VERSION 5.8 ;
BUSBITCHARS "[]" ;
DIVIDERCHAR "/" ;
UNITS
    DATABASE MICRONS 1000 ;
END UNITS

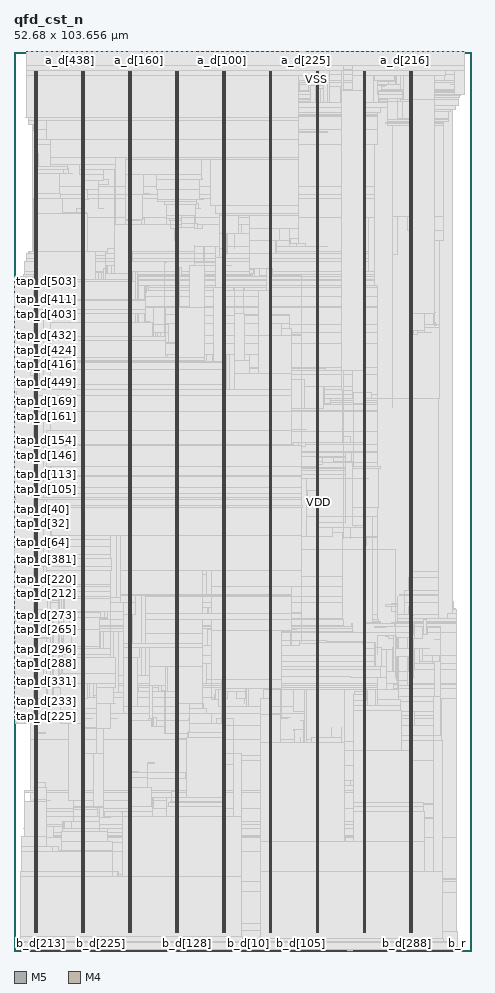
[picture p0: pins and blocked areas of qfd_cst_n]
MACRO qfd_cst_n
  FOREIGN qfd_cst_n 0 0 ;
  CLASS BLOCK ;
  SIZE 52.68 BY 103.656 ;
  PIN a_d[0]
    DIRECTION OUTPUT ;
    USE SIGNAL ;
    PORT
      LAYER M5 ;
        RECT  20.496 103.572 20.52 103.656 ;
    END
  END a_d[0]
  PIN a_d[100]
    DIRECTION OUTPUT ;
    USE SIGNAL ;
    PORT
      LAYER M5 ;
        RECT  23.952 103.572 23.976 103.656 ;
    END
  END a_d[100]
  PIN a_d[101]
    DIRECTION OUTPUT ;
    USE SIGNAL ;
    PORT
      LAYER M5 ;
        RECT  24.048 103.572 24.072 103.656 ;
    END
  END a_d[101]
  PIN a_d[102]
    DIRECTION OUTPUT ;
    USE SIGNAL ;
    PORT
      LAYER M5 ;
        RECT  24.144 103.572 24.168 103.656 ;
    END
  END a_d[102]
  PIN a_d[103]
    DIRECTION OUTPUT ;
    USE SIGNAL ;
    PORT
      LAYER M5 ;
        RECT  24.24 103.572 24.264 103.656 ;
    END
  END a_d[103]
  PIN a_d[104]
    DIRECTION OUTPUT ;
    USE SIGNAL ;
    PORT
      LAYER M5 ;
        RECT  24.336 103.572 24.36 103.656 ;
    END
  END a_d[104]
  PIN a_d[105]
    DIRECTION OUTPUT ;
    USE SIGNAL ;
    PORT
      LAYER M5 ;
        RECT  24.432 103.572 24.456 103.656 ;
    END
  END a_d[105]
  PIN a_d[106]
    DIRECTION OUTPUT ;
    USE SIGNAL ;
    PORT
      LAYER M5 ;
        RECT  24.528 103.572 24.552 103.656 ;
    END
  END a_d[106]
  PIN a_d[107]
    DIRECTION OUTPUT ;
    USE SIGNAL ;
    PORT
      LAYER M5 ;
        RECT  24.624 103.572 24.648 103.656 ;
    END
  END a_d[107]
  PIN a_d[108]
    DIRECTION OUTPUT ;
    USE SIGNAL ;
    PORT
      LAYER M5 ;
        RECT  24.72 103.572 24.744 103.656 ;
    END
  END a_d[108]
  PIN a_d[109]
    DIRECTION OUTPUT ;
    USE SIGNAL ;
    PORT
      LAYER M5 ;
        RECT  24.816 103.572 24.84 103.656 ;
    END
  END a_d[109]
  PIN a_d[10]
    DIRECTION OUTPUT ;
    USE SIGNAL ;
    PORT
      LAYER M5 ;
        RECT  21.456 103.572 21.48 103.656 ;
    END
  END a_d[10]
  PIN a_d[110]
    DIRECTION OUTPUT ;
    USE SIGNAL ;
    PORT
      LAYER M5 ;
        RECT  24.912 103.572 24.936 103.656 ;
    END
  END a_d[110]
  PIN a_d[111]
    DIRECTION OUTPUT ;
    USE SIGNAL ;
    PORT
      LAYER M5 ;
        RECT  25.008 103.572 25.032 103.656 ;
    END
  END a_d[111]
  PIN a_d[112]
    DIRECTION OUTPUT ;
    USE SIGNAL ;
    PORT
      LAYER M5 ;
        RECT  25.104 103.572 25.128 103.656 ;
    END
  END a_d[112]
  PIN a_d[113]
    DIRECTION OUTPUT ;
    USE SIGNAL ;
    PORT
      LAYER M5 ;
        RECT  25.2 103.572 25.224 103.656 ;
    END
  END a_d[113]
  PIN a_d[114]
    DIRECTION OUTPUT ;
    USE SIGNAL ;
    PORT
      LAYER M5 ;
        RECT  25.296 103.572 25.32 103.656 ;
    END
  END a_d[114]
  PIN a_d[115]
    DIRECTION OUTPUT ;
    USE SIGNAL ;
    PORT
      LAYER M5 ;
        RECT  25.392 103.572 25.416 103.656 ;
    END
  END a_d[115]
  PIN a_d[116]
    DIRECTION OUTPUT ;
    USE SIGNAL ;
    PORT
      LAYER M5 ;
        RECT  25.488 103.572 25.512 103.656 ;
    END
  END a_d[116]
  PIN a_d[117]
    DIRECTION OUTPUT ;
    USE SIGNAL ;
    PORT
      LAYER M5 ;
        RECT  25.584 103.572 25.608 103.656 ;
    END
  END a_d[117]
  PIN a_d[118]
    DIRECTION OUTPUT ;
    USE SIGNAL ;
    PORT
      LAYER M5 ;
        RECT  25.68 103.572 25.704 103.656 ;
    END
  END a_d[118]
  PIN a_d[119]
    DIRECTION OUTPUT ;
    USE SIGNAL ;
    PORT
      LAYER M5 ;
        RECT  25.776 103.572 25.8 103.656 ;
    END
  END a_d[119]
  PIN a_d[11]
    DIRECTION OUTPUT ;
    USE SIGNAL ;
    PORT
      LAYER M5 ;
        RECT  21.552 103.572 21.576 103.656 ;
    END
  END a_d[11]
  PIN a_d[120]
    DIRECTION OUTPUT ;
    USE SIGNAL ;
    PORT
      LAYER M5 ;
        RECT  25.872 103.572 25.896 103.656 ;
    END
  END a_d[120]
  PIN a_d[121]
    DIRECTION OUTPUT ;
    USE SIGNAL ;
    PORT
      LAYER M5 ;
        RECT  25.968 103.572 25.992 103.656 ;
    END
  END a_d[121]
  PIN a_d[122]
    DIRECTION OUTPUT ;
    USE SIGNAL ;
    PORT
      LAYER M5 ;
        RECT  26.064 103.572 26.088 103.656 ;
    END
  END a_d[122]
  PIN a_d[123]
    DIRECTION OUTPUT ;
    USE SIGNAL ;
    PORT
      LAYER M5 ;
        RECT  26.16 103.572 26.184 103.656 ;
    END
  END a_d[123]
  PIN a_d[124]
    DIRECTION OUTPUT ;
    USE SIGNAL ;
    PORT
      LAYER M5 ;
        RECT  26.256 103.572 26.28 103.656 ;
    END
  END a_d[124]
  PIN a_d[125]
    DIRECTION OUTPUT ;
    USE SIGNAL ;
    PORT
      LAYER M5 ;
        RECT  26.352 103.572 26.376 103.656 ;
    END
  END a_d[125]
  PIN a_d[126]
    DIRECTION OUTPUT ;
    USE SIGNAL ;
    PORT
      LAYER M5 ;
        RECT  26.448 103.572 26.472 103.656 ;
    END
  END a_d[126]
  PIN a_d[127]
    DIRECTION OUTPUT ;
    USE SIGNAL ;
    PORT
      LAYER M5 ;
        RECT  26.544 103.572 26.568 103.656 ;
    END
  END a_d[127]
  PIN a_d[128]
    DIRECTION OUTPUT ;
    USE SIGNAL ;
    PORT
      LAYER M5 ;
        RECT  17.424 103.572 17.448 103.656 ;
    END
  END a_d[128]
  PIN a_d[129]
    DIRECTION OUTPUT ;
    USE SIGNAL ;
    PORT
      LAYER M5 ;
        RECT  17.52 103.572 17.544 103.656 ;
    END
  END a_d[129]
  PIN a_d[12]
    DIRECTION OUTPUT ;
    USE SIGNAL ;
    PORT
      LAYER M5 ;
        RECT  21.648 103.572 21.672 103.656 ;
    END
  END a_d[12]
  PIN a_d[130]
    DIRECTION OUTPUT ;
    USE SIGNAL ;
    PORT
      LAYER M5 ;
        RECT  17.616 103.572 17.64 103.656 ;
    END
  END a_d[130]
  PIN a_d[131]
    DIRECTION OUTPUT ;
    USE SIGNAL ;
    PORT
      LAYER M5 ;
        RECT  17.712 103.572 17.736 103.656 ;
    END
  END a_d[131]
  PIN a_d[132]
    DIRECTION OUTPUT ;
    USE SIGNAL ;
    PORT
      LAYER M5 ;
        RECT  17.808 103.572 17.832 103.656 ;
    END
  END a_d[132]
  PIN a_d[133]
    DIRECTION OUTPUT ;
    USE SIGNAL ;
    PORT
      LAYER M5 ;
        RECT  17.904 103.572 17.928 103.656 ;
    END
  END a_d[133]
  PIN a_d[134]
    DIRECTION OUTPUT ;
    USE SIGNAL ;
    PORT
      LAYER M5 ;
        RECT  18 103.572 18.024 103.656 ;
    END
  END a_d[134]
  PIN a_d[135]
    DIRECTION OUTPUT ;
    USE SIGNAL ;
    PORT
      LAYER M5 ;
        RECT  18.096 103.572 18.12 103.656 ;
    END
  END a_d[135]
  PIN a_d[136]
    DIRECTION OUTPUT ;
    USE SIGNAL ;
    PORT
      LAYER M5 ;
        RECT  18.192 103.572 18.216 103.656 ;
    END
  END a_d[136]
  PIN a_d[137]
    DIRECTION OUTPUT ;
    USE SIGNAL ;
    PORT
      LAYER M5 ;
        RECT  18.288 103.572 18.312 103.656 ;
    END
  END a_d[137]
  PIN a_d[138]
    DIRECTION OUTPUT ;
    USE SIGNAL ;
    PORT
      LAYER M5 ;
        RECT  18.384 103.572 18.408 103.656 ;
    END
  END a_d[138]
  PIN a_d[139]
    DIRECTION OUTPUT ;
    USE SIGNAL ;
    PORT
      LAYER M5 ;
        RECT  18.48 103.572 18.504 103.656 ;
    END
  END a_d[139]
  PIN a_d[13]
    DIRECTION OUTPUT ;
    USE SIGNAL ;
    PORT
      LAYER M5 ;
        RECT  21.744 103.572 21.768 103.656 ;
    END
  END a_d[13]
  PIN a_d[140]
    DIRECTION OUTPUT ;
    USE SIGNAL ;
    PORT
      LAYER M5 ;
        RECT  18.576 103.572 18.6 103.656 ;
    END
  END a_d[140]
  PIN a_d[141]
    DIRECTION OUTPUT ;
    USE SIGNAL ;
    PORT
      LAYER M5 ;
        RECT  18.672 103.572 18.696 103.656 ;
    END
  END a_d[141]
  PIN a_d[142]
    DIRECTION OUTPUT ;
    USE SIGNAL ;
    PORT
      LAYER M5 ;
        RECT  18.768 103.572 18.792 103.656 ;
    END
  END a_d[142]
  PIN a_d[143]
    DIRECTION OUTPUT ;
    USE SIGNAL ;
    PORT
      LAYER M5 ;
        RECT  18.864 103.572 18.888 103.656 ;
    END
  END a_d[143]
  PIN a_d[144]
    DIRECTION OUTPUT ;
    USE SIGNAL ;
    PORT
      LAYER M5 ;
        RECT  18.96 103.572 18.984 103.656 ;
    END
  END a_d[144]
  PIN a_d[145]
    DIRECTION OUTPUT ;
    USE SIGNAL ;
    PORT
      LAYER M5 ;
        RECT  19.056 103.572 19.08 103.656 ;
    END
  END a_d[145]
  PIN a_d[146]
    DIRECTION OUTPUT ;
    USE SIGNAL ;
    PORT
      LAYER M5 ;
        RECT  19.152 103.572 19.176 103.656 ;
    END
  END a_d[146]
  PIN a_d[147]
    DIRECTION OUTPUT ;
    USE SIGNAL ;
    PORT
      LAYER M5 ;
        RECT  19.248 103.572 19.272 103.656 ;
    END
  END a_d[147]
  PIN a_d[148]
    DIRECTION OUTPUT ;
    USE SIGNAL ;
    PORT
      LAYER M5 ;
        RECT  19.344 103.572 19.368 103.656 ;
    END
  END a_d[148]
  PIN a_d[149]
    DIRECTION OUTPUT ;
    USE SIGNAL ;
    PORT
      LAYER M5 ;
        RECT  19.44 103.572 19.464 103.656 ;
    END
  END a_d[149]
  PIN a_d[14]
    DIRECTION OUTPUT ;
    USE SIGNAL ;
    PORT
      LAYER M5 ;
        RECT  21.84 103.572 21.864 103.656 ;
    END
  END a_d[14]
  PIN a_d[150]
    DIRECTION OUTPUT ;
    USE SIGNAL ;
    PORT
      LAYER M5 ;
        RECT  19.536 103.572 19.56 103.656 ;
    END
  END a_d[150]
  PIN a_d[151]
    DIRECTION OUTPUT ;
    USE SIGNAL ;
    PORT
      LAYER M5 ;
        RECT  19.632 103.572 19.656 103.656 ;
    END
  END a_d[151]
  PIN a_d[152]
    DIRECTION OUTPUT ;
    USE SIGNAL ;
    PORT
      LAYER M5 ;
        RECT  19.728 103.572 19.752 103.656 ;
    END
  END a_d[152]
  PIN a_d[153]
    DIRECTION OUTPUT ;
    USE SIGNAL ;
    PORT
      LAYER M5 ;
        RECT  19.824 103.572 19.848 103.656 ;
    END
  END a_d[153]
  PIN a_d[154]
    DIRECTION OUTPUT ;
    USE SIGNAL ;
    PORT
      LAYER M5 ;
        RECT  19.92 103.572 19.944 103.656 ;
    END
  END a_d[154]
  PIN a_d[155]
    DIRECTION OUTPUT ;
    USE SIGNAL ;
    PORT
      LAYER M5 ;
        RECT  20.016 103.572 20.04 103.656 ;
    END
  END a_d[155]
  PIN a_d[156]
    DIRECTION OUTPUT ;
    USE SIGNAL ;
    PORT
      LAYER M5 ;
        RECT  20.112 103.572 20.136 103.656 ;
    END
  END a_d[156]
  PIN a_d[157]
    DIRECTION OUTPUT ;
    USE SIGNAL ;
    PORT
      LAYER M5 ;
        RECT  20.208 103.572 20.232 103.656 ;
    END
  END a_d[157]
  PIN a_d[158]
    DIRECTION OUTPUT ;
    USE SIGNAL ;
    PORT
      LAYER M5 ;
        RECT  20.304 103.572 20.328 103.656 ;
    END
  END a_d[158]
  PIN a_d[159]
    DIRECTION OUTPUT ;
    USE SIGNAL ;
    PORT
      LAYER M5 ;
        RECT  20.4 103.572 20.424 103.656 ;
    END
  END a_d[159]
  PIN a_d[15]
    DIRECTION OUTPUT ;
    USE SIGNAL ;
    PORT
      LAYER M5 ;
        RECT  21.936 103.572 21.96 103.656 ;
    END
  END a_d[15]
  PIN a_d[160]
    DIRECTION OUTPUT ;
    USE SIGNAL ;
    PORT
      LAYER M5 ;
        RECT  14.352 103.572 14.376 103.656 ;
    END
  END a_d[160]
  PIN a_d[161]
    DIRECTION OUTPUT ;
    USE SIGNAL ;
    PORT
      LAYER M5 ;
        RECT  14.448 103.572 14.472 103.656 ;
    END
  END a_d[161]
  PIN a_d[162]
    DIRECTION OUTPUT ;
    USE SIGNAL ;
    PORT
      LAYER M5 ;
        RECT  14.544 103.572 14.568 103.656 ;
    END
  END a_d[162]
  PIN a_d[163]
    DIRECTION OUTPUT ;
    USE SIGNAL ;
    PORT
      LAYER M5 ;
        RECT  14.64 103.572 14.664 103.656 ;
    END
  END a_d[163]
  PIN a_d[164]
    DIRECTION OUTPUT ;
    USE SIGNAL ;
    PORT
      LAYER M5 ;
        RECT  14.736 103.572 14.76 103.656 ;
    END
  END a_d[164]
  PIN a_d[165]
    DIRECTION OUTPUT ;
    USE SIGNAL ;
    PORT
      LAYER M5 ;
        RECT  14.832 103.572 14.856 103.656 ;
    END
  END a_d[165]
  PIN a_d[166]
    DIRECTION OUTPUT ;
    USE SIGNAL ;
    PORT
      LAYER M5 ;
        RECT  14.928 103.572 14.952 103.656 ;
    END
  END a_d[166]
  PIN a_d[167]
    DIRECTION OUTPUT ;
    USE SIGNAL ;
    PORT
      LAYER M5 ;
        RECT  15.024 103.572 15.048 103.656 ;
    END
  END a_d[167]
  PIN a_d[168]
    DIRECTION OUTPUT ;
    USE SIGNAL ;
    PORT
      LAYER M5 ;
        RECT  15.12 103.572 15.144 103.656 ;
    END
  END a_d[168]
  PIN a_d[169]
    DIRECTION OUTPUT ;
    USE SIGNAL ;
    PORT
      LAYER M5 ;
        RECT  15.216 103.572 15.24 103.656 ;
    END
  END a_d[169]
  PIN a_d[16]
    DIRECTION OUTPUT ;
    USE SIGNAL ;
    PORT
      LAYER M5 ;
        RECT  22.032 103.572 22.056 103.656 ;
    END
  END a_d[16]
  PIN a_d[170]
    DIRECTION OUTPUT ;
    USE SIGNAL ;
    PORT
      LAYER M5 ;
        RECT  15.312 103.572 15.336 103.656 ;
    END
  END a_d[170]
  PIN a_d[171]
    DIRECTION OUTPUT ;
    USE SIGNAL ;
    PORT
      LAYER M5 ;
        RECT  15.408 103.572 15.432 103.656 ;
    END
  END a_d[171]
  PIN a_d[172]
    DIRECTION OUTPUT ;
    USE SIGNAL ;
    PORT
      LAYER M5 ;
        RECT  15.504 103.572 15.528 103.656 ;
    END
  END a_d[172]
  PIN a_d[173]
    DIRECTION OUTPUT ;
    USE SIGNAL ;
    PORT
      LAYER M5 ;
        RECT  15.6 103.572 15.624 103.656 ;
    END
  END a_d[173]
  PIN a_d[174]
    DIRECTION OUTPUT ;
    USE SIGNAL ;
    PORT
      LAYER M5 ;
        RECT  15.696 103.572 15.72 103.656 ;
    END
  END a_d[174]
  PIN a_d[175]
    DIRECTION OUTPUT ;
    USE SIGNAL ;
    PORT
      LAYER M5 ;
        RECT  15.792 103.572 15.816 103.656 ;
    END
  END a_d[175]
  PIN a_d[176]
    DIRECTION OUTPUT ;
    USE SIGNAL ;
    PORT
      LAYER M5 ;
        RECT  15.888 103.572 15.912 103.656 ;
    END
  END a_d[176]
  PIN a_d[177]
    DIRECTION OUTPUT ;
    USE SIGNAL ;
    PORT
      LAYER M5 ;
        RECT  15.984 103.572 16.008 103.656 ;
    END
  END a_d[177]
  PIN a_d[178]
    DIRECTION OUTPUT ;
    USE SIGNAL ;
    PORT
      LAYER M5 ;
        RECT  16.08 103.572 16.104 103.656 ;
    END
  END a_d[178]
  PIN a_d[179]
    DIRECTION OUTPUT ;
    USE SIGNAL ;
    PORT
      LAYER M5 ;
        RECT  16.176 103.572 16.2 103.656 ;
    END
  END a_d[179]
  PIN a_d[17]
    DIRECTION OUTPUT ;
    USE SIGNAL ;
    PORT
      LAYER M5 ;
        RECT  22.128 103.572 22.152 103.656 ;
    END
  END a_d[17]
  PIN a_d[180]
    DIRECTION OUTPUT ;
    USE SIGNAL ;
    PORT
      LAYER M5 ;
        RECT  16.272 103.572 16.296 103.656 ;
    END
  END a_d[180]
  PIN a_d[181]
    DIRECTION OUTPUT ;
    USE SIGNAL ;
    PORT
      LAYER M5 ;
        RECT  16.368 103.572 16.392 103.656 ;
    END
  END a_d[181]
  PIN a_d[182]
    DIRECTION OUTPUT ;
    USE SIGNAL ;
    PORT
      LAYER M5 ;
        RECT  16.464 103.572 16.488 103.656 ;
    END
  END a_d[182]
  PIN a_d[183]
    DIRECTION OUTPUT ;
    USE SIGNAL ;
    PORT
      LAYER M5 ;
        RECT  16.56 103.572 16.584 103.656 ;
    END
  END a_d[183]
  PIN a_d[184]
    DIRECTION OUTPUT ;
    USE SIGNAL ;
    PORT
      LAYER M5 ;
        RECT  16.656 103.572 16.68 103.656 ;
    END
  END a_d[184]
  PIN a_d[185]
    DIRECTION OUTPUT ;
    USE SIGNAL ;
    PORT
      LAYER M5 ;
        RECT  16.752 103.572 16.776 103.656 ;
    END
  END a_d[185]
  PIN a_d[186]
    DIRECTION OUTPUT ;
    USE SIGNAL ;
    PORT
      LAYER M5 ;
        RECT  16.848 103.572 16.872 103.656 ;
    END
  END a_d[186]
  PIN a_d[187]
    DIRECTION OUTPUT ;
    USE SIGNAL ;
    PORT
      LAYER M5 ;
        RECT  16.944 103.572 16.968 103.656 ;
    END
  END a_d[187]
  PIN a_d[188]
    DIRECTION OUTPUT ;
    USE SIGNAL ;
    PORT
      LAYER M5 ;
        RECT  17.04 103.572 17.064 103.656 ;
    END
  END a_d[188]
  PIN a_d[189]
    DIRECTION OUTPUT ;
    USE SIGNAL ;
    PORT
      LAYER M5 ;
        RECT  17.136 103.572 17.16 103.656 ;
    END
  END a_d[189]
  PIN a_d[18]
    DIRECTION OUTPUT ;
    USE SIGNAL ;
    PORT
      LAYER M5 ;
        RECT  22.224 103.572 22.248 103.656 ;
    END
  END a_d[18]
  PIN a_d[190]
    DIRECTION OUTPUT ;
    USE SIGNAL ;
    PORT
      LAYER M5 ;
        RECT  17.232 103.572 17.256 103.656 ;
    END
  END a_d[190]
  PIN a_d[191]
    DIRECTION OUTPUT ;
    USE SIGNAL ;
    PORT
      LAYER M5 ;
        RECT  17.328 103.572 17.352 103.656 ;
    END
  END a_d[191]
  PIN a_d[192]
    DIRECTION OUTPUT ;
    USE SIGNAL ;
    PORT
      LAYER M5 ;
        RECT  42.768 103.572 42.792 103.656 ;
    END
  END a_d[192]
  PIN a_d[193]
    DIRECTION OUTPUT ;
    USE SIGNAL ;
    PORT
      LAYER M5 ;
        RECT  42.864 103.572 42.888 103.656 ;
    END
  END a_d[193]
  PIN a_d[194]
    DIRECTION OUTPUT ;
    USE SIGNAL ;
    PORT
      LAYER M5 ;
        RECT  42.96 103.572 42.984 103.656 ;
    END
  END a_d[194]
  PIN a_d[195]
    DIRECTION OUTPUT ;
    USE SIGNAL ;
    PORT
      LAYER M5 ;
        RECT  43.056 103.572 43.08 103.656 ;
    END
  END a_d[195]
  PIN a_d[196]
    DIRECTION OUTPUT ;
    USE SIGNAL ;
    PORT
      LAYER M5 ;
        RECT  43.152 103.572 43.176 103.656 ;
    END
  END a_d[196]
  PIN a_d[197]
    DIRECTION OUTPUT ;
    USE SIGNAL ;
    PORT
      LAYER M5 ;
        RECT  43.248 103.572 43.272 103.656 ;
    END
  END a_d[197]
  PIN a_d[198]
    DIRECTION OUTPUT ;
    USE SIGNAL ;
    PORT
      LAYER M5 ;
        RECT  43.344 103.572 43.368 103.656 ;
    END
  END a_d[198]
  PIN a_d[199]
    DIRECTION OUTPUT ;
    USE SIGNAL ;
    PORT
      LAYER M5 ;
        RECT  43.44 103.572 43.464 103.656 ;
    END
  END a_d[199]
  PIN a_d[19]
    DIRECTION OUTPUT ;
    USE SIGNAL ;
    PORT
      LAYER M5 ;
        RECT  22.32 103.572 22.344 103.656 ;
    END
  END a_d[19]
  PIN a_d[1]
    DIRECTION OUTPUT ;
    USE SIGNAL ;
    PORT
      LAYER M5 ;
        RECT  20.592 103.572 20.616 103.656 ;
    END
  END a_d[1]
  PIN a_d[200]
    DIRECTION OUTPUT ;
    USE SIGNAL ;
    PORT
      LAYER M5 ;
        RECT  43.536 103.572 43.56 103.656 ;
    END
  END a_d[200]
  PIN a_d[201]
    DIRECTION OUTPUT ;
    USE SIGNAL ;
    PORT
      LAYER M5 ;
        RECT  43.632 103.572 43.656 103.656 ;
    END
  END a_d[201]
  PIN a_d[202]
    DIRECTION OUTPUT ;
    USE SIGNAL ;
    PORT
      LAYER M5 ;
        RECT  43.728 103.572 43.752 103.656 ;
    END
  END a_d[202]
  PIN a_d[203]
    DIRECTION OUTPUT ;
    USE SIGNAL ;
    PORT
      LAYER M5 ;
        RECT  43.824 103.572 43.848 103.656 ;
    END
  END a_d[203]
  PIN a_d[204]
    DIRECTION OUTPUT ;
    USE SIGNAL ;
    PORT
      LAYER M5 ;
        RECT  43.92 103.572 43.944 103.656 ;
    END
  END a_d[204]
  PIN a_d[205]
    DIRECTION OUTPUT ;
    USE SIGNAL ;
    PORT
      LAYER M5 ;
        RECT  44.016 103.572 44.04 103.656 ;
    END
  END a_d[205]
  PIN a_d[206]
    DIRECTION OUTPUT ;
    USE SIGNAL ;
    PORT
      LAYER M5 ;
        RECT  44.112 103.572 44.136 103.656 ;
    END
  END a_d[206]
  PIN a_d[207]
    DIRECTION OUTPUT ;
    USE SIGNAL ;
    PORT
      LAYER M5 ;
        RECT  44.208 103.572 44.232 103.656 ;
    END
  END a_d[207]
  PIN a_d[208]
    DIRECTION OUTPUT ;
    USE SIGNAL ;
    PORT
      LAYER M5 ;
        RECT  44.304 103.572 44.328 103.656 ;
    END
  END a_d[208]
  PIN a_d[209]
    DIRECTION OUTPUT ;
    USE SIGNAL ;
    PORT
      LAYER M5 ;
        RECT  44.4 103.572 44.424 103.656 ;
    END
  END a_d[209]
  PIN a_d[20]
    DIRECTION OUTPUT ;
    USE SIGNAL ;
    PORT
      LAYER M5 ;
        RECT  22.416 103.572 22.44 103.656 ;
    END
  END a_d[20]
  PIN a_d[210]
    DIRECTION OUTPUT ;
    USE SIGNAL ;
    PORT
      LAYER M5 ;
        RECT  44.496 103.572 44.52 103.656 ;
    END
  END a_d[210]
  PIN a_d[211]
    DIRECTION OUTPUT ;
    USE SIGNAL ;
    PORT
      LAYER M5 ;
        RECT  44.592 103.572 44.616 103.656 ;
    END
  END a_d[211]
  PIN a_d[212]
    DIRECTION OUTPUT ;
    USE SIGNAL ;
    PORT
      LAYER M5 ;
        RECT  44.688 103.572 44.712 103.656 ;
    END
  END a_d[212]
  PIN a_d[213]
    DIRECTION OUTPUT ;
    USE SIGNAL ;
    PORT
      LAYER M5 ;
        RECT  44.784 103.572 44.808 103.656 ;
    END
  END a_d[213]
  PIN a_d[214]
    DIRECTION OUTPUT ;
    USE SIGNAL ;
    PORT
      LAYER M5 ;
        RECT  44.88 103.572 44.904 103.656 ;
    END
  END a_d[214]
  PIN a_d[215]
    DIRECTION OUTPUT ;
    USE SIGNAL ;
    PORT
      LAYER M5 ;
        RECT  44.976 103.572 45 103.656 ;
    END
  END a_d[215]
  PIN a_d[216]
    DIRECTION OUTPUT ;
    USE SIGNAL ;
    PORT
      LAYER M5 ;
        RECT  45.072 103.572 45.096 103.656 ;
    END
  END a_d[216]
  PIN a_d[217]
    DIRECTION OUTPUT ;
    USE SIGNAL ;
    PORT
      LAYER M5 ;
        RECT  45.168 103.572 45.192 103.656 ;
    END
  END a_d[217]
  PIN a_d[218]
    DIRECTION OUTPUT ;
    USE SIGNAL ;
    PORT
      LAYER M5 ;
        RECT  45.264 103.572 45.288 103.656 ;
    END
  END a_d[218]
  PIN a_d[219]
    DIRECTION OUTPUT ;
    USE SIGNAL ;
    PORT
      LAYER M5 ;
        RECT  45.36 103.572 45.384 103.656 ;
    END
  END a_d[219]
  PIN a_d[21]
    DIRECTION OUTPUT ;
    USE SIGNAL ;
    PORT
      LAYER M5 ;
        RECT  22.512 103.572 22.536 103.656 ;
    END
  END a_d[21]
  PIN a_d[220]
    DIRECTION OUTPUT ;
    USE SIGNAL ;
    PORT
      LAYER M5 ;
        RECT  45.456 103.572 45.48 103.656 ;
    END
  END a_d[220]
  PIN a_d[221]
    DIRECTION OUTPUT ;
    USE SIGNAL ;
    PORT
      LAYER M5 ;
        RECT  45.552 103.572 45.576 103.656 ;
    END
  END a_d[221]
  PIN a_d[222]
    DIRECTION OUTPUT ;
    USE SIGNAL ;
    PORT
      LAYER M5 ;
        RECT  45.648 103.572 45.672 103.656 ;
    END
  END a_d[222]
  PIN a_d[223]
    DIRECTION OUTPUT ;
    USE SIGNAL ;
    PORT
      LAYER M5 ;
        RECT  45.744 103.572 45.768 103.656 ;
    END
  END a_d[223]
  PIN a_d[224]
    DIRECTION OUTPUT ;
    USE SIGNAL ;
    PORT
      LAYER M5 ;
        RECT  33.552 103.572 33.576 103.656 ;
    END
  END a_d[224]
  PIN a_d[225]
    DIRECTION OUTPUT ;
    USE SIGNAL ;
    PORT
      LAYER M5 ;
        RECT  33.648 103.572 33.672 103.656 ;
    END
  END a_d[225]
  PIN a_d[226]
    DIRECTION OUTPUT ;
    USE SIGNAL ;
    PORT
      LAYER M5 ;
        RECT  33.744 103.572 33.768 103.656 ;
    END
  END a_d[226]
  PIN a_d[227]
    DIRECTION OUTPUT ;
    USE SIGNAL ;
    PORT
      LAYER M5 ;
        RECT  33.84 103.572 33.864 103.656 ;
    END
  END a_d[227]
  PIN a_d[228]
    DIRECTION OUTPUT ;
    USE SIGNAL ;
    PORT
      LAYER M5 ;
        RECT  33.936 103.572 33.96 103.656 ;
    END
  END a_d[228]
  PIN a_d[229]
    DIRECTION OUTPUT ;
    USE SIGNAL ;
    PORT
      LAYER M5 ;
        RECT  34.032 103.572 34.056 103.656 ;
    END
  END a_d[229]
  PIN a_d[22]
    DIRECTION OUTPUT ;
    USE SIGNAL ;
    PORT
      LAYER M5 ;
        RECT  22.608 103.572 22.632 103.656 ;
    END
  END a_d[22]
  PIN a_d[230]
    DIRECTION OUTPUT ;
    USE SIGNAL ;
    PORT
      LAYER M5 ;
        RECT  34.128 103.572 34.152 103.656 ;
    END
  END a_d[230]
  PIN a_d[231]
    DIRECTION OUTPUT ;
    USE SIGNAL ;
    PORT
      LAYER M5 ;
        RECT  34.224 103.572 34.248 103.656 ;
    END
  END a_d[231]
  PIN a_d[232]
    DIRECTION OUTPUT ;
    USE SIGNAL ;
    PORT
      LAYER M5 ;
        RECT  34.32 103.572 34.344 103.656 ;
    END
  END a_d[232]
  PIN a_d[233]
    DIRECTION OUTPUT ;
    USE SIGNAL ;
    PORT
      LAYER M5 ;
        RECT  34.416 103.572 34.44 103.656 ;
    END
  END a_d[233]
  PIN a_d[234]
    DIRECTION OUTPUT ;
    USE SIGNAL ;
    PORT
      LAYER M5 ;
        RECT  34.512 103.572 34.536 103.656 ;
    END
  END a_d[234]
  PIN a_d[235]
    DIRECTION OUTPUT ;
    USE SIGNAL ;
    PORT
      LAYER M5 ;
        RECT  34.608 103.572 34.632 103.656 ;
    END
  END a_d[235]
  PIN a_d[236]
    DIRECTION OUTPUT ;
    USE SIGNAL ;
    PORT
      LAYER M5 ;
        RECT  34.704 103.572 34.728 103.656 ;
    END
  END a_d[236]
  PIN a_d[237]
    DIRECTION OUTPUT ;
    USE SIGNAL ;
    PORT
      LAYER M5 ;
        RECT  34.8 103.572 34.824 103.656 ;
    END
  END a_d[237]
  PIN a_d[238]
    DIRECTION OUTPUT ;
    USE SIGNAL ;
    PORT
      LAYER M5 ;
        RECT  34.896 103.572 34.92 103.656 ;
    END
  END a_d[238]
  PIN a_d[239]
    DIRECTION OUTPUT ;
    USE SIGNAL ;
    PORT
      LAYER M5 ;
        RECT  34.992 103.572 35.016 103.656 ;
    END
  END a_d[239]
  PIN a_d[23]
    DIRECTION OUTPUT ;
    USE SIGNAL ;
    PORT
      LAYER M5 ;
        RECT  22.704 103.572 22.728 103.656 ;
    END
  END a_d[23]
  PIN a_d[240]
    DIRECTION OUTPUT ;
    USE SIGNAL ;
    PORT
      LAYER M5 ;
        RECT  35.088 103.572 35.112 103.656 ;
    END
  END a_d[240]
  PIN a_d[241]
    DIRECTION OUTPUT ;
    USE SIGNAL ;
    PORT
      LAYER M5 ;
        RECT  35.184 103.572 35.208 103.656 ;
    END
  END a_d[241]
  PIN a_d[242]
    DIRECTION OUTPUT ;
    USE SIGNAL ;
    PORT
      LAYER M5 ;
        RECT  35.28 103.572 35.304 103.656 ;
    END
  END a_d[242]
  PIN a_d[243]
    DIRECTION OUTPUT ;
    USE SIGNAL ;
    PORT
      LAYER M5 ;
        RECT  35.376 103.572 35.4 103.656 ;
    END
  END a_d[243]
  PIN a_d[244]
    DIRECTION OUTPUT ;
    USE SIGNAL ;
    PORT
      LAYER M5 ;
        RECT  35.472 103.572 35.496 103.656 ;
    END
  END a_d[244]
  PIN a_d[245]
    DIRECTION OUTPUT ;
    USE SIGNAL ;
    PORT
      LAYER M5 ;
        RECT  35.568 103.572 35.592 103.656 ;
    END
  END a_d[245]
  PIN a_d[246]
    DIRECTION OUTPUT ;
    USE SIGNAL ;
    PORT
      LAYER M5 ;
        RECT  35.664 103.572 35.688 103.656 ;
    END
  END a_d[246]
  PIN a_d[247]
    DIRECTION OUTPUT ;
    USE SIGNAL ;
    PORT
      LAYER M5 ;
        RECT  35.76 103.572 35.784 103.656 ;
    END
  END a_d[247]
  PIN a_d[248]
    DIRECTION OUTPUT ;
    USE SIGNAL ;
    PORT
      LAYER M5 ;
        RECT  35.856 103.572 35.88 103.656 ;
    END
  END a_d[248]
  PIN a_d[249]
    DIRECTION OUTPUT ;
    USE SIGNAL ;
    PORT
      LAYER M5 ;
        RECT  35.952 103.572 35.976 103.656 ;
    END
  END a_d[249]
  PIN a_d[24]
    DIRECTION OUTPUT ;
    USE SIGNAL ;
    PORT
      LAYER M5 ;
        RECT  22.8 103.572 22.824 103.656 ;
    END
  END a_d[24]
  PIN a_d[250]
    DIRECTION OUTPUT ;
    USE SIGNAL ;
    PORT
      LAYER M5 ;
        RECT  36.048 103.572 36.072 103.656 ;
    END
  END a_d[250]
  PIN a_d[251]
    DIRECTION OUTPUT ;
    USE SIGNAL ;
    PORT
      LAYER M5 ;
        RECT  36.144 103.572 36.168 103.656 ;
    END
  END a_d[251]
  PIN a_d[252]
    DIRECTION OUTPUT ;
    USE SIGNAL ;
    PORT
      LAYER M5 ;
        RECT  36.24 103.572 36.264 103.656 ;
    END
  END a_d[252]
  PIN a_d[253]
    DIRECTION OUTPUT ;
    USE SIGNAL ;
    PORT
      LAYER M5 ;
        RECT  36.336 103.572 36.36 103.656 ;
    END
  END a_d[253]
  PIN a_d[254]
    DIRECTION OUTPUT ;
    USE SIGNAL ;
    PORT
      LAYER M5 ;
        RECT  36.432 103.572 36.456 103.656 ;
    END
  END a_d[254]
  PIN a_d[255]
    DIRECTION OUTPUT ;
    USE SIGNAL ;
    PORT
      LAYER M5 ;
        RECT  36.528 103.572 36.552 103.656 ;
    END
  END a_d[255]
  PIN a_d[256]
    DIRECTION OUTPUT ;
    USE SIGNAL ;
    PORT
      LAYER M5 ;
        RECT  36.624 103.572 36.648 103.656 ;
    END
  END a_d[256]
  PIN a_d[257]
    DIRECTION OUTPUT ;
    USE SIGNAL ;
    PORT
      LAYER M5 ;
        RECT  36.72 103.572 36.744 103.656 ;
    END
  END a_d[257]
  PIN a_d[258]
    DIRECTION OUTPUT ;
    USE SIGNAL ;
    PORT
      LAYER M5 ;
        RECT  36.816 103.572 36.84 103.656 ;
    END
  END a_d[258]
  PIN a_d[259]
    DIRECTION OUTPUT ;
    USE SIGNAL ;
    PORT
      LAYER M5 ;
        RECT  36.912 103.572 36.936 103.656 ;
    END
  END a_d[259]
  PIN a_d[25]
    DIRECTION OUTPUT ;
    USE SIGNAL ;
    PORT
      LAYER M5 ;
        RECT  22.896 103.572 22.92 103.656 ;
    END
  END a_d[25]
  PIN a_d[260]
    DIRECTION OUTPUT ;
    USE SIGNAL ;
    PORT
      LAYER M5 ;
        RECT  37.008 103.572 37.032 103.656 ;
    END
  END a_d[260]
  PIN a_d[261]
    DIRECTION OUTPUT ;
    USE SIGNAL ;
    PORT
      LAYER M5 ;
        RECT  37.104 103.572 37.128 103.656 ;
    END
  END a_d[261]
  PIN a_d[262]
    DIRECTION OUTPUT ;
    USE SIGNAL ;
    PORT
      LAYER M5 ;
        RECT  37.2 103.572 37.224 103.656 ;
    END
  END a_d[262]
  PIN a_d[263]
    DIRECTION OUTPUT ;
    USE SIGNAL ;
    PORT
      LAYER M5 ;
        RECT  37.296 103.572 37.32 103.656 ;
    END
  END a_d[263]
  PIN a_d[264]
    DIRECTION OUTPUT ;
    USE SIGNAL ;
    PORT
      LAYER M5 ;
        RECT  37.392 103.572 37.416 103.656 ;
    END
  END a_d[264]
  PIN a_d[265]
    DIRECTION OUTPUT ;
    USE SIGNAL ;
    PORT
      LAYER M5 ;
        RECT  37.488 103.572 37.512 103.656 ;
    END
  END a_d[265]
  PIN a_d[266]
    DIRECTION OUTPUT ;
    USE SIGNAL ;
    PORT
      LAYER M5 ;
        RECT  37.584 103.572 37.608 103.656 ;
    END
  END a_d[266]
  PIN a_d[267]
    DIRECTION OUTPUT ;
    USE SIGNAL ;
    PORT
      LAYER M5 ;
        RECT  37.68 103.572 37.704 103.656 ;
    END
  END a_d[267]
  PIN a_d[268]
    DIRECTION OUTPUT ;
    USE SIGNAL ;
    PORT
      LAYER M5 ;
        RECT  37.776 103.572 37.8 103.656 ;
    END
  END a_d[268]
  PIN a_d[269]
    DIRECTION OUTPUT ;
    USE SIGNAL ;
    PORT
      LAYER M5 ;
        RECT  37.872 103.572 37.896 103.656 ;
    END
  END a_d[269]
  PIN a_d[26]
    DIRECTION OUTPUT ;
    USE SIGNAL ;
    PORT
      LAYER M5 ;
        RECT  22.992 103.572 23.016 103.656 ;
    END
  END a_d[26]
  PIN a_d[270]
    DIRECTION OUTPUT ;
    USE SIGNAL ;
    PORT
      LAYER M5 ;
        RECT  37.968 103.572 37.992 103.656 ;
    END
  END a_d[270]
  PIN a_d[271]
    DIRECTION OUTPUT ;
    USE SIGNAL ;
    PORT
      LAYER M5 ;
        RECT  38.064 103.572 38.088 103.656 ;
    END
  END a_d[271]
  PIN a_d[272]
    DIRECTION OUTPUT ;
    USE SIGNAL ;
    PORT
      LAYER M5 ;
        RECT  38.16 103.572 38.184 103.656 ;
    END
  END a_d[272]
  PIN a_d[273]
    DIRECTION OUTPUT ;
    USE SIGNAL ;
    PORT
      LAYER M5 ;
        RECT  38.256 103.572 38.28 103.656 ;
    END
  END a_d[273]
  PIN a_d[274]
    DIRECTION OUTPUT ;
    USE SIGNAL ;
    PORT
      LAYER M5 ;
        RECT  38.352 103.572 38.376 103.656 ;
    END
  END a_d[274]
  PIN a_d[275]
    DIRECTION OUTPUT ;
    USE SIGNAL ;
    PORT
      LAYER M5 ;
        RECT  38.448 103.572 38.472 103.656 ;
    END
  END a_d[275]
  PIN a_d[276]
    DIRECTION OUTPUT ;
    USE SIGNAL ;
    PORT
      LAYER M5 ;
        RECT  38.544 103.572 38.568 103.656 ;
    END
  END a_d[276]
  PIN a_d[277]
    DIRECTION OUTPUT ;
    USE SIGNAL ;
    PORT
      LAYER M5 ;
        RECT  38.64 103.572 38.664 103.656 ;
    END
  END a_d[277]
  PIN a_d[278]
    DIRECTION OUTPUT ;
    USE SIGNAL ;
    PORT
      LAYER M5 ;
        RECT  38.736 103.572 38.76 103.656 ;
    END
  END a_d[278]
  PIN a_d[279]
    DIRECTION OUTPUT ;
    USE SIGNAL ;
    PORT
      LAYER M5 ;
        RECT  38.832 103.572 38.856 103.656 ;
    END
  END a_d[279]
  PIN a_d[27]
    DIRECTION OUTPUT ;
    USE SIGNAL ;
    PORT
      LAYER M5 ;
        RECT  23.088 103.572 23.112 103.656 ;
    END
  END a_d[27]
  PIN a_d[280]
    DIRECTION OUTPUT ;
    USE SIGNAL ;
    PORT
      LAYER M5 ;
        RECT  38.928 103.572 38.952 103.656 ;
    END
  END a_d[280]
  PIN a_d[281]
    DIRECTION OUTPUT ;
    USE SIGNAL ;
    PORT
      LAYER M5 ;
        RECT  39.024 103.572 39.048 103.656 ;
    END
  END a_d[281]
  PIN a_d[282]
    DIRECTION OUTPUT ;
    USE SIGNAL ;
    PORT
      LAYER M5 ;
        RECT  39.12 103.572 39.144 103.656 ;
    END
  END a_d[282]
  PIN a_d[283]
    DIRECTION OUTPUT ;
    USE SIGNAL ;
    PORT
      LAYER M5 ;
        RECT  39.216 103.572 39.24 103.656 ;
    END
  END a_d[283]
  PIN a_d[284]
    DIRECTION OUTPUT ;
    USE SIGNAL ;
    PORT
      LAYER M5 ;
        RECT  39.312 103.572 39.336 103.656 ;
    END
  END a_d[284]
  PIN a_d[285]
    DIRECTION OUTPUT ;
    USE SIGNAL ;
    PORT
      LAYER M5 ;
        RECT  39.408 103.572 39.432 103.656 ;
    END
  END a_d[285]
  PIN a_d[286]
    DIRECTION OUTPUT ;
    USE SIGNAL ;
    PORT
      LAYER M5 ;
        RECT  39.504 103.572 39.528 103.656 ;
    END
  END a_d[286]
  PIN a_d[287]
    DIRECTION OUTPUT ;
    USE SIGNAL ;
    PORT
      LAYER M5 ;
        RECT  39.6 103.572 39.624 103.656 ;
    END
  END a_d[287]
  PIN a_d[288]
    DIRECTION OUTPUT ;
    USE SIGNAL ;
    PORT
      LAYER M5 ;
        RECT  45.84 103.572 45.864 103.656 ;
    END
  END a_d[288]
  PIN a_d[289]
    DIRECTION OUTPUT ;
    USE SIGNAL ;
    PORT
      LAYER M5 ;
        RECT  45.936 103.572 45.96 103.656 ;
    END
  END a_d[289]
  PIN a_d[28]
    DIRECTION OUTPUT ;
    USE SIGNAL ;
    PORT
      LAYER M5 ;
        RECT  23.184 103.572 23.208 103.656 ;
    END
  END a_d[28]
  PIN a_d[290]
    DIRECTION OUTPUT ;
    USE SIGNAL ;
    PORT
      LAYER M5 ;
        RECT  46.032 103.572 46.056 103.656 ;
    END
  END a_d[290]
  PIN a_d[291]
    DIRECTION OUTPUT ;
    USE SIGNAL ;
    PORT
      LAYER M5 ;
        RECT  46.128 103.572 46.152 103.656 ;
    END
  END a_d[291]
  PIN a_d[292]
    DIRECTION OUTPUT ;
    USE SIGNAL ;
    PORT
      LAYER M5 ;
        RECT  46.224 103.572 46.248 103.656 ;
    END
  END a_d[292]
  PIN a_d[293]
    DIRECTION OUTPUT ;
    USE SIGNAL ;
    PORT
      LAYER M5 ;
        RECT  46.32 103.572 46.344 103.656 ;
    END
  END a_d[293]
  PIN a_d[294]
    DIRECTION OUTPUT ;
    USE SIGNAL ;
    PORT
      LAYER M5 ;
        RECT  46.416 103.572 46.44 103.656 ;
    END
  END a_d[294]
  PIN a_d[295]
    DIRECTION OUTPUT ;
    USE SIGNAL ;
    PORT
      LAYER M5 ;
        RECT  46.512 103.572 46.536 103.656 ;
    END
  END a_d[295]
  PIN a_d[296]
    DIRECTION OUTPUT ;
    USE SIGNAL ;
    PORT
      LAYER M5 ;
        RECT  46.608 103.572 46.632 103.656 ;
    END
  END a_d[296]
  PIN a_d[297]
    DIRECTION OUTPUT ;
    USE SIGNAL ;
    PORT
      LAYER M5 ;
        RECT  46.704 103.572 46.728 103.656 ;
    END
  END a_d[297]
  PIN a_d[298]
    DIRECTION OUTPUT ;
    USE SIGNAL ;
    PORT
      LAYER M5 ;
        RECT  46.8 103.572 46.824 103.656 ;
    END
  END a_d[298]
  PIN a_d[299]
    DIRECTION OUTPUT ;
    USE SIGNAL ;
    PORT
      LAYER M5 ;
        RECT  46.896 103.572 46.92 103.656 ;
    END
  END a_d[299]
  PIN a_d[29]
    DIRECTION OUTPUT ;
    USE SIGNAL ;
    PORT
      LAYER M5 ;
        RECT  23.28 103.572 23.304 103.656 ;
    END
  END a_d[29]
  PIN a_d[2]
    DIRECTION OUTPUT ;
    USE SIGNAL ;
    PORT
      LAYER M5 ;
        RECT  20.688 103.572 20.712 103.656 ;
    END
  END a_d[2]
  PIN a_d[300]
    DIRECTION OUTPUT ;
    USE SIGNAL ;
    PORT
      LAYER M5 ;
        RECT  46.992 103.572 47.016 103.656 ;
    END
  END a_d[300]
  PIN a_d[301]
    DIRECTION OUTPUT ;
    USE SIGNAL ;
    PORT
      LAYER M5 ;
        RECT  47.088 103.572 47.112 103.656 ;
    END
  END a_d[301]
  PIN a_d[302]
    DIRECTION OUTPUT ;
    USE SIGNAL ;
    PORT
      LAYER M5 ;
        RECT  47.184 103.572 47.208 103.656 ;
    END
  END a_d[302]
  PIN a_d[303]
    DIRECTION OUTPUT ;
    USE SIGNAL ;
    PORT
      LAYER M5 ;
        RECT  47.28 103.572 47.304 103.656 ;
    END
  END a_d[303]
  PIN a_d[304]
    DIRECTION OUTPUT ;
    USE SIGNAL ;
    PORT
      LAYER M5 ;
        RECT  47.376 103.572 47.4 103.656 ;
    END
  END a_d[304]
  PIN a_d[305]
    DIRECTION OUTPUT ;
    USE SIGNAL ;
    PORT
      LAYER M5 ;
        RECT  47.472 103.572 47.496 103.656 ;
    END
  END a_d[305]
  PIN a_d[306]
    DIRECTION OUTPUT ;
    USE SIGNAL ;
    PORT
      LAYER M5 ;
        RECT  47.568 103.572 47.592 103.656 ;
    END
  END a_d[306]
  PIN a_d[307]
    DIRECTION OUTPUT ;
    USE SIGNAL ;
    PORT
      LAYER M5 ;
        RECT  47.664 103.572 47.688 103.656 ;
    END
  END a_d[307]
  PIN a_d[308]
    DIRECTION OUTPUT ;
    USE SIGNAL ;
    PORT
      LAYER M5 ;
        RECT  47.76 103.572 47.784 103.656 ;
    END
  END a_d[308]
  PIN a_d[309]
    DIRECTION OUTPUT ;
    USE SIGNAL ;
    PORT
      LAYER M5 ;
        RECT  47.856 103.572 47.88 103.656 ;
    END
  END a_d[309]
  PIN a_d[30]
    DIRECTION OUTPUT ;
    USE SIGNAL ;
    PORT
      LAYER M5 ;
        RECT  23.376 103.572 23.4 103.656 ;
    END
  END a_d[30]
  PIN a_d[310]
    DIRECTION OUTPUT ;
    USE SIGNAL ;
    PORT
      LAYER M5 ;
        RECT  47.952 103.572 47.976 103.656 ;
    END
  END a_d[310]
  PIN a_d[311]
    DIRECTION OUTPUT ;
    USE SIGNAL ;
    PORT
      LAYER M5 ;
        RECT  48.048 103.572 48.072 103.656 ;
    END
  END a_d[311]
  PIN a_d[312]
    DIRECTION OUTPUT ;
    USE SIGNAL ;
    PORT
      LAYER M5 ;
        RECT  48.144 103.572 48.168 103.656 ;
    END
  END a_d[312]
  PIN a_d[313]
    DIRECTION OUTPUT ;
    USE SIGNAL ;
    PORT
      LAYER M5 ;
        RECT  48.24 103.572 48.264 103.656 ;
    END
  END a_d[313]
  PIN a_d[314]
    DIRECTION OUTPUT ;
    USE SIGNAL ;
    PORT
      LAYER M5 ;
        RECT  48.336 103.572 48.36 103.656 ;
    END
  END a_d[314]
  PIN a_d[315]
    DIRECTION OUTPUT ;
    USE SIGNAL ;
    PORT
      LAYER M5 ;
        RECT  48.432 103.572 48.456 103.656 ;
    END
  END a_d[315]
  PIN a_d[316]
    DIRECTION OUTPUT ;
    USE SIGNAL ;
    PORT
      LAYER M5 ;
        RECT  48.528 103.572 48.552 103.656 ;
    END
  END a_d[316]
  PIN a_d[317]
    DIRECTION OUTPUT ;
    USE SIGNAL ;
    PORT
      LAYER M5 ;
        RECT  48.624 103.572 48.648 103.656 ;
    END
  END a_d[317]
  PIN a_d[318]
    DIRECTION OUTPUT ;
    USE SIGNAL ;
    PORT
      LAYER M5 ;
        RECT  48.72 103.572 48.744 103.656 ;
    END
  END a_d[318]
  PIN a_d[319]
    DIRECTION OUTPUT ;
    USE SIGNAL ;
    PORT
      LAYER M5 ;
        RECT  48.816 103.572 48.84 103.656 ;
    END
  END a_d[319]
  PIN a_d[31]
    DIRECTION OUTPUT ;
    USE SIGNAL ;
    PORT
      LAYER M5 ;
        RECT  23.472 103.572 23.496 103.656 ;
    END
  END a_d[31]
  PIN a_d[320]
    DIRECTION OUTPUT ;
    USE SIGNAL ;
    PORT
      LAYER M5 ;
        RECT  39.696 103.572 39.72 103.656 ;
    END
  END a_d[320]
  PIN a_d[321]
    DIRECTION OUTPUT ;
    USE SIGNAL ;
    PORT
      LAYER M5 ;
        RECT  39.792 103.572 39.816 103.656 ;
    END
  END a_d[321]
  PIN a_d[322]
    DIRECTION OUTPUT ;
    USE SIGNAL ;
    PORT
      LAYER M5 ;
        RECT  39.888 103.572 39.912 103.656 ;
    END
  END a_d[322]
  PIN a_d[323]
    DIRECTION OUTPUT ;
    USE SIGNAL ;
    PORT
      LAYER M5 ;
        RECT  39.984 103.572 40.008 103.656 ;
    END
  END a_d[323]
  PIN a_d[324]
    DIRECTION OUTPUT ;
    USE SIGNAL ;
    PORT
      LAYER M5 ;
        RECT  40.08 103.572 40.104 103.656 ;
    END
  END a_d[324]
  PIN a_d[325]
    DIRECTION OUTPUT ;
    USE SIGNAL ;
    PORT
      LAYER M5 ;
        RECT  40.176 103.572 40.2 103.656 ;
    END
  END a_d[325]
  PIN a_d[326]
    DIRECTION OUTPUT ;
    USE SIGNAL ;
    PORT
      LAYER M5 ;
        RECT  40.272 103.572 40.296 103.656 ;
    END
  END a_d[326]
  PIN a_d[327]
    DIRECTION OUTPUT ;
    USE SIGNAL ;
    PORT
      LAYER M5 ;
        RECT  40.368 103.572 40.392 103.656 ;
    END
  END a_d[327]
  PIN a_d[328]
    DIRECTION OUTPUT ;
    USE SIGNAL ;
    PORT
      LAYER M5 ;
        RECT  40.464 103.572 40.488 103.656 ;
    END
  END a_d[328]
  PIN a_d[329]
    DIRECTION OUTPUT ;
    USE SIGNAL ;
    PORT
      LAYER M5 ;
        RECT  40.56 103.572 40.584 103.656 ;
    END
  END a_d[329]
  PIN a_d[32]
    DIRECTION OUTPUT ;
    USE SIGNAL ;
    PORT
      LAYER M5 ;
        RECT  29.712 103.572 29.736 103.656 ;
    END
  END a_d[32]
  PIN a_d[330]
    DIRECTION OUTPUT ;
    USE SIGNAL ;
    PORT
      LAYER M5 ;
        RECT  40.656 103.572 40.68 103.656 ;
    END
  END a_d[330]
  PIN a_d[331]
    DIRECTION OUTPUT ;
    USE SIGNAL ;
    PORT
      LAYER M5 ;
        RECT  40.752 103.572 40.776 103.656 ;
    END
  END a_d[331]
  PIN a_d[332]
    DIRECTION OUTPUT ;
    USE SIGNAL ;
    PORT
      LAYER M5 ;
        RECT  40.848 103.572 40.872 103.656 ;
    END
  END a_d[332]
  PIN a_d[333]
    DIRECTION OUTPUT ;
    USE SIGNAL ;
    PORT
      LAYER M5 ;
        RECT  40.944 103.572 40.968 103.656 ;
    END
  END a_d[333]
  PIN a_d[334]
    DIRECTION OUTPUT ;
    USE SIGNAL ;
    PORT
      LAYER M5 ;
        RECT  41.04 103.572 41.064 103.656 ;
    END
  END a_d[334]
  PIN a_d[335]
    DIRECTION OUTPUT ;
    USE SIGNAL ;
    PORT
      LAYER M5 ;
        RECT  41.136 103.572 41.16 103.656 ;
    END
  END a_d[335]
  PIN a_d[336]
    DIRECTION OUTPUT ;
    USE SIGNAL ;
    PORT
      LAYER M5 ;
        RECT  41.232 103.572 41.256 103.656 ;
    END
  END a_d[336]
  PIN a_d[337]
    DIRECTION OUTPUT ;
    USE SIGNAL ;
    PORT
      LAYER M5 ;
        RECT  41.328 103.572 41.352 103.656 ;
    END
  END a_d[337]
  PIN a_d[338]
    DIRECTION OUTPUT ;
    USE SIGNAL ;
    PORT
      LAYER M5 ;
        RECT  41.424 103.572 41.448 103.656 ;
    END
  END a_d[338]
  PIN a_d[339]
    DIRECTION OUTPUT ;
    USE SIGNAL ;
    PORT
      LAYER M5 ;
        RECT  41.52 103.572 41.544 103.656 ;
    END
  END a_d[339]
  PIN a_d[33]
    DIRECTION OUTPUT ;
    USE SIGNAL ;
    PORT
      LAYER M5 ;
        RECT  29.808 103.572 29.832 103.656 ;
    END
  END a_d[33]
  PIN a_d[340]
    DIRECTION OUTPUT ;
    USE SIGNAL ;
    PORT
      LAYER M5 ;
        RECT  41.616 103.572 41.64 103.656 ;
    END
  END a_d[340]
  PIN a_d[341]
    DIRECTION OUTPUT ;
    USE SIGNAL ;
    PORT
      LAYER M5 ;
        RECT  41.712 103.572 41.736 103.656 ;
    END
  END a_d[341]
  PIN a_d[342]
    DIRECTION OUTPUT ;
    USE SIGNAL ;
    PORT
      LAYER M5 ;
        RECT  41.808 103.572 41.832 103.656 ;
    END
  END a_d[342]
  PIN a_d[343]
    DIRECTION OUTPUT ;
    USE SIGNAL ;
    PORT
      LAYER M5 ;
        RECT  41.904 103.572 41.928 103.656 ;
    END
  END a_d[343]
  PIN a_d[344]
    DIRECTION OUTPUT ;
    USE SIGNAL ;
    PORT
      LAYER M5 ;
        RECT  42 103.572 42.024 103.656 ;
    END
  END a_d[344]
  PIN a_d[345]
    DIRECTION OUTPUT ;
    USE SIGNAL ;
    PORT
      LAYER M5 ;
        RECT  42.096 103.572 42.12 103.656 ;
    END
  END a_d[345]
  PIN a_d[346]
    DIRECTION OUTPUT ;
    USE SIGNAL ;
    PORT
      LAYER M5 ;
        RECT  42.192 103.572 42.216 103.656 ;
    END
  END a_d[346]
  PIN a_d[347]
    DIRECTION OUTPUT ;
    USE SIGNAL ;
    PORT
      LAYER M5 ;
        RECT  42.288 103.572 42.312 103.656 ;
    END
  END a_d[347]
  PIN a_d[348]
    DIRECTION OUTPUT ;
    USE SIGNAL ;
    PORT
      LAYER M5 ;
        RECT  42.384 103.572 42.408 103.656 ;
    END
  END a_d[348]
  PIN a_d[349]
    DIRECTION OUTPUT ;
    USE SIGNAL ;
    PORT
      LAYER M5 ;
        RECT  42.48 103.572 42.504 103.656 ;
    END
  END a_d[349]
  PIN a_d[34]
    DIRECTION OUTPUT ;
    USE SIGNAL ;
    PORT
      LAYER M5 ;
        RECT  29.904 103.572 29.928 103.656 ;
    END
  END a_d[34]
  PIN a_d[350]
    DIRECTION OUTPUT ;
    USE SIGNAL ;
    PORT
      LAYER M5 ;
        RECT  42.576 103.572 42.6 103.656 ;
    END
  END a_d[350]
  PIN a_d[351]
    DIRECTION OUTPUT ;
    USE SIGNAL ;
    PORT
      LAYER M5 ;
        RECT  42.672 103.572 42.696 103.656 ;
    END
  END a_d[351]
  PIN a_d[352]
    DIRECTION OUTPUT ;
    USE SIGNAL ;
    PORT
      LAYER M5 ;
        RECT  48.912 103.572 48.936 103.656 ;
    END
  END a_d[352]
  PIN a_d[353]
    DIRECTION OUTPUT ;
    USE SIGNAL ;
    PORT
      LAYER M5 ;
        RECT  49.008 103.572 49.032 103.656 ;
    END
  END a_d[353]
  PIN a_d[354]
    DIRECTION OUTPUT ;
    USE SIGNAL ;
    PORT
      LAYER M5 ;
        RECT  49.104 103.572 49.128 103.656 ;
    END
  END a_d[354]
  PIN a_d[355]
    DIRECTION OUTPUT ;
    USE SIGNAL ;
    PORT
      LAYER M5 ;
        RECT  49.2 103.572 49.224 103.656 ;
    END
  END a_d[355]
  PIN a_d[356]
    DIRECTION OUTPUT ;
    USE SIGNAL ;
    PORT
      LAYER M5 ;
        RECT  49.296 103.572 49.32 103.656 ;
    END
  END a_d[356]
  PIN a_d[357]
    DIRECTION OUTPUT ;
    USE SIGNAL ;
    PORT
      LAYER M5 ;
        RECT  49.392 103.572 49.416 103.656 ;
    END
  END a_d[357]
  PIN a_d[358]
    DIRECTION OUTPUT ;
    USE SIGNAL ;
    PORT
      LAYER M5 ;
        RECT  49.488 103.572 49.512 103.656 ;
    END
  END a_d[358]
  PIN a_d[359]
    DIRECTION OUTPUT ;
    USE SIGNAL ;
    PORT
      LAYER M5 ;
        RECT  49.584 103.572 49.608 103.656 ;
    END
  END a_d[359]
  PIN a_d[35]
    DIRECTION OUTPUT ;
    USE SIGNAL ;
    PORT
      LAYER M5 ;
        RECT  30 103.572 30.024 103.656 ;
    END
  END a_d[35]
  PIN a_d[360]
    DIRECTION OUTPUT ;
    USE SIGNAL ;
    PORT
      LAYER M5 ;
        RECT  49.68 103.572 49.704 103.656 ;
    END
  END a_d[360]
  PIN a_d[361]
    DIRECTION OUTPUT ;
    USE SIGNAL ;
    PORT
      LAYER M5 ;
        RECT  49.776 103.572 49.8 103.656 ;
    END
  END a_d[361]
  PIN a_d[362]
    DIRECTION OUTPUT ;
    USE SIGNAL ;
    PORT
      LAYER M5 ;
        RECT  49.872 103.572 49.896 103.656 ;
    END
  END a_d[362]
  PIN a_d[363]
    DIRECTION OUTPUT ;
    USE SIGNAL ;
    PORT
      LAYER M5 ;
        RECT  49.968 103.572 49.992 103.656 ;
    END
  END a_d[363]
  PIN a_d[364]
    DIRECTION OUTPUT ;
    USE SIGNAL ;
    PORT
      LAYER M5 ;
        RECT  50.064 103.572 50.088 103.656 ;
    END
  END a_d[364]
  PIN a_d[365]
    DIRECTION OUTPUT ;
    USE SIGNAL ;
    PORT
      LAYER M5 ;
        RECT  50.16 103.572 50.184 103.656 ;
    END
  END a_d[365]
  PIN a_d[366]
    DIRECTION OUTPUT ;
    USE SIGNAL ;
    PORT
      LAYER M5 ;
        RECT  50.256 103.572 50.28 103.656 ;
    END
  END a_d[366]
  PIN a_d[367]
    DIRECTION OUTPUT ;
    USE SIGNAL ;
    PORT
      LAYER M5 ;
        RECT  50.352 103.572 50.376 103.656 ;
    END
  END a_d[367]
  PIN a_d[368]
    DIRECTION OUTPUT ;
    USE SIGNAL ;
    PORT
      LAYER M5 ;
        RECT  50.448 103.572 50.472 103.656 ;
    END
  END a_d[368]
  PIN a_d[369]
    DIRECTION OUTPUT ;
    USE SIGNAL ;
    PORT
      LAYER M5 ;
        RECT  50.544 103.572 50.568 103.656 ;
    END
  END a_d[369]
  PIN a_d[36]
    DIRECTION OUTPUT ;
    USE SIGNAL ;
    PORT
      LAYER M5 ;
        RECT  30.096 103.572 30.12 103.656 ;
    END
  END a_d[36]
  PIN a_d[370]
    DIRECTION OUTPUT ;
    USE SIGNAL ;
    PORT
      LAYER M5 ;
        RECT  50.64 103.572 50.664 103.656 ;
    END
  END a_d[370]
  PIN a_d[371]
    DIRECTION OUTPUT ;
    USE SIGNAL ;
    PORT
      LAYER M5 ;
        RECT  50.736 103.572 50.76 103.656 ;
    END
  END a_d[371]
  PIN a_d[372]
    DIRECTION OUTPUT ;
    USE SIGNAL ;
    PORT
      LAYER M5 ;
        RECT  50.832 103.572 50.856 103.656 ;
    END
  END a_d[372]
  PIN a_d[373]
    DIRECTION OUTPUT ;
    USE SIGNAL ;
    PORT
      LAYER M5 ;
        RECT  50.928 103.572 50.952 103.656 ;
    END
  END a_d[373]
  PIN a_d[374]
    DIRECTION OUTPUT ;
    USE SIGNAL ;
    PORT
      LAYER M5 ;
        RECT  51.024 103.572 51.048 103.656 ;
    END
  END a_d[374]
  PIN a_d[375]
    DIRECTION OUTPUT ;
    USE SIGNAL ;
    PORT
      LAYER M5 ;
        RECT  51.12 103.572 51.144 103.656 ;
    END
  END a_d[375]
  PIN a_d[376]
    DIRECTION OUTPUT ;
    USE SIGNAL ;
    PORT
      LAYER M5 ;
        RECT  51.216 103.572 51.24 103.656 ;
    END
  END a_d[376]
  PIN a_d[377]
    DIRECTION OUTPUT ;
    USE SIGNAL ;
    PORT
      LAYER M5 ;
        RECT  51.312 103.572 51.336 103.656 ;
    END
  END a_d[377]
  PIN a_d[378]
    DIRECTION OUTPUT ;
    USE SIGNAL ;
    PORT
      LAYER M5 ;
        RECT  51.408 103.572 51.432 103.656 ;
    END
  END a_d[378]
  PIN a_d[379]
    DIRECTION OUTPUT ;
    USE SIGNAL ;
    PORT
      LAYER M5 ;
        RECT  51.504 103.572 51.528 103.656 ;
    END
  END a_d[379]
  PIN a_d[37]
    DIRECTION OUTPUT ;
    USE SIGNAL ;
    PORT
      LAYER M5 ;
        RECT  30.192 103.572 30.216 103.656 ;
    END
  END a_d[37]
  PIN a_d[380]
    DIRECTION OUTPUT ;
    USE SIGNAL ;
    PORT
      LAYER M5 ;
        RECT  51.6 103.572 51.624 103.656 ;
    END
  END a_d[380]
  PIN a_d[381]
    DIRECTION OUTPUT ;
    USE SIGNAL ;
    PORT
      LAYER M5 ;
        RECT  51.696 103.572 51.72 103.656 ;
    END
  END a_d[381]
  PIN a_d[382]
    DIRECTION OUTPUT ;
    USE SIGNAL ;
    PORT
      LAYER M5 ;
        RECT  51.792 103.572 51.816 103.656 ;
    END
  END a_d[382]
  PIN a_d[383]
    DIRECTION OUTPUT ;
    USE SIGNAL ;
    PORT
      LAYER M5 ;
        RECT  51.888 103.572 51.912 103.656 ;
    END
  END a_d[383]
  PIN a_d[384]
    DIRECTION OUTPUT ;
    USE SIGNAL ;
    PORT
      LAYER M5 ;
        RECT  10.512 103.572 10.536 103.656 ;
    END
  END a_d[384]
  PIN a_d[385]
    DIRECTION OUTPUT ;
    USE SIGNAL ;
    PORT
      LAYER M5 ;
        RECT  10.608 103.572 10.632 103.656 ;
    END
  END a_d[385]
  PIN a_d[386]
    DIRECTION OUTPUT ;
    USE SIGNAL ;
    PORT
      LAYER M5 ;
        RECT  10.704 103.572 10.728 103.656 ;
    END
  END a_d[386]
  PIN a_d[387]
    DIRECTION OUTPUT ;
    USE SIGNAL ;
    PORT
      LAYER M5 ;
        RECT  10.8 103.572 10.824 103.656 ;
    END
  END a_d[387]
  PIN a_d[388]
    DIRECTION OUTPUT ;
    USE SIGNAL ;
    PORT
      LAYER M5 ;
        RECT  10.896 103.572 10.92 103.656 ;
    END
  END a_d[388]
  PIN a_d[389]
    DIRECTION OUTPUT ;
    USE SIGNAL ;
    PORT
      LAYER M5 ;
        RECT  10.992 103.572 11.016 103.656 ;
    END
  END a_d[389]
  PIN a_d[38]
    DIRECTION OUTPUT ;
    USE SIGNAL ;
    PORT
      LAYER M5 ;
        RECT  30.288 103.572 30.312 103.656 ;
    END
  END a_d[38]
  PIN a_d[390]
    DIRECTION OUTPUT ;
    USE SIGNAL ;
    PORT
      LAYER M5 ;
        RECT  11.088 103.572 11.112 103.656 ;
    END
  END a_d[390]
  PIN a_d[391]
    DIRECTION OUTPUT ;
    USE SIGNAL ;
    PORT
      LAYER M5 ;
        RECT  11.184 103.572 11.208 103.656 ;
    END
  END a_d[391]
  PIN a_d[392]
    DIRECTION OUTPUT ;
    USE SIGNAL ;
    PORT
      LAYER M5 ;
        RECT  11.28 103.572 11.304 103.656 ;
    END
  END a_d[392]
  PIN a_d[393]
    DIRECTION OUTPUT ;
    USE SIGNAL ;
    PORT
      LAYER M5 ;
        RECT  11.376 103.572 11.4 103.656 ;
    END
  END a_d[393]
  PIN a_d[394]
    DIRECTION OUTPUT ;
    USE SIGNAL ;
    PORT
      LAYER M5 ;
        RECT  11.472 103.572 11.496 103.656 ;
    END
  END a_d[394]
  PIN a_d[395]
    DIRECTION OUTPUT ;
    USE SIGNAL ;
    PORT
      LAYER M5 ;
        RECT  11.568 103.572 11.592 103.656 ;
    END
  END a_d[395]
  PIN a_d[396]
    DIRECTION OUTPUT ;
    USE SIGNAL ;
    PORT
      LAYER M5 ;
        RECT  11.664 103.572 11.688 103.656 ;
    END
  END a_d[396]
  PIN a_d[397]
    DIRECTION OUTPUT ;
    USE SIGNAL ;
    PORT
      LAYER M5 ;
        RECT  11.76 103.572 11.784 103.656 ;
    END
  END a_d[397]
  PIN a_d[398]
    DIRECTION OUTPUT ;
    USE SIGNAL ;
    PORT
      LAYER M5 ;
        RECT  11.856 103.572 11.88 103.656 ;
    END
  END a_d[398]
  PIN a_d[399]
    DIRECTION OUTPUT ;
    USE SIGNAL ;
    PORT
      LAYER M5 ;
        RECT  11.952 103.572 11.976 103.656 ;
    END
  END a_d[399]
  PIN a_d[39]
    DIRECTION OUTPUT ;
    USE SIGNAL ;
    PORT
      LAYER M5 ;
        RECT  30.384 103.572 30.408 103.656 ;
    END
  END a_d[39]
  PIN a_d[3]
    DIRECTION OUTPUT ;
    USE SIGNAL ;
    PORT
      LAYER M5 ;
        RECT  20.784 103.572 20.808 103.656 ;
    END
  END a_d[3]
  PIN a_d[400]
    DIRECTION OUTPUT ;
    USE SIGNAL ;
    PORT
      LAYER M5 ;
        RECT  12.048 103.572 12.072 103.656 ;
    END
  END a_d[400]
  PIN a_d[401]
    DIRECTION OUTPUT ;
    USE SIGNAL ;
    PORT
      LAYER M5 ;
        RECT  12.144 103.572 12.168 103.656 ;
    END
  END a_d[401]
  PIN a_d[402]
    DIRECTION OUTPUT ;
    USE SIGNAL ;
    PORT
      LAYER M5 ;
        RECT  12.24 103.572 12.264 103.656 ;
    END
  END a_d[402]
  PIN a_d[403]
    DIRECTION OUTPUT ;
    USE SIGNAL ;
    PORT
      LAYER M5 ;
        RECT  12.336 103.572 12.36 103.656 ;
    END
  END a_d[403]
  PIN a_d[404]
    DIRECTION OUTPUT ;
    USE SIGNAL ;
    PORT
      LAYER M5 ;
        RECT  12.432 103.572 12.456 103.656 ;
    END
  END a_d[404]
  PIN a_d[405]
    DIRECTION OUTPUT ;
    USE SIGNAL ;
    PORT
      LAYER M5 ;
        RECT  12.528 103.572 12.552 103.656 ;
    END
  END a_d[405]
  PIN a_d[406]
    DIRECTION OUTPUT ;
    USE SIGNAL ;
    PORT
      LAYER M5 ;
        RECT  12.624 103.572 12.648 103.656 ;
    END
  END a_d[406]
  PIN a_d[407]
    DIRECTION OUTPUT ;
    USE SIGNAL ;
    PORT
      LAYER M5 ;
        RECT  12.72 103.572 12.744 103.656 ;
    END
  END a_d[407]
  PIN a_d[408]
    DIRECTION OUTPUT ;
    USE SIGNAL ;
    PORT
      LAYER M5 ;
        RECT  12.816 103.572 12.84 103.656 ;
    END
  END a_d[408]
  PIN a_d[409]
    DIRECTION OUTPUT ;
    USE SIGNAL ;
    PORT
      LAYER M5 ;
        RECT  12.912 103.572 12.936 103.656 ;
    END
  END a_d[409]
  PIN a_d[40]
    DIRECTION OUTPUT ;
    USE SIGNAL ;
    PORT
      LAYER M5 ;
        RECT  30.48 103.572 30.504 103.656 ;
    END
  END a_d[40]
  PIN a_d[410]
    DIRECTION OUTPUT ;
    USE SIGNAL ;
    PORT
      LAYER M5 ;
        RECT  13.008 103.572 13.032 103.656 ;
    END
  END a_d[410]
  PIN a_d[411]
    DIRECTION OUTPUT ;
    USE SIGNAL ;
    PORT
      LAYER M5 ;
        RECT  13.104 103.572 13.128 103.656 ;
    END
  END a_d[411]
  PIN a_d[412]
    DIRECTION OUTPUT ;
    USE SIGNAL ;
    PORT
      LAYER M5 ;
        RECT  13.2 103.572 13.224 103.656 ;
    END
  END a_d[412]
  PIN a_d[413]
    DIRECTION OUTPUT ;
    USE SIGNAL ;
    PORT
      LAYER M5 ;
        RECT  13.296 103.572 13.32 103.656 ;
    END
  END a_d[413]
  PIN a_d[414]
    DIRECTION OUTPUT ;
    USE SIGNAL ;
    PORT
      LAYER M5 ;
        RECT  13.392 103.572 13.416 103.656 ;
    END
  END a_d[414]
  PIN a_d[415]
    DIRECTION OUTPUT ;
    USE SIGNAL ;
    PORT
      LAYER M5 ;
        RECT  13.488 103.572 13.512 103.656 ;
    END
  END a_d[415]
  PIN a_d[416]
    DIRECTION OUTPUT ;
    USE SIGNAL ;
    PORT
      LAYER M5 ;
        RECT  4.368 103.572 4.392 103.656 ;
    END
  END a_d[416]
  PIN a_d[417]
    DIRECTION OUTPUT ;
    USE SIGNAL ;
    PORT
      LAYER M5 ;
        RECT  4.464 103.572 4.488 103.656 ;
    END
  END a_d[417]
  PIN a_d[418]
    DIRECTION OUTPUT ;
    USE SIGNAL ;
    PORT
      LAYER M5 ;
        RECT  4.56 103.572 4.584 103.656 ;
    END
  END a_d[418]
  PIN a_d[419]
    DIRECTION OUTPUT ;
    USE SIGNAL ;
    PORT
      LAYER M5 ;
        RECT  4.656 103.572 4.68 103.656 ;
    END
  END a_d[419]
  PIN a_d[41]
    DIRECTION OUTPUT ;
    USE SIGNAL ;
    PORT
      LAYER M5 ;
        RECT  30.576 103.572 30.6 103.656 ;
    END
  END a_d[41]
  PIN a_d[420]
    DIRECTION OUTPUT ;
    USE SIGNAL ;
    PORT
      LAYER M5 ;
        RECT  4.752 103.572 4.776 103.656 ;
    END
  END a_d[420]
  PIN a_d[421]
    DIRECTION OUTPUT ;
    USE SIGNAL ;
    PORT
      LAYER M5 ;
        RECT  4.848 103.572 4.872 103.656 ;
    END
  END a_d[421]
  PIN a_d[422]
    DIRECTION OUTPUT ;
    USE SIGNAL ;
    PORT
      LAYER M5 ;
        RECT  4.944 103.572 4.968 103.656 ;
    END
  END a_d[422]
  PIN a_d[423]
    DIRECTION OUTPUT ;
    USE SIGNAL ;
    PORT
      LAYER M5 ;
        RECT  5.04 103.572 5.064 103.656 ;
    END
  END a_d[423]
  PIN a_d[424]
    DIRECTION OUTPUT ;
    USE SIGNAL ;
    PORT
      LAYER M5 ;
        RECT  5.136 103.572 5.16 103.656 ;
    END
  END a_d[424]
  PIN a_d[425]
    DIRECTION OUTPUT ;
    USE SIGNAL ;
    PORT
      LAYER M5 ;
        RECT  5.232 103.572 5.256 103.656 ;
    END
  END a_d[425]
  PIN a_d[426]
    DIRECTION OUTPUT ;
    USE SIGNAL ;
    PORT
      LAYER M5 ;
        RECT  5.328 103.572 5.352 103.656 ;
    END
  END a_d[426]
  PIN a_d[427]
    DIRECTION OUTPUT ;
    USE SIGNAL ;
    PORT
      LAYER M5 ;
        RECT  5.424 103.572 5.448 103.656 ;
    END
  END a_d[427]
  PIN a_d[428]
    DIRECTION OUTPUT ;
    USE SIGNAL ;
    PORT
      LAYER M5 ;
        RECT  5.52 103.572 5.544 103.656 ;
    END
  END a_d[428]
  PIN a_d[429]
    DIRECTION OUTPUT ;
    USE SIGNAL ;
    PORT
      LAYER M5 ;
        RECT  5.616 103.572 5.64 103.656 ;
    END
  END a_d[429]
  PIN a_d[42]
    DIRECTION OUTPUT ;
    USE SIGNAL ;
    PORT
      LAYER M5 ;
        RECT  30.672 103.572 30.696 103.656 ;
    END
  END a_d[42]
  PIN a_d[430]
    DIRECTION OUTPUT ;
    USE SIGNAL ;
    PORT
      LAYER M5 ;
        RECT  5.712 103.572 5.736 103.656 ;
    END
  END a_d[430]
  PIN a_d[431]
    DIRECTION OUTPUT ;
    USE SIGNAL ;
    PORT
      LAYER M5 ;
        RECT  5.808 103.572 5.832 103.656 ;
    END
  END a_d[431]
  PIN a_d[432]
    DIRECTION OUTPUT ;
    USE SIGNAL ;
    PORT
      LAYER M5 ;
        RECT  5.904 103.572 5.928 103.656 ;
    END
  END a_d[432]
  PIN a_d[433]
    DIRECTION OUTPUT ;
    USE SIGNAL ;
    PORT
      LAYER M5 ;
        RECT  6 103.572 6.024 103.656 ;
    END
  END a_d[433]
  PIN a_d[434]
    DIRECTION OUTPUT ;
    USE SIGNAL ;
    PORT
      LAYER M5 ;
        RECT  6.096 103.572 6.12 103.656 ;
    END
  END a_d[434]
  PIN a_d[435]
    DIRECTION OUTPUT ;
    USE SIGNAL ;
    PORT
      LAYER M5 ;
        RECT  6.192 103.572 6.216 103.656 ;
    END
  END a_d[435]
  PIN a_d[436]
    DIRECTION OUTPUT ;
    USE SIGNAL ;
    PORT
      LAYER M5 ;
        RECT  6.288 103.572 6.312 103.656 ;
    END
  END a_d[436]
  PIN a_d[437]
    DIRECTION OUTPUT ;
    USE SIGNAL ;
    PORT
      LAYER M5 ;
        RECT  6.384 103.572 6.408 103.656 ;
    END
  END a_d[437]
  PIN a_d[438]
    DIRECTION OUTPUT ;
    USE SIGNAL ;
    PORT
      LAYER M5 ;
        RECT  6.48 103.572 6.504 103.656 ;
    END
  END a_d[438]
  PIN a_d[439]
    DIRECTION OUTPUT ;
    USE SIGNAL ;
    PORT
      LAYER M5 ;
        RECT  6.576 103.572 6.6 103.656 ;
    END
  END a_d[439]
  PIN a_d[43]
    DIRECTION OUTPUT ;
    USE SIGNAL ;
    PORT
      LAYER M5 ;
        RECT  30.768 103.572 30.792 103.656 ;
    END
  END a_d[43]
  PIN a_d[440]
    DIRECTION OUTPUT ;
    USE SIGNAL ;
    PORT
      LAYER M5 ;
        RECT  6.672 103.572 6.696 103.656 ;
    END
  END a_d[440]
  PIN a_d[441]
    DIRECTION OUTPUT ;
    USE SIGNAL ;
    PORT
      LAYER M5 ;
        RECT  6.768 103.572 6.792 103.656 ;
    END
  END a_d[441]
  PIN a_d[442]
    DIRECTION OUTPUT ;
    USE SIGNAL ;
    PORT
      LAYER M5 ;
        RECT  6.864 103.572 6.888 103.656 ;
    END
  END a_d[442]
  PIN a_d[443]
    DIRECTION OUTPUT ;
    USE SIGNAL ;
    PORT
      LAYER M5 ;
        RECT  6.96 103.572 6.984 103.656 ;
    END
  END a_d[443]
  PIN a_d[444]
    DIRECTION OUTPUT ;
    USE SIGNAL ;
    PORT
      LAYER M5 ;
        RECT  7.056 103.572 7.08 103.656 ;
    END
  END a_d[444]
  PIN a_d[445]
    DIRECTION OUTPUT ;
    USE SIGNAL ;
    PORT
      LAYER M5 ;
        RECT  7.152 103.572 7.176 103.656 ;
    END
  END a_d[445]
  PIN a_d[446]
    DIRECTION OUTPUT ;
    USE SIGNAL ;
    PORT
      LAYER M5 ;
        RECT  7.248 103.572 7.272 103.656 ;
    END
  END a_d[446]
  PIN a_d[447]
    DIRECTION OUTPUT ;
    USE SIGNAL ;
    PORT
      LAYER M5 ;
        RECT  7.344 103.572 7.368 103.656 ;
    END
  END a_d[447]
  PIN a_d[448]
    DIRECTION OUTPUT ;
    USE SIGNAL ;
    PORT
      LAYER M5 ;
        RECT  7.44 103.572 7.464 103.656 ;
    END
  END a_d[448]
  PIN a_d[449]
    DIRECTION OUTPUT ;
    USE SIGNAL ;
    PORT
      LAYER M5 ;
        RECT  7.536 103.572 7.56 103.656 ;
    END
  END a_d[449]
  PIN a_d[44]
    DIRECTION OUTPUT ;
    USE SIGNAL ;
    PORT
      LAYER M5 ;
        RECT  30.864 103.572 30.888 103.656 ;
    END
  END a_d[44]
  PIN a_d[450]
    DIRECTION OUTPUT ;
    USE SIGNAL ;
    PORT
      LAYER M5 ;
        RECT  7.632 103.572 7.656 103.656 ;
    END
  END a_d[450]
  PIN a_d[451]
    DIRECTION OUTPUT ;
    USE SIGNAL ;
    PORT
      LAYER M5 ;
        RECT  7.728 103.572 7.752 103.656 ;
    END
  END a_d[451]
  PIN a_d[452]
    DIRECTION OUTPUT ;
    USE SIGNAL ;
    PORT
      LAYER M5 ;
        RECT  7.824 103.572 7.848 103.656 ;
    END
  END a_d[452]
  PIN a_d[453]
    DIRECTION OUTPUT ;
    USE SIGNAL ;
    PORT
      LAYER M5 ;
        RECT  7.92 103.572 7.944 103.656 ;
    END
  END a_d[453]
  PIN a_d[454]
    DIRECTION OUTPUT ;
    USE SIGNAL ;
    PORT
      LAYER M5 ;
        RECT  8.016 103.572 8.04 103.656 ;
    END
  END a_d[454]
  PIN a_d[455]
    DIRECTION OUTPUT ;
    USE SIGNAL ;
    PORT
      LAYER M5 ;
        RECT  8.112 103.572 8.136 103.656 ;
    END
  END a_d[455]
  PIN a_d[456]
    DIRECTION OUTPUT ;
    USE SIGNAL ;
    PORT
      LAYER M5 ;
        RECT  8.208 103.572 8.232 103.656 ;
    END
  END a_d[456]
  PIN a_d[457]
    DIRECTION OUTPUT ;
    USE SIGNAL ;
    PORT
      LAYER M5 ;
        RECT  8.304 103.572 8.328 103.656 ;
    END
  END a_d[457]
  PIN a_d[458]
    DIRECTION OUTPUT ;
    USE SIGNAL ;
    PORT
      LAYER M5 ;
        RECT  8.4 103.572 8.424 103.656 ;
    END
  END a_d[458]
  PIN a_d[459]
    DIRECTION OUTPUT ;
    USE SIGNAL ;
    PORT
      LAYER M5 ;
        RECT  8.496 103.572 8.52 103.656 ;
    END
  END a_d[459]
  PIN a_d[45]
    DIRECTION OUTPUT ;
    USE SIGNAL ;
    PORT
      LAYER M5 ;
        RECT  30.96 103.572 30.984 103.656 ;
    END
  END a_d[45]
  PIN a_d[460]
    DIRECTION OUTPUT ;
    USE SIGNAL ;
    PORT
      LAYER M5 ;
        RECT  8.592 103.572 8.616 103.656 ;
    END
  END a_d[460]
  PIN a_d[461]
    DIRECTION OUTPUT ;
    USE SIGNAL ;
    PORT
      LAYER M5 ;
        RECT  8.688 103.572 8.712 103.656 ;
    END
  END a_d[461]
  PIN a_d[462]
    DIRECTION OUTPUT ;
    USE SIGNAL ;
    PORT
      LAYER M5 ;
        RECT  8.784 103.572 8.808 103.656 ;
    END
  END a_d[462]
  PIN a_d[463]
    DIRECTION OUTPUT ;
    USE SIGNAL ;
    PORT
      LAYER M5 ;
        RECT  8.88 103.572 8.904 103.656 ;
    END
  END a_d[463]
  PIN a_d[464]
    DIRECTION OUTPUT ;
    USE SIGNAL ;
    PORT
      LAYER M5 ;
        RECT  8.976 103.572 9 103.656 ;
    END
  END a_d[464]
  PIN a_d[465]
    DIRECTION OUTPUT ;
    USE SIGNAL ;
    PORT
      LAYER M5 ;
        RECT  9.072 103.572 9.096 103.656 ;
    END
  END a_d[465]
  PIN a_d[466]
    DIRECTION OUTPUT ;
    USE SIGNAL ;
    PORT
      LAYER M5 ;
        RECT  9.168 103.572 9.192 103.656 ;
    END
  END a_d[466]
  PIN a_d[467]
    DIRECTION OUTPUT ;
    USE SIGNAL ;
    PORT
      LAYER M5 ;
        RECT  9.264 103.572 9.288 103.656 ;
    END
  END a_d[467]
  PIN a_d[468]
    DIRECTION OUTPUT ;
    USE SIGNAL ;
    PORT
      LAYER M5 ;
        RECT  9.36 103.572 9.384 103.656 ;
    END
  END a_d[468]
  PIN a_d[469]
    DIRECTION OUTPUT ;
    USE SIGNAL ;
    PORT
      LAYER M5 ;
        RECT  9.456 103.572 9.48 103.656 ;
    END
  END a_d[469]
  PIN a_d[46]
    DIRECTION OUTPUT ;
    USE SIGNAL ;
    PORT
      LAYER M5 ;
        RECT  31.056 103.572 31.08 103.656 ;
    END
  END a_d[46]
  PIN a_d[470]
    DIRECTION OUTPUT ;
    USE SIGNAL ;
    PORT
      LAYER M5 ;
        RECT  9.552 103.572 9.576 103.656 ;
    END
  END a_d[470]
  PIN a_d[471]
    DIRECTION OUTPUT ;
    USE SIGNAL ;
    PORT
      LAYER M5 ;
        RECT  9.648 103.572 9.672 103.656 ;
    END
  END a_d[471]
  PIN a_d[472]
    DIRECTION OUTPUT ;
    USE SIGNAL ;
    PORT
      LAYER M5 ;
        RECT  9.744 103.572 9.768 103.656 ;
    END
  END a_d[472]
  PIN a_d[473]
    DIRECTION OUTPUT ;
    USE SIGNAL ;
    PORT
      LAYER M5 ;
        RECT  9.84 103.572 9.864 103.656 ;
    END
  END a_d[473]
  PIN a_d[474]
    DIRECTION OUTPUT ;
    USE SIGNAL ;
    PORT
      LAYER M5 ;
        RECT  9.936 103.572 9.96 103.656 ;
    END
  END a_d[474]
  PIN a_d[475]
    DIRECTION OUTPUT ;
    USE SIGNAL ;
    PORT
      LAYER M5 ;
        RECT  10.032 103.572 10.056 103.656 ;
    END
  END a_d[475]
  PIN a_d[476]
    DIRECTION OUTPUT ;
    USE SIGNAL ;
    PORT
      LAYER M5 ;
        RECT  10.128 103.572 10.152 103.656 ;
    END
  END a_d[476]
  PIN a_d[477]
    DIRECTION OUTPUT ;
    USE SIGNAL ;
    PORT
      LAYER M5 ;
        RECT  10.224 103.572 10.248 103.656 ;
    END
  END a_d[477]
  PIN a_d[478]
    DIRECTION OUTPUT ;
    USE SIGNAL ;
    PORT
      LAYER M5 ;
        RECT  10.32 103.572 10.344 103.656 ;
    END
  END a_d[478]
  PIN a_d[479]
    DIRECTION OUTPUT ;
    USE SIGNAL ;
    PORT
      LAYER M5 ;
        RECT  10.416 103.572 10.44 103.656 ;
    END
  END a_d[479]
  PIN a_d[47]
    DIRECTION OUTPUT ;
    USE SIGNAL ;
    PORT
      LAYER M5 ;
        RECT  31.152 103.572 31.176 103.656 ;
    END
  END a_d[47]
  PIN a_d[480]
    DIRECTION OUTPUT ;
    USE SIGNAL ;
    PORT
      LAYER M5 ;
        RECT  1.392 103.572 1.416 103.656 ;
    END
  END a_d[480]
  PIN a_d[481]
    DIRECTION OUTPUT ;
    USE SIGNAL ;
    PORT
      LAYER M5 ;
        RECT  1.488 103.572 1.512 103.656 ;
    END
  END a_d[481]
  PIN a_d[482]
    DIRECTION OUTPUT ;
    USE SIGNAL ;
    PORT
      LAYER M5 ;
        RECT  1.584 103.572 1.608 103.656 ;
    END
  END a_d[482]
  PIN a_d[483]
    DIRECTION OUTPUT ;
    USE SIGNAL ;
    PORT
      LAYER M5 ;
        RECT  1.68 103.572 1.704 103.656 ;
    END
  END a_d[483]
  PIN a_d[484]
    DIRECTION OUTPUT ;
    USE SIGNAL ;
    PORT
      LAYER M5 ;
        RECT  1.776 103.572 1.8 103.656 ;
    END
  END a_d[484]
  PIN a_d[485]
    DIRECTION OUTPUT ;
    USE SIGNAL ;
    PORT
      LAYER M5 ;
        RECT  1.872 103.572 1.896 103.656 ;
    END
  END a_d[485]
  PIN a_d[486]
    DIRECTION OUTPUT ;
    USE SIGNAL ;
    PORT
      LAYER M5 ;
        RECT  1.968 103.572 1.992 103.656 ;
    END
  END a_d[486]
  PIN a_d[487]
    DIRECTION OUTPUT ;
    USE SIGNAL ;
    PORT
      LAYER M5 ;
        RECT  2.064 103.572 2.088 103.656 ;
    END
  END a_d[487]
  PIN a_d[488]
    DIRECTION OUTPUT ;
    USE SIGNAL ;
    PORT
      LAYER M5 ;
        RECT  2.16 103.572 2.184 103.656 ;
    END
  END a_d[488]
  PIN a_d[489]
    DIRECTION OUTPUT ;
    USE SIGNAL ;
    PORT
      LAYER M5 ;
        RECT  2.256 103.572 2.28 103.656 ;
    END
  END a_d[489]
  PIN a_d[48]
    DIRECTION OUTPUT ;
    USE SIGNAL ;
    PORT
      LAYER M5 ;
        RECT  31.248 103.572 31.272 103.656 ;
    END
  END a_d[48]
  PIN a_d[490]
    DIRECTION OUTPUT ;
    USE SIGNAL ;
    PORT
      LAYER M5 ;
        RECT  2.352 103.572 2.376 103.656 ;
    END
  END a_d[490]
  PIN a_d[491]
    DIRECTION OUTPUT ;
    USE SIGNAL ;
    PORT
      LAYER M5 ;
        RECT  2.448 103.572 2.472 103.656 ;
    END
  END a_d[491]
  PIN a_d[492]
    DIRECTION OUTPUT ;
    USE SIGNAL ;
    PORT
      LAYER M5 ;
        RECT  2.544 103.572 2.568 103.656 ;
    END
  END a_d[492]
  PIN a_d[493]
    DIRECTION OUTPUT ;
    USE SIGNAL ;
    PORT
      LAYER M5 ;
        RECT  2.64 103.572 2.664 103.656 ;
    END
  END a_d[493]
  PIN a_d[494]
    DIRECTION OUTPUT ;
    USE SIGNAL ;
    PORT
      LAYER M5 ;
        RECT  2.736 103.572 2.76 103.656 ;
    END
  END a_d[494]
  PIN a_d[495]
    DIRECTION OUTPUT ;
    USE SIGNAL ;
    PORT
      LAYER M5 ;
        RECT  2.832 103.572 2.856 103.656 ;
    END
  END a_d[495]
  PIN a_d[496]
    DIRECTION OUTPUT ;
    USE SIGNAL ;
    PORT
      LAYER M5 ;
        RECT  2.928 103.572 2.952 103.656 ;
    END
  END a_d[496]
  PIN a_d[497]
    DIRECTION OUTPUT ;
    USE SIGNAL ;
    PORT
      LAYER M5 ;
        RECT  3.024 103.572 3.048 103.656 ;
    END
  END a_d[497]
  PIN a_d[498]
    DIRECTION OUTPUT ;
    USE SIGNAL ;
    PORT
      LAYER M5 ;
        RECT  3.12 103.572 3.144 103.656 ;
    END
  END a_d[498]
  PIN a_d[499]
    DIRECTION OUTPUT ;
    USE SIGNAL ;
    PORT
      LAYER M5 ;
        RECT  3.216 103.572 3.24 103.656 ;
    END
  END a_d[499]
  PIN a_d[49]
    DIRECTION OUTPUT ;
    USE SIGNAL ;
    PORT
      LAYER M5 ;
        RECT  31.344 103.572 31.368 103.656 ;
    END
  END a_d[49]
  PIN a_d[4]
    DIRECTION OUTPUT ;
    USE SIGNAL ;
    PORT
      LAYER M5 ;
        RECT  20.88 103.572 20.904 103.656 ;
    END
  END a_d[4]
  PIN a_d[500]
    DIRECTION OUTPUT ;
    USE SIGNAL ;
    PORT
      LAYER M5 ;
        RECT  3.312 103.572 3.336 103.656 ;
    END
  END a_d[500]
  PIN a_d[501]
    DIRECTION OUTPUT ;
    USE SIGNAL ;
    PORT
      LAYER M5 ;
        RECT  3.408 103.572 3.432 103.656 ;
    END
  END a_d[501]
  PIN a_d[502]
    DIRECTION OUTPUT ;
    USE SIGNAL ;
    PORT
      LAYER M5 ;
        RECT  3.504 103.572 3.528 103.656 ;
    END
  END a_d[502]
  PIN a_d[503]
    DIRECTION OUTPUT ;
    USE SIGNAL ;
    PORT
      LAYER M5 ;
        RECT  3.6 103.572 3.624 103.656 ;
    END
  END a_d[503]
  PIN a_d[504]
    DIRECTION OUTPUT ;
    USE SIGNAL ;
    PORT
      LAYER M5 ;
        RECT  3.696 103.572 3.72 103.656 ;
    END
  END a_d[504]
  PIN a_d[505]
    DIRECTION OUTPUT ;
    USE SIGNAL ;
    PORT
      LAYER M5 ;
        RECT  3.792 103.572 3.816 103.656 ;
    END
  END a_d[505]
  PIN a_d[506]
    DIRECTION OUTPUT ;
    USE SIGNAL ;
    PORT
      LAYER M5 ;
        RECT  3.888 103.572 3.912 103.656 ;
    END
  END a_d[506]
  PIN a_d[507]
    DIRECTION OUTPUT ;
    USE SIGNAL ;
    PORT
      LAYER M5 ;
        RECT  3.984 103.572 4.008 103.656 ;
    END
  END a_d[507]
  PIN a_d[50]
    DIRECTION OUTPUT ;
    USE SIGNAL ;
    PORT
      LAYER M5 ;
        RECT  31.44 103.572 31.464 103.656 ;
    END
  END a_d[50]
  PIN a_d[51]
    DIRECTION OUTPUT ;
    USE SIGNAL ;
    PORT
      LAYER M5 ;
        RECT  31.536 103.572 31.56 103.656 ;
    END
  END a_d[51]
  PIN a_d[52]
    DIRECTION OUTPUT ;
    USE SIGNAL ;
    PORT
      LAYER M5 ;
        RECT  31.632 103.572 31.656 103.656 ;
    END
  END a_d[52]
  PIN a_d[53]
    DIRECTION OUTPUT ;
    USE SIGNAL ;
    PORT
      LAYER M5 ;
        RECT  31.728 103.572 31.752 103.656 ;
    END
  END a_d[53]
  PIN a_d[54]
    DIRECTION OUTPUT ;
    USE SIGNAL ;
    PORT
      LAYER M5 ;
        RECT  31.824 103.572 31.848 103.656 ;
    END
  END a_d[54]
  PIN a_d[55]
    DIRECTION OUTPUT ;
    USE SIGNAL ;
    PORT
      LAYER M5 ;
        RECT  31.92 103.572 31.944 103.656 ;
    END
  END a_d[55]
  PIN a_d[56]
    DIRECTION OUTPUT ;
    USE SIGNAL ;
    PORT
      LAYER M5 ;
        RECT  32.016 103.572 32.04 103.656 ;
    END
  END a_d[56]
  PIN a_d[57]
    DIRECTION OUTPUT ;
    USE SIGNAL ;
    PORT
      LAYER M5 ;
        RECT  32.112 103.572 32.136 103.656 ;
    END
  END a_d[57]
  PIN a_d[58]
    DIRECTION OUTPUT ;
    USE SIGNAL ;
    PORT
      LAYER M5 ;
        RECT  32.208 103.572 32.232 103.656 ;
    END
  END a_d[58]
  PIN a_d[59]
    DIRECTION OUTPUT ;
    USE SIGNAL ;
    PORT
      LAYER M5 ;
        RECT  32.304 103.572 32.328 103.656 ;
    END
  END a_d[59]
  PIN a_d[5]
    DIRECTION OUTPUT ;
    USE SIGNAL ;
    PORT
      LAYER M5 ;
        RECT  20.976 103.572 21 103.656 ;
    END
  END a_d[5]
  PIN a_d[60]
    DIRECTION OUTPUT ;
    USE SIGNAL ;
    PORT
      LAYER M5 ;
        RECT  32.4 103.572 32.424 103.656 ;
    END
  END a_d[60]
  PIN a_d[61]
    DIRECTION OUTPUT ;
    USE SIGNAL ;
    PORT
      LAYER M5 ;
        RECT  32.496 103.572 32.52 103.656 ;
    END
  END a_d[61]
  PIN a_d[62]
    DIRECTION OUTPUT ;
    USE SIGNAL ;
    PORT
      LAYER M5 ;
        RECT  32.592 103.572 32.616 103.656 ;
    END
  END a_d[62]
  PIN a_d[63]
    DIRECTION OUTPUT ;
    USE SIGNAL ;
    PORT
      LAYER M5 ;
        RECT  32.688 103.572 32.712 103.656 ;
    END
  END a_d[63]
  PIN a_d[64]
    DIRECTION OUTPUT ;
    USE SIGNAL ;
    PORT
      LAYER M5 ;
        RECT  26.64 103.572 26.664 103.656 ;
    END
  END a_d[64]
  PIN a_d[65]
    DIRECTION OUTPUT ;
    USE SIGNAL ;
    PORT
      LAYER M5 ;
        RECT  26.736 103.572 26.76 103.656 ;
    END
  END a_d[65]
  PIN a_d[66]
    DIRECTION OUTPUT ;
    USE SIGNAL ;
    PORT
      LAYER M5 ;
        RECT  26.832 103.572 26.856 103.656 ;
    END
  END a_d[66]
  PIN a_d[67]
    DIRECTION OUTPUT ;
    USE SIGNAL ;
    PORT
      LAYER M5 ;
        RECT  26.928 103.572 26.952 103.656 ;
    END
  END a_d[67]
  PIN a_d[68]
    DIRECTION OUTPUT ;
    USE SIGNAL ;
    PORT
      LAYER M5 ;
        RECT  27.024 103.572 27.048 103.656 ;
    END
  END a_d[68]
  PIN a_d[69]
    DIRECTION OUTPUT ;
    USE SIGNAL ;
    PORT
      LAYER M5 ;
        RECT  27.12 103.572 27.144 103.656 ;
    END
  END a_d[69]
  PIN a_d[6]
    DIRECTION OUTPUT ;
    USE SIGNAL ;
    PORT
      LAYER M5 ;
        RECT  21.072 103.572 21.096 103.656 ;
    END
  END a_d[6]
  PIN a_d[70]
    DIRECTION OUTPUT ;
    USE SIGNAL ;
    PORT
      LAYER M5 ;
        RECT  27.216 103.572 27.24 103.656 ;
    END
  END a_d[70]
  PIN a_d[71]
    DIRECTION OUTPUT ;
    USE SIGNAL ;
    PORT
      LAYER M5 ;
        RECT  27.312 103.572 27.336 103.656 ;
    END
  END a_d[71]
  PIN a_d[72]
    DIRECTION OUTPUT ;
    USE SIGNAL ;
    PORT
      LAYER M5 ;
        RECT  27.408 103.572 27.432 103.656 ;
    END
  END a_d[72]
  PIN a_d[73]
    DIRECTION OUTPUT ;
    USE SIGNAL ;
    PORT
      LAYER M5 ;
        RECT  27.504 103.572 27.528 103.656 ;
    END
  END a_d[73]
  PIN a_d[74]
    DIRECTION OUTPUT ;
    USE SIGNAL ;
    PORT
      LAYER M5 ;
        RECT  27.6 103.572 27.624 103.656 ;
    END
  END a_d[74]
  PIN a_d[75]
    DIRECTION OUTPUT ;
    USE SIGNAL ;
    PORT
      LAYER M5 ;
        RECT  27.696 103.572 27.72 103.656 ;
    END
  END a_d[75]
  PIN a_d[76]
    DIRECTION OUTPUT ;
    USE SIGNAL ;
    PORT
      LAYER M5 ;
        RECT  27.792 103.572 27.816 103.656 ;
    END
  END a_d[76]
  PIN a_d[77]
    DIRECTION OUTPUT ;
    USE SIGNAL ;
    PORT
      LAYER M5 ;
        RECT  27.888 103.572 27.912 103.656 ;
    END
  END a_d[77]
  PIN a_d[78]
    DIRECTION OUTPUT ;
    USE SIGNAL ;
    PORT
      LAYER M5 ;
        RECT  27.984 103.572 28.008 103.656 ;
    END
  END a_d[78]
  PIN a_d[79]
    DIRECTION OUTPUT ;
    USE SIGNAL ;
    PORT
      LAYER M5 ;
        RECT  28.08 103.572 28.104 103.656 ;
    END
  END a_d[79]
  PIN a_d[7]
    DIRECTION OUTPUT ;
    USE SIGNAL ;
    PORT
      LAYER M5 ;
        RECT  21.168 103.572 21.192 103.656 ;
    END
  END a_d[7]
  PIN a_d[80]
    DIRECTION OUTPUT ;
    USE SIGNAL ;
    PORT
      LAYER M5 ;
        RECT  28.176 103.572 28.2 103.656 ;
    END
  END a_d[80]
  PIN a_d[81]
    DIRECTION OUTPUT ;
    USE SIGNAL ;
    PORT
      LAYER M5 ;
        RECT  28.272 103.572 28.296 103.656 ;
    END
  END a_d[81]
  PIN a_d[82]
    DIRECTION OUTPUT ;
    USE SIGNAL ;
    PORT
      LAYER M5 ;
        RECT  28.368 103.572 28.392 103.656 ;
    END
  END a_d[82]
  PIN a_d[83]
    DIRECTION OUTPUT ;
    USE SIGNAL ;
    PORT
      LAYER M5 ;
        RECT  28.464 103.572 28.488 103.656 ;
    END
  END a_d[83]
  PIN a_d[84]
    DIRECTION OUTPUT ;
    USE SIGNAL ;
    PORT
      LAYER M5 ;
        RECT  28.56 103.572 28.584 103.656 ;
    END
  END a_d[84]
  PIN a_d[85]
    DIRECTION OUTPUT ;
    USE SIGNAL ;
    PORT
      LAYER M5 ;
        RECT  28.656 103.572 28.68 103.656 ;
    END
  END a_d[85]
  PIN a_d[86]
    DIRECTION OUTPUT ;
    USE SIGNAL ;
    PORT
      LAYER M5 ;
        RECT  28.752 103.572 28.776 103.656 ;
    END
  END a_d[86]
  PIN a_d[87]
    DIRECTION OUTPUT ;
    USE SIGNAL ;
    PORT
      LAYER M5 ;
        RECT  28.848 103.572 28.872 103.656 ;
    END
  END a_d[87]
  PIN a_d[88]
    DIRECTION OUTPUT ;
    USE SIGNAL ;
    PORT
      LAYER M5 ;
        RECT  28.944 103.572 28.968 103.656 ;
    END
  END a_d[88]
  PIN a_d[89]
    DIRECTION OUTPUT ;
    USE SIGNAL ;
    PORT
      LAYER M5 ;
        RECT  29.04 103.572 29.064 103.656 ;
    END
  END a_d[89]
  PIN a_d[8]
    DIRECTION OUTPUT ;
    USE SIGNAL ;
    PORT
      LAYER M5 ;
        RECT  21.264 103.572 21.288 103.656 ;
    END
  END a_d[8]
  PIN a_d[90]
    DIRECTION OUTPUT ;
    USE SIGNAL ;
    PORT
      LAYER M5 ;
        RECT  29.136 103.572 29.16 103.656 ;
    END
  END a_d[90]
  PIN a_d[91]
    DIRECTION OUTPUT ;
    USE SIGNAL ;
    PORT
      LAYER M5 ;
        RECT  29.232 103.572 29.256 103.656 ;
    END
  END a_d[91]
  PIN a_d[92]
    DIRECTION OUTPUT ;
    USE SIGNAL ;
    PORT
      LAYER M5 ;
        RECT  29.328 103.572 29.352 103.656 ;
    END
  END a_d[92]
  PIN a_d[93]
    DIRECTION OUTPUT ;
    USE SIGNAL ;
    PORT
      LAYER M5 ;
        RECT  29.424 103.572 29.448 103.656 ;
    END
  END a_d[93]
  PIN a_d[94]
    DIRECTION OUTPUT ;
    USE SIGNAL ;
    PORT
      LAYER M5 ;
        RECT  29.52 103.572 29.544 103.656 ;
    END
  END a_d[94]
  PIN a_d[95]
    DIRECTION OUTPUT ;
    USE SIGNAL ;
    PORT
      LAYER M5 ;
        RECT  29.616 103.572 29.64 103.656 ;
    END
  END a_d[95]
  PIN a_d[96]
    DIRECTION OUTPUT ;
    USE SIGNAL ;
    PORT
      LAYER M5 ;
        RECT  23.568 103.572 23.592 103.656 ;
    END
  END a_d[96]
  PIN a_d[97]
    DIRECTION OUTPUT ;
    USE SIGNAL ;
    PORT
      LAYER M5 ;
        RECT  23.664 103.572 23.688 103.656 ;
    END
  END a_d[97]
  PIN a_d[98]
    DIRECTION OUTPUT ;
    USE SIGNAL ;
    PORT
      LAYER M5 ;
        RECT  23.76 103.572 23.784 103.656 ;
    END
  END a_d[98]
  PIN a_d[99]
    DIRECTION OUTPUT ;
    USE SIGNAL ;
    PORT
      LAYER M5 ;
        RECT  23.856 103.572 23.88 103.656 ;
    END
  END a_d[99]
  PIN a_d[9]
    DIRECTION OUTPUT ;
    USE SIGNAL ;
    PORT
      LAYER M5 ;
        RECT  21.36 103.572 21.384 103.656 ;
    END
  END a_d[9]
  PIN a_r
    DIRECTION INPUT ;
    USE SIGNAL ;
    PORT
      LAYER M5 ;
        RECT  4.08 103.572 4.104 103.656 ;
    END
  END a_r
  PIN b_d[0]
    DIRECTION INPUT ;
    USE SIGNAL ;
    PORT
      LAYER M5 ;
        RECT  26.064 0 26.088 0.084 ;
    END
  END b_d[0]
  PIN b_d[100]
    DIRECTION INPUT ;
    USE SIGNAL ;
    PORT
      LAYER M5 ;
        RECT  32.592 0 32.616 0.084 ;
    END
  END b_d[100]
  PIN b_d[101]
    DIRECTION INPUT ;
    USE SIGNAL ;
    PORT
      LAYER M5 ;
        RECT  32.688 0 32.712 0.084 ;
    END
  END b_d[101]
  PIN b_d[102]
    DIRECTION INPUT ;
    USE SIGNAL ;
    PORT
      LAYER M5 ;
        RECT  32.784 0 32.808 0.084 ;
    END
  END b_d[102]
  PIN b_d[103]
    DIRECTION INPUT ;
    USE SIGNAL ;
    PORT
      LAYER M5 ;
        RECT  32.88 0 32.904 0.084 ;
    END
  END b_d[103]
  PIN b_d[104]
    DIRECTION INPUT ;
    USE SIGNAL ;
    PORT
      LAYER M5 ;
        RECT  32.976 0 33 0.084 ;
    END
  END b_d[104]
  PIN b_d[105]
    DIRECTION INPUT ;
    USE SIGNAL ;
    PORT
      LAYER M5 ;
        RECT  33.072 0 33.096 0.084 ;
    END
  END b_d[105]
  PIN b_d[106]
    DIRECTION INPUT ;
    USE SIGNAL ;
    PORT
      LAYER M5 ;
        RECT  33.168 0 33.192 0.084 ;
    END
  END b_d[106]
  PIN b_d[107]
    DIRECTION INPUT ;
    USE SIGNAL ;
    PORT
      LAYER M5 ;
        RECT  33.264 0 33.288 0.084 ;
    END
  END b_d[107]
  PIN b_d[108]
    DIRECTION INPUT ;
    USE SIGNAL ;
    PORT
      LAYER M5 ;
        RECT  33.36 0 33.384 0.084 ;
    END
  END b_d[108]
  PIN b_d[109]
    DIRECTION INPUT ;
    USE SIGNAL ;
    PORT
      LAYER M5 ;
        RECT  33.456 0 33.48 0.084 ;
    END
  END b_d[109]
  PIN b_d[10]
    DIRECTION INPUT ;
    USE SIGNAL ;
    PORT
      LAYER M5 ;
        RECT  27.024 0 27.048 0.084 ;
    END
  END b_d[10]
  PIN b_d[110]
    DIRECTION INPUT ;
    USE SIGNAL ;
    PORT
      LAYER M5 ;
        RECT  33.552 0 33.576 0.084 ;
    END
  END b_d[110]
  PIN b_d[111]
    DIRECTION INPUT ;
    USE SIGNAL ;
    PORT
      LAYER M5 ;
        RECT  33.648 0 33.672 0.084 ;
    END
  END b_d[111]
  PIN b_d[112]
    DIRECTION INPUT ;
    USE SIGNAL ;
    PORT
      LAYER M5 ;
        RECT  33.744 0 33.768 0.084 ;
    END
  END b_d[112]
  PIN b_d[113]
    DIRECTION INPUT ;
    USE SIGNAL ;
    PORT
      LAYER M5 ;
        RECT  33.84 0 33.864 0.084 ;
    END
  END b_d[113]
  PIN b_d[114]
    DIRECTION INPUT ;
    USE SIGNAL ;
    PORT
      LAYER M5 ;
        RECT  33.936 0 33.96 0.084 ;
    END
  END b_d[114]
  PIN b_d[115]
    DIRECTION INPUT ;
    USE SIGNAL ;
    PORT
      LAYER M5 ;
        RECT  34.032 0 34.056 0.084 ;
    END
  END b_d[115]
  PIN b_d[116]
    DIRECTION INPUT ;
    USE SIGNAL ;
    PORT
      LAYER M5 ;
        RECT  34.128 0 34.152 0.084 ;
    END
  END b_d[116]
  PIN b_d[117]
    DIRECTION INPUT ;
    USE SIGNAL ;
    PORT
      LAYER M5 ;
        RECT  34.224 0 34.248 0.084 ;
    END
  END b_d[117]
  PIN b_d[118]
    DIRECTION INPUT ;
    USE SIGNAL ;
    PORT
      LAYER M5 ;
        RECT  34.32 0 34.344 0.084 ;
    END
  END b_d[118]
  PIN b_d[119]
    DIRECTION INPUT ;
    USE SIGNAL ;
    PORT
      LAYER M5 ;
        RECT  34.416 0 34.44 0.084 ;
    END
  END b_d[119]
  PIN b_d[11]
    DIRECTION INPUT ;
    USE SIGNAL ;
    PORT
      LAYER M5 ;
        RECT  27.12 0 27.144 0.084 ;
    END
  END b_d[11]
  PIN b_d[120]
    DIRECTION INPUT ;
    USE SIGNAL ;
    PORT
      LAYER M5 ;
        RECT  34.512 0 34.536 0.084 ;
    END
  END b_d[120]
  PIN b_d[121]
    DIRECTION INPUT ;
    USE SIGNAL ;
    PORT
      LAYER M5 ;
        RECT  34.608 0 34.632 0.084 ;
    END
  END b_d[121]
  PIN b_d[122]
    DIRECTION INPUT ;
    USE SIGNAL ;
    PORT
      LAYER M5 ;
        RECT  34.704 0 34.728 0.084 ;
    END
  END b_d[122]
  PIN b_d[123]
    DIRECTION INPUT ;
    USE SIGNAL ;
    PORT
      LAYER M5 ;
        RECT  34.8 0 34.824 0.084 ;
    END
  END b_d[123]
  PIN b_d[124]
    DIRECTION INPUT ;
    USE SIGNAL ;
    PORT
      LAYER M5 ;
        RECT  34.896 0 34.92 0.084 ;
    END
  END b_d[124]
  PIN b_d[125]
    DIRECTION INPUT ;
    USE SIGNAL ;
    PORT
      LAYER M5 ;
        RECT  34.992 0 35.016 0.084 ;
    END
  END b_d[125]
  PIN b_d[126]
    DIRECTION INPUT ;
    USE SIGNAL ;
    PORT
      LAYER M5 ;
        RECT  35.088 0 35.112 0.084 ;
    END
  END b_d[126]
  PIN b_d[127]
    DIRECTION INPUT ;
    USE SIGNAL ;
    PORT
      LAYER M5 ;
        RECT  35.184 0 35.208 0.084 ;
    END
  END b_d[127]
  PIN b_d[128]
    DIRECTION INPUT ;
    USE SIGNAL ;
    PORT
      LAYER M5 ;
        RECT  19.92 0 19.944 0.084 ;
    END
  END b_d[128]
  PIN b_d[129]
    DIRECTION INPUT ;
    USE SIGNAL ;
    PORT
      LAYER M5 ;
        RECT  20.016 0 20.04 0.084 ;
    END
  END b_d[129]
  PIN b_d[12]
    DIRECTION INPUT ;
    USE SIGNAL ;
    PORT
      LAYER M5 ;
        RECT  27.216 0 27.24 0.084 ;
    END
  END b_d[12]
  PIN b_d[130]
    DIRECTION INPUT ;
    USE SIGNAL ;
    PORT
      LAYER M5 ;
        RECT  20.112 0 20.136 0.084 ;
    END
  END b_d[130]
  PIN b_d[131]
    DIRECTION INPUT ;
    USE SIGNAL ;
    PORT
      LAYER M5 ;
        RECT  20.208 0 20.232 0.084 ;
    END
  END b_d[131]
  PIN b_d[132]
    DIRECTION INPUT ;
    USE SIGNAL ;
    PORT
      LAYER M5 ;
        RECT  20.304 0 20.328 0.084 ;
    END
  END b_d[132]
  PIN b_d[133]
    DIRECTION INPUT ;
    USE SIGNAL ;
    PORT
      LAYER M5 ;
        RECT  20.4 0 20.424 0.084 ;
    END
  END b_d[133]
  PIN b_d[134]
    DIRECTION INPUT ;
    USE SIGNAL ;
    PORT
      LAYER M5 ;
        RECT  20.496 0 20.52 0.084 ;
    END
  END b_d[134]
  PIN b_d[135]
    DIRECTION INPUT ;
    USE SIGNAL ;
    PORT
      LAYER M5 ;
        RECT  20.592 0 20.616 0.084 ;
    END
  END b_d[135]
  PIN b_d[136]
    DIRECTION INPUT ;
    USE SIGNAL ;
    PORT
      LAYER M5 ;
        RECT  20.688 0 20.712 0.084 ;
    END
  END b_d[136]
  PIN b_d[137]
    DIRECTION INPUT ;
    USE SIGNAL ;
    PORT
      LAYER M5 ;
        RECT  20.784 0 20.808 0.084 ;
    END
  END b_d[137]
  PIN b_d[138]
    DIRECTION INPUT ;
    USE SIGNAL ;
    PORT
      LAYER M5 ;
        RECT  20.88 0 20.904 0.084 ;
    END
  END b_d[138]
  PIN b_d[139]
    DIRECTION INPUT ;
    USE SIGNAL ;
    PORT
      LAYER M5 ;
        RECT  20.976 0 21 0.084 ;
    END
  END b_d[139]
  PIN b_d[13]
    DIRECTION INPUT ;
    USE SIGNAL ;
    PORT
      LAYER M5 ;
        RECT  27.312 0 27.336 0.084 ;
    END
  END b_d[13]
  PIN b_d[140]
    DIRECTION INPUT ;
    USE SIGNAL ;
    PORT
      LAYER M5 ;
        RECT  21.072 0 21.096 0.084 ;
    END
  END b_d[140]
  PIN b_d[141]
    DIRECTION INPUT ;
    USE SIGNAL ;
    PORT
      LAYER M5 ;
        RECT  21.168 0 21.192 0.084 ;
    END
  END b_d[141]
  PIN b_d[142]
    DIRECTION INPUT ;
    USE SIGNAL ;
    PORT
      LAYER M5 ;
        RECT  21.264 0 21.288 0.084 ;
    END
  END b_d[142]
  PIN b_d[143]
    DIRECTION INPUT ;
    USE SIGNAL ;
    PORT
      LAYER M5 ;
        RECT  21.36 0 21.384 0.084 ;
    END
  END b_d[143]
  PIN b_d[144]
    DIRECTION INPUT ;
    USE SIGNAL ;
    PORT
      LAYER M5 ;
        RECT  21.456 0 21.48 0.084 ;
    END
  END b_d[144]
  PIN b_d[145]
    DIRECTION INPUT ;
    USE SIGNAL ;
    PORT
      LAYER M5 ;
        RECT  21.552 0 21.576 0.084 ;
    END
  END b_d[145]
  PIN b_d[146]
    DIRECTION INPUT ;
    USE SIGNAL ;
    PORT
      LAYER M5 ;
        RECT  21.648 0 21.672 0.084 ;
    END
  END b_d[146]
  PIN b_d[147]
    DIRECTION INPUT ;
    USE SIGNAL ;
    PORT
      LAYER M5 ;
        RECT  21.744 0 21.768 0.084 ;
    END
  END b_d[147]
  PIN b_d[148]
    DIRECTION INPUT ;
    USE SIGNAL ;
    PORT
      LAYER M5 ;
        RECT  21.84 0 21.864 0.084 ;
    END
  END b_d[148]
  PIN b_d[149]
    DIRECTION INPUT ;
    USE SIGNAL ;
    PORT
      LAYER M5 ;
        RECT  21.936 0 21.96 0.084 ;
    END
  END b_d[149]
  PIN b_d[14]
    DIRECTION INPUT ;
    USE SIGNAL ;
    PORT
      LAYER M5 ;
        RECT  27.408 0 27.432 0.084 ;
    END
  END b_d[14]
  PIN b_d[150]
    DIRECTION INPUT ;
    USE SIGNAL ;
    PORT
      LAYER M5 ;
        RECT  22.032 0 22.056 0.084 ;
    END
  END b_d[150]
  PIN b_d[151]
    DIRECTION INPUT ;
    USE SIGNAL ;
    PORT
      LAYER M5 ;
        RECT  22.128 0 22.152 0.084 ;
    END
  END b_d[151]
  PIN b_d[152]
    DIRECTION INPUT ;
    USE SIGNAL ;
    PORT
      LAYER M5 ;
        RECT  22.224 0 22.248 0.084 ;
    END
  END b_d[152]
  PIN b_d[153]
    DIRECTION INPUT ;
    USE SIGNAL ;
    PORT
      LAYER M5 ;
        RECT  22.32 0 22.344 0.084 ;
    END
  END b_d[153]
  PIN b_d[154]
    DIRECTION INPUT ;
    USE SIGNAL ;
    PORT
      LAYER M5 ;
        RECT  22.416 0 22.44 0.084 ;
    END
  END b_d[154]
  PIN b_d[155]
    DIRECTION INPUT ;
    USE SIGNAL ;
    PORT
      LAYER M5 ;
        RECT  22.512 0 22.536 0.084 ;
    END
  END b_d[155]
  PIN b_d[156]
    DIRECTION INPUT ;
    USE SIGNAL ;
    PORT
      LAYER M5 ;
        RECT  22.608 0 22.632 0.084 ;
    END
  END b_d[156]
  PIN b_d[157]
    DIRECTION INPUT ;
    USE SIGNAL ;
    PORT
      LAYER M5 ;
        RECT  22.704 0 22.728 0.084 ;
    END
  END b_d[157]
  PIN b_d[158]
    DIRECTION INPUT ;
    USE SIGNAL ;
    PORT
      LAYER M5 ;
        RECT  22.8 0 22.824 0.084 ;
    END
  END b_d[158]
  PIN b_d[159]
    DIRECTION INPUT ;
    USE SIGNAL ;
    PORT
      LAYER M5 ;
        RECT  22.896 0 22.92 0.084 ;
    END
  END b_d[159]
  PIN b_d[15]
    DIRECTION INPUT ;
    USE SIGNAL ;
    PORT
      LAYER M5 ;
        RECT  27.504 0 27.528 0.084 ;
    END
  END b_d[15]
  PIN b_d[160]
    DIRECTION INPUT ;
    USE SIGNAL ;
    PORT
      LAYER M5 ;
        RECT  22.992 0 23.016 0.084 ;
    END
  END b_d[160]
  PIN b_d[161]
    DIRECTION INPUT ;
    USE SIGNAL ;
    PORT
      LAYER M5 ;
        RECT  23.088 0 23.112 0.084 ;
    END
  END b_d[161]
  PIN b_d[162]
    DIRECTION INPUT ;
    USE SIGNAL ;
    PORT
      LAYER M5 ;
        RECT  23.184 0 23.208 0.084 ;
    END
  END b_d[162]
  PIN b_d[163]
    DIRECTION INPUT ;
    USE SIGNAL ;
    PORT
      LAYER M5 ;
        RECT  23.28 0 23.304 0.084 ;
    END
  END b_d[163]
  PIN b_d[164]
    DIRECTION INPUT ;
    USE SIGNAL ;
    PORT
      LAYER M5 ;
        RECT  23.376 0 23.4 0.084 ;
    END
  END b_d[164]
  PIN b_d[165]
    DIRECTION INPUT ;
    USE SIGNAL ;
    PORT
      LAYER M5 ;
        RECT  23.472 0 23.496 0.084 ;
    END
  END b_d[165]
  PIN b_d[166]
    DIRECTION INPUT ;
    USE SIGNAL ;
    PORT
      LAYER M5 ;
        RECT  23.568 0 23.592 0.084 ;
    END
  END b_d[166]
  PIN b_d[167]
    DIRECTION INPUT ;
    USE SIGNAL ;
    PORT
      LAYER M5 ;
        RECT  23.664 0 23.688 0.084 ;
    END
  END b_d[167]
  PIN b_d[168]
    DIRECTION INPUT ;
    USE SIGNAL ;
    PORT
      LAYER M5 ;
        RECT  23.76 0 23.784 0.084 ;
    END
  END b_d[168]
  PIN b_d[169]
    DIRECTION INPUT ;
    USE SIGNAL ;
    PORT
      LAYER M5 ;
        RECT  23.856 0 23.88 0.084 ;
    END
  END b_d[169]
  PIN b_d[16]
    DIRECTION INPUT ;
    USE SIGNAL ;
    PORT
      LAYER M5 ;
        RECT  27.6 0 27.624 0.084 ;
    END
  END b_d[16]
  PIN b_d[170]
    DIRECTION INPUT ;
    USE SIGNAL ;
    PORT
      LAYER M5 ;
        RECT  23.952 0 23.976 0.084 ;
    END
  END b_d[170]
  PIN b_d[171]
    DIRECTION INPUT ;
    USE SIGNAL ;
    PORT
      LAYER M5 ;
        RECT  24.048 0 24.072 0.084 ;
    END
  END b_d[171]
  PIN b_d[172]
    DIRECTION INPUT ;
    USE SIGNAL ;
    PORT
      LAYER M5 ;
        RECT  24.144 0 24.168 0.084 ;
    END
  END b_d[172]
  PIN b_d[173]
    DIRECTION INPUT ;
    USE SIGNAL ;
    PORT
      LAYER M5 ;
        RECT  24.24 0 24.264 0.084 ;
    END
  END b_d[173]
  PIN b_d[174]
    DIRECTION INPUT ;
    USE SIGNAL ;
    PORT
      LAYER M5 ;
        RECT  24.336 0 24.36 0.084 ;
    END
  END b_d[174]
  PIN b_d[175]
    DIRECTION INPUT ;
    USE SIGNAL ;
    PORT
      LAYER M5 ;
        RECT  24.432 0 24.456 0.084 ;
    END
  END b_d[175]
  PIN b_d[176]
    DIRECTION INPUT ;
    USE SIGNAL ;
    PORT
      LAYER M5 ;
        RECT  24.528 0 24.552 0.084 ;
    END
  END b_d[176]
  PIN b_d[177]
    DIRECTION INPUT ;
    USE SIGNAL ;
    PORT
      LAYER M5 ;
        RECT  24.624 0 24.648 0.084 ;
    END
  END b_d[177]
  PIN b_d[178]
    DIRECTION INPUT ;
    USE SIGNAL ;
    PORT
      LAYER M5 ;
        RECT  24.72 0 24.744 0.084 ;
    END
  END b_d[178]
  PIN b_d[179]
    DIRECTION INPUT ;
    USE SIGNAL ;
    PORT
      LAYER M5 ;
        RECT  24.816 0 24.84 0.084 ;
    END
  END b_d[179]
  PIN b_d[17]
    DIRECTION INPUT ;
    USE SIGNAL ;
    PORT
      LAYER M5 ;
        RECT  27.696 0 27.72 0.084 ;
    END
  END b_d[17]
  PIN b_d[180]
    DIRECTION INPUT ;
    USE SIGNAL ;
    PORT
      LAYER M5 ;
        RECT  24.912 0 24.936 0.084 ;
    END
  END b_d[180]
  PIN b_d[181]
    DIRECTION INPUT ;
    USE SIGNAL ;
    PORT
      LAYER M5 ;
        RECT  25.008 0 25.032 0.084 ;
    END
  END b_d[181]
  PIN b_d[182]
    DIRECTION INPUT ;
    USE SIGNAL ;
    PORT
      LAYER M5 ;
        RECT  25.104 0 25.128 0.084 ;
    END
  END b_d[182]
  PIN b_d[183]
    DIRECTION INPUT ;
    USE SIGNAL ;
    PORT
      LAYER M5 ;
        RECT  25.2 0 25.224 0.084 ;
    END
  END b_d[183]
  PIN b_d[184]
    DIRECTION INPUT ;
    USE SIGNAL ;
    PORT
      LAYER M5 ;
        RECT  25.296 0 25.32 0.084 ;
    END
  END b_d[184]
  PIN b_d[185]
    DIRECTION INPUT ;
    USE SIGNAL ;
    PORT
      LAYER M5 ;
        RECT  25.392 0 25.416 0.084 ;
    END
  END b_d[185]
  PIN b_d[186]
    DIRECTION INPUT ;
    USE SIGNAL ;
    PORT
      LAYER M5 ;
        RECT  25.488 0 25.512 0.084 ;
    END
  END b_d[186]
  PIN b_d[187]
    DIRECTION INPUT ;
    USE SIGNAL ;
    PORT
      LAYER M5 ;
        RECT  25.584 0 25.608 0.084 ;
    END
  END b_d[187]
  PIN b_d[188]
    DIRECTION INPUT ;
    USE SIGNAL ;
    PORT
      LAYER M5 ;
        RECT  25.68 0 25.704 0.084 ;
    END
  END b_d[188]
  PIN b_d[189]
    DIRECTION INPUT ;
    USE SIGNAL ;
    PORT
      LAYER M5 ;
        RECT  25.776 0 25.8 0.084 ;
    END
  END b_d[189]
  PIN b_d[18]
    DIRECTION INPUT ;
    USE SIGNAL ;
    PORT
      LAYER M5 ;
        RECT  27.792 0 27.816 0.084 ;
    END
  END b_d[18]
  PIN b_d[190]
    DIRECTION INPUT ;
    USE SIGNAL ;
    PORT
      LAYER M5 ;
        RECT  25.872 0 25.896 0.084 ;
    END
  END b_d[190]
  PIN b_d[191]
    DIRECTION INPUT ;
    USE SIGNAL ;
    PORT
      LAYER M5 ;
        RECT  25.968 0 25.992 0.084 ;
    END
  END b_d[191]
  PIN b_d[192]
    DIRECTION INPUT ;
    USE SIGNAL ;
    PORT
      LAYER M5 ;
        RECT  0.72 0 0.744 0.084 ;
    END
  END b_d[192]
  PIN b_d[193]
    DIRECTION INPUT ;
    USE SIGNAL ;
    PORT
      LAYER M5 ;
        RECT  0.816 0 0.84 0.084 ;
    END
  END b_d[193]
  PIN b_d[194]
    DIRECTION INPUT ;
    USE SIGNAL ;
    PORT
      LAYER M5 ;
        RECT  0.912 0 0.936 0.084 ;
    END
  END b_d[194]
  PIN b_d[195]
    DIRECTION INPUT ;
    USE SIGNAL ;
    PORT
      LAYER M5 ;
        RECT  1.008 0 1.032 0.084 ;
    END
  END b_d[195]
  PIN b_d[196]
    DIRECTION INPUT ;
    USE SIGNAL ;
    PORT
      LAYER M5 ;
        RECT  1.104 0 1.128 0.084 ;
    END
  END b_d[196]
  PIN b_d[197]
    DIRECTION INPUT ;
    USE SIGNAL ;
    PORT
      LAYER M5 ;
        RECT  1.2 0 1.224 0.084 ;
    END
  END b_d[197]
  PIN b_d[198]
    DIRECTION INPUT ;
    USE SIGNAL ;
    PORT
      LAYER M5 ;
        RECT  1.296 0 1.32 0.084 ;
    END
  END b_d[198]
  PIN b_d[199]
    DIRECTION INPUT ;
    USE SIGNAL ;
    PORT
      LAYER M5 ;
        RECT  1.392 0 1.416 0.084 ;
    END
  END b_d[199]
  PIN b_d[19]
    DIRECTION INPUT ;
    USE SIGNAL ;
    PORT
      LAYER M5 ;
        RECT  27.888 0 27.912 0.084 ;
    END
  END b_d[19]
  PIN b_d[1]
    DIRECTION INPUT ;
    USE SIGNAL ;
    PORT
      LAYER M5 ;
        RECT  26.16 0 26.184 0.084 ;
    END
  END b_d[1]
  PIN b_d[200]
    DIRECTION INPUT ;
    USE SIGNAL ;
    PORT
      LAYER M5 ;
        RECT  1.488 0 1.512 0.084 ;
    END
  END b_d[200]
  PIN b_d[201]
    DIRECTION INPUT ;
    USE SIGNAL ;
    PORT
      LAYER M5 ;
        RECT  1.584 0 1.608 0.084 ;
    END
  END b_d[201]
  PIN b_d[202]
    DIRECTION INPUT ;
    USE SIGNAL ;
    PORT
      LAYER M5 ;
        RECT  1.68 0 1.704 0.084 ;
    END
  END b_d[202]
  PIN b_d[203]
    DIRECTION INPUT ;
    USE SIGNAL ;
    PORT
      LAYER M5 ;
        RECT  1.776 0 1.8 0.084 ;
    END
  END b_d[203]
  PIN b_d[204]
    DIRECTION INPUT ;
    USE SIGNAL ;
    PORT
      LAYER M5 ;
        RECT  1.872 0 1.896 0.084 ;
    END
  END b_d[204]
  PIN b_d[205]
    DIRECTION INPUT ;
    USE SIGNAL ;
    PORT
      LAYER M5 ;
        RECT  1.968 0 1.992 0.084 ;
    END
  END b_d[205]
  PIN b_d[206]
    DIRECTION INPUT ;
    USE SIGNAL ;
    PORT
      LAYER M5 ;
        RECT  2.064 0 2.088 0.084 ;
    END
  END b_d[206]
  PIN b_d[207]
    DIRECTION INPUT ;
    USE SIGNAL ;
    PORT
      LAYER M5 ;
        RECT  2.16 0 2.184 0.084 ;
    END
  END b_d[207]
  PIN b_d[208]
    DIRECTION INPUT ;
    USE SIGNAL ;
    PORT
      LAYER M5 ;
        RECT  2.256 0 2.28 0.084 ;
    END
  END b_d[208]
  PIN b_d[209]
    DIRECTION INPUT ;
    USE SIGNAL ;
    PORT
      LAYER M5 ;
        RECT  2.352 0 2.376 0.084 ;
    END
  END b_d[209]
  PIN b_d[20]
    DIRECTION INPUT ;
    USE SIGNAL ;
    PORT
      LAYER M5 ;
        RECT  27.984 0 28.008 0.084 ;
    END
  END b_d[20]
  PIN b_d[210]
    DIRECTION INPUT ;
    USE SIGNAL ;
    PORT
      LAYER M5 ;
        RECT  2.448 0 2.472 0.084 ;
    END
  END b_d[210]
  PIN b_d[211]
    DIRECTION INPUT ;
    USE SIGNAL ;
    PORT
      LAYER M5 ;
        RECT  2.544 0 2.568 0.084 ;
    END
  END b_d[211]
  PIN b_d[212]
    DIRECTION INPUT ;
    USE SIGNAL ;
    PORT
      LAYER M5 ;
        RECT  2.64 0 2.664 0.084 ;
    END
  END b_d[212]
  PIN b_d[213]
    DIRECTION INPUT ;
    USE SIGNAL ;
    PORT
      LAYER M5 ;
        RECT  2.736 0 2.76 0.084 ;
    END
  END b_d[213]
  PIN b_d[214]
    DIRECTION INPUT ;
    USE SIGNAL ;
    PORT
      LAYER M5 ;
        RECT  2.832 0 2.856 0.084 ;
    END
  END b_d[214]
  PIN b_d[215]
    DIRECTION INPUT ;
    USE SIGNAL ;
    PORT
      LAYER M5 ;
        RECT  2.928 0 2.952 0.084 ;
    END
  END b_d[215]
  PIN b_d[216]
    DIRECTION INPUT ;
    USE SIGNAL ;
    PORT
      LAYER M5 ;
        RECT  3.024 0 3.048 0.084 ;
    END
  END b_d[216]
  PIN b_d[217]
    DIRECTION INPUT ;
    USE SIGNAL ;
    PORT
      LAYER M5 ;
        RECT  3.12 0 3.144 0.084 ;
    END
  END b_d[217]
  PIN b_d[218]
    DIRECTION INPUT ;
    USE SIGNAL ;
    PORT
      LAYER M5 ;
        RECT  3.216 0 3.24 0.084 ;
    END
  END b_d[218]
  PIN b_d[219]
    DIRECTION INPUT ;
    USE SIGNAL ;
    PORT
      LAYER M5 ;
        RECT  3.312 0 3.336 0.084 ;
    END
  END b_d[219]
  PIN b_d[21]
    DIRECTION INPUT ;
    USE SIGNAL ;
    PORT
      LAYER M5 ;
        RECT  28.08 0 28.104 0.084 ;
    END
  END b_d[21]
  PIN b_d[220]
    DIRECTION INPUT ;
    USE SIGNAL ;
    PORT
      LAYER M5 ;
        RECT  3.408 0 3.432 0.084 ;
    END
  END b_d[220]
  PIN b_d[221]
    DIRECTION INPUT ;
    USE SIGNAL ;
    PORT
      LAYER M5 ;
        RECT  3.504 0 3.528 0.084 ;
    END
  END b_d[221]
  PIN b_d[222]
    DIRECTION INPUT ;
    USE SIGNAL ;
    PORT
      LAYER M5 ;
        RECT  3.6 0 3.624 0.084 ;
    END
  END b_d[222]
  PIN b_d[223]
    DIRECTION INPUT ;
    USE SIGNAL ;
    PORT
      LAYER M5 ;
        RECT  3.696 0 3.72 0.084 ;
    END
  END b_d[223]
  PIN b_d[224]
    DIRECTION INPUT ;
    USE SIGNAL ;
    PORT
      LAYER M5 ;
        RECT  9.936 0 9.96 0.084 ;
    END
  END b_d[224]
  PIN b_d[225]
    DIRECTION INPUT ;
    USE SIGNAL ;
    PORT
      LAYER M5 ;
        RECT  10.032 0 10.056 0.084 ;
    END
  END b_d[225]
  PIN b_d[226]
    DIRECTION INPUT ;
    USE SIGNAL ;
    PORT
      LAYER M5 ;
        RECT  10.128 0 10.152 0.084 ;
    END
  END b_d[226]
  PIN b_d[227]
    DIRECTION INPUT ;
    USE SIGNAL ;
    PORT
      LAYER M5 ;
        RECT  10.224 0 10.248 0.084 ;
    END
  END b_d[227]
  PIN b_d[228]
    DIRECTION INPUT ;
    USE SIGNAL ;
    PORT
      LAYER M5 ;
        RECT  10.32 0 10.344 0.084 ;
    END
  END b_d[228]
  PIN b_d[229]
    DIRECTION INPUT ;
    USE SIGNAL ;
    PORT
      LAYER M5 ;
        RECT  10.416 0 10.44 0.084 ;
    END
  END b_d[229]
  PIN b_d[22]
    DIRECTION INPUT ;
    USE SIGNAL ;
    PORT
      LAYER M5 ;
        RECT  28.176 0 28.2 0.084 ;
    END
  END b_d[22]
  PIN b_d[230]
    DIRECTION INPUT ;
    USE SIGNAL ;
    PORT
      LAYER M5 ;
        RECT  10.512 0 10.536 0.084 ;
    END
  END b_d[230]
  PIN b_d[231]
    DIRECTION INPUT ;
    USE SIGNAL ;
    PORT
      LAYER M5 ;
        RECT  10.608 0 10.632 0.084 ;
    END
  END b_d[231]
  PIN b_d[232]
    DIRECTION INPUT ;
    USE SIGNAL ;
    PORT
      LAYER M5 ;
        RECT  10.704 0 10.728 0.084 ;
    END
  END b_d[232]
  PIN b_d[233]
    DIRECTION INPUT ;
    USE SIGNAL ;
    PORT
      LAYER M5 ;
        RECT  10.8 0 10.824 0.084 ;
    END
  END b_d[233]
  PIN b_d[234]
    DIRECTION INPUT ;
    USE SIGNAL ;
    PORT
      LAYER M5 ;
        RECT  10.896 0 10.92 0.084 ;
    END
  END b_d[234]
  PIN b_d[235]
    DIRECTION INPUT ;
    USE SIGNAL ;
    PORT
      LAYER M5 ;
        RECT  10.992 0 11.016 0.084 ;
    END
  END b_d[235]
  PIN b_d[236]
    DIRECTION INPUT ;
    USE SIGNAL ;
    PORT
      LAYER M5 ;
        RECT  11.088 0 11.112 0.084 ;
    END
  END b_d[236]
  PIN b_d[237]
    DIRECTION INPUT ;
    USE SIGNAL ;
    PORT
      LAYER M5 ;
        RECT  11.184 0 11.208 0.084 ;
    END
  END b_d[237]
  PIN b_d[238]
    DIRECTION INPUT ;
    USE SIGNAL ;
    PORT
      LAYER M5 ;
        RECT  11.28 0 11.304 0.084 ;
    END
  END b_d[238]
  PIN b_d[239]
    DIRECTION INPUT ;
    USE SIGNAL ;
    PORT
      LAYER M5 ;
        RECT  11.376 0 11.4 0.084 ;
    END
  END b_d[239]
  PIN b_d[23]
    DIRECTION INPUT ;
    USE SIGNAL ;
    PORT
      LAYER M5 ;
        RECT  28.272 0 28.296 0.084 ;
    END
  END b_d[23]
  PIN b_d[240]
    DIRECTION INPUT ;
    USE SIGNAL ;
    PORT
      LAYER M5 ;
        RECT  11.472 0 11.496 0.084 ;
    END
  END b_d[240]
  PIN b_d[241]
    DIRECTION INPUT ;
    USE SIGNAL ;
    PORT
      LAYER M5 ;
        RECT  11.568 0 11.592 0.084 ;
    END
  END b_d[241]
  PIN b_d[242]
    DIRECTION INPUT ;
    USE SIGNAL ;
    PORT
      LAYER M5 ;
        RECT  11.664 0 11.688 0.084 ;
    END
  END b_d[242]
  PIN b_d[243]
    DIRECTION INPUT ;
    USE SIGNAL ;
    PORT
      LAYER M5 ;
        RECT  11.76 0 11.784 0.084 ;
    END
  END b_d[243]
  PIN b_d[244]
    DIRECTION INPUT ;
    USE SIGNAL ;
    PORT
      LAYER M5 ;
        RECT  11.856 0 11.88 0.084 ;
    END
  END b_d[244]
  PIN b_d[245]
    DIRECTION INPUT ;
    USE SIGNAL ;
    PORT
      LAYER M5 ;
        RECT  11.952 0 11.976 0.084 ;
    END
  END b_d[245]
  PIN b_d[246]
    DIRECTION INPUT ;
    USE SIGNAL ;
    PORT
      LAYER M5 ;
        RECT  12.048 0 12.072 0.084 ;
    END
  END b_d[246]
  PIN b_d[247]
    DIRECTION INPUT ;
    USE SIGNAL ;
    PORT
      LAYER M5 ;
        RECT  12.144 0 12.168 0.084 ;
    END
  END b_d[247]
  PIN b_d[248]
    DIRECTION INPUT ;
    USE SIGNAL ;
    PORT
      LAYER M5 ;
        RECT  12.24 0 12.264 0.084 ;
    END
  END b_d[248]
  PIN b_d[249]
    DIRECTION INPUT ;
    USE SIGNAL ;
    PORT
      LAYER M5 ;
        RECT  12.336 0 12.36 0.084 ;
    END
  END b_d[249]
  PIN b_d[24]
    DIRECTION INPUT ;
    USE SIGNAL ;
    PORT
      LAYER M5 ;
        RECT  28.368 0 28.392 0.084 ;
    END
  END b_d[24]
  PIN b_d[250]
    DIRECTION INPUT ;
    USE SIGNAL ;
    PORT
      LAYER M5 ;
        RECT  12.432 0 12.456 0.084 ;
    END
  END b_d[250]
  PIN b_d[251]
    DIRECTION INPUT ;
    USE SIGNAL ;
    PORT
      LAYER M5 ;
        RECT  12.528 0 12.552 0.084 ;
    END
  END b_d[251]
  PIN b_d[252]
    DIRECTION INPUT ;
    USE SIGNAL ;
    PORT
      LAYER M5 ;
        RECT  12.624 0 12.648 0.084 ;
    END
  END b_d[252]
  PIN b_d[253]
    DIRECTION INPUT ;
    USE SIGNAL ;
    PORT
      LAYER M5 ;
        RECT  12.72 0 12.744 0.084 ;
    END
  END b_d[253]
  PIN b_d[254]
    DIRECTION INPUT ;
    USE SIGNAL ;
    PORT
      LAYER M5 ;
        RECT  12.816 0 12.84 0.084 ;
    END
  END b_d[254]
  PIN b_d[255]
    DIRECTION INPUT ;
    USE SIGNAL ;
    PORT
      LAYER M5 ;
        RECT  12.912 0 12.936 0.084 ;
    END
  END b_d[255]
  PIN b_d[256]
    DIRECTION INPUT ;
    USE SIGNAL ;
    PORT
      LAYER M5 ;
        RECT  16.08 0 16.104 0.084 ;
    END
  END b_d[256]
  PIN b_d[257]
    DIRECTION INPUT ;
    USE SIGNAL ;
    PORT
      LAYER M5 ;
        RECT  16.176 0 16.2 0.084 ;
    END
  END b_d[257]
  PIN b_d[258]
    DIRECTION INPUT ;
    USE SIGNAL ;
    PORT
      LAYER M5 ;
        RECT  16.272 0 16.296 0.084 ;
    END
  END b_d[258]
  PIN b_d[259]
    DIRECTION INPUT ;
    USE SIGNAL ;
    PORT
      LAYER M5 ;
        RECT  16.368 0 16.392 0.084 ;
    END
  END b_d[259]
  PIN b_d[25]
    DIRECTION INPUT ;
    USE SIGNAL ;
    PORT
      LAYER M5 ;
        RECT  28.464 0 28.488 0.084 ;
    END
  END b_d[25]
  PIN b_d[260]
    DIRECTION INPUT ;
    USE SIGNAL ;
    PORT
      LAYER M5 ;
        RECT  16.464 0 16.488 0.084 ;
    END
  END b_d[260]
  PIN b_d[261]
    DIRECTION INPUT ;
    USE SIGNAL ;
    PORT
      LAYER M5 ;
        RECT  16.56 0 16.584 0.084 ;
    END
  END b_d[261]
  PIN b_d[262]
    DIRECTION INPUT ;
    USE SIGNAL ;
    PORT
      LAYER M5 ;
        RECT  16.656 0 16.68 0.084 ;
    END
  END b_d[262]
  PIN b_d[263]
    DIRECTION INPUT ;
    USE SIGNAL ;
    PORT
      LAYER M5 ;
        RECT  16.752 0 16.776 0.084 ;
    END
  END b_d[263]
  PIN b_d[264]
    DIRECTION INPUT ;
    USE SIGNAL ;
    PORT
      LAYER M5 ;
        RECT  16.848 0 16.872 0.084 ;
    END
  END b_d[264]
  PIN b_d[265]
    DIRECTION INPUT ;
    USE SIGNAL ;
    PORT
      LAYER M5 ;
        RECT  16.944 0 16.968 0.084 ;
    END
  END b_d[265]
  PIN b_d[266]
    DIRECTION INPUT ;
    USE SIGNAL ;
    PORT
      LAYER M5 ;
        RECT  17.04 0 17.064 0.084 ;
    END
  END b_d[266]
  PIN b_d[267]
    DIRECTION INPUT ;
    USE SIGNAL ;
    PORT
      LAYER M5 ;
        RECT  17.136 0 17.16 0.084 ;
    END
  END b_d[267]
  PIN b_d[268]
    DIRECTION INPUT ;
    USE SIGNAL ;
    PORT
      LAYER M5 ;
        RECT  17.232 0 17.256 0.084 ;
    END
  END b_d[268]
  PIN b_d[269]
    DIRECTION INPUT ;
    USE SIGNAL ;
    PORT
      LAYER M5 ;
        RECT  17.328 0 17.352 0.084 ;
    END
  END b_d[269]
  PIN b_d[26]
    DIRECTION INPUT ;
    USE SIGNAL ;
    PORT
      LAYER M5 ;
        RECT  28.56 0 28.584 0.084 ;
    END
  END b_d[26]
  PIN b_d[270]
    DIRECTION INPUT ;
    USE SIGNAL ;
    PORT
      LAYER M5 ;
        RECT  17.424 0 17.448 0.084 ;
    END
  END b_d[270]
  PIN b_d[271]
    DIRECTION INPUT ;
    USE SIGNAL ;
    PORT
      LAYER M5 ;
        RECT  17.52 0 17.544 0.084 ;
    END
  END b_d[271]
  PIN b_d[272]
    DIRECTION INPUT ;
    USE SIGNAL ;
    PORT
      LAYER M5 ;
        RECT  17.616 0 17.64 0.084 ;
    END
  END b_d[272]
  PIN b_d[273]
    DIRECTION INPUT ;
    USE SIGNAL ;
    PORT
      LAYER M5 ;
        RECT  17.712 0 17.736 0.084 ;
    END
  END b_d[273]
  PIN b_d[274]
    DIRECTION INPUT ;
    USE SIGNAL ;
    PORT
      LAYER M5 ;
        RECT  17.808 0 17.832 0.084 ;
    END
  END b_d[274]
  PIN b_d[275]
    DIRECTION INPUT ;
    USE SIGNAL ;
    PORT
      LAYER M5 ;
        RECT  17.904 0 17.928 0.084 ;
    END
  END b_d[275]
  PIN b_d[276]
    DIRECTION INPUT ;
    USE SIGNAL ;
    PORT
      LAYER M5 ;
        RECT  18 0 18.024 0.084 ;
    END
  END b_d[276]
  PIN b_d[277]
    DIRECTION INPUT ;
    USE SIGNAL ;
    PORT
      LAYER M5 ;
        RECT  18.096 0 18.12 0.084 ;
    END
  END b_d[277]
  PIN b_d[278]
    DIRECTION INPUT ;
    USE SIGNAL ;
    PORT
      LAYER M5 ;
        RECT  18.192 0 18.216 0.084 ;
    END
  END b_d[278]
  PIN b_d[279]
    DIRECTION INPUT ;
    USE SIGNAL ;
    PORT
      LAYER M5 ;
        RECT  18.288 0 18.312 0.084 ;
    END
  END b_d[279]
  PIN b_d[27]
    DIRECTION INPUT ;
    USE SIGNAL ;
    PORT
      LAYER M5 ;
        RECT  28.656 0 28.68 0.084 ;
    END
  END b_d[27]
  PIN b_d[280]
    DIRECTION INPUT ;
    USE SIGNAL ;
    PORT
      LAYER M5 ;
        RECT  18.384 0 18.408 0.084 ;
    END
  END b_d[280]
  PIN b_d[281]
    DIRECTION INPUT ;
    USE SIGNAL ;
    PORT
      LAYER M5 ;
        RECT  18.48 0 18.504 0.084 ;
    END
  END b_d[281]
  PIN b_d[282]
    DIRECTION INPUT ;
    USE SIGNAL ;
    PORT
      LAYER M5 ;
        RECT  18.576 0 18.6 0.084 ;
    END
  END b_d[282]
  PIN b_d[283]
    DIRECTION INPUT ;
    USE SIGNAL ;
    PORT
      LAYER M5 ;
        RECT  18.672 0 18.696 0.084 ;
    END
  END b_d[283]
  PIN b_d[284]
    DIRECTION INPUT ;
    USE SIGNAL ;
    PORT
      LAYER M5 ;
        RECT  18.768 0 18.792 0.084 ;
    END
  END b_d[284]
  PIN b_d[285]
    DIRECTION INPUT ;
    USE SIGNAL ;
    PORT
      LAYER M5 ;
        RECT  18.864 0 18.888 0.084 ;
    END
  END b_d[285]
  PIN b_d[286]
    DIRECTION INPUT ;
    USE SIGNAL ;
    PORT
      LAYER M5 ;
        RECT  18.96 0 18.984 0.084 ;
    END
  END b_d[286]
  PIN b_d[287]
    DIRECTION INPUT ;
    USE SIGNAL ;
    PORT
      LAYER M5 ;
        RECT  19.056 0 19.08 0.084 ;
    END
  END b_d[287]
  PIN b_d[288]
    DIRECTION INPUT ;
    USE SIGNAL ;
    PORT
      LAYER M5 ;
        RECT  45.264 0 45.288 0.084 ;
    END
  END b_d[288]
  PIN b_d[289]
    DIRECTION INPUT ;
    USE SIGNAL ;
    PORT
      LAYER M5 ;
        RECT  45.36 0 45.384 0.084 ;
    END
  END b_d[289]
  PIN b_d[28]
    DIRECTION INPUT ;
    USE SIGNAL ;
    PORT
      LAYER M5 ;
        RECT  28.752 0 28.776 0.084 ;
    END
  END b_d[28]
  PIN b_d[290]
    DIRECTION INPUT ;
    USE SIGNAL ;
    PORT
      LAYER M5 ;
        RECT  45.456 0 45.48 0.084 ;
    END
  END b_d[290]
  PIN b_d[291]
    DIRECTION INPUT ;
    USE SIGNAL ;
    PORT
      LAYER M5 ;
        RECT  45.552 0 45.576 0.084 ;
    END
  END b_d[291]
  PIN b_d[292]
    DIRECTION INPUT ;
    USE SIGNAL ;
    PORT
      LAYER M5 ;
        RECT  45.648 0 45.672 0.084 ;
    END
  END b_d[292]
  PIN b_d[293]
    DIRECTION INPUT ;
    USE SIGNAL ;
    PORT
      LAYER M5 ;
        RECT  45.744 0 45.768 0.084 ;
    END
  END b_d[293]
  PIN b_d[294]
    DIRECTION INPUT ;
    USE SIGNAL ;
    PORT
      LAYER M5 ;
        RECT  45.84 0 45.864 0.084 ;
    END
  END b_d[294]
  PIN b_d[295]
    DIRECTION INPUT ;
    USE SIGNAL ;
    PORT
      LAYER M5 ;
        RECT  45.936 0 45.96 0.084 ;
    END
  END b_d[295]
  PIN b_d[296]
    DIRECTION INPUT ;
    USE SIGNAL ;
    PORT
      LAYER M5 ;
        RECT  46.032 0 46.056 0.084 ;
    END
  END b_d[296]
  PIN b_d[297]
    DIRECTION INPUT ;
    USE SIGNAL ;
    PORT
      LAYER M5 ;
        RECT  46.128 0 46.152 0.084 ;
    END
  END b_d[297]
  PIN b_d[298]
    DIRECTION INPUT ;
    USE SIGNAL ;
    PORT
      LAYER M5 ;
        RECT  46.224 0 46.248 0.084 ;
    END
  END b_d[298]
  PIN b_d[299]
    DIRECTION INPUT ;
    USE SIGNAL ;
    PORT
      LAYER M5 ;
        RECT  46.32 0 46.344 0.084 ;
    END
  END b_d[299]
  PIN b_d[29]
    DIRECTION INPUT ;
    USE SIGNAL ;
    PORT
      LAYER M5 ;
        RECT  28.848 0 28.872 0.084 ;
    END
  END b_d[29]
  PIN b_d[2]
    DIRECTION INPUT ;
    USE SIGNAL ;
    PORT
      LAYER M5 ;
        RECT  26.256 0 26.28 0.084 ;
    END
  END b_d[2]
  PIN b_d[300]
    DIRECTION INPUT ;
    USE SIGNAL ;
    PORT
      LAYER M5 ;
        RECT  46.416 0 46.44 0.084 ;
    END
  END b_d[300]
  PIN b_d[301]
    DIRECTION INPUT ;
    USE SIGNAL ;
    PORT
      LAYER M5 ;
        RECT  46.512 0 46.536 0.084 ;
    END
  END b_d[301]
  PIN b_d[302]
    DIRECTION INPUT ;
    USE SIGNAL ;
    PORT
      LAYER M5 ;
        RECT  46.608 0 46.632 0.084 ;
    END
  END b_d[302]
  PIN b_d[303]
    DIRECTION INPUT ;
    USE SIGNAL ;
    PORT
      LAYER M5 ;
        RECT  46.704 0 46.728 0.084 ;
    END
  END b_d[303]
  PIN b_d[304]
    DIRECTION INPUT ;
    USE SIGNAL ;
    PORT
      LAYER M5 ;
        RECT  46.8 0 46.824 0.084 ;
    END
  END b_d[304]
  PIN b_d[305]
    DIRECTION INPUT ;
    USE SIGNAL ;
    PORT
      LAYER M5 ;
        RECT  46.896 0 46.92 0.084 ;
    END
  END b_d[305]
  PIN b_d[306]
    DIRECTION INPUT ;
    USE SIGNAL ;
    PORT
      LAYER M5 ;
        RECT  46.992 0 47.016 0.084 ;
    END
  END b_d[306]
  PIN b_d[307]
    DIRECTION INPUT ;
    USE SIGNAL ;
    PORT
      LAYER M5 ;
        RECT  47.088 0 47.112 0.084 ;
    END
  END b_d[307]
  PIN b_d[308]
    DIRECTION INPUT ;
    USE SIGNAL ;
    PORT
      LAYER M5 ;
        RECT  47.184 0 47.208 0.084 ;
    END
  END b_d[308]
  PIN b_d[309]
    DIRECTION INPUT ;
    USE SIGNAL ;
    PORT
      LAYER M5 ;
        RECT  47.28 0 47.304 0.084 ;
    END
  END b_d[309]
  PIN b_d[30]
    DIRECTION INPUT ;
    USE SIGNAL ;
    PORT
      LAYER M5 ;
        RECT  28.944 0 28.968 0.084 ;
    END
  END b_d[30]
  PIN b_d[310]
    DIRECTION INPUT ;
    USE SIGNAL ;
    PORT
      LAYER M5 ;
        RECT  47.376 0 47.4 0.084 ;
    END
  END b_d[310]
  PIN b_d[311]
    DIRECTION INPUT ;
    USE SIGNAL ;
    PORT
      LAYER M5 ;
        RECT  47.472 0 47.496 0.084 ;
    END
  END b_d[311]
  PIN b_d[312]
    DIRECTION INPUT ;
    USE SIGNAL ;
    PORT
      LAYER M5 ;
        RECT  47.568 0 47.592 0.084 ;
    END
  END b_d[312]
  PIN b_d[313]
    DIRECTION INPUT ;
    USE SIGNAL ;
    PORT
      LAYER M5 ;
        RECT  47.664 0 47.688 0.084 ;
    END
  END b_d[313]
  PIN b_d[314]
    DIRECTION INPUT ;
    USE SIGNAL ;
    PORT
      LAYER M5 ;
        RECT  47.76 0 47.784 0.084 ;
    END
  END b_d[314]
  PIN b_d[315]
    DIRECTION INPUT ;
    USE SIGNAL ;
    PORT
      LAYER M5 ;
        RECT  47.856 0 47.88 0.084 ;
    END
  END b_d[315]
  PIN b_d[316]
    DIRECTION INPUT ;
    USE SIGNAL ;
    PORT
      LAYER M5 ;
        RECT  47.952 0 47.976 0.084 ;
    END
  END b_d[316]
  PIN b_d[317]
    DIRECTION INPUT ;
    USE SIGNAL ;
    PORT
      LAYER M5 ;
        RECT  48.048 0 48.072 0.084 ;
    END
  END b_d[317]
  PIN b_d[318]
    DIRECTION INPUT ;
    USE SIGNAL ;
    PORT
      LAYER M5 ;
        RECT  48.144 0 48.168 0.084 ;
    END
  END b_d[318]
  PIN b_d[319]
    DIRECTION INPUT ;
    USE SIGNAL ;
    PORT
      LAYER M5 ;
        RECT  48.24 0 48.264 0.084 ;
    END
  END b_d[319]
  PIN b_d[31]
    DIRECTION INPUT ;
    USE SIGNAL ;
    PORT
      LAYER M5 ;
        RECT  29.04 0 29.064 0.084 ;
    END
  END b_d[31]
  PIN b_d[320]
    DIRECTION INPUT ;
    USE SIGNAL ;
    PORT
      LAYER M5 ;
        RECT  3.792 0 3.816 0.084 ;
    END
  END b_d[320]
  PIN b_d[321]
    DIRECTION INPUT ;
    USE SIGNAL ;
    PORT
      LAYER M5 ;
        RECT  3.888 0 3.912 0.084 ;
    END
  END b_d[321]
  PIN b_d[322]
    DIRECTION INPUT ;
    USE SIGNAL ;
    PORT
      LAYER M5 ;
        RECT  3.984 0 4.008 0.084 ;
    END
  END b_d[322]
  PIN b_d[323]
    DIRECTION INPUT ;
    USE SIGNAL ;
    PORT
      LAYER M5 ;
        RECT  4.08 0 4.104 0.084 ;
    END
  END b_d[323]
  PIN b_d[324]
    DIRECTION INPUT ;
    USE SIGNAL ;
    PORT
      LAYER M5 ;
        RECT  4.176 0 4.2 0.084 ;
    END
  END b_d[324]
  PIN b_d[325]
    DIRECTION INPUT ;
    USE SIGNAL ;
    PORT
      LAYER M5 ;
        RECT  4.272 0 4.296 0.084 ;
    END
  END b_d[325]
  PIN b_d[326]
    DIRECTION INPUT ;
    USE SIGNAL ;
    PORT
      LAYER M5 ;
        RECT  4.368 0 4.392 0.084 ;
    END
  END b_d[326]
  PIN b_d[327]
    DIRECTION INPUT ;
    USE SIGNAL ;
    PORT
      LAYER M5 ;
        RECT  4.464 0 4.488 0.084 ;
    END
  END b_d[327]
  PIN b_d[328]
    DIRECTION INPUT ;
    USE SIGNAL ;
    PORT
      LAYER M5 ;
        RECT  4.56 0 4.584 0.084 ;
    END
  END b_d[328]
  PIN b_d[329]
    DIRECTION INPUT ;
    USE SIGNAL ;
    PORT
      LAYER M5 ;
        RECT  4.656 0 4.68 0.084 ;
    END
  END b_d[329]
  PIN b_d[32]
    DIRECTION INPUT ;
    USE SIGNAL ;
    PORT
      LAYER M5 ;
        RECT  35.28 0 35.304 0.084 ;
    END
  END b_d[32]
  PIN b_d[330]
    DIRECTION INPUT ;
    USE SIGNAL ;
    PORT
      LAYER M5 ;
        RECT  4.752 0 4.776 0.084 ;
    END
  END b_d[330]
  PIN b_d[331]
    DIRECTION INPUT ;
    USE SIGNAL ;
    PORT
      LAYER M5 ;
        RECT  4.848 0 4.872 0.084 ;
    END
  END b_d[331]
  PIN b_d[332]
    DIRECTION INPUT ;
    USE SIGNAL ;
    PORT
      LAYER M5 ;
        RECT  4.944 0 4.968 0.084 ;
    END
  END b_d[332]
  PIN b_d[333]
    DIRECTION INPUT ;
    USE SIGNAL ;
    PORT
      LAYER M5 ;
        RECT  5.04 0 5.064 0.084 ;
    END
  END b_d[333]
  PIN b_d[334]
    DIRECTION INPUT ;
    USE SIGNAL ;
    PORT
      LAYER M5 ;
        RECT  5.136 0 5.16 0.084 ;
    END
  END b_d[334]
  PIN b_d[335]
    DIRECTION INPUT ;
    USE SIGNAL ;
    PORT
      LAYER M5 ;
        RECT  5.232 0 5.256 0.084 ;
    END
  END b_d[335]
  PIN b_d[336]
    DIRECTION INPUT ;
    USE SIGNAL ;
    PORT
      LAYER M5 ;
        RECT  5.328 0 5.352 0.084 ;
    END
  END b_d[336]
  PIN b_d[337]
    DIRECTION INPUT ;
    USE SIGNAL ;
    PORT
      LAYER M5 ;
        RECT  5.424 0 5.448 0.084 ;
    END
  END b_d[337]
  PIN b_d[338]
    DIRECTION INPUT ;
    USE SIGNAL ;
    PORT
      LAYER M5 ;
        RECT  5.52 0 5.544 0.084 ;
    END
  END b_d[338]
  PIN b_d[339]
    DIRECTION INPUT ;
    USE SIGNAL ;
    PORT
      LAYER M5 ;
        RECT  5.616 0 5.64 0.084 ;
    END
  END b_d[339]
  PIN b_d[33]
    DIRECTION INPUT ;
    USE SIGNAL ;
    PORT
      LAYER M5 ;
        RECT  35.376 0 35.4 0.084 ;
    END
  END b_d[33]
  PIN b_d[340]
    DIRECTION INPUT ;
    USE SIGNAL ;
    PORT
      LAYER M5 ;
        RECT  5.712 0 5.736 0.084 ;
    END
  END b_d[340]
  PIN b_d[341]
    DIRECTION INPUT ;
    USE SIGNAL ;
    PORT
      LAYER M5 ;
        RECT  5.808 0 5.832 0.084 ;
    END
  END b_d[341]
  PIN b_d[342]
    DIRECTION INPUT ;
    USE SIGNAL ;
    PORT
      LAYER M5 ;
        RECT  5.904 0 5.928 0.084 ;
    END
  END b_d[342]
  PIN b_d[343]
    DIRECTION INPUT ;
    USE SIGNAL ;
    PORT
      LAYER M5 ;
        RECT  6 0 6.024 0.084 ;
    END
  END b_d[343]
  PIN b_d[344]
    DIRECTION INPUT ;
    USE SIGNAL ;
    PORT
      LAYER M5 ;
        RECT  6.096 0 6.12 0.084 ;
    END
  END b_d[344]
  PIN b_d[345]
    DIRECTION INPUT ;
    USE SIGNAL ;
    PORT
      LAYER M5 ;
        RECT  6.192 0 6.216 0.084 ;
    END
  END b_d[345]
  PIN b_d[346]
    DIRECTION INPUT ;
    USE SIGNAL ;
    PORT
      LAYER M5 ;
        RECT  6.288 0 6.312 0.084 ;
    END
  END b_d[346]
  PIN b_d[347]
    DIRECTION INPUT ;
    USE SIGNAL ;
    PORT
      LAYER M5 ;
        RECT  6.384 0 6.408 0.084 ;
    END
  END b_d[347]
  PIN b_d[348]
    DIRECTION INPUT ;
    USE SIGNAL ;
    PORT
      LAYER M5 ;
        RECT  6.48 0 6.504 0.084 ;
    END
  END b_d[348]
  PIN b_d[349]
    DIRECTION INPUT ;
    USE SIGNAL ;
    PORT
      LAYER M5 ;
        RECT  6.576 0 6.6 0.084 ;
    END
  END b_d[349]
  PIN b_d[34]
    DIRECTION INPUT ;
    USE SIGNAL ;
    PORT
      LAYER M5 ;
        RECT  35.472 0 35.496 0.084 ;
    END
  END b_d[34]
  PIN b_d[350]
    DIRECTION INPUT ;
    USE SIGNAL ;
    PORT
      LAYER M5 ;
        RECT  6.672 0 6.696 0.084 ;
    END
  END b_d[350]
  PIN b_d[351]
    DIRECTION INPUT ;
    USE SIGNAL ;
    PORT
      LAYER M5 ;
        RECT  6.768 0 6.792 0.084 ;
    END
  END b_d[351]
  PIN b_d[352]
    DIRECTION INPUT ;
    USE SIGNAL ;
    PORT
      LAYER M5 ;
        RECT  13.008 0 13.032 0.084 ;
    END
  END b_d[352]
  PIN b_d[353]
    DIRECTION INPUT ;
    USE SIGNAL ;
    PORT
      LAYER M5 ;
        RECT  13.104 0 13.128 0.084 ;
    END
  END b_d[353]
  PIN b_d[354]
    DIRECTION INPUT ;
    USE SIGNAL ;
    PORT
      LAYER M5 ;
        RECT  13.2 0 13.224 0.084 ;
    END
  END b_d[354]
  PIN b_d[355]
    DIRECTION INPUT ;
    USE SIGNAL ;
    PORT
      LAYER M5 ;
        RECT  13.296 0 13.32 0.084 ;
    END
  END b_d[355]
  PIN b_d[356]
    DIRECTION INPUT ;
    USE SIGNAL ;
    PORT
      LAYER M5 ;
        RECT  13.392 0 13.416 0.084 ;
    END
  END b_d[356]
  PIN b_d[357]
    DIRECTION INPUT ;
    USE SIGNAL ;
    PORT
      LAYER M5 ;
        RECT  13.488 0 13.512 0.084 ;
    END
  END b_d[357]
  PIN b_d[358]
    DIRECTION INPUT ;
    USE SIGNAL ;
    PORT
      LAYER M5 ;
        RECT  13.584 0 13.608 0.084 ;
    END
  END b_d[358]
  PIN b_d[359]
    DIRECTION INPUT ;
    USE SIGNAL ;
    PORT
      LAYER M5 ;
        RECT  13.68 0 13.704 0.084 ;
    END
  END b_d[359]
  PIN b_d[35]
    DIRECTION INPUT ;
    USE SIGNAL ;
    PORT
      LAYER M5 ;
        RECT  35.568 0 35.592 0.084 ;
    END
  END b_d[35]
  PIN b_d[360]
    DIRECTION INPUT ;
    USE SIGNAL ;
    PORT
      LAYER M5 ;
        RECT  13.776 0 13.8 0.084 ;
    END
  END b_d[360]
  PIN b_d[361]
    DIRECTION INPUT ;
    USE SIGNAL ;
    PORT
      LAYER M5 ;
        RECT  13.872 0 13.896 0.084 ;
    END
  END b_d[361]
  PIN b_d[362]
    DIRECTION INPUT ;
    USE SIGNAL ;
    PORT
      LAYER M5 ;
        RECT  13.968 0 13.992 0.084 ;
    END
  END b_d[362]
  PIN b_d[363]
    DIRECTION INPUT ;
    USE SIGNAL ;
    PORT
      LAYER M5 ;
        RECT  14.064 0 14.088 0.084 ;
    END
  END b_d[363]
  PIN b_d[364]
    DIRECTION INPUT ;
    USE SIGNAL ;
    PORT
      LAYER M5 ;
        RECT  14.16 0 14.184 0.084 ;
    END
  END b_d[364]
  PIN b_d[365]
    DIRECTION INPUT ;
    USE SIGNAL ;
    PORT
      LAYER M5 ;
        RECT  14.256 0 14.28 0.084 ;
    END
  END b_d[365]
  PIN b_d[366]
    DIRECTION INPUT ;
    USE SIGNAL ;
    PORT
      LAYER M5 ;
        RECT  14.352 0 14.376 0.084 ;
    END
  END b_d[366]
  PIN b_d[367]
    DIRECTION INPUT ;
    USE SIGNAL ;
    PORT
      LAYER M5 ;
        RECT  14.448 0 14.472 0.084 ;
    END
  END b_d[367]
  PIN b_d[368]
    DIRECTION INPUT ;
    USE SIGNAL ;
    PORT
      LAYER M5 ;
        RECT  14.544 0 14.568 0.084 ;
    END
  END b_d[368]
  PIN b_d[369]
    DIRECTION INPUT ;
    USE SIGNAL ;
    PORT
      LAYER M5 ;
        RECT  14.64 0 14.664 0.084 ;
    END
  END b_d[369]
  PIN b_d[36]
    DIRECTION INPUT ;
    USE SIGNAL ;
    PORT
      LAYER M5 ;
        RECT  35.664 0 35.688 0.084 ;
    END
  END b_d[36]
  PIN b_d[370]
    DIRECTION INPUT ;
    USE SIGNAL ;
    PORT
      LAYER M5 ;
        RECT  14.736 0 14.76 0.084 ;
    END
  END b_d[370]
  PIN b_d[371]
    DIRECTION INPUT ;
    USE SIGNAL ;
    PORT
      LAYER M5 ;
        RECT  14.832 0 14.856 0.084 ;
    END
  END b_d[371]
  PIN b_d[372]
    DIRECTION INPUT ;
    USE SIGNAL ;
    PORT
      LAYER M5 ;
        RECT  14.928 0 14.952 0.084 ;
    END
  END b_d[372]
  PIN b_d[373]
    DIRECTION INPUT ;
    USE SIGNAL ;
    PORT
      LAYER M5 ;
        RECT  15.024 0 15.048 0.084 ;
    END
  END b_d[373]
  PIN b_d[374]
    DIRECTION INPUT ;
    USE SIGNAL ;
    PORT
      LAYER M5 ;
        RECT  15.12 0 15.144 0.084 ;
    END
  END b_d[374]
  PIN b_d[375]
    DIRECTION INPUT ;
    USE SIGNAL ;
    PORT
      LAYER M5 ;
        RECT  15.216 0 15.24 0.084 ;
    END
  END b_d[375]
  PIN b_d[376]
    DIRECTION INPUT ;
    USE SIGNAL ;
    PORT
      LAYER M5 ;
        RECT  15.312 0 15.336 0.084 ;
    END
  END b_d[376]
  PIN b_d[377]
    DIRECTION INPUT ;
    USE SIGNAL ;
    PORT
      LAYER M5 ;
        RECT  15.408 0 15.432 0.084 ;
    END
  END b_d[377]
  PIN b_d[378]
    DIRECTION INPUT ;
    USE SIGNAL ;
    PORT
      LAYER M5 ;
        RECT  15.504 0 15.528 0.084 ;
    END
  END b_d[378]
  PIN b_d[379]
    DIRECTION INPUT ;
    USE SIGNAL ;
    PORT
      LAYER M5 ;
        RECT  15.6 0 15.624 0.084 ;
    END
  END b_d[379]
  PIN b_d[37]
    DIRECTION INPUT ;
    USE SIGNAL ;
    PORT
      LAYER M5 ;
        RECT  35.76 0 35.784 0.084 ;
    END
  END b_d[37]
  PIN b_d[380]
    DIRECTION INPUT ;
    USE SIGNAL ;
    PORT
      LAYER M5 ;
        RECT  15.696 0 15.72 0.084 ;
    END
  END b_d[380]
  PIN b_d[381]
    DIRECTION INPUT ;
    USE SIGNAL ;
    PORT
      LAYER M5 ;
        RECT  15.792 0 15.816 0.084 ;
    END
  END b_d[381]
  PIN b_d[382]
    DIRECTION INPUT ;
    USE SIGNAL ;
    PORT
      LAYER M5 ;
        RECT  15.888 0 15.912 0.084 ;
    END
  END b_d[382]
  PIN b_d[383]
    DIRECTION INPUT ;
    USE SIGNAL ;
    PORT
      LAYER M5 ;
        RECT  15.984 0 16.008 0.084 ;
    END
  END b_d[383]
  PIN b_d[384]
    DIRECTION INPUT ;
    USE SIGNAL ;
    PORT
      LAYER M5 ;
        RECT  42.192 0 42.216 0.084 ;
    END
  END b_d[384]
  PIN b_d[385]
    DIRECTION INPUT ;
    USE SIGNAL ;
    PORT
      LAYER M5 ;
        RECT  42.288 0 42.312 0.084 ;
    END
  END b_d[385]
  PIN b_d[386]
    DIRECTION INPUT ;
    USE SIGNAL ;
    PORT
      LAYER M5 ;
        RECT  42.384 0 42.408 0.084 ;
    END
  END b_d[386]
  PIN b_d[387]
    DIRECTION INPUT ;
    USE SIGNAL ;
    PORT
      LAYER M5 ;
        RECT  42.48 0 42.504 0.084 ;
    END
  END b_d[387]
  PIN b_d[388]
    DIRECTION INPUT ;
    USE SIGNAL ;
    PORT
      LAYER M5 ;
        RECT  42.576 0 42.6 0.084 ;
    END
  END b_d[388]
  PIN b_d[389]
    DIRECTION INPUT ;
    USE SIGNAL ;
    PORT
      LAYER M5 ;
        RECT  42.672 0 42.696 0.084 ;
    END
  END b_d[389]
  PIN b_d[38]
    DIRECTION INPUT ;
    USE SIGNAL ;
    PORT
      LAYER M5 ;
        RECT  35.856 0 35.88 0.084 ;
    END
  END b_d[38]
  PIN b_d[390]
    DIRECTION INPUT ;
    USE SIGNAL ;
    PORT
      LAYER M5 ;
        RECT  42.768 0 42.792 0.084 ;
    END
  END b_d[390]
  PIN b_d[391]
    DIRECTION INPUT ;
    USE SIGNAL ;
    PORT
      LAYER M5 ;
        RECT  42.864 0 42.888 0.084 ;
    END
  END b_d[391]
  PIN b_d[392]
    DIRECTION INPUT ;
    USE SIGNAL ;
    PORT
      LAYER M5 ;
        RECT  42.96 0 42.984 0.084 ;
    END
  END b_d[392]
  PIN b_d[393]
    DIRECTION INPUT ;
    USE SIGNAL ;
    PORT
      LAYER M5 ;
        RECT  43.056 0 43.08 0.084 ;
    END
  END b_d[393]
  PIN b_d[394]
    DIRECTION INPUT ;
    USE SIGNAL ;
    PORT
      LAYER M5 ;
        RECT  43.152 0 43.176 0.084 ;
    END
  END b_d[394]
  PIN b_d[395]
    DIRECTION INPUT ;
    USE SIGNAL ;
    PORT
      LAYER M5 ;
        RECT  43.248 0 43.272 0.084 ;
    END
  END b_d[395]
  PIN b_d[396]
    DIRECTION INPUT ;
    USE SIGNAL ;
    PORT
      LAYER M5 ;
        RECT  43.344 0 43.368 0.084 ;
    END
  END b_d[396]
  PIN b_d[397]
    DIRECTION INPUT ;
    USE SIGNAL ;
    PORT
      LAYER M5 ;
        RECT  43.44 0 43.464 0.084 ;
    END
  END b_d[397]
  PIN b_d[398]
    DIRECTION INPUT ;
    USE SIGNAL ;
    PORT
      LAYER M5 ;
        RECT  43.536 0 43.56 0.084 ;
    END
  END b_d[398]
  PIN b_d[399]
    DIRECTION INPUT ;
    USE SIGNAL ;
    PORT
      LAYER M5 ;
        RECT  43.632 0 43.656 0.084 ;
    END
  END b_d[399]
  PIN b_d[39]
    DIRECTION INPUT ;
    USE SIGNAL ;
    PORT
      LAYER M5 ;
        RECT  35.952 0 35.976 0.084 ;
    END
  END b_d[39]
  PIN b_d[3]
    DIRECTION INPUT ;
    USE SIGNAL ;
    PORT
      LAYER M5 ;
        RECT  26.352 0 26.376 0.084 ;
    END
  END b_d[3]
  PIN b_d[400]
    DIRECTION INPUT ;
    USE SIGNAL ;
    PORT
      LAYER M5 ;
        RECT  43.728 0 43.752 0.084 ;
    END
  END b_d[400]
  PIN b_d[401]
    DIRECTION INPUT ;
    USE SIGNAL ;
    PORT
      LAYER M5 ;
        RECT  43.824 0 43.848 0.084 ;
    END
  END b_d[401]
  PIN b_d[402]
    DIRECTION INPUT ;
    USE SIGNAL ;
    PORT
      LAYER M5 ;
        RECT  43.92 0 43.944 0.084 ;
    END
  END b_d[402]
  PIN b_d[403]
    DIRECTION INPUT ;
    USE SIGNAL ;
    PORT
      LAYER M5 ;
        RECT  44.016 0 44.04 0.084 ;
    END
  END b_d[403]
  PIN b_d[404]
    DIRECTION INPUT ;
    USE SIGNAL ;
    PORT
      LAYER M5 ;
        RECT  44.112 0 44.136 0.084 ;
    END
  END b_d[404]
  PIN b_d[405]
    DIRECTION INPUT ;
    USE SIGNAL ;
    PORT
      LAYER M5 ;
        RECT  44.208 0 44.232 0.084 ;
    END
  END b_d[405]
  PIN b_d[406]
    DIRECTION INPUT ;
    USE SIGNAL ;
    PORT
      LAYER M5 ;
        RECT  44.304 0 44.328 0.084 ;
    END
  END b_d[406]
  PIN b_d[407]
    DIRECTION INPUT ;
    USE SIGNAL ;
    PORT
      LAYER M5 ;
        RECT  44.4 0 44.424 0.084 ;
    END
  END b_d[407]
  PIN b_d[408]
    DIRECTION INPUT ;
    USE SIGNAL ;
    PORT
      LAYER M5 ;
        RECT  44.496 0 44.52 0.084 ;
    END
  END b_d[408]
  PIN b_d[409]
    DIRECTION INPUT ;
    USE SIGNAL ;
    PORT
      LAYER M5 ;
        RECT  44.592 0 44.616 0.084 ;
    END
  END b_d[409]
  PIN b_d[40]
    DIRECTION INPUT ;
    USE SIGNAL ;
    PORT
      LAYER M5 ;
        RECT  36.048 0 36.072 0.084 ;
    END
  END b_d[40]
  PIN b_d[410]
    DIRECTION INPUT ;
    USE SIGNAL ;
    PORT
      LAYER M5 ;
        RECT  44.688 0 44.712 0.084 ;
    END
  END b_d[410]
  PIN b_d[411]
    DIRECTION INPUT ;
    USE SIGNAL ;
    PORT
      LAYER M5 ;
        RECT  44.784 0 44.808 0.084 ;
    END
  END b_d[411]
  PIN b_d[412]
    DIRECTION INPUT ;
    USE SIGNAL ;
    PORT
      LAYER M5 ;
        RECT  44.88 0 44.904 0.084 ;
    END
  END b_d[412]
  PIN b_d[413]
    DIRECTION INPUT ;
    USE SIGNAL ;
    PORT
      LAYER M5 ;
        RECT  44.976 0 45 0.084 ;
    END
  END b_d[413]
  PIN b_d[414]
    DIRECTION INPUT ;
    USE SIGNAL ;
    PORT
      LAYER M5 ;
        RECT  45.072 0 45.096 0.084 ;
    END
  END b_d[414]
  PIN b_d[415]
    DIRECTION INPUT ;
    USE SIGNAL ;
    PORT
      LAYER M5 ;
        RECT  45.168 0 45.192 0.084 ;
    END
  END b_d[415]
  PIN b_d[416]
    DIRECTION INPUT ;
    USE SIGNAL ;
    PORT
      LAYER M5 ;
        RECT  6.864 0 6.888 0.084 ;
    END
  END b_d[416]
  PIN b_d[417]
    DIRECTION INPUT ;
    USE SIGNAL ;
    PORT
      LAYER M5 ;
        RECT  6.96 0 6.984 0.084 ;
    END
  END b_d[417]
  PIN b_d[418]
    DIRECTION INPUT ;
    USE SIGNAL ;
    PORT
      LAYER M5 ;
        RECT  7.056 0 7.08 0.084 ;
    END
  END b_d[418]
  PIN b_d[419]
    DIRECTION INPUT ;
    USE SIGNAL ;
    PORT
      LAYER M5 ;
        RECT  7.152 0 7.176 0.084 ;
    END
  END b_d[419]
  PIN b_d[41]
    DIRECTION INPUT ;
    USE SIGNAL ;
    PORT
      LAYER M5 ;
        RECT  36.144 0 36.168 0.084 ;
    END
  END b_d[41]
  PIN b_d[420]
    DIRECTION INPUT ;
    USE SIGNAL ;
    PORT
      LAYER M5 ;
        RECT  7.248 0 7.272 0.084 ;
    END
  END b_d[420]
  PIN b_d[421]
    DIRECTION INPUT ;
    USE SIGNAL ;
    PORT
      LAYER M5 ;
        RECT  7.344 0 7.368 0.084 ;
    END
  END b_d[421]
  PIN b_d[422]
    DIRECTION INPUT ;
    USE SIGNAL ;
    PORT
      LAYER M5 ;
        RECT  7.44 0 7.464 0.084 ;
    END
  END b_d[422]
  PIN b_d[423]
    DIRECTION INPUT ;
    USE SIGNAL ;
    PORT
      LAYER M5 ;
        RECT  7.536 0 7.56 0.084 ;
    END
  END b_d[423]
  PIN b_d[424]
    DIRECTION INPUT ;
    USE SIGNAL ;
    PORT
      LAYER M5 ;
        RECT  7.632 0 7.656 0.084 ;
    END
  END b_d[424]
  PIN b_d[425]
    DIRECTION INPUT ;
    USE SIGNAL ;
    PORT
      LAYER M5 ;
        RECT  7.728 0 7.752 0.084 ;
    END
  END b_d[425]
  PIN b_d[426]
    DIRECTION INPUT ;
    USE SIGNAL ;
    PORT
      LAYER M5 ;
        RECT  7.824 0 7.848 0.084 ;
    END
  END b_d[426]
  PIN b_d[427]
    DIRECTION INPUT ;
    USE SIGNAL ;
    PORT
      LAYER M5 ;
        RECT  7.92 0 7.944 0.084 ;
    END
  END b_d[427]
  PIN b_d[428]
    DIRECTION INPUT ;
    USE SIGNAL ;
    PORT
      LAYER M5 ;
        RECT  8.016 0 8.04 0.084 ;
    END
  END b_d[428]
  PIN b_d[429]
    DIRECTION INPUT ;
    USE SIGNAL ;
    PORT
      LAYER M5 ;
        RECT  8.112 0 8.136 0.084 ;
    END
  END b_d[429]
  PIN b_d[42]
    DIRECTION INPUT ;
    USE SIGNAL ;
    PORT
      LAYER M5 ;
        RECT  36.24 0 36.264 0.084 ;
    END
  END b_d[42]
  PIN b_d[430]
    DIRECTION INPUT ;
    USE SIGNAL ;
    PORT
      LAYER M5 ;
        RECT  8.208 0 8.232 0.084 ;
    END
  END b_d[430]
  PIN b_d[431]
    DIRECTION INPUT ;
    USE SIGNAL ;
    PORT
      LAYER M5 ;
        RECT  8.304 0 8.328 0.084 ;
    END
  END b_d[431]
  PIN b_d[432]
    DIRECTION INPUT ;
    USE SIGNAL ;
    PORT
      LAYER M5 ;
        RECT  8.4 0 8.424 0.084 ;
    END
  END b_d[432]
  PIN b_d[433]
    DIRECTION INPUT ;
    USE SIGNAL ;
    PORT
      LAYER M5 ;
        RECT  8.496 0 8.52 0.084 ;
    END
  END b_d[433]
  PIN b_d[434]
    DIRECTION INPUT ;
    USE SIGNAL ;
    PORT
      LAYER M5 ;
        RECT  8.592 0 8.616 0.084 ;
    END
  END b_d[434]
  PIN b_d[435]
    DIRECTION INPUT ;
    USE SIGNAL ;
    PORT
      LAYER M5 ;
        RECT  8.688 0 8.712 0.084 ;
    END
  END b_d[435]
  PIN b_d[436]
    DIRECTION INPUT ;
    USE SIGNAL ;
    PORT
      LAYER M5 ;
        RECT  8.784 0 8.808 0.084 ;
    END
  END b_d[436]
  PIN b_d[437]
    DIRECTION INPUT ;
    USE SIGNAL ;
    PORT
      LAYER M5 ;
        RECT  8.88 0 8.904 0.084 ;
    END
  END b_d[437]
  PIN b_d[438]
    DIRECTION INPUT ;
    USE SIGNAL ;
    PORT
      LAYER M5 ;
        RECT  8.976 0 9 0.084 ;
    END
  END b_d[438]
  PIN b_d[439]
    DIRECTION INPUT ;
    USE SIGNAL ;
    PORT
      LAYER M5 ;
        RECT  9.072 0 9.096 0.084 ;
    END
  END b_d[439]
  PIN b_d[43]
    DIRECTION INPUT ;
    USE SIGNAL ;
    PORT
      LAYER M5 ;
        RECT  36.336 0 36.36 0.084 ;
    END
  END b_d[43]
  PIN b_d[440]
    DIRECTION INPUT ;
    USE SIGNAL ;
    PORT
      LAYER M5 ;
        RECT  9.168 0 9.192 0.084 ;
    END
  END b_d[440]
  PIN b_d[441]
    DIRECTION INPUT ;
    USE SIGNAL ;
    PORT
      LAYER M5 ;
        RECT  9.264 0 9.288 0.084 ;
    END
  END b_d[441]
  PIN b_d[442]
    DIRECTION INPUT ;
    USE SIGNAL ;
    PORT
      LAYER M5 ;
        RECT  9.36 0 9.384 0.084 ;
    END
  END b_d[442]
  PIN b_d[443]
    DIRECTION INPUT ;
    USE SIGNAL ;
    PORT
      LAYER M5 ;
        RECT  9.456 0 9.48 0.084 ;
    END
  END b_d[443]
  PIN b_d[444]
    DIRECTION INPUT ;
    USE SIGNAL ;
    PORT
      LAYER M5 ;
        RECT  9.552 0 9.576 0.084 ;
    END
  END b_d[444]
  PIN b_d[445]
    DIRECTION INPUT ;
    USE SIGNAL ;
    PORT
      LAYER M5 ;
        RECT  9.648 0 9.672 0.084 ;
    END
  END b_d[445]
  PIN b_d[446]
    DIRECTION INPUT ;
    USE SIGNAL ;
    PORT
      LAYER M5 ;
        RECT  9.744 0 9.768 0.084 ;
    END
  END b_d[446]
  PIN b_d[447]
    DIRECTION INPUT ;
    USE SIGNAL ;
    PORT
      LAYER M5 ;
        RECT  9.84 0 9.864 0.084 ;
    END
  END b_d[447]
  PIN b_d[448]
    DIRECTION INPUT ;
    USE SIGNAL ;
    PORT
      LAYER M5 ;
        RECT  39.12 0 39.144 0.084 ;
    END
  END b_d[448]
  PIN b_d[449]
    DIRECTION INPUT ;
    USE SIGNAL ;
    PORT
      LAYER M5 ;
        RECT  39.216 0 39.24 0.084 ;
    END
  END b_d[449]
  PIN b_d[44]
    DIRECTION INPUT ;
    USE SIGNAL ;
    PORT
      LAYER M5 ;
        RECT  36.432 0 36.456 0.084 ;
    END
  END b_d[44]
  PIN b_d[450]
    DIRECTION INPUT ;
    USE SIGNAL ;
    PORT
      LAYER M5 ;
        RECT  39.312 0 39.336 0.084 ;
    END
  END b_d[450]
  PIN b_d[451]
    DIRECTION INPUT ;
    USE SIGNAL ;
    PORT
      LAYER M5 ;
        RECT  39.408 0 39.432 0.084 ;
    END
  END b_d[451]
  PIN b_d[452]
    DIRECTION INPUT ;
    USE SIGNAL ;
    PORT
      LAYER M5 ;
        RECT  39.504 0 39.528 0.084 ;
    END
  END b_d[452]
  PIN b_d[453]
    DIRECTION INPUT ;
    USE SIGNAL ;
    PORT
      LAYER M5 ;
        RECT  39.6 0 39.624 0.084 ;
    END
  END b_d[453]
  PIN b_d[454]
    DIRECTION INPUT ;
    USE SIGNAL ;
    PORT
      LAYER M5 ;
        RECT  39.696 0 39.72 0.084 ;
    END
  END b_d[454]
  PIN b_d[455]
    DIRECTION INPUT ;
    USE SIGNAL ;
    PORT
      LAYER M5 ;
        RECT  39.792 0 39.816 0.084 ;
    END
  END b_d[455]
  PIN b_d[456]
    DIRECTION INPUT ;
    USE SIGNAL ;
    PORT
      LAYER M5 ;
        RECT  39.888 0 39.912 0.084 ;
    END
  END b_d[456]
  PIN b_d[457]
    DIRECTION INPUT ;
    USE SIGNAL ;
    PORT
      LAYER M5 ;
        RECT  39.984 0 40.008 0.084 ;
    END
  END b_d[457]
  PIN b_d[458]
    DIRECTION INPUT ;
    USE SIGNAL ;
    PORT
      LAYER M5 ;
        RECT  40.08 0 40.104 0.084 ;
    END
  END b_d[458]
  PIN b_d[459]
    DIRECTION INPUT ;
    USE SIGNAL ;
    PORT
      LAYER M5 ;
        RECT  40.176 0 40.2 0.084 ;
    END
  END b_d[459]
  PIN b_d[45]
    DIRECTION INPUT ;
    USE SIGNAL ;
    PORT
      LAYER M5 ;
        RECT  36.528 0 36.552 0.084 ;
    END
  END b_d[45]
  PIN b_d[460]
    DIRECTION INPUT ;
    USE SIGNAL ;
    PORT
      LAYER M5 ;
        RECT  40.272 0 40.296 0.084 ;
    END
  END b_d[460]
  PIN b_d[461]
    DIRECTION INPUT ;
    USE SIGNAL ;
    PORT
      LAYER M5 ;
        RECT  40.368 0 40.392 0.084 ;
    END
  END b_d[461]
  PIN b_d[462]
    DIRECTION INPUT ;
    USE SIGNAL ;
    PORT
      LAYER M5 ;
        RECT  40.464 0 40.488 0.084 ;
    END
  END b_d[462]
  PIN b_d[463]
    DIRECTION INPUT ;
    USE SIGNAL ;
    PORT
      LAYER M5 ;
        RECT  40.56 0 40.584 0.084 ;
    END
  END b_d[463]
  PIN b_d[464]
    DIRECTION INPUT ;
    USE SIGNAL ;
    PORT
      LAYER M5 ;
        RECT  40.656 0 40.68 0.084 ;
    END
  END b_d[464]
  PIN b_d[465]
    DIRECTION INPUT ;
    USE SIGNAL ;
    PORT
      LAYER M5 ;
        RECT  40.752 0 40.776 0.084 ;
    END
  END b_d[465]
  PIN b_d[466]
    DIRECTION INPUT ;
    USE SIGNAL ;
    PORT
      LAYER M5 ;
        RECT  40.848 0 40.872 0.084 ;
    END
  END b_d[466]
  PIN b_d[467]
    DIRECTION INPUT ;
    USE SIGNAL ;
    PORT
      LAYER M5 ;
        RECT  40.944 0 40.968 0.084 ;
    END
  END b_d[467]
  PIN b_d[468]
    DIRECTION INPUT ;
    USE SIGNAL ;
    PORT
      LAYER M5 ;
        RECT  41.04 0 41.064 0.084 ;
    END
  END b_d[468]
  PIN b_d[469]
    DIRECTION INPUT ;
    USE SIGNAL ;
    PORT
      LAYER M5 ;
        RECT  41.136 0 41.16 0.084 ;
    END
  END b_d[469]
  PIN b_d[46]
    DIRECTION INPUT ;
    USE SIGNAL ;
    PORT
      LAYER M5 ;
        RECT  36.624 0 36.648 0.084 ;
    END
  END b_d[46]
  PIN b_d[470]
    DIRECTION INPUT ;
    USE SIGNAL ;
    PORT
      LAYER M5 ;
        RECT  41.232 0 41.256 0.084 ;
    END
  END b_d[470]
  PIN b_d[471]
    DIRECTION INPUT ;
    USE SIGNAL ;
    PORT
      LAYER M5 ;
        RECT  41.328 0 41.352 0.084 ;
    END
  END b_d[471]
  PIN b_d[472]
    DIRECTION INPUT ;
    USE SIGNAL ;
    PORT
      LAYER M5 ;
        RECT  41.424 0 41.448 0.084 ;
    END
  END b_d[472]
  PIN b_d[473]
    DIRECTION INPUT ;
    USE SIGNAL ;
    PORT
      LAYER M5 ;
        RECT  41.52 0 41.544 0.084 ;
    END
  END b_d[473]
  PIN b_d[474]
    DIRECTION INPUT ;
    USE SIGNAL ;
    PORT
      LAYER M5 ;
        RECT  41.616 0 41.64 0.084 ;
    END
  END b_d[474]
  PIN b_d[475]
    DIRECTION INPUT ;
    USE SIGNAL ;
    PORT
      LAYER M5 ;
        RECT  41.712 0 41.736 0.084 ;
    END
  END b_d[475]
  PIN b_d[476]
    DIRECTION INPUT ;
    USE SIGNAL ;
    PORT
      LAYER M5 ;
        RECT  41.808 0 41.832 0.084 ;
    END
  END b_d[476]
  PIN b_d[477]
    DIRECTION INPUT ;
    USE SIGNAL ;
    PORT
      LAYER M5 ;
        RECT  41.904 0 41.928 0.084 ;
    END
  END b_d[477]
  PIN b_d[478]
    DIRECTION INPUT ;
    USE SIGNAL ;
    PORT
      LAYER M5 ;
        RECT  42 0 42.024 0.084 ;
    END
  END b_d[478]
  PIN b_d[479]
    DIRECTION INPUT ;
    USE SIGNAL ;
    PORT
      LAYER M5 ;
        RECT  42.096 0 42.12 0.084 ;
    END
  END b_d[479]
  PIN b_d[47]
    DIRECTION INPUT ;
    USE SIGNAL ;
    PORT
      LAYER M5 ;
        RECT  36.72 0 36.744 0.084 ;
    END
  END b_d[47]
  PIN b_d[480]
    DIRECTION INPUT ;
    USE SIGNAL ;
    PORT
      LAYER M5 ;
        RECT  48.336 0 48.36 0.084 ;
    END
  END b_d[480]
  PIN b_d[481]
    DIRECTION INPUT ;
    USE SIGNAL ;
    PORT
      LAYER M5 ;
        RECT  48.432 0 48.456 0.084 ;
    END
  END b_d[481]
  PIN b_d[482]
    DIRECTION INPUT ;
    USE SIGNAL ;
    PORT
      LAYER M5 ;
        RECT  48.528 0 48.552 0.084 ;
    END
  END b_d[482]
  PIN b_d[483]
    DIRECTION INPUT ;
    USE SIGNAL ;
    PORT
      LAYER M5 ;
        RECT  48.624 0 48.648 0.084 ;
    END
  END b_d[483]
  PIN b_d[484]
    DIRECTION INPUT ;
    USE SIGNAL ;
    PORT
      LAYER M5 ;
        RECT  48.72 0 48.744 0.084 ;
    END
  END b_d[484]
  PIN b_d[485]
    DIRECTION INPUT ;
    USE SIGNAL ;
    PORT
      LAYER M5 ;
        RECT  48.816 0 48.84 0.084 ;
    END
  END b_d[485]
  PIN b_d[486]
    DIRECTION INPUT ;
    USE SIGNAL ;
    PORT
      LAYER M5 ;
        RECT  48.912 0 48.936 0.084 ;
    END
  END b_d[486]
  PIN b_d[487]
    DIRECTION INPUT ;
    USE SIGNAL ;
    PORT
      LAYER M5 ;
        RECT  49.008 0 49.032 0.084 ;
    END
  END b_d[487]
  PIN b_d[488]
    DIRECTION INPUT ;
    USE SIGNAL ;
    PORT
      LAYER M5 ;
        RECT  49.104 0 49.128 0.084 ;
    END
  END b_d[488]
  PIN b_d[489]
    DIRECTION INPUT ;
    USE SIGNAL ;
    PORT
      LAYER M5 ;
        RECT  49.2 0 49.224 0.084 ;
    END
  END b_d[489]
  PIN b_d[48]
    DIRECTION INPUT ;
    USE SIGNAL ;
    PORT
      LAYER M5 ;
        RECT  36.816 0 36.84 0.084 ;
    END
  END b_d[48]
  PIN b_d[490]
    DIRECTION INPUT ;
    USE SIGNAL ;
    PORT
      LAYER M5 ;
        RECT  49.296 0 49.32 0.084 ;
    END
  END b_d[490]
  PIN b_d[491]
    DIRECTION INPUT ;
    USE SIGNAL ;
    PORT
      LAYER M5 ;
        RECT  49.392 0 49.416 0.084 ;
    END
  END b_d[491]
  PIN b_d[492]
    DIRECTION INPUT ;
    USE SIGNAL ;
    PORT
      LAYER M5 ;
        RECT  49.488 0 49.512 0.084 ;
    END
  END b_d[492]
  PIN b_d[493]
    DIRECTION INPUT ;
    USE SIGNAL ;
    PORT
      LAYER M5 ;
        RECT  49.584 0 49.608 0.084 ;
    END
  END b_d[493]
  PIN b_d[494]
    DIRECTION INPUT ;
    USE SIGNAL ;
    PORT
      LAYER M5 ;
        RECT  49.68 0 49.704 0.084 ;
    END
  END b_d[494]
  PIN b_d[495]
    DIRECTION INPUT ;
    USE SIGNAL ;
    PORT
      LAYER M5 ;
        RECT  49.776 0 49.8 0.084 ;
    END
  END b_d[495]
  PIN b_d[496]
    DIRECTION INPUT ;
    USE SIGNAL ;
    PORT
      LAYER M5 ;
        RECT  49.872 0 49.896 0.084 ;
    END
  END b_d[496]
  PIN b_d[497]
    DIRECTION INPUT ;
    USE SIGNAL ;
    PORT
      LAYER M5 ;
        RECT  49.968 0 49.992 0.084 ;
    END
  END b_d[497]
  PIN b_d[498]
    DIRECTION INPUT ;
    USE SIGNAL ;
    PORT
      LAYER M5 ;
        RECT  50.064 0 50.088 0.084 ;
    END
  END b_d[498]
  PIN b_d[499]
    DIRECTION INPUT ;
    USE SIGNAL ;
    PORT
      LAYER M5 ;
        RECT  50.16 0 50.184 0.084 ;
    END
  END b_d[499]
  PIN b_d[49]
    DIRECTION INPUT ;
    USE SIGNAL ;
    PORT
      LAYER M5 ;
        RECT  36.912 0 36.936 0.084 ;
    END
  END b_d[49]
  PIN b_d[4]
    DIRECTION INPUT ;
    USE SIGNAL ;
    PORT
      LAYER M5 ;
        RECT  26.448 0 26.472 0.084 ;
    END
  END b_d[4]
  PIN b_d[500]
    DIRECTION INPUT ;
    USE SIGNAL ;
    PORT
      LAYER M5 ;
        RECT  50.256 0 50.28 0.084 ;
    END
  END b_d[500]
  PIN b_d[501]
    DIRECTION INPUT ;
    USE SIGNAL ;
    PORT
      LAYER M5 ;
        RECT  50.352 0 50.376 0.084 ;
    END
  END b_d[501]
  PIN b_d[502]
    DIRECTION INPUT ;
    USE SIGNAL ;
    PORT
      LAYER M5 ;
        RECT  50.448 0 50.472 0.084 ;
    END
  END b_d[502]
  PIN b_d[503]
    DIRECTION INPUT ;
    USE SIGNAL ;
    PORT
      LAYER M5 ;
        RECT  50.544 0 50.568 0.084 ;
    END
  END b_d[503]
  PIN b_d[504]
    DIRECTION INPUT ;
    USE SIGNAL ;
    PORT
      LAYER M5 ;
        RECT  50.64 0 50.664 0.084 ;
    END
  END b_d[504]
  PIN b_d[505]
    DIRECTION INPUT ;
    USE SIGNAL ;
    PORT
      LAYER M5 ;
        RECT  50.736 0 50.76 0.084 ;
    END
  END b_d[505]
  PIN b_d[506]
    DIRECTION INPUT ;
    USE SIGNAL ;
    PORT
      LAYER M5 ;
        RECT  50.832 0 50.856 0.084 ;
    END
  END b_d[506]
  PIN b_d[507]
    DIRECTION INPUT ;
    USE SIGNAL ;
    PORT
      LAYER M5 ;
        RECT  50.928 0 50.952 0.084 ;
    END
  END b_d[507]
  PIN b_d[50]
    DIRECTION INPUT ;
    USE SIGNAL ;
    PORT
      LAYER M5 ;
        RECT  37.008 0 37.032 0.084 ;
    END
  END b_d[50]
  PIN b_d[51]
    DIRECTION INPUT ;
    USE SIGNAL ;
    PORT
      LAYER M5 ;
        RECT  37.104 0 37.128 0.084 ;
    END
  END b_d[51]
  PIN b_d[52]
    DIRECTION INPUT ;
    USE SIGNAL ;
    PORT
      LAYER M5 ;
        RECT  37.2 0 37.224 0.084 ;
    END
  END b_d[52]
  PIN b_d[53]
    DIRECTION INPUT ;
    USE SIGNAL ;
    PORT
      LAYER M5 ;
        RECT  37.296 0 37.32 0.084 ;
    END
  END b_d[53]
  PIN b_d[54]
    DIRECTION INPUT ;
    USE SIGNAL ;
    PORT
      LAYER M5 ;
        RECT  37.392 0 37.416 0.084 ;
    END
  END b_d[54]
  PIN b_d[55]
    DIRECTION INPUT ;
    USE SIGNAL ;
    PORT
      LAYER M5 ;
        RECT  37.488 0 37.512 0.084 ;
    END
  END b_d[55]
  PIN b_d[56]
    DIRECTION INPUT ;
    USE SIGNAL ;
    PORT
      LAYER M5 ;
        RECT  37.584 0 37.608 0.084 ;
    END
  END b_d[56]
  PIN b_d[57]
    DIRECTION INPUT ;
    USE SIGNAL ;
    PORT
      LAYER M5 ;
        RECT  37.68 0 37.704 0.084 ;
    END
  END b_d[57]
  PIN b_d[58]
    DIRECTION INPUT ;
    USE SIGNAL ;
    PORT
      LAYER M5 ;
        RECT  37.776 0 37.8 0.084 ;
    END
  END b_d[58]
  PIN b_d[59]
    DIRECTION INPUT ;
    USE SIGNAL ;
    PORT
      LAYER M5 ;
        RECT  37.872 0 37.896 0.084 ;
    END
  END b_d[59]
  PIN b_d[5]
    DIRECTION INPUT ;
    USE SIGNAL ;
    PORT
      LAYER M5 ;
        RECT  26.544 0 26.568 0.084 ;
    END
  END b_d[5]
  PIN b_d[60]
    DIRECTION INPUT ;
    USE SIGNAL ;
    PORT
      LAYER M5 ;
        RECT  37.968 0 37.992 0.084 ;
    END
  END b_d[60]
  PIN b_d[61]
    DIRECTION INPUT ;
    USE SIGNAL ;
    PORT
      LAYER M5 ;
        RECT  38.064 0 38.088 0.084 ;
    END
  END b_d[61]
  PIN b_d[62]
    DIRECTION INPUT ;
    USE SIGNAL ;
    PORT
      LAYER M5 ;
        RECT  38.16 0 38.184 0.084 ;
    END
  END b_d[62]
  PIN b_d[63]
    DIRECTION INPUT ;
    USE SIGNAL ;
    PORT
      LAYER M5 ;
        RECT  38.256 0 38.28 0.084 ;
    END
  END b_d[63]
  PIN b_d[64]
    DIRECTION INPUT ;
    USE SIGNAL ;
    PORT
      LAYER M5 ;
        RECT  29.136 0 29.16 0.084 ;
    END
  END b_d[64]
  PIN b_d[65]
    DIRECTION INPUT ;
    USE SIGNAL ;
    PORT
      LAYER M5 ;
        RECT  29.232 0 29.256 0.084 ;
    END
  END b_d[65]
  PIN b_d[66]
    DIRECTION INPUT ;
    USE SIGNAL ;
    PORT
      LAYER M5 ;
        RECT  29.328 0 29.352 0.084 ;
    END
  END b_d[66]
  PIN b_d[67]
    DIRECTION INPUT ;
    USE SIGNAL ;
    PORT
      LAYER M5 ;
        RECT  29.424 0 29.448 0.084 ;
    END
  END b_d[67]
  PIN b_d[68]
    DIRECTION INPUT ;
    USE SIGNAL ;
    PORT
      LAYER M5 ;
        RECT  29.52 0 29.544 0.084 ;
    END
  END b_d[68]
  PIN b_d[69]
    DIRECTION INPUT ;
    USE SIGNAL ;
    PORT
      LAYER M5 ;
        RECT  29.616 0 29.64 0.084 ;
    END
  END b_d[69]
  PIN b_d[6]
    DIRECTION INPUT ;
    USE SIGNAL ;
    PORT
      LAYER M5 ;
        RECT  26.64 0 26.664 0.084 ;
    END
  END b_d[6]
  PIN b_d[70]
    DIRECTION INPUT ;
    USE SIGNAL ;
    PORT
      LAYER M5 ;
        RECT  29.712 0 29.736 0.084 ;
    END
  END b_d[70]
  PIN b_d[71]
    DIRECTION INPUT ;
    USE SIGNAL ;
    PORT
      LAYER M5 ;
        RECT  29.808 0 29.832 0.084 ;
    END
  END b_d[71]
  PIN b_d[72]
    DIRECTION INPUT ;
    USE SIGNAL ;
    PORT
      LAYER M5 ;
        RECT  29.904 0 29.928 0.084 ;
    END
  END b_d[72]
  PIN b_d[73]
    DIRECTION INPUT ;
    USE SIGNAL ;
    PORT
      LAYER M5 ;
        RECT  30 0 30.024 0.084 ;
    END
  END b_d[73]
  PIN b_d[74]
    DIRECTION INPUT ;
    USE SIGNAL ;
    PORT
      LAYER M5 ;
        RECT  30.096 0 30.12 0.084 ;
    END
  END b_d[74]
  PIN b_d[75]
    DIRECTION INPUT ;
    USE SIGNAL ;
    PORT
      LAYER M5 ;
        RECT  30.192 0 30.216 0.084 ;
    END
  END b_d[75]
  PIN b_d[76]
    DIRECTION INPUT ;
    USE SIGNAL ;
    PORT
      LAYER M5 ;
        RECT  30.288 0 30.312 0.084 ;
    END
  END b_d[76]
  PIN b_d[77]
    DIRECTION INPUT ;
    USE SIGNAL ;
    PORT
      LAYER M5 ;
        RECT  30.384 0 30.408 0.084 ;
    END
  END b_d[77]
  PIN b_d[78]
    DIRECTION INPUT ;
    USE SIGNAL ;
    PORT
      LAYER M5 ;
        RECT  30.48 0 30.504 0.084 ;
    END
  END b_d[78]
  PIN b_d[79]
    DIRECTION INPUT ;
    USE SIGNAL ;
    PORT
      LAYER M5 ;
        RECT  30.576 0 30.6 0.084 ;
    END
  END b_d[79]
  PIN b_d[7]
    DIRECTION INPUT ;
    USE SIGNAL ;
    PORT
      LAYER M5 ;
        RECT  26.736 0 26.76 0.084 ;
    END
  END b_d[7]
  PIN b_d[80]
    DIRECTION INPUT ;
    USE SIGNAL ;
    PORT
      LAYER M5 ;
        RECT  30.672 0 30.696 0.084 ;
    END
  END b_d[80]
  PIN b_d[81]
    DIRECTION INPUT ;
    USE SIGNAL ;
    PORT
      LAYER M5 ;
        RECT  30.768 0 30.792 0.084 ;
    END
  END b_d[81]
  PIN b_d[82]
    DIRECTION INPUT ;
    USE SIGNAL ;
    PORT
      LAYER M5 ;
        RECT  30.864 0 30.888 0.084 ;
    END
  END b_d[82]
  PIN b_d[83]
    DIRECTION INPUT ;
    USE SIGNAL ;
    PORT
      LAYER M5 ;
        RECT  30.96 0 30.984 0.084 ;
    END
  END b_d[83]
  PIN b_d[84]
    DIRECTION INPUT ;
    USE SIGNAL ;
    PORT
      LAYER M5 ;
        RECT  31.056 0 31.08 0.084 ;
    END
  END b_d[84]
  PIN b_d[85]
    DIRECTION INPUT ;
    USE SIGNAL ;
    PORT
      LAYER M5 ;
        RECT  31.152 0 31.176 0.084 ;
    END
  END b_d[85]
  PIN b_d[86]
    DIRECTION INPUT ;
    USE SIGNAL ;
    PORT
      LAYER M5 ;
        RECT  31.248 0 31.272 0.084 ;
    END
  END b_d[86]
  PIN b_d[87]
    DIRECTION INPUT ;
    USE SIGNAL ;
    PORT
      LAYER M5 ;
        RECT  31.344 0 31.368 0.084 ;
    END
  END b_d[87]
  PIN b_d[88]
    DIRECTION INPUT ;
    USE SIGNAL ;
    PORT
      LAYER M5 ;
        RECT  31.44 0 31.464 0.084 ;
    END
  END b_d[88]
  PIN b_d[89]
    DIRECTION INPUT ;
    USE SIGNAL ;
    PORT
      LAYER M5 ;
        RECT  31.536 0 31.56 0.084 ;
    END
  END b_d[89]
  PIN b_d[8]
    DIRECTION INPUT ;
    USE SIGNAL ;
    PORT
      LAYER M5 ;
        RECT  26.832 0 26.856 0.084 ;
    END
  END b_d[8]
  PIN b_d[90]
    DIRECTION INPUT ;
    USE SIGNAL ;
    PORT
      LAYER M5 ;
        RECT  31.632 0 31.656 0.084 ;
    END
  END b_d[90]
  PIN b_d[91]
    DIRECTION INPUT ;
    USE SIGNAL ;
    PORT
      LAYER M5 ;
        RECT  31.728 0 31.752 0.084 ;
    END
  END b_d[91]
  PIN b_d[92]
    DIRECTION INPUT ;
    USE SIGNAL ;
    PORT
      LAYER M5 ;
        RECT  31.824 0 31.848 0.084 ;
    END
  END b_d[92]
  PIN b_d[93]
    DIRECTION INPUT ;
    USE SIGNAL ;
    PORT
      LAYER M5 ;
        RECT  31.92 0 31.944 0.084 ;
    END
  END b_d[93]
  PIN b_d[94]
    DIRECTION INPUT ;
    USE SIGNAL ;
    PORT
      LAYER M5 ;
        RECT  32.016 0 32.04 0.084 ;
    END
  END b_d[94]
  PIN b_d[95]
    DIRECTION INPUT ;
    USE SIGNAL ;
    PORT
      LAYER M5 ;
        RECT  32.112 0 32.136 0.084 ;
    END
  END b_d[95]
  PIN b_d[96]
    DIRECTION INPUT ;
    USE SIGNAL ;
    PORT
      LAYER M5 ;
        RECT  32.208 0 32.232 0.084 ;
    END
  END b_d[96]
  PIN b_d[97]
    DIRECTION INPUT ;
    USE SIGNAL ;
    PORT
      LAYER M5 ;
        RECT  32.304 0 32.328 0.084 ;
    END
  END b_d[97]
  PIN b_d[98]
    DIRECTION INPUT ;
    USE SIGNAL ;
    PORT
      LAYER M5 ;
        RECT  32.4 0 32.424 0.084 ;
    END
  END b_d[98]
  PIN b_d[99]
    DIRECTION INPUT ;
    USE SIGNAL ;
    PORT
      LAYER M5 ;
        RECT  32.496 0 32.52 0.084 ;
    END
  END b_d[99]
  PIN b_d[9]
    DIRECTION INPUT ;
    USE SIGNAL ;
    PORT
      LAYER M5 ;
        RECT  26.928 0 26.952 0.084 ;
    END
  END b_d[9]
  PIN b_r
    DIRECTION OUTPUT ;
    USE SIGNAL ;
    PORT
      LAYER M5 ;
        RECT  51.024 0 51.048 0.084 ;
    END
  END b_r
  PIN ck
    DIRECTION INPUT ;
    USE SIGNAL ;
    PORT
      LAYER M5 ;
        RECT  4.176 103.572 4.2 103.656 ;
    END
  END ck
  PIN rst_n
    DIRECTION INPUT ;
    USE SIGNAL ;
    PORT
      LAYER M5 ;
        RECT  4.272 103.572 4.296 103.656 ;
    END
  END rst_n
  PIN tap_d[0]
    DIRECTION OUTPUT ;
    USE SIGNAL ;
    PORT
      LAYER M4 ;
        RECT  0 58.416 0.084 58.44 ;
    END
  END tap_d[0]
  PIN tap_d[100]
    DIRECTION OUTPUT ;
    USE SIGNAL ;
    PORT
      LAYER M4 ;
        RECT  0 52.656 0.084 52.68 ;
    END
  END tap_d[100]
  PIN tap_d[101]
    DIRECTION OUTPUT ;
    USE SIGNAL ;
    PORT
      LAYER M4 ;
        RECT  0 52.752 0.084 52.776 ;
    END
  END tap_d[101]
  PIN tap_d[102]
    DIRECTION OUTPUT ;
    USE SIGNAL ;
    PORT
      LAYER M4 ;
        RECT  0 52.848 0.084 52.872 ;
    END
  END tap_d[102]
  PIN tap_d[103]
    DIRECTION OUTPUT ;
    USE SIGNAL ;
    PORT
      LAYER M4 ;
        RECT  0 52.944 0.084 52.968 ;
    END
  END tap_d[103]
  PIN tap_d[104]
    DIRECTION OUTPUT ;
    USE SIGNAL ;
    PORT
      LAYER M4 ;
        RECT  0 53.04 0.084 53.064 ;
    END
  END tap_d[104]
  PIN tap_d[105]
    DIRECTION OUTPUT ;
    USE SIGNAL ;
    PORT
      LAYER M4 ;
        RECT  0 53.136 0.084 53.16 ;
    END
  END tap_d[105]
  PIN tap_d[106]
    DIRECTION OUTPUT ;
    USE SIGNAL ;
    PORT
      LAYER M4 ;
        RECT  0 53.232 0.084 53.256 ;
    END
  END tap_d[106]
  PIN tap_d[107]
    DIRECTION OUTPUT ;
    USE SIGNAL ;
    PORT
      LAYER M4 ;
        RECT  0 53.328 0.084 53.352 ;
    END
  END tap_d[107]
  PIN tap_d[108]
    DIRECTION OUTPUT ;
    USE SIGNAL ;
    PORT
      LAYER M4 ;
        RECT  0 53.424 0.084 53.448 ;
    END
  END tap_d[108]
  PIN tap_d[109]
    DIRECTION OUTPUT ;
    USE SIGNAL ;
    PORT
      LAYER M4 ;
        RECT  0 53.52 0.084 53.544 ;
    END
  END tap_d[109]
  PIN tap_d[10]
    DIRECTION OUTPUT ;
    USE SIGNAL ;
    PORT
      LAYER M4 ;
        RECT  0 59.376 0.084 59.4 ;
    END
  END tap_d[10]
  PIN tap_d[110]
    DIRECTION OUTPUT ;
    USE SIGNAL ;
    PORT
      LAYER M4 ;
        RECT  0 53.616 0.084 53.64 ;
    END
  END tap_d[110]
  PIN tap_d[111]
    DIRECTION OUTPUT ;
    USE SIGNAL ;
    PORT
      LAYER M4 ;
        RECT  0 53.712 0.084 53.736 ;
    END
  END tap_d[111]
  PIN tap_d[112]
    DIRECTION OUTPUT ;
    USE SIGNAL ;
    PORT
      LAYER M4 ;
        RECT  0 53.808 0.084 53.832 ;
    END
  END tap_d[112]
  PIN tap_d[113]
    DIRECTION OUTPUT ;
    USE SIGNAL ;
    PORT
      LAYER M4 ;
        RECT  0 53.904 0.084 53.928 ;
    END
  END tap_d[113]
  PIN tap_d[114]
    DIRECTION OUTPUT ;
    USE SIGNAL ;
    PORT
      LAYER M4 ;
        RECT  0 54 0.084 54.024 ;
    END
  END tap_d[114]
  PIN tap_d[115]
    DIRECTION OUTPUT ;
    USE SIGNAL ;
    PORT
      LAYER M4 ;
        RECT  0 54.096 0.084 54.12 ;
    END
  END tap_d[115]
  PIN tap_d[116]
    DIRECTION OUTPUT ;
    USE SIGNAL ;
    PORT
      LAYER M4 ;
        RECT  0 54.192 0.084 54.216 ;
    END
  END tap_d[116]
  PIN tap_d[117]
    DIRECTION OUTPUT ;
    USE SIGNAL ;
    PORT
      LAYER M4 ;
        RECT  0 54.288 0.084 54.312 ;
    END
  END tap_d[117]
  PIN tap_d[118]
    DIRECTION OUTPUT ;
    USE SIGNAL ;
    PORT
      LAYER M4 ;
        RECT  0 54.384 0.084 54.408 ;
    END
  END tap_d[118]
  PIN tap_d[119]
    DIRECTION OUTPUT ;
    USE SIGNAL ;
    PORT
      LAYER M4 ;
        RECT  0 54.48 0.084 54.504 ;
    END
  END tap_d[119]
  PIN tap_d[11]
    DIRECTION OUTPUT ;
    USE SIGNAL ;
    PORT
      LAYER M4 ;
        RECT  0 59.472 0.084 59.496 ;
    END
  END tap_d[11]
  PIN tap_d[120]
    DIRECTION OUTPUT ;
    USE SIGNAL ;
    PORT
      LAYER M4 ;
        RECT  0 54.576 0.084 54.6 ;
    END
  END tap_d[120]
  PIN tap_d[121]
    DIRECTION OUTPUT ;
    USE SIGNAL ;
    PORT
      LAYER M4 ;
        RECT  0 54.672 0.084 54.696 ;
    END
  END tap_d[121]
  PIN tap_d[122]
    DIRECTION OUTPUT ;
    USE SIGNAL ;
    PORT
      LAYER M4 ;
        RECT  0 54.768 0.084 54.792 ;
    END
  END tap_d[122]
  PIN tap_d[123]
    DIRECTION OUTPUT ;
    USE SIGNAL ;
    PORT
      LAYER M4 ;
        RECT  0 54.864 0.084 54.888 ;
    END
  END tap_d[123]
  PIN tap_d[124]
    DIRECTION OUTPUT ;
    USE SIGNAL ;
    PORT
      LAYER M4 ;
        RECT  0 54.96 0.084 54.984 ;
    END
  END tap_d[124]
  PIN tap_d[125]
    DIRECTION OUTPUT ;
    USE SIGNAL ;
    PORT
      LAYER M4 ;
        RECT  0 55.056 0.084 55.08 ;
    END
  END tap_d[125]
  PIN tap_d[126]
    DIRECTION OUTPUT ;
    USE SIGNAL ;
    PORT
      LAYER M4 ;
        RECT  0 55.152 0.084 55.176 ;
    END
  END tap_d[126]
  PIN tap_d[127]
    DIRECTION OUTPUT ;
    USE SIGNAL ;
    PORT
      LAYER M4 ;
        RECT  0 55.248 0.084 55.272 ;
    END
  END tap_d[127]
  PIN tap_d[128]
    DIRECTION OUTPUT ;
    USE SIGNAL ;
    PORT
      LAYER M4 ;
        RECT  0 55.344 0.084 55.368 ;
    END
  END tap_d[128]
  PIN tap_d[129]
    DIRECTION OUTPUT ;
    USE SIGNAL ;
    PORT
      LAYER M4 ;
        RECT  0 55.44 0.084 55.464 ;
    END
  END tap_d[129]
  PIN tap_d[12]
    DIRECTION OUTPUT ;
    USE SIGNAL ;
    PORT
      LAYER M4 ;
        RECT  0 59.568 0.084 59.592 ;
    END
  END tap_d[12]
  PIN tap_d[130]
    DIRECTION OUTPUT ;
    USE SIGNAL ;
    PORT
      LAYER M4 ;
        RECT  0 55.536 0.084 55.56 ;
    END
  END tap_d[130]
  PIN tap_d[131]
    DIRECTION OUTPUT ;
    USE SIGNAL ;
    PORT
      LAYER M4 ;
        RECT  0 55.632 0.084 55.656 ;
    END
  END tap_d[131]
  PIN tap_d[132]
    DIRECTION OUTPUT ;
    USE SIGNAL ;
    PORT
      LAYER M4 ;
        RECT  0 55.728 0.084 55.752 ;
    END
  END tap_d[132]
  PIN tap_d[133]
    DIRECTION OUTPUT ;
    USE SIGNAL ;
    PORT
      LAYER M4 ;
        RECT  0 55.824 0.084 55.848 ;
    END
  END tap_d[133]
  PIN tap_d[134]
    DIRECTION OUTPUT ;
    USE SIGNAL ;
    PORT
      LAYER M4 ;
        RECT  0 55.92 0.084 55.944 ;
    END
  END tap_d[134]
  PIN tap_d[135]
    DIRECTION OUTPUT ;
    USE SIGNAL ;
    PORT
      LAYER M4 ;
        RECT  0 56.016 0.084 56.04 ;
    END
  END tap_d[135]
  PIN tap_d[136]
    DIRECTION OUTPUT ;
    USE SIGNAL ;
    PORT
      LAYER M4 ;
        RECT  0 56.112 0.084 56.136 ;
    END
  END tap_d[136]
  PIN tap_d[137]
    DIRECTION OUTPUT ;
    USE SIGNAL ;
    PORT
      LAYER M4 ;
        RECT  0 56.208 0.084 56.232 ;
    END
  END tap_d[137]
  PIN tap_d[138]
    DIRECTION OUTPUT ;
    USE SIGNAL ;
    PORT
      LAYER M4 ;
        RECT  0 56.304 0.084 56.328 ;
    END
  END tap_d[138]
  PIN tap_d[139]
    DIRECTION OUTPUT ;
    USE SIGNAL ;
    PORT
      LAYER M4 ;
        RECT  0 56.4 0.084 56.424 ;
    END
  END tap_d[139]
  PIN tap_d[13]
    DIRECTION OUTPUT ;
    USE SIGNAL ;
    PORT
      LAYER M4 ;
        RECT  0 59.664 0.084 59.688 ;
    END
  END tap_d[13]
  PIN tap_d[140]
    DIRECTION OUTPUT ;
    USE SIGNAL ;
    PORT
      LAYER M4 ;
        RECT  0 56.496 0.084 56.52 ;
    END
  END tap_d[140]
  PIN tap_d[141]
    DIRECTION OUTPUT ;
    USE SIGNAL ;
    PORT
      LAYER M4 ;
        RECT  0 56.592 0.084 56.616 ;
    END
  END tap_d[141]
  PIN tap_d[142]
    DIRECTION OUTPUT ;
    USE SIGNAL ;
    PORT
      LAYER M4 ;
        RECT  0 56.688 0.084 56.712 ;
    END
  END tap_d[142]
  PIN tap_d[143]
    DIRECTION OUTPUT ;
    USE SIGNAL ;
    PORT
      LAYER M4 ;
        RECT  0 56.784 0.084 56.808 ;
    END
  END tap_d[143]
  PIN tap_d[144]
    DIRECTION OUTPUT ;
    USE SIGNAL ;
    PORT
      LAYER M4 ;
        RECT  0 56.88 0.084 56.904 ;
    END
  END tap_d[144]
  PIN tap_d[145]
    DIRECTION OUTPUT ;
    USE SIGNAL ;
    PORT
      LAYER M4 ;
        RECT  0 56.976 0.084 57 ;
    END
  END tap_d[145]
  PIN tap_d[146]
    DIRECTION OUTPUT ;
    USE SIGNAL ;
    PORT
      LAYER M4 ;
        RECT  0 57.072 0.084 57.096 ;
    END
  END tap_d[146]
  PIN tap_d[147]
    DIRECTION OUTPUT ;
    USE SIGNAL ;
    PORT
      LAYER M4 ;
        RECT  0 57.168 0.084 57.192 ;
    END
  END tap_d[147]
  PIN tap_d[148]
    DIRECTION OUTPUT ;
    USE SIGNAL ;
    PORT
      LAYER M4 ;
        RECT  0 57.264 0.084 57.288 ;
    END
  END tap_d[148]
  PIN tap_d[149]
    DIRECTION OUTPUT ;
    USE SIGNAL ;
    PORT
      LAYER M4 ;
        RECT  0 57.36 0.084 57.384 ;
    END
  END tap_d[149]
  PIN tap_d[14]
    DIRECTION OUTPUT ;
    USE SIGNAL ;
    PORT
      LAYER M4 ;
        RECT  0 59.76 0.084 59.784 ;
    END
  END tap_d[14]
  PIN tap_d[150]
    DIRECTION OUTPUT ;
    USE SIGNAL ;
    PORT
      LAYER M4 ;
        RECT  0 57.456 0.084 57.48 ;
    END
  END tap_d[150]
  PIN tap_d[151]
    DIRECTION OUTPUT ;
    USE SIGNAL ;
    PORT
      LAYER M4 ;
        RECT  0 57.552 0.084 57.576 ;
    END
  END tap_d[151]
  PIN tap_d[152]
    DIRECTION OUTPUT ;
    USE SIGNAL ;
    PORT
      LAYER M4 ;
        RECT  0 57.648 0.084 57.672 ;
    END
  END tap_d[152]
  PIN tap_d[153]
    DIRECTION OUTPUT ;
    USE SIGNAL ;
    PORT
      LAYER M4 ;
        RECT  0 57.744 0.084 57.768 ;
    END
  END tap_d[153]
  PIN tap_d[154]
    DIRECTION OUTPUT ;
    USE SIGNAL ;
    PORT
      LAYER M4 ;
        RECT  0 57.84 0.084 57.864 ;
    END
  END tap_d[154]
  PIN tap_d[155]
    DIRECTION OUTPUT ;
    USE SIGNAL ;
    PORT
      LAYER M4 ;
        RECT  0 57.936 0.084 57.96 ;
    END
  END tap_d[155]
  PIN tap_d[156]
    DIRECTION OUTPUT ;
    USE SIGNAL ;
    PORT
      LAYER M4 ;
        RECT  0 58.032 0.084 58.056 ;
    END
  END tap_d[156]
  PIN tap_d[157]
    DIRECTION OUTPUT ;
    USE SIGNAL ;
    PORT
      LAYER M4 ;
        RECT  0 58.128 0.084 58.152 ;
    END
  END tap_d[157]
  PIN tap_d[158]
    DIRECTION OUTPUT ;
    USE SIGNAL ;
    PORT
      LAYER M4 ;
        RECT  0 58.224 0.084 58.248 ;
    END
  END tap_d[158]
  PIN tap_d[159]
    DIRECTION OUTPUT ;
    USE SIGNAL ;
    PORT
      LAYER M4 ;
        RECT  0 58.32 0.084 58.344 ;
    END
  END tap_d[159]
  PIN tap_d[15]
    DIRECTION OUTPUT ;
    USE SIGNAL ;
    PORT
      LAYER M4 ;
        RECT  0 59.856 0.084 59.88 ;
    END
  END tap_d[15]
  PIN tap_d[160]
    DIRECTION OUTPUT ;
    USE SIGNAL ;
    PORT
      LAYER M4 ;
        RECT  0 61.488 0.084 61.512 ;
    END
  END tap_d[160]
  PIN tap_d[161]
    DIRECTION OUTPUT ;
    USE SIGNAL ;
    PORT
      LAYER M4 ;
        RECT  0 61.584 0.084 61.608 ;
    END
  END tap_d[161]
  PIN tap_d[162]
    DIRECTION OUTPUT ;
    USE SIGNAL ;
    PORT
      LAYER M4 ;
        RECT  0 61.68 0.084 61.704 ;
    END
  END tap_d[162]
  PIN tap_d[163]
    DIRECTION OUTPUT ;
    USE SIGNAL ;
    PORT
      LAYER M4 ;
        RECT  0 61.776 0.084 61.8 ;
    END
  END tap_d[163]
  PIN tap_d[164]
    DIRECTION OUTPUT ;
    USE SIGNAL ;
    PORT
      LAYER M4 ;
        RECT  0 61.872 0.084 61.896 ;
    END
  END tap_d[164]
  PIN tap_d[165]
    DIRECTION OUTPUT ;
    USE SIGNAL ;
    PORT
      LAYER M4 ;
        RECT  0 61.968 0.084 61.992 ;
    END
  END tap_d[165]
  PIN tap_d[166]
    DIRECTION OUTPUT ;
    USE SIGNAL ;
    PORT
      LAYER M4 ;
        RECT  0 62.064 0.084 62.088 ;
    END
  END tap_d[166]
  PIN tap_d[167]
    DIRECTION OUTPUT ;
    USE SIGNAL ;
    PORT
      LAYER M4 ;
        RECT  0 62.16 0.084 62.184 ;
    END
  END tap_d[167]
  PIN tap_d[168]
    DIRECTION OUTPUT ;
    USE SIGNAL ;
    PORT
      LAYER M4 ;
        RECT  0 62.256 0.084 62.28 ;
    END
  END tap_d[168]
  PIN tap_d[169]
    DIRECTION OUTPUT ;
    USE SIGNAL ;
    PORT
      LAYER M4 ;
        RECT  0 62.352 0.084 62.376 ;
    END
  END tap_d[169]
  PIN tap_d[16]
    DIRECTION OUTPUT ;
    USE SIGNAL ;
    PORT
      LAYER M4 ;
        RECT  0 59.952 0.084 59.976 ;
    END
  END tap_d[16]
  PIN tap_d[170]
    DIRECTION OUTPUT ;
    USE SIGNAL ;
    PORT
      LAYER M4 ;
        RECT  0 62.448 0.084 62.472 ;
    END
  END tap_d[170]
  PIN tap_d[171]
    DIRECTION OUTPUT ;
    USE SIGNAL ;
    PORT
      LAYER M4 ;
        RECT  0 62.544 0.084 62.568 ;
    END
  END tap_d[171]
  PIN tap_d[172]
    DIRECTION OUTPUT ;
    USE SIGNAL ;
    PORT
      LAYER M4 ;
        RECT  0 62.64 0.084 62.664 ;
    END
  END tap_d[172]
  PIN tap_d[173]
    DIRECTION OUTPUT ;
    USE SIGNAL ;
    PORT
      LAYER M4 ;
        RECT  0 62.736 0.084 62.76 ;
    END
  END tap_d[173]
  PIN tap_d[174]
    DIRECTION OUTPUT ;
    USE SIGNAL ;
    PORT
      LAYER M4 ;
        RECT  0 62.832 0.084 62.856 ;
    END
  END tap_d[174]
  PIN tap_d[175]
    DIRECTION OUTPUT ;
    USE SIGNAL ;
    PORT
      LAYER M4 ;
        RECT  0 62.928 0.084 62.952 ;
    END
  END tap_d[175]
  PIN tap_d[176]
    DIRECTION OUTPUT ;
    USE SIGNAL ;
    PORT
      LAYER M4 ;
        RECT  0 63.024 0.084 63.048 ;
    END
  END tap_d[176]
  PIN tap_d[177]
    DIRECTION OUTPUT ;
    USE SIGNAL ;
    PORT
      LAYER M4 ;
        RECT  0 63.12 0.084 63.144 ;
    END
  END tap_d[177]
  PIN tap_d[178]
    DIRECTION OUTPUT ;
    USE SIGNAL ;
    PORT
      LAYER M4 ;
        RECT  0 63.216 0.084 63.24 ;
    END
  END tap_d[178]
  PIN tap_d[179]
    DIRECTION OUTPUT ;
    USE SIGNAL ;
    PORT
      LAYER M4 ;
        RECT  0 63.312 0.084 63.336 ;
    END
  END tap_d[179]
  PIN tap_d[17]
    DIRECTION OUTPUT ;
    USE SIGNAL ;
    PORT
      LAYER M4 ;
        RECT  0 60.048 0.084 60.072 ;
    END
  END tap_d[17]
  PIN tap_d[180]
    DIRECTION OUTPUT ;
    USE SIGNAL ;
    PORT
      LAYER M4 ;
        RECT  0 63.408 0.084 63.432 ;
    END
  END tap_d[180]
  PIN tap_d[181]
    DIRECTION OUTPUT ;
    USE SIGNAL ;
    PORT
      LAYER M4 ;
        RECT  0 63.504 0.084 63.528 ;
    END
  END tap_d[181]
  PIN tap_d[182]
    DIRECTION OUTPUT ;
    USE SIGNAL ;
    PORT
      LAYER M4 ;
        RECT  0 63.6 0.084 63.624 ;
    END
  END tap_d[182]
  PIN tap_d[183]
    DIRECTION OUTPUT ;
    USE SIGNAL ;
    PORT
      LAYER M4 ;
        RECT  0 63.696 0.084 63.72 ;
    END
  END tap_d[183]
  PIN tap_d[184]
    DIRECTION OUTPUT ;
    USE SIGNAL ;
    PORT
      LAYER M4 ;
        RECT  0 63.792 0.084 63.816 ;
    END
  END tap_d[184]
  PIN tap_d[185]
    DIRECTION OUTPUT ;
    USE SIGNAL ;
    PORT
      LAYER M4 ;
        RECT  0 63.888 0.084 63.912 ;
    END
  END tap_d[185]
  PIN tap_d[186]
    DIRECTION OUTPUT ;
    USE SIGNAL ;
    PORT
      LAYER M4 ;
        RECT  0 63.984 0.084 64.008 ;
    END
  END tap_d[186]
  PIN tap_d[187]
    DIRECTION OUTPUT ;
    USE SIGNAL ;
    PORT
      LAYER M4 ;
        RECT  0 64.08 0.084 64.104 ;
    END
  END tap_d[187]
  PIN tap_d[188]
    DIRECTION OUTPUT ;
    USE SIGNAL ;
    PORT
      LAYER M4 ;
        RECT  0 64.176 0.084 64.2 ;
    END
  END tap_d[188]
  PIN tap_d[189]
    DIRECTION OUTPUT ;
    USE SIGNAL ;
    PORT
      LAYER M4 ;
        RECT  0 64.272 0.084 64.296 ;
    END
  END tap_d[189]
  PIN tap_d[18]
    DIRECTION OUTPUT ;
    USE SIGNAL ;
    PORT
      LAYER M4 ;
        RECT  0 60.144 0.084 60.168 ;
    END
  END tap_d[18]
  PIN tap_d[190]
    DIRECTION OUTPUT ;
    USE SIGNAL ;
    PORT
      LAYER M4 ;
        RECT  0 64.368 0.084 64.392 ;
    END
  END tap_d[190]
  PIN tap_d[191]
    DIRECTION OUTPUT ;
    USE SIGNAL ;
    PORT
      LAYER M4 ;
        RECT  0 64.464 0.084 64.488 ;
    END
  END tap_d[191]
  PIN tap_d[192]
    DIRECTION OUTPUT ;
    USE SIGNAL ;
    PORT
      LAYER M4 ;
        RECT  0 39.216 0.084 39.24 ;
    END
  END tap_d[192]
  PIN tap_d[193]
    DIRECTION OUTPUT ;
    USE SIGNAL ;
    PORT
      LAYER M4 ;
        RECT  0 39.312 0.084 39.336 ;
    END
  END tap_d[193]
  PIN tap_d[194]
    DIRECTION OUTPUT ;
    USE SIGNAL ;
    PORT
      LAYER M4 ;
        RECT  0 39.408 0.084 39.432 ;
    END
  END tap_d[194]
  PIN tap_d[195]
    DIRECTION OUTPUT ;
    USE SIGNAL ;
    PORT
      LAYER M4 ;
        RECT  0 39.504 0.084 39.528 ;
    END
  END tap_d[195]
  PIN tap_d[196]
    DIRECTION OUTPUT ;
    USE SIGNAL ;
    PORT
      LAYER M4 ;
        RECT  0 39.6 0.084 39.624 ;
    END
  END tap_d[196]
  PIN tap_d[197]
    DIRECTION OUTPUT ;
    USE SIGNAL ;
    PORT
      LAYER M4 ;
        RECT  0 39.696 0.084 39.72 ;
    END
  END tap_d[197]
  PIN tap_d[198]
    DIRECTION OUTPUT ;
    USE SIGNAL ;
    PORT
      LAYER M4 ;
        RECT  0 39.792 0.084 39.816 ;
    END
  END tap_d[198]
  PIN tap_d[199]
    DIRECTION OUTPUT ;
    USE SIGNAL ;
    PORT
      LAYER M4 ;
        RECT  0 39.888 0.084 39.912 ;
    END
  END tap_d[199]
  PIN tap_d[19]
    DIRECTION OUTPUT ;
    USE SIGNAL ;
    PORT
      LAYER M4 ;
        RECT  0 60.24 0.084 60.264 ;
    END
  END tap_d[19]
  PIN tap_d[1]
    DIRECTION OUTPUT ;
    USE SIGNAL ;
    PORT
      LAYER M4 ;
        RECT  0 58.512 0.084 58.536 ;
    END
  END tap_d[1]
  PIN tap_d[200]
    DIRECTION OUTPUT ;
    USE SIGNAL ;
    PORT
      LAYER M4 ;
        RECT  0 39.984 0.084 40.008 ;
    END
  END tap_d[200]
  PIN tap_d[201]
    DIRECTION OUTPUT ;
    USE SIGNAL ;
    PORT
      LAYER M4 ;
        RECT  0 40.08 0.084 40.104 ;
    END
  END tap_d[201]
  PIN tap_d[202]
    DIRECTION OUTPUT ;
    USE SIGNAL ;
    PORT
      LAYER M4 ;
        RECT  0 40.176 0.084 40.2 ;
    END
  END tap_d[202]
  PIN tap_d[203]
    DIRECTION OUTPUT ;
    USE SIGNAL ;
    PORT
      LAYER M4 ;
        RECT  0 40.272 0.084 40.296 ;
    END
  END tap_d[203]
  PIN tap_d[204]
    DIRECTION OUTPUT ;
    USE SIGNAL ;
    PORT
      LAYER M4 ;
        RECT  0 40.368 0.084 40.392 ;
    END
  END tap_d[204]
  PIN tap_d[205]
    DIRECTION OUTPUT ;
    USE SIGNAL ;
    PORT
      LAYER M4 ;
        RECT  0 40.464 0.084 40.488 ;
    END
  END tap_d[205]
  PIN tap_d[206]
    DIRECTION OUTPUT ;
    USE SIGNAL ;
    PORT
      LAYER M4 ;
        RECT  0 40.56 0.084 40.584 ;
    END
  END tap_d[206]
  PIN tap_d[207]
    DIRECTION OUTPUT ;
    USE SIGNAL ;
    PORT
      LAYER M4 ;
        RECT  0 40.656 0.084 40.68 ;
    END
  END tap_d[207]
  PIN tap_d[208]
    DIRECTION OUTPUT ;
    USE SIGNAL ;
    PORT
      LAYER M4 ;
        RECT  0 40.752 0.084 40.776 ;
    END
  END tap_d[208]
  PIN tap_d[209]
    DIRECTION OUTPUT ;
    USE SIGNAL ;
    PORT
      LAYER M4 ;
        RECT  0 40.848 0.084 40.872 ;
    END
  END tap_d[209]
  PIN tap_d[20]
    DIRECTION OUTPUT ;
    USE SIGNAL ;
    PORT
      LAYER M4 ;
        RECT  0 60.336 0.084 60.36 ;
    END
  END tap_d[20]
  PIN tap_d[210]
    DIRECTION OUTPUT ;
    USE SIGNAL ;
    PORT
      LAYER M4 ;
        RECT  0 40.944 0.084 40.968 ;
    END
  END tap_d[210]
  PIN tap_d[211]
    DIRECTION OUTPUT ;
    USE SIGNAL ;
    PORT
      LAYER M4 ;
        RECT  0 41.04 0.084 41.064 ;
    END
  END tap_d[211]
  PIN tap_d[212]
    DIRECTION OUTPUT ;
    USE SIGNAL ;
    PORT
      LAYER M4 ;
        RECT  0 41.136 0.084 41.16 ;
    END
  END tap_d[212]
  PIN tap_d[213]
    DIRECTION OUTPUT ;
    USE SIGNAL ;
    PORT
      LAYER M4 ;
        RECT  0 41.232 0.084 41.256 ;
    END
  END tap_d[213]
  PIN tap_d[214]
    DIRECTION OUTPUT ;
    USE SIGNAL ;
    PORT
      LAYER M4 ;
        RECT  0 41.328 0.084 41.352 ;
    END
  END tap_d[214]
  PIN tap_d[215]
    DIRECTION OUTPUT ;
    USE SIGNAL ;
    PORT
      LAYER M4 ;
        RECT  0 41.424 0.084 41.448 ;
    END
  END tap_d[215]
  PIN tap_d[216]
    DIRECTION OUTPUT ;
    USE SIGNAL ;
    PORT
      LAYER M4 ;
        RECT  0 41.52 0.084 41.544 ;
    END
  END tap_d[216]
  PIN tap_d[217]
    DIRECTION OUTPUT ;
    USE SIGNAL ;
    PORT
      LAYER M4 ;
        RECT  0 41.616 0.084 41.64 ;
    END
  END tap_d[217]
  PIN tap_d[218]
    DIRECTION OUTPUT ;
    USE SIGNAL ;
    PORT
      LAYER M4 ;
        RECT  0 41.712 0.084 41.736 ;
    END
  END tap_d[218]
  PIN tap_d[219]
    DIRECTION OUTPUT ;
    USE SIGNAL ;
    PORT
      LAYER M4 ;
        RECT  0 41.808 0.084 41.832 ;
    END
  END tap_d[219]
  PIN tap_d[21]
    DIRECTION OUTPUT ;
    USE SIGNAL ;
    PORT
      LAYER M4 ;
        RECT  0 60.432 0.084 60.456 ;
    END
  END tap_d[21]
  PIN tap_d[220]
    DIRECTION OUTPUT ;
    USE SIGNAL ;
    PORT
      LAYER M4 ;
        RECT  0 41.904 0.084 41.928 ;
    END
  END tap_d[220]
  PIN tap_d[221]
    DIRECTION OUTPUT ;
    USE SIGNAL ;
    PORT
      LAYER M4 ;
        RECT  0 42 0.084 42.024 ;
    END
  END tap_d[221]
  PIN tap_d[222]
    DIRECTION OUTPUT ;
    USE SIGNAL ;
    PORT
      LAYER M4 ;
        RECT  0 42.096 0.084 42.12 ;
    END
  END tap_d[222]
  PIN tap_d[223]
    DIRECTION OUTPUT ;
    USE SIGNAL ;
    PORT
      LAYER M4 ;
        RECT  0 42.192 0.084 42.216 ;
    END
  END tap_d[223]
  PIN tap_d[224]
    DIRECTION OUTPUT ;
    USE SIGNAL ;
    PORT
      LAYER M4 ;
        RECT  0 26.928 0.084 26.952 ;
    END
  END tap_d[224]
  PIN tap_d[225]
    DIRECTION OUTPUT ;
    USE SIGNAL ;
    PORT
      LAYER M4 ;
        RECT  0 27.024 0.084 27.048 ;
    END
  END tap_d[225]
  PIN tap_d[226]
    DIRECTION OUTPUT ;
    USE SIGNAL ;
    PORT
      LAYER M4 ;
        RECT  0 27.12 0.084 27.144 ;
    END
  END tap_d[226]
  PIN tap_d[227]
    DIRECTION OUTPUT ;
    USE SIGNAL ;
    PORT
      LAYER M4 ;
        RECT  0 27.216 0.084 27.24 ;
    END
  END tap_d[227]
  PIN tap_d[228]
    DIRECTION OUTPUT ;
    USE SIGNAL ;
    PORT
      LAYER M4 ;
        RECT  0 27.312 0.084 27.336 ;
    END
  END tap_d[228]
  PIN tap_d[229]
    DIRECTION OUTPUT ;
    USE SIGNAL ;
    PORT
      LAYER M4 ;
        RECT  0 27.408 0.084 27.432 ;
    END
  END tap_d[229]
  PIN tap_d[22]
    DIRECTION OUTPUT ;
    USE SIGNAL ;
    PORT
      LAYER M4 ;
        RECT  0 60.528 0.084 60.552 ;
    END
  END tap_d[22]
  PIN tap_d[230]
    DIRECTION OUTPUT ;
    USE SIGNAL ;
    PORT
      LAYER M4 ;
        RECT  0 27.504 0.084 27.528 ;
    END
  END tap_d[230]
  PIN tap_d[231]
    DIRECTION OUTPUT ;
    USE SIGNAL ;
    PORT
      LAYER M4 ;
        RECT  0 27.6 0.084 27.624 ;
    END
  END tap_d[231]
  PIN tap_d[232]
    DIRECTION OUTPUT ;
    USE SIGNAL ;
    PORT
      LAYER M4 ;
        RECT  0 27.696 0.084 27.72 ;
    END
  END tap_d[232]
  PIN tap_d[233]
    DIRECTION OUTPUT ;
    USE SIGNAL ;
    PORT
      LAYER M4 ;
        RECT  0 27.792 0.084 27.816 ;
    END
  END tap_d[233]
  PIN tap_d[234]
    DIRECTION OUTPUT ;
    USE SIGNAL ;
    PORT
      LAYER M4 ;
        RECT  0 27.888 0.084 27.912 ;
    END
  END tap_d[234]
  PIN tap_d[235]
    DIRECTION OUTPUT ;
    USE SIGNAL ;
    PORT
      LAYER M4 ;
        RECT  0 27.984 0.084 28.008 ;
    END
  END tap_d[235]
  PIN tap_d[236]
    DIRECTION OUTPUT ;
    USE SIGNAL ;
    PORT
      LAYER M4 ;
        RECT  0 28.08 0.084 28.104 ;
    END
  END tap_d[236]
  PIN tap_d[237]
    DIRECTION OUTPUT ;
    USE SIGNAL ;
    PORT
      LAYER M4 ;
        RECT  0 28.176 0.084 28.2 ;
    END
  END tap_d[237]
  PIN tap_d[238]
    DIRECTION OUTPUT ;
    USE SIGNAL ;
    PORT
      LAYER M4 ;
        RECT  0 28.272 0.084 28.296 ;
    END
  END tap_d[238]
  PIN tap_d[239]
    DIRECTION OUTPUT ;
    USE SIGNAL ;
    PORT
      LAYER M4 ;
        RECT  0 28.368 0.084 28.392 ;
    END
  END tap_d[239]
  PIN tap_d[23]
    DIRECTION OUTPUT ;
    USE SIGNAL ;
    PORT
      LAYER M4 ;
        RECT  0 60.624 0.084 60.648 ;
    END
  END tap_d[23]
  PIN tap_d[240]
    DIRECTION OUTPUT ;
    USE SIGNAL ;
    PORT
      LAYER M4 ;
        RECT  0 28.464 0.084 28.488 ;
    END
  END tap_d[240]
  PIN tap_d[241]
    DIRECTION OUTPUT ;
    USE SIGNAL ;
    PORT
      LAYER M4 ;
        RECT  0 28.56 0.084 28.584 ;
    END
  END tap_d[241]
  PIN tap_d[242]
    DIRECTION OUTPUT ;
    USE SIGNAL ;
    PORT
      LAYER M4 ;
        RECT  0 28.656 0.084 28.68 ;
    END
  END tap_d[242]
  PIN tap_d[243]
    DIRECTION OUTPUT ;
    USE SIGNAL ;
    PORT
      LAYER M4 ;
        RECT  0 28.752 0.084 28.776 ;
    END
  END tap_d[243]
  PIN tap_d[244]
    DIRECTION OUTPUT ;
    USE SIGNAL ;
    PORT
      LAYER M4 ;
        RECT  0 28.848 0.084 28.872 ;
    END
  END tap_d[244]
  PIN tap_d[245]
    DIRECTION OUTPUT ;
    USE SIGNAL ;
    PORT
      LAYER M4 ;
        RECT  0 28.944 0.084 28.968 ;
    END
  END tap_d[245]
  PIN tap_d[246]
    DIRECTION OUTPUT ;
    USE SIGNAL ;
    PORT
      LAYER M4 ;
        RECT  0 29.04 0.084 29.064 ;
    END
  END tap_d[246]
  PIN tap_d[247]
    DIRECTION OUTPUT ;
    USE SIGNAL ;
    PORT
      LAYER M4 ;
        RECT  0 29.136 0.084 29.16 ;
    END
  END tap_d[247]
  PIN tap_d[248]
    DIRECTION OUTPUT ;
    USE SIGNAL ;
    PORT
      LAYER M4 ;
        RECT  0 29.232 0.084 29.256 ;
    END
  END tap_d[248]
  PIN tap_d[249]
    DIRECTION OUTPUT ;
    USE SIGNAL ;
    PORT
      LAYER M4 ;
        RECT  0 29.328 0.084 29.352 ;
    END
  END tap_d[249]
  PIN tap_d[24]
    DIRECTION OUTPUT ;
    USE SIGNAL ;
    PORT
      LAYER M4 ;
        RECT  0 60.72 0.084 60.744 ;
    END
  END tap_d[24]
  PIN tap_d[250]
    DIRECTION OUTPUT ;
    USE SIGNAL ;
    PORT
      LAYER M4 ;
        RECT  0 29.424 0.084 29.448 ;
    END
  END tap_d[250]
  PIN tap_d[251]
    DIRECTION OUTPUT ;
    USE SIGNAL ;
    PORT
      LAYER M4 ;
        RECT  0 29.52 0.084 29.544 ;
    END
  END tap_d[251]
  PIN tap_d[252]
    DIRECTION OUTPUT ;
    USE SIGNAL ;
    PORT
      LAYER M4 ;
        RECT  0 29.616 0.084 29.64 ;
    END
  END tap_d[252]
  PIN tap_d[253]
    DIRECTION OUTPUT ;
    USE SIGNAL ;
    PORT
      LAYER M4 ;
        RECT  0 29.712 0.084 29.736 ;
    END
  END tap_d[253]
  PIN tap_d[254]
    DIRECTION OUTPUT ;
    USE SIGNAL ;
    PORT
      LAYER M4 ;
        RECT  0 29.808 0.084 29.832 ;
    END
  END tap_d[254]
  PIN tap_d[255]
    DIRECTION OUTPUT ;
    USE SIGNAL ;
    PORT
      LAYER M4 ;
        RECT  0 29.904 0.084 29.928 ;
    END
  END tap_d[255]
  PIN tap_d[256]
    DIRECTION OUTPUT ;
    USE SIGNAL ;
    PORT
      LAYER M4 ;
        RECT  0 36.144 0.084 36.168 ;
    END
  END tap_d[256]
  PIN tap_d[257]
    DIRECTION OUTPUT ;
    USE SIGNAL ;
    PORT
      LAYER M4 ;
        RECT  0 36.24 0.084 36.264 ;
    END
  END tap_d[257]
  PIN tap_d[258]
    DIRECTION OUTPUT ;
    USE SIGNAL ;
    PORT
      LAYER M4 ;
        RECT  0 36.336 0.084 36.36 ;
    END
  END tap_d[258]
  PIN tap_d[259]
    DIRECTION OUTPUT ;
    USE SIGNAL ;
    PORT
      LAYER M4 ;
        RECT  0 36.432 0.084 36.456 ;
    END
  END tap_d[259]
  PIN tap_d[25]
    DIRECTION OUTPUT ;
    USE SIGNAL ;
    PORT
      LAYER M4 ;
        RECT  0 60.816 0.084 60.84 ;
    END
  END tap_d[25]
  PIN tap_d[260]
    DIRECTION OUTPUT ;
    USE SIGNAL ;
    PORT
      LAYER M4 ;
        RECT  0 36.528 0.084 36.552 ;
    END
  END tap_d[260]
  PIN tap_d[261]
    DIRECTION OUTPUT ;
    USE SIGNAL ;
    PORT
      LAYER M4 ;
        RECT  0 36.624 0.084 36.648 ;
    END
  END tap_d[261]
  PIN tap_d[262]
    DIRECTION OUTPUT ;
    USE SIGNAL ;
    PORT
      LAYER M4 ;
        RECT  0 36.72 0.084 36.744 ;
    END
  END tap_d[262]
  PIN tap_d[263]
    DIRECTION OUTPUT ;
    USE SIGNAL ;
    PORT
      LAYER M4 ;
        RECT  0 36.816 0.084 36.84 ;
    END
  END tap_d[263]
  PIN tap_d[264]
    DIRECTION OUTPUT ;
    USE SIGNAL ;
    PORT
      LAYER M4 ;
        RECT  0 36.912 0.084 36.936 ;
    END
  END tap_d[264]
  PIN tap_d[265]
    DIRECTION OUTPUT ;
    USE SIGNAL ;
    PORT
      LAYER M4 ;
        RECT  0 37.008 0.084 37.032 ;
    END
  END tap_d[265]
  PIN tap_d[266]
    DIRECTION OUTPUT ;
    USE SIGNAL ;
    PORT
      LAYER M4 ;
        RECT  0 37.104 0.084 37.128 ;
    END
  END tap_d[266]
  PIN tap_d[267]
    DIRECTION OUTPUT ;
    USE SIGNAL ;
    PORT
      LAYER M4 ;
        RECT  0 37.2 0.084 37.224 ;
    END
  END tap_d[267]
  PIN tap_d[268]
    DIRECTION OUTPUT ;
    USE SIGNAL ;
    PORT
      LAYER M4 ;
        RECT  0 37.296 0.084 37.32 ;
    END
  END tap_d[268]
  PIN tap_d[269]
    DIRECTION OUTPUT ;
    USE SIGNAL ;
    PORT
      LAYER M4 ;
        RECT  0 37.392 0.084 37.416 ;
    END
  END tap_d[269]
  PIN tap_d[26]
    DIRECTION OUTPUT ;
    USE SIGNAL ;
    PORT
      LAYER M4 ;
        RECT  0 60.912 0.084 60.936 ;
    END
  END tap_d[26]
  PIN tap_d[270]
    DIRECTION OUTPUT ;
    USE SIGNAL ;
    PORT
      LAYER M4 ;
        RECT  0 37.488 0.084 37.512 ;
    END
  END tap_d[270]
  PIN tap_d[271]
    DIRECTION OUTPUT ;
    USE SIGNAL ;
    PORT
      LAYER M4 ;
        RECT  0 37.584 0.084 37.608 ;
    END
  END tap_d[271]
  PIN tap_d[272]
    DIRECTION OUTPUT ;
    USE SIGNAL ;
    PORT
      LAYER M4 ;
        RECT  0 37.68 0.084 37.704 ;
    END
  END tap_d[272]
  PIN tap_d[273]
    DIRECTION OUTPUT ;
    USE SIGNAL ;
    PORT
      LAYER M4 ;
        RECT  0 37.776 0.084 37.8 ;
    END
  END tap_d[273]
  PIN tap_d[274]
    DIRECTION OUTPUT ;
    USE SIGNAL ;
    PORT
      LAYER M4 ;
        RECT  0 37.872 0.084 37.896 ;
    END
  END tap_d[274]
  PIN tap_d[275]
    DIRECTION OUTPUT ;
    USE SIGNAL ;
    PORT
      LAYER M4 ;
        RECT  0 37.968 0.084 37.992 ;
    END
  END tap_d[275]
  PIN tap_d[276]
    DIRECTION OUTPUT ;
    USE SIGNAL ;
    PORT
      LAYER M4 ;
        RECT  0 38.064 0.084 38.088 ;
    END
  END tap_d[276]
  PIN tap_d[277]
    DIRECTION OUTPUT ;
    USE SIGNAL ;
    PORT
      LAYER M4 ;
        RECT  0 38.16 0.084 38.184 ;
    END
  END tap_d[277]
  PIN tap_d[278]
    DIRECTION OUTPUT ;
    USE SIGNAL ;
    PORT
      LAYER M4 ;
        RECT  0 38.256 0.084 38.28 ;
    END
  END tap_d[278]
  PIN tap_d[279]
    DIRECTION OUTPUT ;
    USE SIGNAL ;
    PORT
      LAYER M4 ;
        RECT  0 38.352 0.084 38.376 ;
    END
  END tap_d[279]
  PIN tap_d[27]
    DIRECTION OUTPUT ;
    USE SIGNAL ;
    PORT
      LAYER M4 ;
        RECT  0 61.008 0.084 61.032 ;
    END
  END tap_d[27]
  PIN tap_d[280]
    DIRECTION OUTPUT ;
    USE SIGNAL ;
    PORT
      LAYER M4 ;
        RECT  0 38.448 0.084 38.472 ;
    END
  END tap_d[280]
  PIN tap_d[281]
    DIRECTION OUTPUT ;
    USE SIGNAL ;
    PORT
      LAYER M4 ;
        RECT  0 38.544 0.084 38.568 ;
    END
  END tap_d[281]
  PIN tap_d[282]
    DIRECTION OUTPUT ;
    USE SIGNAL ;
    PORT
      LAYER M4 ;
        RECT  0 38.64 0.084 38.664 ;
    END
  END tap_d[282]
  PIN tap_d[283]
    DIRECTION OUTPUT ;
    USE SIGNAL ;
    PORT
      LAYER M4 ;
        RECT  0 38.736 0.084 38.76 ;
    END
  END tap_d[283]
  PIN tap_d[284]
    DIRECTION OUTPUT ;
    USE SIGNAL ;
    PORT
      LAYER M4 ;
        RECT  0 38.832 0.084 38.856 ;
    END
  END tap_d[284]
  PIN tap_d[285]
    DIRECTION OUTPUT ;
    USE SIGNAL ;
    PORT
      LAYER M4 ;
        RECT  0 38.928 0.084 38.952 ;
    END
  END tap_d[285]
  PIN tap_d[286]
    DIRECTION OUTPUT ;
    USE SIGNAL ;
    PORT
      LAYER M4 ;
        RECT  0 39.024 0.084 39.048 ;
    END
  END tap_d[286]
  PIN tap_d[287]
    DIRECTION OUTPUT ;
    USE SIGNAL ;
    PORT
      LAYER M4 ;
        RECT  0 39.12 0.084 39.144 ;
    END
  END tap_d[287]
  PIN tap_d[288]
    DIRECTION OUTPUT ;
    USE SIGNAL ;
    PORT
      LAYER M4 ;
        RECT  0 33.072 0.084 33.096 ;
    END
  END tap_d[288]
  PIN tap_d[289]
    DIRECTION OUTPUT ;
    USE SIGNAL ;
    PORT
      LAYER M4 ;
        RECT  0 33.168 0.084 33.192 ;
    END
  END tap_d[289]
  PIN tap_d[28]
    DIRECTION OUTPUT ;
    USE SIGNAL ;
    PORT
      LAYER M4 ;
        RECT  0 61.104 0.084 61.128 ;
    END
  END tap_d[28]
  PIN tap_d[290]
    DIRECTION OUTPUT ;
    USE SIGNAL ;
    PORT
      LAYER M4 ;
        RECT  0 33.264 0.084 33.288 ;
    END
  END tap_d[290]
  PIN tap_d[291]
    DIRECTION OUTPUT ;
    USE SIGNAL ;
    PORT
      LAYER M4 ;
        RECT  0 33.36 0.084 33.384 ;
    END
  END tap_d[291]
  PIN tap_d[292]
    DIRECTION OUTPUT ;
    USE SIGNAL ;
    PORT
      LAYER M4 ;
        RECT  0 33.456 0.084 33.48 ;
    END
  END tap_d[292]
  PIN tap_d[293]
    DIRECTION OUTPUT ;
    USE SIGNAL ;
    PORT
      LAYER M4 ;
        RECT  0 33.552 0.084 33.576 ;
    END
  END tap_d[293]
  PIN tap_d[294]
    DIRECTION OUTPUT ;
    USE SIGNAL ;
    PORT
      LAYER M4 ;
        RECT  0 33.648 0.084 33.672 ;
    END
  END tap_d[294]
  PIN tap_d[295]
    DIRECTION OUTPUT ;
    USE SIGNAL ;
    PORT
      LAYER M4 ;
        RECT  0 33.744 0.084 33.768 ;
    END
  END tap_d[295]
  PIN tap_d[296]
    DIRECTION OUTPUT ;
    USE SIGNAL ;
    PORT
      LAYER M4 ;
        RECT  0 33.84 0.084 33.864 ;
    END
  END tap_d[296]
  PIN tap_d[297]
    DIRECTION OUTPUT ;
    USE SIGNAL ;
    PORT
      LAYER M4 ;
        RECT  0 33.936 0.084 33.96 ;
    END
  END tap_d[297]
  PIN tap_d[298]
    DIRECTION OUTPUT ;
    USE SIGNAL ;
    PORT
      LAYER M4 ;
        RECT  0 34.032 0.084 34.056 ;
    END
  END tap_d[298]
  PIN tap_d[299]
    DIRECTION OUTPUT ;
    USE SIGNAL ;
    PORT
      LAYER M4 ;
        RECT  0 34.128 0.084 34.152 ;
    END
  END tap_d[299]
  PIN tap_d[29]
    DIRECTION OUTPUT ;
    USE SIGNAL ;
    PORT
      LAYER M4 ;
        RECT  0 61.2 0.084 61.224 ;
    END
  END tap_d[29]
  PIN tap_d[2]
    DIRECTION OUTPUT ;
    USE SIGNAL ;
    PORT
      LAYER M4 ;
        RECT  0 58.608 0.084 58.632 ;
    END
  END tap_d[2]
  PIN tap_d[300]
    DIRECTION OUTPUT ;
    USE SIGNAL ;
    PORT
      LAYER M4 ;
        RECT  0 34.224 0.084 34.248 ;
    END
  END tap_d[300]
  PIN tap_d[301]
    DIRECTION OUTPUT ;
    USE SIGNAL ;
    PORT
      LAYER M4 ;
        RECT  0 34.32 0.084 34.344 ;
    END
  END tap_d[301]
  PIN tap_d[302]
    DIRECTION OUTPUT ;
    USE SIGNAL ;
    PORT
      LAYER M4 ;
        RECT  0 34.416 0.084 34.44 ;
    END
  END tap_d[302]
  PIN tap_d[303]
    DIRECTION OUTPUT ;
    USE SIGNAL ;
    PORT
      LAYER M4 ;
        RECT  0 34.512 0.084 34.536 ;
    END
  END tap_d[303]
  PIN tap_d[304]
    DIRECTION OUTPUT ;
    USE SIGNAL ;
    PORT
      LAYER M4 ;
        RECT  0 34.608 0.084 34.632 ;
    END
  END tap_d[304]
  PIN tap_d[305]
    DIRECTION OUTPUT ;
    USE SIGNAL ;
    PORT
      LAYER M4 ;
        RECT  0 34.704 0.084 34.728 ;
    END
  END tap_d[305]
  PIN tap_d[306]
    DIRECTION OUTPUT ;
    USE SIGNAL ;
    PORT
      LAYER M4 ;
        RECT  0 34.8 0.084 34.824 ;
    END
  END tap_d[306]
  PIN tap_d[307]
    DIRECTION OUTPUT ;
    USE SIGNAL ;
    PORT
      LAYER M4 ;
        RECT  0 34.896 0.084 34.92 ;
    END
  END tap_d[307]
  PIN tap_d[308]
    DIRECTION OUTPUT ;
    USE SIGNAL ;
    PORT
      LAYER M4 ;
        RECT  0 34.992 0.084 35.016 ;
    END
  END tap_d[308]
  PIN tap_d[309]
    DIRECTION OUTPUT ;
    USE SIGNAL ;
    PORT
      LAYER M4 ;
        RECT  0 35.088 0.084 35.112 ;
    END
  END tap_d[309]
  PIN tap_d[30]
    DIRECTION OUTPUT ;
    USE SIGNAL ;
    PORT
      LAYER M4 ;
        RECT  0 61.296 0.084 61.32 ;
    END
  END tap_d[30]
  PIN tap_d[310]
    DIRECTION OUTPUT ;
    USE SIGNAL ;
    PORT
      LAYER M4 ;
        RECT  0 35.184 0.084 35.208 ;
    END
  END tap_d[310]
  PIN tap_d[311]
    DIRECTION OUTPUT ;
    USE SIGNAL ;
    PORT
      LAYER M4 ;
        RECT  0 35.28 0.084 35.304 ;
    END
  END tap_d[311]
  PIN tap_d[312]
    DIRECTION OUTPUT ;
    USE SIGNAL ;
    PORT
      LAYER M4 ;
        RECT  0 35.376 0.084 35.4 ;
    END
  END tap_d[312]
  PIN tap_d[313]
    DIRECTION OUTPUT ;
    USE SIGNAL ;
    PORT
      LAYER M4 ;
        RECT  0 35.472 0.084 35.496 ;
    END
  END tap_d[313]
  PIN tap_d[314]
    DIRECTION OUTPUT ;
    USE SIGNAL ;
    PORT
      LAYER M4 ;
        RECT  0 35.568 0.084 35.592 ;
    END
  END tap_d[314]
  PIN tap_d[315]
    DIRECTION OUTPUT ;
    USE SIGNAL ;
    PORT
      LAYER M4 ;
        RECT  0 35.664 0.084 35.688 ;
    END
  END tap_d[315]
  PIN tap_d[316]
    DIRECTION OUTPUT ;
    USE SIGNAL ;
    PORT
      LAYER M4 ;
        RECT  0 35.76 0.084 35.784 ;
    END
  END tap_d[316]
  PIN tap_d[317]
    DIRECTION OUTPUT ;
    USE SIGNAL ;
    PORT
      LAYER M4 ;
        RECT  0 35.856 0.084 35.88 ;
    END
  END tap_d[317]
  PIN tap_d[318]
    DIRECTION OUTPUT ;
    USE SIGNAL ;
    PORT
      LAYER M4 ;
        RECT  0 35.952 0.084 35.976 ;
    END
  END tap_d[318]
  PIN tap_d[319]
    DIRECTION OUTPUT ;
    USE SIGNAL ;
    PORT
      LAYER M4 ;
        RECT  0 36.048 0.084 36.072 ;
    END
  END tap_d[319]
  PIN tap_d[31]
    DIRECTION OUTPUT ;
    USE SIGNAL ;
    PORT
      LAYER M4 ;
        RECT  0 61.392 0.084 61.416 ;
    END
  END tap_d[31]
  PIN tap_d[320]
    DIRECTION OUTPUT ;
    USE SIGNAL ;
    PORT
      LAYER M4 ;
        RECT  0 30 0.084 30.024 ;
    END
  END tap_d[320]
  PIN tap_d[321]
    DIRECTION OUTPUT ;
    USE SIGNAL ;
    PORT
      LAYER M4 ;
        RECT  0 30.096 0.084 30.12 ;
    END
  END tap_d[321]
  PIN tap_d[322]
    DIRECTION OUTPUT ;
    USE SIGNAL ;
    PORT
      LAYER M4 ;
        RECT  0 30.192 0.084 30.216 ;
    END
  END tap_d[322]
  PIN tap_d[323]
    DIRECTION OUTPUT ;
    USE SIGNAL ;
    PORT
      LAYER M4 ;
        RECT  0 30.288 0.084 30.312 ;
    END
  END tap_d[323]
  PIN tap_d[324]
    DIRECTION OUTPUT ;
    USE SIGNAL ;
    PORT
      LAYER M4 ;
        RECT  0 30.384 0.084 30.408 ;
    END
  END tap_d[324]
  PIN tap_d[325]
    DIRECTION OUTPUT ;
    USE SIGNAL ;
    PORT
      LAYER M4 ;
        RECT  0 30.48 0.084 30.504 ;
    END
  END tap_d[325]
  PIN tap_d[326]
    DIRECTION OUTPUT ;
    USE SIGNAL ;
    PORT
      LAYER M4 ;
        RECT  0 30.576 0.084 30.6 ;
    END
  END tap_d[326]
  PIN tap_d[327]
    DIRECTION OUTPUT ;
    USE SIGNAL ;
    PORT
      LAYER M4 ;
        RECT  0 30.672 0.084 30.696 ;
    END
  END tap_d[327]
  PIN tap_d[328]
    DIRECTION OUTPUT ;
    USE SIGNAL ;
    PORT
      LAYER M4 ;
        RECT  0 30.768 0.084 30.792 ;
    END
  END tap_d[328]
  PIN tap_d[329]
    DIRECTION OUTPUT ;
    USE SIGNAL ;
    PORT
      LAYER M4 ;
        RECT  0 30.864 0.084 30.888 ;
    END
  END tap_d[329]
  PIN tap_d[32]
    DIRECTION OUTPUT ;
    USE SIGNAL ;
    PORT
      LAYER M4 ;
        RECT  0 49.2 0.084 49.224 ;
    END
  END tap_d[32]
  PIN tap_d[330]
    DIRECTION OUTPUT ;
    USE SIGNAL ;
    PORT
      LAYER M4 ;
        RECT  0 30.96 0.084 30.984 ;
    END
  END tap_d[330]
  PIN tap_d[331]
    DIRECTION OUTPUT ;
    USE SIGNAL ;
    PORT
      LAYER M4 ;
        RECT  0 31.056 0.084 31.08 ;
    END
  END tap_d[331]
  PIN tap_d[332]
    DIRECTION OUTPUT ;
    USE SIGNAL ;
    PORT
      LAYER M4 ;
        RECT  0 31.152 0.084 31.176 ;
    END
  END tap_d[332]
  PIN tap_d[333]
    DIRECTION OUTPUT ;
    USE SIGNAL ;
    PORT
      LAYER M4 ;
        RECT  0 31.248 0.084 31.272 ;
    END
  END tap_d[333]
  PIN tap_d[334]
    DIRECTION OUTPUT ;
    USE SIGNAL ;
    PORT
      LAYER M4 ;
        RECT  0 31.344 0.084 31.368 ;
    END
  END tap_d[334]
  PIN tap_d[335]
    DIRECTION OUTPUT ;
    USE SIGNAL ;
    PORT
      LAYER M4 ;
        RECT  0 31.44 0.084 31.464 ;
    END
  END tap_d[335]
  PIN tap_d[336]
    DIRECTION OUTPUT ;
    USE SIGNAL ;
    PORT
      LAYER M4 ;
        RECT  0 31.536 0.084 31.56 ;
    END
  END tap_d[336]
  PIN tap_d[337]
    DIRECTION OUTPUT ;
    USE SIGNAL ;
    PORT
      LAYER M4 ;
        RECT  0 31.632 0.084 31.656 ;
    END
  END tap_d[337]
  PIN tap_d[338]
    DIRECTION OUTPUT ;
    USE SIGNAL ;
    PORT
      LAYER M4 ;
        RECT  0 31.728 0.084 31.752 ;
    END
  END tap_d[338]
  PIN tap_d[339]
    DIRECTION OUTPUT ;
    USE SIGNAL ;
    PORT
      LAYER M4 ;
        RECT  0 31.824 0.084 31.848 ;
    END
  END tap_d[339]
  PIN tap_d[33]
    DIRECTION OUTPUT ;
    USE SIGNAL ;
    PORT
      LAYER M4 ;
        RECT  0 49.296 0.084 49.32 ;
    END
  END tap_d[33]
  PIN tap_d[340]
    DIRECTION OUTPUT ;
    USE SIGNAL ;
    PORT
      LAYER M4 ;
        RECT  0 31.92 0.084 31.944 ;
    END
  END tap_d[340]
  PIN tap_d[341]
    DIRECTION OUTPUT ;
    USE SIGNAL ;
    PORT
      LAYER M4 ;
        RECT  0 32.016 0.084 32.04 ;
    END
  END tap_d[341]
  PIN tap_d[342]
    DIRECTION OUTPUT ;
    USE SIGNAL ;
    PORT
      LAYER M4 ;
        RECT  0 32.112 0.084 32.136 ;
    END
  END tap_d[342]
  PIN tap_d[343]
    DIRECTION OUTPUT ;
    USE SIGNAL ;
    PORT
      LAYER M4 ;
        RECT  0 32.208 0.084 32.232 ;
    END
  END tap_d[343]
  PIN tap_d[344]
    DIRECTION OUTPUT ;
    USE SIGNAL ;
    PORT
      LAYER M4 ;
        RECT  0 32.304 0.084 32.328 ;
    END
  END tap_d[344]
  PIN tap_d[345]
    DIRECTION OUTPUT ;
    USE SIGNAL ;
    PORT
      LAYER M4 ;
        RECT  0 32.4 0.084 32.424 ;
    END
  END tap_d[345]
  PIN tap_d[346]
    DIRECTION OUTPUT ;
    USE SIGNAL ;
    PORT
      LAYER M4 ;
        RECT  0 32.496 0.084 32.52 ;
    END
  END tap_d[346]
  PIN tap_d[347]
    DIRECTION OUTPUT ;
    USE SIGNAL ;
    PORT
      LAYER M4 ;
        RECT  0 32.592 0.084 32.616 ;
    END
  END tap_d[347]
  PIN tap_d[348]
    DIRECTION OUTPUT ;
    USE SIGNAL ;
    PORT
      LAYER M4 ;
        RECT  0 32.688 0.084 32.712 ;
    END
  END tap_d[348]
  PIN tap_d[349]
    DIRECTION OUTPUT ;
    USE SIGNAL ;
    PORT
      LAYER M4 ;
        RECT  0 32.784 0.084 32.808 ;
    END
  END tap_d[349]
  PIN tap_d[34]
    DIRECTION OUTPUT ;
    USE SIGNAL ;
    PORT
      LAYER M4 ;
        RECT  0 49.392 0.084 49.416 ;
    END
  END tap_d[34]
  PIN tap_d[350]
    DIRECTION OUTPUT ;
    USE SIGNAL ;
    PORT
      LAYER M4 ;
        RECT  0 32.88 0.084 32.904 ;
    END
  END tap_d[350]
  PIN tap_d[351]
    DIRECTION OUTPUT ;
    USE SIGNAL ;
    PORT
      LAYER M4 ;
        RECT  0 32.976 0.084 33 ;
    END
  END tap_d[351]
  PIN tap_d[352]
    DIRECTION OUTPUT ;
    USE SIGNAL ;
    PORT
      LAYER M4 ;
        RECT  0 42.288 0.084 42.312 ;
    END
  END tap_d[352]
  PIN tap_d[353]
    DIRECTION OUTPUT ;
    USE SIGNAL ;
    PORT
      LAYER M4 ;
        RECT  0 42.384 0.084 42.408 ;
    END
  END tap_d[353]
  PIN tap_d[354]
    DIRECTION OUTPUT ;
    USE SIGNAL ;
    PORT
      LAYER M4 ;
        RECT  0 42.48 0.084 42.504 ;
    END
  END tap_d[354]
  PIN tap_d[355]
    DIRECTION OUTPUT ;
    USE SIGNAL ;
    PORT
      LAYER M4 ;
        RECT  0 42.576 0.084 42.6 ;
    END
  END tap_d[355]
  PIN tap_d[356]
    DIRECTION OUTPUT ;
    USE SIGNAL ;
    PORT
      LAYER M4 ;
        RECT  0 42.672 0.084 42.696 ;
    END
  END tap_d[356]
  PIN tap_d[357]
    DIRECTION OUTPUT ;
    USE SIGNAL ;
    PORT
      LAYER M4 ;
        RECT  0 42.768 0.084 42.792 ;
    END
  END tap_d[357]
  PIN tap_d[358]
    DIRECTION OUTPUT ;
    USE SIGNAL ;
    PORT
      LAYER M4 ;
        RECT  0 42.864 0.084 42.888 ;
    END
  END tap_d[358]
  PIN tap_d[359]
    DIRECTION OUTPUT ;
    USE SIGNAL ;
    PORT
      LAYER M4 ;
        RECT  0 42.96 0.084 42.984 ;
    END
  END tap_d[359]
  PIN tap_d[35]
    DIRECTION OUTPUT ;
    USE SIGNAL ;
    PORT
      LAYER M4 ;
        RECT  0 49.488 0.084 49.512 ;
    END
  END tap_d[35]
  PIN tap_d[360]
    DIRECTION OUTPUT ;
    USE SIGNAL ;
    PORT
      LAYER M4 ;
        RECT  0 43.056 0.084 43.08 ;
    END
  END tap_d[360]
  PIN tap_d[361]
    DIRECTION OUTPUT ;
    USE SIGNAL ;
    PORT
      LAYER M4 ;
        RECT  0 43.152 0.084 43.176 ;
    END
  END tap_d[361]
  PIN tap_d[362]
    DIRECTION OUTPUT ;
    USE SIGNAL ;
    PORT
      LAYER M4 ;
        RECT  0 43.248 0.084 43.272 ;
    END
  END tap_d[362]
  PIN tap_d[363]
    DIRECTION OUTPUT ;
    USE SIGNAL ;
    PORT
      LAYER M4 ;
        RECT  0 43.344 0.084 43.368 ;
    END
  END tap_d[363]
  PIN tap_d[364]
    DIRECTION OUTPUT ;
    USE SIGNAL ;
    PORT
      LAYER M4 ;
        RECT  0 43.44 0.084 43.464 ;
    END
  END tap_d[364]
  PIN tap_d[365]
    DIRECTION OUTPUT ;
    USE SIGNAL ;
    PORT
      LAYER M4 ;
        RECT  0 43.536 0.084 43.56 ;
    END
  END tap_d[365]
  PIN tap_d[366]
    DIRECTION OUTPUT ;
    USE SIGNAL ;
    PORT
      LAYER M4 ;
        RECT  0 43.632 0.084 43.656 ;
    END
  END tap_d[366]
  PIN tap_d[367]
    DIRECTION OUTPUT ;
    USE SIGNAL ;
    PORT
      LAYER M4 ;
        RECT  0 43.728 0.084 43.752 ;
    END
  END tap_d[367]
  PIN tap_d[368]
    DIRECTION OUTPUT ;
    USE SIGNAL ;
    PORT
      LAYER M4 ;
        RECT  0 43.824 0.084 43.848 ;
    END
  END tap_d[368]
  PIN tap_d[369]
    DIRECTION OUTPUT ;
    USE SIGNAL ;
    PORT
      LAYER M4 ;
        RECT  0 43.92 0.084 43.944 ;
    END
  END tap_d[369]
  PIN tap_d[36]
    DIRECTION OUTPUT ;
    USE SIGNAL ;
    PORT
      LAYER M4 ;
        RECT  0 49.584 0.084 49.608 ;
    END
  END tap_d[36]
  PIN tap_d[370]
    DIRECTION OUTPUT ;
    USE SIGNAL ;
    PORT
      LAYER M4 ;
        RECT  0 44.016 0.084 44.04 ;
    END
  END tap_d[370]
  PIN tap_d[371]
    DIRECTION OUTPUT ;
    USE SIGNAL ;
    PORT
      LAYER M4 ;
        RECT  0 44.112 0.084 44.136 ;
    END
  END tap_d[371]
  PIN tap_d[372]
    DIRECTION OUTPUT ;
    USE SIGNAL ;
    PORT
      LAYER M4 ;
        RECT  0 44.208 0.084 44.232 ;
    END
  END tap_d[372]
  PIN tap_d[373]
    DIRECTION OUTPUT ;
    USE SIGNAL ;
    PORT
      LAYER M4 ;
        RECT  0 44.304 0.084 44.328 ;
    END
  END tap_d[373]
  PIN tap_d[374]
    DIRECTION OUTPUT ;
    USE SIGNAL ;
    PORT
      LAYER M4 ;
        RECT  0 44.4 0.084 44.424 ;
    END
  END tap_d[374]
  PIN tap_d[375]
    DIRECTION OUTPUT ;
    USE SIGNAL ;
    PORT
      LAYER M4 ;
        RECT  0 44.496 0.084 44.52 ;
    END
  END tap_d[375]
  PIN tap_d[376]
    DIRECTION OUTPUT ;
    USE SIGNAL ;
    PORT
      LAYER M4 ;
        RECT  0 44.592 0.084 44.616 ;
    END
  END tap_d[376]
  PIN tap_d[377]
    DIRECTION OUTPUT ;
    USE SIGNAL ;
    PORT
      LAYER M4 ;
        RECT  0 44.688 0.084 44.712 ;
    END
  END tap_d[377]
  PIN tap_d[378]
    DIRECTION OUTPUT ;
    USE SIGNAL ;
    PORT
      LAYER M4 ;
        RECT  0 44.784 0.084 44.808 ;
    END
  END tap_d[378]
  PIN tap_d[379]
    DIRECTION OUTPUT ;
    USE SIGNAL ;
    PORT
      LAYER M4 ;
        RECT  0 44.88 0.084 44.904 ;
    END
  END tap_d[379]
  PIN tap_d[37]
    DIRECTION OUTPUT ;
    USE SIGNAL ;
    PORT
      LAYER M4 ;
        RECT  0 49.68 0.084 49.704 ;
    END
  END tap_d[37]
  PIN tap_d[380]
    DIRECTION OUTPUT ;
    USE SIGNAL ;
    PORT
      LAYER M4 ;
        RECT  0 44.976 0.084 45 ;
    END
  END tap_d[380]
  PIN tap_d[381]
    DIRECTION OUTPUT ;
    USE SIGNAL ;
    PORT
      LAYER M4 ;
        RECT  0 45.072 0.084 45.096 ;
    END
  END tap_d[381]
  PIN tap_d[382]
    DIRECTION OUTPUT ;
    USE SIGNAL ;
    PORT
      LAYER M4 ;
        RECT  0 45.168 0.084 45.192 ;
    END
  END tap_d[382]
  PIN tap_d[383]
    DIRECTION OUTPUT ;
    USE SIGNAL ;
    PORT
      LAYER M4 ;
        RECT  0 45.264 0.084 45.288 ;
    END
  END tap_d[383]
  PIN tap_d[384]
    DIRECTION OUTPUT ;
    USE SIGNAL ;
    PORT
      LAYER M4 ;
        RECT  0 71.472 0.084 71.496 ;
    END
  END tap_d[384]
  PIN tap_d[385]
    DIRECTION OUTPUT ;
    USE SIGNAL ;
    PORT
      LAYER M4 ;
        RECT  0 71.568 0.084 71.592 ;
    END
  END tap_d[385]
  PIN tap_d[386]
    DIRECTION OUTPUT ;
    USE SIGNAL ;
    PORT
      LAYER M4 ;
        RECT  0 71.664 0.084 71.688 ;
    END
  END tap_d[386]
  PIN tap_d[387]
    DIRECTION OUTPUT ;
    USE SIGNAL ;
    PORT
      LAYER M4 ;
        RECT  0 71.76 0.084 71.784 ;
    END
  END tap_d[387]
  PIN tap_d[388]
    DIRECTION OUTPUT ;
    USE SIGNAL ;
    PORT
      LAYER M4 ;
        RECT  0 71.856 0.084 71.88 ;
    END
  END tap_d[388]
  PIN tap_d[389]
    DIRECTION OUTPUT ;
    USE SIGNAL ;
    PORT
      LAYER M4 ;
        RECT  0 71.952 0.084 71.976 ;
    END
  END tap_d[389]
  PIN tap_d[38]
    DIRECTION OUTPUT ;
    USE SIGNAL ;
    PORT
      LAYER M4 ;
        RECT  0 49.776 0.084 49.8 ;
    END
  END tap_d[38]
  PIN tap_d[390]
    DIRECTION OUTPUT ;
    USE SIGNAL ;
    PORT
      LAYER M4 ;
        RECT  0 72.048 0.084 72.072 ;
    END
  END tap_d[390]
  PIN tap_d[391]
    DIRECTION OUTPUT ;
    USE SIGNAL ;
    PORT
      LAYER M4 ;
        RECT  0 72.144 0.084 72.168 ;
    END
  END tap_d[391]
  PIN tap_d[392]
    DIRECTION OUTPUT ;
    USE SIGNAL ;
    PORT
      LAYER M4 ;
        RECT  0 72.24 0.084 72.264 ;
    END
  END tap_d[392]
  PIN tap_d[393]
    DIRECTION OUTPUT ;
    USE SIGNAL ;
    PORT
      LAYER M4 ;
        RECT  0 72.336 0.084 72.36 ;
    END
  END tap_d[393]
  PIN tap_d[394]
    DIRECTION OUTPUT ;
    USE SIGNAL ;
    PORT
      LAYER M4 ;
        RECT  0 72.432 0.084 72.456 ;
    END
  END tap_d[394]
  PIN tap_d[395]
    DIRECTION OUTPUT ;
    USE SIGNAL ;
    PORT
      LAYER M4 ;
        RECT  0 72.528 0.084 72.552 ;
    END
  END tap_d[395]
  PIN tap_d[396]
    DIRECTION OUTPUT ;
    USE SIGNAL ;
    PORT
      LAYER M4 ;
        RECT  0 72.624 0.084 72.648 ;
    END
  END tap_d[396]
  PIN tap_d[397]
    DIRECTION OUTPUT ;
    USE SIGNAL ;
    PORT
      LAYER M4 ;
        RECT  0 72.72 0.084 72.744 ;
    END
  END tap_d[397]
  PIN tap_d[398]
    DIRECTION OUTPUT ;
    USE SIGNAL ;
    PORT
      LAYER M4 ;
        RECT  0 72.816 0.084 72.84 ;
    END
  END tap_d[398]
  PIN tap_d[399]
    DIRECTION OUTPUT ;
    USE SIGNAL ;
    PORT
      LAYER M4 ;
        RECT  0 72.912 0.084 72.936 ;
    END
  END tap_d[399]
  PIN tap_d[39]
    DIRECTION OUTPUT ;
    USE SIGNAL ;
    PORT
      LAYER M4 ;
        RECT  0 49.872 0.084 49.896 ;
    END
  END tap_d[39]
  PIN tap_d[3]
    DIRECTION OUTPUT ;
    USE SIGNAL ;
    PORT
      LAYER M4 ;
        RECT  0 58.704 0.084 58.728 ;
    END
  END tap_d[3]
  PIN tap_d[400]
    DIRECTION OUTPUT ;
    USE SIGNAL ;
    PORT
      LAYER M4 ;
        RECT  0 73.008 0.084 73.032 ;
    END
  END tap_d[400]
  PIN tap_d[401]
    DIRECTION OUTPUT ;
    USE SIGNAL ;
    PORT
      LAYER M4 ;
        RECT  0 73.104 0.084 73.128 ;
    END
  END tap_d[401]
  PIN tap_d[402]
    DIRECTION OUTPUT ;
    USE SIGNAL ;
    PORT
      LAYER M4 ;
        RECT  0 73.2 0.084 73.224 ;
    END
  END tap_d[402]
  PIN tap_d[403]
    DIRECTION OUTPUT ;
    USE SIGNAL ;
    PORT
      LAYER M4 ;
        RECT  0 73.296 0.084 73.32 ;
    END
  END tap_d[403]
  PIN tap_d[404]
    DIRECTION OUTPUT ;
    USE SIGNAL ;
    PORT
      LAYER M4 ;
        RECT  0 73.392 0.084 73.416 ;
    END
  END tap_d[404]
  PIN tap_d[405]
    DIRECTION OUTPUT ;
    USE SIGNAL ;
    PORT
      LAYER M4 ;
        RECT  0 73.488 0.084 73.512 ;
    END
  END tap_d[405]
  PIN tap_d[406]
    DIRECTION OUTPUT ;
    USE SIGNAL ;
    PORT
      LAYER M4 ;
        RECT  0 73.584 0.084 73.608 ;
    END
  END tap_d[406]
  PIN tap_d[407]
    DIRECTION OUTPUT ;
    USE SIGNAL ;
    PORT
      LAYER M4 ;
        RECT  0 73.68 0.084 73.704 ;
    END
  END tap_d[407]
  PIN tap_d[408]
    DIRECTION OUTPUT ;
    USE SIGNAL ;
    PORT
      LAYER M4 ;
        RECT  0 73.776 0.084 73.8 ;
    END
  END tap_d[408]
  PIN tap_d[409]
    DIRECTION OUTPUT ;
    USE SIGNAL ;
    PORT
      LAYER M4 ;
        RECT  0 73.872 0.084 73.896 ;
    END
  END tap_d[409]
  PIN tap_d[40]
    DIRECTION OUTPUT ;
    USE SIGNAL ;
    PORT
      LAYER M4 ;
        RECT  0 49.968 0.084 49.992 ;
    END
  END tap_d[40]
  PIN tap_d[410]
    DIRECTION OUTPUT ;
    USE SIGNAL ;
    PORT
      LAYER M4 ;
        RECT  0 73.968 0.084 73.992 ;
    END
  END tap_d[410]
  PIN tap_d[411]
    DIRECTION OUTPUT ;
    USE SIGNAL ;
    PORT
      LAYER M4 ;
        RECT  0 74.064 0.084 74.088 ;
    END
  END tap_d[411]
  PIN tap_d[412]
    DIRECTION OUTPUT ;
    USE SIGNAL ;
    PORT
      LAYER M4 ;
        RECT  0 74.16 0.084 74.184 ;
    END
  END tap_d[412]
  PIN tap_d[413]
    DIRECTION OUTPUT ;
    USE SIGNAL ;
    PORT
      LAYER M4 ;
        RECT  0 74.256 0.084 74.28 ;
    END
  END tap_d[413]
  PIN tap_d[414]
    DIRECTION OUTPUT ;
    USE SIGNAL ;
    PORT
      LAYER M4 ;
        RECT  0 74.352 0.084 74.376 ;
    END
  END tap_d[414]
  PIN tap_d[415]
    DIRECTION OUTPUT ;
    USE SIGNAL ;
    PORT
      LAYER M4 ;
        RECT  0 74.448 0.084 74.472 ;
    END
  END tap_d[415]
  PIN tap_d[416]
    DIRECTION OUTPUT ;
    USE SIGNAL ;
    PORT
      LAYER M4 ;
        RECT  0 68.4 0.084 68.424 ;
    END
  END tap_d[416]
  PIN tap_d[417]
    DIRECTION OUTPUT ;
    USE SIGNAL ;
    PORT
      LAYER M4 ;
        RECT  0 68.496 0.084 68.52 ;
    END
  END tap_d[417]
  PIN tap_d[418]
    DIRECTION OUTPUT ;
    USE SIGNAL ;
    PORT
      LAYER M4 ;
        RECT  0 68.592 0.084 68.616 ;
    END
  END tap_d[418]
  PIN tap_d[419]
    DIRECTION OUTPUT ;
    USE SIGNAL ;
    PORT
      LAYER M4 ;
        RECT  0 68.688 0.084 68.712 ;
    END
  END tap_d[419]
  PIN tap_d[41]
    DIRECTION OUTPUT ;
    USE SIGNAL ;
    PORT
      LAYER M4 ;
        RECT  0 50.064 0.084 50.088 ;
    END
  END tap_d[41]
  PIN tap_d[420]
    DIRECTION OUTPUT ;
    USE SIGNAL ;
    PORT
      LAYER M4 ;
        RECT  0 68.784 0.084 68.808 ;
    END
  END tap_d[420]
  PIN tap_d[421]
    DIRECTION OUTPUT ;
    USE SIGNAL ;
    PORT
      LAYER M4 ;
        RECT  0 68.88 0.084 68.904 ;
    END
  END tap_d[421]
  PIN tap_d[422]
    DIRECTION OUTPUT ;
    USE SIGNAL ;
    PORT
      LAYER M4 ;
        RECT  0 68.976 0.084 69 ;
    END
  END tap_d[422]
  PIN tap_d[423]
    DIRECTION OUTPUT ;
    USE SIGNAL ;
    PORT
      LAYER M4 ;
        RECT  0 69.072 0.084 69.096 ;
    END
  END tap_d[423]
  PIN tap_d[424]
    DIRECTION OUTPUT ;
    USE SIGNAL ;
    PORT
      LAYER M4 ;
        RECT  0 69.168 0.084 69.192 ;
    END
  END tap_d[424]
  PIN tap_d[425]
    DIRECTION OUTPUT ;
    USE SIGNAL ;
    PORT
      LAYER M4 ;
        RECT  0 69.264 0.084 69.288 ;
    END
  END tap_d[425]
  PIN tap_d[426]
    DIRECTION OUTPUT ;
    USE SIGNAL ;
    PORT
      LAYER M4 ;
        RECT  0 69.36 0.084 69.384 ;
    END
  END tap_d[426]
  PIN tap_d[427]
    DIRECTION OUTPUT ;
    USE SIGNAL ;
    PORT
      LAYER M4 ;
        RECT  0 69.456 0.084 69.48 ;
    END
  END tap_d[427]
  PIN tap_d[428]
    DIRECTION OUTPUT ;
    USE SIGNAL ;
    PORT
      LAYER M4 ;
        RECT  0 69.552 0.084 69.576 ;
    END
  END tap_d[428]
  PIN tap_d[429]
    DIRECTION OUTPUT ;
    USE SIGNAL ;
    PORT
      LAYER M4 ;
        RECT  0 69.648 0.084 69.672 ;
    END
  END tap_d[429]
  PIN tap_d[42]
    DIRECTION OUTPUT ;
    USE SIGNAL ;
    PORT
      LAYER M4 ;
        RECT  0 50.16 0.084 50.184 ;
    END
  END tap_d[42]
  PIN tap_d[430]
    DIRECTION OUTPUT ;
    USE SIGNAL ;
    PORT
      LAYER M4 ;
        RECT  0 69.744 0.084 69.768 ;
    END
  END tap_d[430]
  PIN tap_d[431]
    DIRECTION OUTPUT ;
    USE SIGNAL ;
    PORT
      LAYER M4 ;
        RECT  0 69.84 0.084 69.864 ;
    END
  END tap_d[431]
  PIN tap_d[432]
    DIRECTION OUTPUT ;
    USE SIGNAL ;
    PORT
      LAYER M4 ;
        RECT  0 69.936 0.084 69.96 ;
    END
  END tap_d[432]
  PIN tap_d[433]
    DIRECTION OUTPUT ;
    USE SIGNAL ;
    PORT
      LAYER M4 ;
        RECT  0 70.032 0.084 70.056 ;
    END
  END tap_d[433]
  PIN tap_d[434]
    DIRECTION OUTPUT ;
    USE SIGNAL ;
    PORT
      LAYER M4 ;
        RECT  0 70.128 0.084 70.152 ;
    END
  END tap_d[434]
  PIN tap_d[435]
    DIRECTION OUTPUT ;
    USE SIGNAL ;
    PORT
      LAYER M4 ;
        RECT  0 70.224 0.084 70.248 ;
    END
  END tap_d[435]
  PIN tap_d[436]
    DIRECTION OUTPUT ;
    USE SIGNAL ;
    PORT
      LAYER M4 ;
        RECT  0 70.32 0.084 70.344 ;
    END
  END tap_d[436]
  PIN tap_d[437]
    DIRECTION OUTPUT ;
    USE SIGNAL ;
    PORT
      LAYER M4 ;
        RECT  0 70.416 0.084 70.44 ;
    END
  END tap_d[437]
  PIN tap_d[438]
    DIRECTION OUTPUT ;
    USE SIGNAL ;
    PORT
      LAYER M4 ;
        RECT  0 70.512 0.084 70.536 ;
    END
  END tap_d[438]
  PIN tap_d[439]
    DIRECTION OUTPUT ;
    USE SIGNAL ;
    PORT
      LAYER M4 ;
        RECT  0 70.608 0.084 70.632 ;
    END
  END tap_d[439]
  PIN tap_d[43]
    DIRECTION OUTPUT ;
    USE SIGNAL ;
    PORT
      LAYER M4 ;
        RECT  0 50.256 0.084 50.28 ;
    END
  END tap_d[43]
  PIN tap_d[440]
    DIRECTION OUTPUT ;
    USE SIGNAL ;
    PORT
      LAYER M4 ;
        RECT  0 70.704 0.084 70.728 ;
    END
  END tap_d[440]
  PIN tap_d[441]
    DIRECTION OUTPUT ;
    USE SIGNAL ;
    PORT
      LAYER M4 ;
        RECT  0 70.8 0.084 70.824 ;
    END
  END tap_d[441]
  PIN tap_d[442]
    DIRECTION OUTPUT ;
    USE SIGNAL ;
    PORT
      LAYER M4 ;
        RECT  0 70.896 0.084 70.92 ;
    END
  END tap_d[442]
  PIN tap_d[443]
    DIRECTION OUTPUT ;
    USE SIGNAL ;
    PORT
      LAYER M4 ;
        RECT  0 70.992 0.084 71.016 ;
    END
  END tap_d[443]
  PIN tap_d[444]
    DIRECTION OUTPUT ;
    USE SIGNAL ;
    PORT
      LAYER M4 ;
        RECT  0 71.088 0.084 71.112 ;
    END
  END tap_d[444]
  PIN tap_d[445]
    DIRECTION OUTPUT ;
    USE SIGNAL ;
    PORT
      LAYER M4 ;
        RECT  0 71.184 0.084 71.208 ;
    END
  END tap_d[445]
  PIN tap_d[446]
    DIRECTION OUTPUT ;
    USE SIGNAL ;
    PORT
      LAYER M4 ;
        RECT  0 71.28 0.084 71.304 ;
    END
  END tap_d[446]
  PIN tap_d[447]
    DIRECTION OUTPUT ;
    USE SIGNAL ;
    PORT
      LAYER M4 ;
        RECT  0 71.376 0.084 71.4 ;
    END
  END tap_d[447]
  PIN tap_d[448]
    DIRECTION OUTPUT ;
    USE SIGNAL ;
    PORT
      LAYER M4 ;
        RECT  0 65.328 0.084 65.352 ;
    END
  END tap_d[448]
  PIN tap_d[449]
    DIRECTION OUTPUT ;
    USE SIGNAL ;
    PORT
      LAYER M4 ;
        RECT  0 65.424 0.084 65.448 ;
    END
  END tap_d[449]
  PIN tap_d[44]
    DIRECTION OUTPUT ;
    USE SIGNAL ;
    PORT
      LAYER M4 ;
        RECT  0 50.352 0.084 50.376 ;
    END
  END tap_d[44]
  PIN tap_d[450]
    DIRECTION OUTPUT ;
    USE SIGNAL ;
    PORT
      LAYER M4 ;
        RECT  0 65.52 0.084 65.544 ;
    END
  END tap_d[450]
  PIN tap_d[451]
    DIRECTION OUTPUT ;
    USE SIGNAL ;
    PORT
      LAYER M4 ;
        RECT  0 65.616 0.084 65.64 ;
    END
  END tap_d[451]
  PIN tap_d[452]
    DIRECTION OUTPUT ;
    USE SIGNAL ;
    PORT
      LAYER M4 ;
        RECT  0 65.712 0.084 65.736 ;
    END
  END tap_d[452]
  PIN tap_d[453]
    DIRECTION OUTPUT ;
    USE SIGNAL ;
    PORT
      LAYER M4 ;
        RECT  0 65.808 0.084 65.832 ;
    END
  END tap_d[453]
  PIN tap_d[454]
    DIRECTION OUTPUT ;
    USE SIGNAL ;
    PORT
      LAYER M4 ;
        RECT  0 65.904 0.084 65.928 ;
    END
  END tap_d[454]
  PIN tap_d[455]
    DIRECTION OUTPUT ;
    USE SIGNAL ;
    PORT
      LAYER M4 ;
        RECT  0 66 0.084 66.024 ;
    END
  END tap_d[455]
  PIN tap_d[456]
    DIRECTION OUTPUT ;
    USE SIGNAL ;
    PORT
      LAYER M4 ;
        RECT  0 66.096 0.084 66.12 ;
    END
  END tap_d[456]
  PIN tap_d[457]
    DIRECTION OUTPUT ;
    USE SIGNAL ;
    PORT
      LAYER M4 ;
        RECT  0 66.192 0.084 66.216 ;
    END
  END tap_d[457]
  PIN tap_d[458]
    DIRECTION OUTPUT ;
    USE SIGNAL ;
    PORT
      LAYER M4 ;
        RECT  0 66.288 0.084 66.312 ;
    END
  END tap_d[458]
  PIN tap_d[459]
    DIRECTION OUTPUT ;
    USE SIGNAL ;
    PORT
      LAYER M4 ;
        RECT  0 66.384 0.084 66.408 ;
    END
  END tap_d[459]
  PIN tap_d[45]
    DIRECTION OUTPUT ;
    USE SIGNAL ;
    PORT
      LAYER M4 ;
        RECT  0 50.448 0.084 50.472 ;
    END
  END tap_d[45]
  PIN tap_d[460]
    DIRECTION OUTPUT ;
    USE SIGNAL ;
    PORT
      LAYER M4 ;
        RECT  0 66.48 0.084 66.504 ;
    END
  END tap_d[460]
  PIN tap_d[461]
    DIRECTION OUTPUT ;
    USE SIGNAL ;
    PORT
      LAYER M4 ;
        RECT  0 66.576 0.084 66.6 ;
    END
  END tap_d[461]
  PIN tap_d[462]
    DIRECTION OUTPUT ;
    USE SIGNAL ;
    PORT
      LAYER M4 ;
        RECT  0 66.672 0.084 66.696 ;
    END
  END tap_d[462]
  PIN tap_d[463]
    DIRECTION OUTPUT ;
    USE SIGNAL ;
    PORT
      LAYER M4 ;
        RECT  0 66.768 0.084 66.792 ;
    END
  END tap_d[463]
  PIN tap_d[464]
    DIRECTION OUTPUT ;
    USE SIGNAL ;
    PORT
      LAYER M4 ;
        RECT  0 66.864 0.084 66.888 ;
    END
  END tap_d[464]
  PIN tap_d[465]
    DIRECTION OUTPUT ;
    USE SIGNAL ;
    PORT
      LAYER M4 ;
        RECT  0 66.96 0.084 66.984 ;
    END
  END tap_d[465]
  PIN tap_d[466]
    DIRECTION OUTPUT ;
    USE SIGNAL ;
    PORT
      LAYER M4 ;
        RECT  0 67.056 0.084 67.08 ;
    END
  END tap_d[466]
  PIN tap_d[467]
    DIRECTION OUTPUT ;
    USE SIGNAL ;
    PORT
      LAYER M4 ;
        RECT  0 67.152 0.084 67.176 ;
    END
  END tap_d[467]
  PIN tap_d[468]
    DIRECTION OUTPUT ;
    USE SIGNAL ;
    PORT
      LAYER M4 ;
        RECT  0 67.248 0.084 67.272 ;
    END
  END tap_d[468]
  PIN tap_d[469]
    DIRECTION OUTPUT ;
    USE SIGNAL ;
    PORT
      LAYER M4 ;
        RECT  0 67.344 0.084 67.368 ;
    END
  END tap_d[469]
  PIN tap_d[46]
    DIRECTION OUTPUT ;
    USE SIGNAL ;
    PORT
      LAYER M4 ;
        RECT  0 50.544 0.084 50.568 ;
    END
  END tap_d[46]
  PIN tap_d[470]
    DIRECTION OUTPUT ;
    USE SIGNAL ;
    PORT
      LAYER M4 ;
        RECT  0 67.44 0.084 67.464 ;
    END
  END tap_d[470]
  PIN tap_d[471]
    DIRECTION OUTPUT ;
    USE SIGNAL ;
    PORT
      LAYER M4 ;
        RECT  0 67.536 0.084 67.56 ;
    END
  END tap_d[471]
  PIN tap_d[472]
    DIRECTION OUTPUT ;
    USE SIGNAL ;
    PORT
      LAYER M4 ;
        RECT  0 67.632 0.084 67.656 ;
    END
  END tap_d[472]
  PIN tap_d[473]
    DIRECTION OUTPUT ;
    USE SIGNAL ;
    PORT
      LAYER M4 ;
        RECT  0 67.728 0.084 67.752 ;
    END
  END tap_d[473]
  PIN tap_d[474]
    DIRECTION OUTPUT ;
    USE SIGNAL ;
    PORT
      LAYER M4 ;
        RECT  0 67.824 0.084 67.848 ;
    END
  END tap_d[474]
  PIN tap_d[475]
    DIRECTION OUTPUT ;
    USE SIGNAL ;
    PORT
      LAYER M4 ;
        RECT  0 67.92 0.084 67.944 ;
    END
  END tap_d[475]
  PIN tap_d[476]
    DIRECTION OUTPUT ;
    USE SIGNAL ;
    PORT
      LAYER M4 ;
        RECT  0 68.016 0.084 68.04 ;
    END
  END tap_d[476]
  PIN tap_d[477]
    DIRECTION OUTPUT ;
    USE SIGNAL ;
    PORT
      LAYER M4 ;
        RECT  0 68.112 0.084 68.136 ;
    END
  END tap_d[477]
  PIN tap_d[478]
    DIRECTION OUTPUT ;
    USE SIGNAL ;
    PORT
      LAYER M4 ;
        RECT  0 68.208 0.084 68.232 ;
    END
  END tap_d[478]
  PIN tap_d[479]
    DIRECTION OUTPUT ;
    USE SIGNAL ;
    PORT
      LAYER M4 ;
        RECT  0 68.304 0.084 68.328 ;
    END
  END tap_d[479]
  PIN tap_d[47]
    DIRECTION OUTPUT ;
    USE SIGNAL ;
    PORT
      LAYER M4 ;
        RECT  0 50.64 0.084 50.664 ;
    END
  END tap_d[47]
  PIN tap_d[480]
    DIRECTION OUTPUT ;
    USE SIGNAL ;
    PORT
      LAYER M4 ;
        RECT  0 74.832 0.084 74.856 ;
    END
  END tap_d[480]
  PIN tap_d[481]
    DIRECTION OUTPUT ;
    USE SIGNAL ;
    PORT
      LAYER M4 ;
        RECT  0 74.928 0.084 74.952 ;
    END
  END tap_d[481]
  PIN tap_d[482]
    DIRECTION OUTPUT ;
    USE SIGNAL ;
    PORT
      LAYER M4 ;
        RECT  0 75.024 0.084 75.048 ;
    END
  END tap_d[482]
  PIN tap_d[483]
    DIRECTION OUTPUT ;
    USE SIGNAL ;
    PORT
      LAYER M4 ;
        RECT  0 75.12 0.084 75.144 ;
    END
  END tap_d[483]
  PIN tap_d[484]
    DIRECTION OUTPUT ;
    USE SIGNAL ;
    PORT
      LAYER M4 ;
        RECT  0 75.216 0.084 75.24 ;
    END
  END tap_d[484]
  PIN tap_d[485]
    DIRECTION OUTPUT ;
    USE SIGNAL ;
    PORT
      LAYER M4 ;
        RECT  0 75.312 0.084 75.336 ;
    END
  END tap_d[485]
  PIN tap_d[486]
    DIRECTION OUTPUT ;
    USE SIGNAL ;
    PORT
      LAYER M4 ;
        RECT  0 75.408 0.084 75.432 ;
    END
  END tap_d[486]
  PIN tap_d[487]
    DIRECTION OUTPUT ;
    USE SIGNAL ;
    PORT
      LAYER M4 ;
        RECT  0 75.504 0.084 75.528 ;
    END
  END tap_d[487]
  PIN tap_d[488]
    DIRECTION OUTPUT ;
    USE SIGNAL ;
    PORT
      LAYER M4 ;
        RECT  0 75.6 0.084 75.624 ;
    END
  END tap_d[488]
  PIN tap_d[489]
    DIRECTION OUTPUT ;
    USE SIGNAL ;
    PORT
      LAYER M4 ;
        RECT  0 75.696 0.084 75.72 ;
    END
  END tap_d[489]
  PIN tap_d[48]
    DIRECTION OUTPUT ;
    USE SIGNAL ;
    PORT
      LAYER M4 ;
        RECT  0 50.736 0.084 50.76 ;
    END
  END tap_d[48]
  PIN tap_d[490]
    DIRECTION OUTPUT ;
    USE SIGNAL ;
    PORT
      LAYER M4 ;
        RECT  0 75.792 0.084 75.816 ;
    END
  END tap_d[490]
  PIN tap_d[491]
    DIRECTION OUTPUT ;
    USE SIGNAL ;
    PORT
      LAYER M4 ;
        RECT  0 75.888 0.084 75.912 ;
    END
  END tap_d[491]
  PIN tap_d[492]
    DIRECTION OUTPUT ;
    USE SIGNAL ;
    PORT
      LAYER M4 ;
        RECT  0 75.984 0.084 76.008 ;
    END
  END tap_d[492]
  PIN tap_d[493]
    DIRECTION OUTPUT ;
    USE SIGNAL ;
    PORT
      LAYER M4 ;
        RECT  0 76.08 0.084 76.104 ;
    END
  END tap_d[493]
  PIN tap_d[494]
    DIRECTION OUTPUT ;
    USE SIGNAL ;
    PORT
      LAYER M4 ;
        RECT  0 76.176 0.084 76.2 ;
    END
  END tap_d[494]
  PIN tap_d[495]
    DIRECTION OUTPUT ;
    USE SIGNAL ;
    PORT
      LAYER M4 ;
        RECT  0 76.272 0.084 76.296 ;
    END
  END tap_d[495]
  PIN tap_d[496]
    DIRECTION OUTPUT ;
    USE SIGNAL ;
    PORT
      LAYER M4 ;
        RECT  0 76.368 0.084 76.392 ;
    END
  END tap_d[496]
  PIN tap_d[497]
    DIRECTION OUTPUT ;
    USE SIGNAL ;
    PORT
      LAYER M4 ;
        RECT  0 76.464 0.084 76.488 ;
    END
  END tap_d[497]
  PIN tap_d[498]
    DIRECTION OUTPUT ;
    USE SIGNAL ;
    PORT
      LAYER M4 ;
        RECT  0 76.56 0.084 76.584 ;
    END
  END tap_d[498]
  PIN tap_d[499]
    DIRECTION OUTPUT ;
    USE SIGNAL ;
    PORT
      LAYER M4 ;
        RECT  0 76.656 0.084 76.68 ;
    END
  END tap_d[499]
  PIN tap_d[49]
    DIRECTION OUTPUT ;
    USE SIGNAL ;
    PORT
      LAYER M4 ;
        RECT  0 50.832 0.084 50.856 ;
    END
  END tap_d[49]
  PIN tap_d[4]
    DIRECTION OUTPUT ;
    USE SIGNAL ;
    PORT
      LAYER M4 ;
        RECT  0 58.8 0.084 58.824 ;
    END
  END tap_d[4]
  PIN tap_d[500]
    DIRECTION OUTPUT ;
    USE SIGNAL ;
    PORT
      LAYER M4 ;
        RECT  0 76.752 0.084 76.776 ;
    END
  END tap_d[500]
  PIN tap_d[501]
    DIRECTION OUTPUT ;
    USE SIGNAL ;
    PORT
      LAYER M4 ;
        RECT  0 76.848 0.084 76.872 ;
    END
  END tap_d[501]
  PIN tap_d[502]
    DIRECTION OUTPUT ;
    USE SIGNAL ;
    PORT
      LAYER M4 ;
        RECT  0 76.944 0.084 76.968 ;
    END
  END tap_d[502]
  PIN tap_d[503]
    DIRECTION OUTPUT ;
    USE SIGNAL ;
    PORT
      LAYER M4 ;
        RECT  0 77.04 0.084 77.064 ;
    END
  END tap_d[503]
  PIN tap_d[504]
    DIRECTION OUTPUT ;
    USE SIGNAL ;
    PORT
      LAYER M4 ;
        RECT  0 77.136 0.084 77.16 ;
    END
  END tap_d[504]
  PIN tap_d[505]
    DIRECTION OUTPUT ;
    USE SIGNAL ;
    PORT
      LAYER M4 ;
        RECT  0 77.232 0.084 77.256 ;
    END
  END tap_d[505]
  PIN tap_d[506]
    DIRECTION OUTPUT ;
    USE SIGNAL ;
    PORT
      LAYER M4 ;
        RECT  0 77.328 0.084 77.352 ;
    END
  END tap_d[506]
  PIN tap_d[507]
    DIRECTION OUTPUT ;
    USE SIGNAL ;
    PORT
      LAYER M4 ;
        RECT  0 77.424 0.084 77.448 ;
    END
  END tap_d[507]
  PIN tap_d[50]
    DIRECTION OUTPUT ;
    USE SIGNAL ;
    PORT
      LAYER M4 ;
        RECT  0 50.928 0.084 50.952 ;
    END
  END tap_d[50]
  PIN tap_d[51]
    DIRECTION OUTPUT ;
    USE SIGNAL ;
    PORT
      LAYER M4 ;
        RECT  0 51.024 0.084 51.048 ;
    END
  END tap_d[51]
  PIN tap_d[52]
    DIRECTION OUTPUT ;
    USE SIGNAL ;
    PORT
      LAYER M4 ;
        RECT  0 51.12 0.084 51.144 ;
    END
  END tap_d[52]
  PIN tap_d[53]
    DIRECTION OUTPUT ;
    USE SIGNAL ;
    PORT
      LAYER M4 ;
        RECT  0 51.216 0.084 51.24 ;
    END
  END tap_d[53]
  PIN tap_d[54]
    DIRECTION OUTPUT ;
    USE SIGNAL ;
    PORT
      LAYER M4 ;
        RECT  0 51.312 0.084 51.336 ;
    END
  END tap_d[54]
  PIN tap_d[55]
    DIRECTION OUTPUT ;
    USE SIGNAL ;
    PORT
      LAYER M4 ;
        RECT  0 51.408 0.084 51.432 ;
    END
  END tap_d[55]
  PIN tap_d[56]
    DIRECTION OUTPUT ;
    USE SIGNAL ;
    PORT
      LAYER M4 ;
        RECT  0 51.504 0.084 51.528 ;
    END
  END tap_d[56]
  PIN tap_d[57]
    DIRECTION OUTPUT ;
    USE SIGNAL ;
    PORT
      LAYER M4 ;
        RECT  0 51.6 0.084 51.624 ;
    END
  END tap_d[57]
  PIN tap_d[58]
    DIRECTION OUTPUT ;
    USE SIGNAL ;
    PORT
      LAYER M4 ;
        RECT  0 51.696 0.084 51.72 ;
    END
  END tap_d[58]
  PIN tap_d[59]
    DIRECTION OUTPUT ;
    USE SIGNAL ;
    PORT
      LAYER M4 ;
        RECT  0 51.792 0.084 51.816 ;
    END
  END tap_d[59]
  PIN tap_d[5]
    DIRECTION OUTPUT ;
    USE SIGNAL ;
    PORT
      LAYER M4 ;
        RECT  0 58.896 0.084 58.92 ;
    END
  END tap_d[5]
  PIN tap_d[60]
    DIRECTION OUTPUT ;
    USE SIGNAL ;
    PORT
      LAYER M4 ;
        RECT  0 51.888 0.084 51.912 ;
    END
  END tap_d[60]
  PIN tap_d[61]
    DIRECTION OUTPUT ;
    USE SIGNAL ;
    PORT
      LAYER M4 ;
        RECT  0 51.984 0.084 52.008 ;
    END
  END tap_d[61]
  PIN tap_d[62]
    DIRECTION OUTPUT ;
    USE SIGNAL ;
    PORT
      LAYER M4 ;
        RECT  0 52.08 0.084 52.104 ;
    END
  END tap_d[62]
  PIN tap_d[63]
    DIRECTION OUTPUT ;
    USE SIGNAL ;
    PORT
      LAYER M4 ;
        RECT  0 52.176 0.084 52.2 ;
    END
  END tap_d[63]
  PIN tap_d[64]
    DIRECTION OUTPUT ;
    USE SIGNAL ;
    PORT
      LAYER M4 ;
        RECT  0 46.128 0.084 46.152 ;
    END
  END tap_d[64]
  PIN tap_d[65]
    DIRECTION OUTPUT ;
    USE SIGNAL ;
    PORT
      LAYER M4 ;
        RECT  0 46.224 0.084 46.248 ;
    END
  END tap_d[65]
  PIN tap_d[66]
    DIRECTION OUTPUT ;
    USE SIGNAL ;
    PORT
      LAYER M4 ;
        RECT  0 46.32 0.084 46.344 ;
    END
  END tap_d[66]
  PIN tap_d[67]
    DIRECTION OUTPUT ;
    USE SIGNAL ;
    PORT
      LAYER M4 ;
        RECT  0 46.416 0.084 46.44 ;
    END
  END tap_d[67]
  PIN tap_d[68]
    DIRECTION OUTPUT ;
    USE SIGNAL ;
    PORT
      LAYER M4 ;
        RECT  0 46.512 0.084 46.536 ;
    END
  END tap_d[68]
  PIN tap_d[69]
    DIRECTION OUTPUT ;
    USE SIGNAL ;
    PORT
      LAYER M4 ;
        RECT  0 46.608 0.084 46.632 ;
    END
  END tap_d[69]
  PIN tap_d[6]
    DIRECTION OUTPUT ;
    USE SIGNAL ;
    PORT
      LAYER M4 ;
        RECT  0 58.992 0.084 59.016 ;
    END
  END tap_d[6]
  PIN tap_d[70]
    DIRECTION OUTPUT ;
    USE SIGNAL ;
    PORT
      LAYER M4 ;
        RECT  0 46.704 0.084 46.728 ;
    END
  END tap_d[70]
  PIN tap_d[71]
    DIRECTION OUTPUT ;
    USE SIGNAL ;
    PORT
      LAYER M4 ;
        RECT  0 46.8 0.084 46.824 ;
    END
  END tap_d[71]
  PIN tap_d[72]
    DIRECTION OUTPUT ;
    USE SIGNAL ;
    PORT
      LAYER M4 ;
        RECT  0 46.896 0.084 46.92 ;
    END
  END tap_d[72]
  PIN tap_d[73]
    DIRECTION OUTPUT ;
    USE SIGNAL ;
    PORT
      LAYER M4 ;
        RECT  0 46.992 0.084 47.016 ;
    END
  END tap_d[73]
  PIN tap_d[74]
    DIRECTION OUTPUT ;
    USE SIGNAL ;
    PORT
      LAYER M4 ;
        RECT  0 47.088 0.084 47.112 ;
    END
  END tap_d[74]
  PIN tap_d[75]
    DIRECTION OUTPUT ;
    USE SIGNAL ;
    PORT
      LAYER M4 ;
        RECT  0 47.184 0.084 47.208 ;
    END
  END tap_d[75]
  PIN tap_d[76]
    DIRECTION OUTPUT ;
    USE SIGNAL ;
    PORT
      LAYER M4 ;
        RECT  0 47.28 0.084 47.304 ;
    END
  END tap_d[76]
  PIN tap_d[77]
    DIRECTION OUTPUT ;
    USE SIGNAL ;
    PORT
      LAYER M4 ;
        RECT  0 47.376 0.084 47.4 ;
    END
  END tap_d[77]
  PIN tap_d[78]
    DIRECTION OUTPUT ;
    USE SIGNAL ;
    PORT
      LAYER M4 ;
        RECT  0 47.472 0.084 47.496 ;
    END
  END tap_d[78]
  PIN tap_d[79]
    DIRECTION OUTPUT ;
    USE SIGNAL ;
    PORT
      LAYER M4 ;
        RECT  0 47.568 0.084 47.592 ;
    END
  END tap_d[79]
  PIN tap_d[7]
    DIRECTION OUTPUT ;
    USE SIGNAL ;
    PORT
      LAYER M4 ;
        RECT  0 59.088 0.084 59.112 ;
    END
  END tap_d[7]
  PIN tap_d[80]
    DIRECTION OUTPUT ;
    USE SIGNAL ;
    PORT
      LAYER M4 ;
        RECT  0 47.664 0.084 47.688 ;
    END
  END tap_d[80]
  PIN tap_d[81]
    DIRECTION OUTPUT ;
    USE SIGNAL ;
    PORT
      LAYER M4 ;
        RECT  0 47.76 0.084 47.784 ;
    END
  END tap_d[81]
  PIN tap_d[82]
    DIRECTION OUTPUT ;
    USE SIGNAL ;
    PORT
      LAYER M4 ;
        RECT  0 47.856 0.084 47.88 ;
    END
  END tap_d[82]
  PIN tap_d[83]
    DIRECTION OUTPUT ;
    USE SIGNAL ;
    PORT
      LAYER M4 ;
        RECT  0 47.952 0.084 47.976 ;
    END
  END tap_d[83]
  PIN tap_d[84]
    DIRECTION OUTPUT ;
    USE SIGNAL ;
    PORT
      LAYER M4 ;
        RECT  0 48.048 0.084 48.072 ;
    END
  END tap_d[84]
  PIN tap_d[85]
    DIRECTION OUTPUT ;
    USE SIGNAL ;
    PORT
      LAYER M4 ;
        RECT  0 48.144 0.084 48.168 ;
    END
  END tap_d[85]
  PIN tap_d[86]
    DIRECTION OUTPUT ;
    USE SIGNAL ;
    PORT
      LAYER M4 ;
        RECT  0 48.24 0.084 48.264 ;
    END
  END tap_d[86]
  PIN tap_d[87]
    DIRECTION OUTPUT ;
    USE SIGNAL ;
    PORT
      LAYER M4 ;
        RECT  0 48.336 0.084 48.36 ;
    END
  END tap_d[87]
  PIN tap_d[88]
    DIRECTION OUTPUT ;
    USE SIGNAL ;
    PORT
      LAYER M4 ;
        RECT  0 48.432 0.084 48.456 ;
    END
  END tap_d[88]
  PIN tap_d[89]
    DIRECTION OUTPUT ;
    USE SIGNAL ;
    PORT
      LAYER M4 ;
        RECT  0 48.528 0.084 48.552 ;
    END
  END tap_d[89]
  PIN tap_d[8]
    DIRECTION OUTPUT ;
    USE SIGNAL ;
    PORT
      LAYER M4 ;
        RECT  0 59.184 0.084 59.208 ;
    END
  END tap_d[8]
  PIN tap_d[90]
    DIRECTION OUTPUT ;
    USE SIGNAL ;
    PORT
      LAYER M4 ;
        RECT  0 48.624 0.084 48.648 ;
    END
  END tap_d[90]
  PIN tap_d[91]
    DIRECTION OUTPUT ;
    USE SIGNAL ;
    PORT
      LAYER M4 ;
        RECT  0 48.72 0.084 48.744 ;
    END
  END tap_d[91]
  PIN tap_d[92]
    DIRECTION OUTPUT ;
    USE SIGNAL ;
    PORT
      LAYER M4 ;
        RECT  0 48.816 0.084 48.84 ;
    END
  END tap_d[92]
  PIN tap_d[93]
    DIRECTION OUTPUT ;
    USE SIGNAL ;
    PORT
      LAYER M4 ;
        RECT  0 48.912 0.084 48.936 ;
    END
  END tap_d[93]
  PIN tap_d[94]
    DIRECTION OUTPUT ;
    USE SIGNAL ;
    PORT
      LAYER M4 ;
        RECT  0 49.008 0.084 49.032 ;
    END
  END tap_d[94]
  PIN tap_d[95]
    DIRECTION OUTPUT ;
    USE SIGNAL ;
    PORT
      LAYER M4 ;
        RECT  0 49.104 0.084 49.128 ;
    END
  END tap_d[95]
  PIN tap_d[96]
    DIRECTION OUTPUT ;
    USE SIGNAL ;
    PORT
      LAYER M4 ;
        RECT  0 52.272 0.084 52.296 ;
    END
  END tap_d[96]
  PIN tap_d[97]
    DIRECTION OUTPUT ;
    USE SIGNAL ;
    PORT
      LAYER M4 ;
        RECT  0 52.368 0.084 52.392 ;
    END
  END tap_d[97]
  PIN tap_d[98]
    DIRECTION OUTPUT ;
    USE SIGNAL ;
    PORT
      LAYER M4 ;
        RECT  0 52.464 0.084 52.488 ;
    END
  END tap_d[98]
  PIN tap_d[99]
    DIRECTION OUTPUT ;
    USE SIGNAL ;
    PORT
      LAYER M4 ;
        RECT  0 52.56 0.084 52.584 ;
    END
  END tap_d[99]
  PIN tap_d[9]
    DIRECTION OUTPUT ;
    USE SIGNAL ;
    PORT
      LAYER M4 ;
        RECT  0 59.28 0.084 59.304 ;
    END
  END tap_d[9]
  PIN tap_r
    DIRECTION INPUT ;
    USE SIGNAL ;
    PORT
      LAYER M4 ;
        RECT  0 77.52 0.084 77.544 ;
    END
  END tap_r
  PIN VDD
    DIRECTION INOUT ;
    USE POWER ;
    PORT
      LAYER M5 ;
        RECT  45.792 2.151 45.912 101.273 ;
        RECT  40.392 2.151 40.512 101.273 ;
        RECT  34.992 2.151 35.112 101.273 ;
        RECT  29.592 2.151 29.712 101.273 ;
        RECT  24.192 2.151 24.312 101.273 ;
        RECT  18.792 2.151 18.912 101.273 ;
        RECT  13.392 2.151 13.512 101.273 ;
        RECT  7.992 2.151 8.112 101.273 ;
        RECT  2.592 2.151 2.712 101.273 ;
    END
  END VDD
  PIN VSS
    DIRECTION INOUT ;
    USE GROUND ;
    PORT
      LAYER M5 ;
        RECT  45.6 2.137 45.72 101.259 ;
        RECT  40.2 2.137 40.32 101.259 ;
        RECT  34.8 2.137 34.92 101.259 ;
        RECT  29.4 2.137 29.52 101.259 ;
        RECT  24 2.137 24.12 101.259 ;
        RECT  18.6 2.137 18.72 101.259 ;
        RECT  13.2 2.137 13.32 101.259 ;
        RECT  7.8 2.137 7.92 101.259 ;
        RECT  2.4 2.137 2.52 101.259 ;
    END
  END VSS
  OBS
    LAYER RVTN ;
     RECT  2.16 2.16 50.49 2.295 ;
     RECT  2.16 2.565 50.49 2.835 ;
     RECT  2.16 3.105 50.49 3.375 ;
     RECT  2.16 3.645 50.49 3.915 ;
     RECT  2.16 4.185 50.49 4.455 ;
     RECT  2.16 4.725 50.49 4.995 ;
     RECT  2.16 5.265 50.49 5.535 ;
     RECT  2.16 5.805 50.49 6.075 ;
     RECT  2.16 6.345 50.49 6.615 ;
     RECT  2.16 6.885 50.49 7.155 ;
     RECT  2.16 7.425 50.49 7.695 ;
     RECT  2.16 7.965 50.49 8.235 ;
     RECT  2.16 8.505 50.49 8.775 ;
     RECT  2.16 9.045 50.49 9.315 ;
     RECT  2.16 9.585 50.49 9.855 ;
     RECT  2.16 10.125 50.49 10.395 ;
     RECT  2.16 10.665 50.49 10.935 ;
     RECT  2.16 11.205 50.49 11.475 ;
     RECT  2.16 11.745 50.49 12.015 ;
     RECT  2.16 12.285 50.49 12.555 ;
     RECT  2.16 12.825 50.49 13.095 ;
     RECT  2.16 13.365 50.49 13.635 ;
     RECT  2.16 13.905 50.49 14.175 ;
     RECT  2.16 14.445 50.49 14.715 ;
     RECT  2.16 14.985 50.49 15.255 ;
     RECT  2.16 15.525 50.49 15.795 ;
     RECT  2.16 16.065 50.49 16.335 ;
     RECT  2.16 16.605 50.49 16.875 ;
     RECT  2.16 17.145 50.49 17.415 ;
     RECT  2.16 17.685 50.49 17.955 ;
     RECT  2.16 18.225 50.49 18.495 ;
     RECT  2.16 18.765 50.49 19.035 ;
     RECT  2.16 19.305 50.49 19.575 ;
     RECT  2.16 19.845 50.49 20.115 ;
     RECT  2.16 20.385 50.49 20.655 ;
     RECT  2.16 20.925 50.49 21.195 ;
     RECT  2.16 21.465 50.49 21.735 ;
     RECT  2.16 22.005 50.49 22.275 ;
     RECT  2.16 22.545 50.49 22.815 ;
     RECT  2.16 23.085 50.49 23.355 ;
     RECT  2.16 23.625 50.49 23.895 ;
     RECT  2.16 24.165 50.49 24.435 ;
     RECT  2.16 24.705 50.49 24.975 ;
     RECT  2.16 25.245 50.49 25.515 ;
     RECT  2.16 25.785 50.49 26.055 ;
     RECT  2.16 26.325 50.49 26.595 ;
     RECT  2.16 26.865 50.49 27.135 ;
     RECT  2.16 27.405 50.49 27.675 ;
     RECT  2.16 27.945 50.49 28.215 ;
     RECT  2.16 28.485 50.49 28.755 ;
     RECT  2.16 29.025 50.49 29.295 ;
     RECT  2.16 29.565 50.49 29.835 ;
     RECT  2.16 30.105 50.49 30.375 ;
     RECT  2.16 30.645 50.49 30.915 ;
     RECT  2.16 31.185 50.49 31.455 ;
     RECT  2.16 31.725 50.49 31.995 ;
     RECT  2.16 32.265 50.49 32.535 ;
     RECT  2.16 32.805 50.49 33.075 ;
     RECT  2.16 33.345 50.49 33.615 ;
     RECT  2.16 33.885 50.49 34.155 ;
     RECT  2.16 34.425 50.49 34.695 ;
     RECT  2.16 34.965 50.49 35.235 ;
     RECT  2.16 35.505 50.49 35.775 ;
     RECT  2.16 36.045 50.49 36.315 ;
     RECT  2.16 36.585 50.49 36.855 ;
     RECT  2.16 37.125 50.49 37.395 ;
     RECT  2.16 37.665 50.49 37.935 ;
     RECT  2.16 38.205 50.49 38.475 ;
     RECT  2.16 38.745 50.49 39.015 ;
     RECT  2.16 39.285 50.49 39.555 ;
     RECT  2.16 39.825 50.49 40.095 ;
     RECT  2.16 40.365 50.49 40.635 ;
     RECT  2.16 40.905 50.49 41.175 ;
     RECT  2.16 41.445 50.49 41.715 ;
     RECT  2.16 41.985 50.49 42.255 ;
     RECT  2.16 42.525 50.49 42.795 ;
     RECT  2.16 43.065 50.49 43.335 ;
     RECT  2.16 43.605 50.49 43.875 ;
     RECT  2.16 44.145 50.49 44.415 ;
     RECT  2.16 44.685 50.49 44.955 ;
     RECT  2.16 45.225 50.49 45.495 ;
     RECT  2.16 45.765 50.49 46.035 ;
     RECT  2.16 46.305 50.49 46.575 ;
     RECT  2.16 46.845 50.49 47.115 ;
     RECT  2.16 47.385 50.49 47.655 ;
     RECT  2.16 47.925 50.49 48.195 ;
     RECT  2.16 48.465 50.49 48.735 ;
     RECT  2.16 49.005 50.49 49.275 ;
     RECT  2.16 49.545 50.49 49.815 ;
     RECT  2.16 50.085 50.49 50.355 ;
     RECT  2.16 50.625 50.49 50.895 ;
     RECT  2.16 51.165 50.49 51.435 ;
     RECT  2.16 51.705 50.49 51.975 ;
     RECT  2.16 52.245 50.49 52.515 ;
     RECT  2.16 52.785 50.49 53.055 ;
     RECT  2.16 53.325 50.49 53.595 ;
     RECT  2.16 53.865 50.49 54.135 ;
     RECT  2.16 54.405 50.49 54.675 ;
     RECT  2.16 54.945 50.49 55.215 ;
     RECT  2.16 55.485 50.49 55.755 ;
     RECT  2.16 56.025 50.49 56.295 ;
     RECT  2.16 56.565 50.49 56.835 ;
     RECT  2.16 57.105 50.49 57.375 ;
     RECT  2.16 57.645 50.49 57.915 ;
     RECT  2.16 58.185 50.49 58.455 ;
     RECT  2.16 58.725 50.49 58.995 ;
     RECT  2.16 59.265 50.49 59.535 ;
     RECT  2.16 59.805 50.49 60.075 ;
     RECT  2.16 60.345 50.49 60.615 ;
     RECT  2.16 60.885 50.49 61.155 ;
     RECT  2.16 61.425 50.49 61.695 ;
     RECT  2.16 61.965 50.49 62.235 ;
     RECT  2.16 62.505 50.49 62.775 ;
     RECT  2.16 63.045 50.49 63.315 ;
     RECT  2.16 63.585 50.49 63.855 ;
     RECT  2.16 64.125 50.49 64.395 ;
     RECT  2.16 64.665 50.49 64.935 ;
     RECT  2.16 65.205 50.49 65.475 ;
     RECT  2.16 65.745 50.49 66.015 ;
     RECT  2.16 66.285 50.49 66.555 ;
     RECT  2.16 66.825 50.49 67.095 ;
     RECT  2.16 67.365 50.49 67.635 ;
     RECT  2.16 67.905 50.49 68.175 ;
     RECT  2.16 68.445 50.49 68.715 ;
     RECT  2.16 68.985 50.49 69.255 ;
     RECT  2.16 69.525 50.49 69.795 ;
     RECT  2.16 70.065 50.49 70.335 ;
     RECT  2.16 70.605 50.49 70.875 ;
     RECT  2.16 71.145 50.49 71.415 ;
     RECT  2.16 71.685 50.49 71.955 ;
     RECT  2.16 72.225 50.49 72.495 ;
     RECT  2.16 72.765 50.49 73.035 ;
     RECT  2.16 73.305 50.49 73.575 ;
     RECT  2.16 73.845 50.49 74.115 ;
     RECT  2.16 74.385 50.49 74.655 ;
     RECT  2.16 74.925 50.49 75.195 ;
     RECT  2.16 75.465 50.49 75.735 ;
     RECT  2.16 76.005 50.49 76.275 ;
     RECT  2.16 76.545 50.49 76.815 ;
     RECT  2.16 77.085 50.49 77.355 ;
     RECT  2.16 77.625 50.49 77.895 ;
     RECT  2.16 78.165 50.49 78.435 ;
     RECT  2.16 78.705 50.49 78.975 ;
     RECT  2.16 79.245 50.49 79.515 ;
     RECT  2.16 79.785 50.49 80.055 ;
     RECT  2.16 80.325 50.49 80.595 ;
     RECT  2.16 80.865 50.49 81.135 ;
     RECT  2.16 81.405 50.49 81.675 ;
     RECT  2.16 81.945 50.49 82.215 ;
     RECT  2.16 82.485 50.49 82.755 ;
     RECT  2.16 83.025 50.49 83.295 ;
     RECT  2.16 83.565 50.49 83.835 ;
     RECT  2.16 84.105 50.49 84.375 ;
     RECT  2.16 84.645 50.49 84.915 ;
     RECT  2.16 85.185 50.49 85.455 ;
     RECT  2.16 85.725 50.49 85.995 ;
     RECT  2.16 86.265 50.49 86.535 ;
     RECT  2.16 86.805 50.49 87.075 ;
     RECT  2.16 87.345 50.49 87.615 ;
     RECT  2.16 87.885 50.49 88.155 ;
     RECT  2.16 88.425 50.49 88.695 ;
     RECT  2.16 88.965 50.49 89.235 ;
     RECT  2.16 89.505 50.49 89.775 ;
     RECT  2.16 90.045 50.49 90.315 ;
     RECT  2.16 90.585 50.49 90.855 ;
     RECT  2.16 91.125 50.49 91.395 ;
     RECT  2.16 91.665 50.49 91.935 ;
     RECT  2.16 92.205 50.49 92.475 ;
     RECT  2.16 92.745 50.49 93.015 ;
     RECT  2.16 93.285 50.49 93.555 ;
     RECT  2.16 93.825 50.49 94.095 ;
     RECT  2.16 94.365 50.49 94.635 ;
     RECT  2.16 94.905 50.49 95.175 ;
     RECT  2.16 95.445 50.49 95.715 ;
     RECT  2.16 95.985 50.49 96.255 ;
     RECT  2.16 96.525 50.49 96.795 ;
     RECT  2.16 97.065 50.49 97.335 ;
     RECT  2.16 97.605 50.49 97.875 ;
     RECT  2.16 98.145 50.49 98.415 ;
     RECT  2.16 98.685 50.49 98.955 ;
     RECT  2.16 99.225 50.49 99.495 ;
     RECT  2.16 99.765 50.49 100.035 ;
     RECT  2.16 100.305 50.49 100.575 ;
     RECT  2.16 100.845 50.49 101.115 ;
    LAYER RVTP ;
     RECT  2.16 2.295 50.49 2.565 ;
     RECT  2.16 2.835 50.49 3.105 ;
     RECT  2.16 3.375 50.49 3.645 ;
     RECT  2.16 3.915 50.49 4.185 ;
     RECT  2.16 4.455 50.49 4.725 ;
     RECT  2.16 4.995 50.49 5.265 ;
     RECT  2.16 5.535 50.49 5.805 ;
     RECT  2.16 6.075 50.49 6.345 ;
     RECT  2.16 6.615 50.49 6.885 ;
     RECT  2.16 7.155 50.49 7.425 ;
     RECT  2.16 7.695 50.49 7.965 ;
     RECT  2.16 8.235 50.49 8.505 ;
     RECT  2.16 8.775 50.49 9.045 ;
     RECT  2.16 9.315 50.49 9.585 ;
     RECT  2.16 9.855 50.49 10.125 ;
     RECT  2.16 10.395 50.49 10.665 ;
     RECT  2.16 10.935 50.49 11.205 ;
     RECT  2.16 11.475 50.49 11.745 ;
     RECT  2.16 12.015 50.49 12.285 ;
     RECT  2.16 12.555 50.49 12.825 ;
     RECT  2.16 13.095 50.49 13.365 ;
     RECT  2.16 13.635 50.49 13.905 ;
     RECT  2.16 14.175 50.49 14.445 ;
     RECT  2.16 14.715 50.49 14.985 ;
     RECT  2.16 15.255 50.49 15.525 ;
     RECT  2.16 15.795 50.49 16.065 ;
     RECT  2.16 16.335 50.49 16.605 ;
     RECT  2.16 16.875 50.49 17.145 ;
     RECT  2.16 17.415 50.49 17.685 ;
     RECT  2.16 17.955 50.49 18.225 ;
     RECT  2.16 18.495 50.49 18.765 ;
     RECT  2.16 19.035 50.49 19.305 ;
     RECT  2.16 19.575 50.49 19.845 ;
     RECT  2.16 20.115 50.49 20.385 ;
     RECT  2.16 20.655 50.49 20.925 ;
     RECT  2.16 21.195 50.49 21.465 ;
     RECT  2.16 21.735 50.49 22.005 ;
     RECT  2.16 22.275 50.49 22.545 ;
     RECT  2.16 22.815 50.49 23.085 ;
     RECT  2.16 23.355 50.49 23.625 ;
     RECT  2.16 23.895 50.49 24.165 ;
     RECT  2.16 24.435 50.49 24.705 ;
     RECT  2.16 24.975 50.49 25.245 ;
     RECT  2.16 25.515 50.49 25.785 ;
     RECT  2.16 26.055 50.49 26.325 ;
     RECT  2.16 26.595 50.49 26.865 ;
     RECT  2.16 27.135 50.49 27.405 ;
     RECT  2.16 27.675 50.49 27.945 ;
     RECT  2.16 28.215 50.49 28.485 ;
     RECT  2.16 28.755 50.49 29.025 ;
     RECT  2.16 29.295 50.49 29.565 ;
     RECT  2.16 29.835 50.49 30.105 ;
     RECT  2.16 30.375 50.49 30.645 ;
     RECT  2.16 30.915 50.49 31.185 ;
     RECT  2.16 31.455 50.49 31.725 ;
     RECT  2.16 31.995 50.49 32.265 ;
     RECT  2.16 32.535 50.49 32.805 ;
     RECT  2.16 33.075 50.49 33.345 ;
     RECT  2.16 33.615 50.49 33.885 ;
     RECT  2.16 34.155 50.49 34.425 ;
     RECT  2.16 34.695 50.49 34.965 ;
     RECT  2.16 35.235 50.49 35.505 ;
     RECT  2.16 35.775 50.49 36.045 ;
     RECT  2.16 36.315 50.49 36.585 ;
     RECT  2.16 36.855 50.49 37.125 ;
     RECT  2.16 37.395 50.49 37.665 ;
     RECT  2.16 37.935 50.49 38.205 ;
     RECT  2.16 38.475 50.49 38.745 ;
     RECT  2.16 39.015 50.49 39.285 ;
     RECT  2.16 39.555 50.49 39.825 ;
     RECT  2.16 40.095 50.49 40.365 ;
     RECT  2.16 40.635 50.49 40.905 ;
     RECT  2.16 41.175 50.49 41.445 ;
     RECT  2.16 41.715 50.49 41.985 ;
     RECT  2.16 42.255 50.49 42.525 ;
     RECT  2.16 42.795 50.49 43.065 ;
     RECT  2.16 43.335 50.49 43.605 ;
     RECT  2.16 43.875 50.49 44.145 ;
     RECT  2.16 44.415 50.49 44.685 ;
     RECT  2.16 44.955 50.49 45.225 ;
     RECT  2.16 45.495 50.49 45.765 ;
     RECT  2.16 46.035 50.49 46.305 ;
     RECT  2.16 46.575 50.49 46.845 ;
     RECT  2.16 47.115 50.49 47.385 ;
     RECT  2.16 47.655 50.49 47.925 ;
     RECT  2.16 48.195 50.49 48.465 ;
     RECT  2.16 48.735 50.49 49.005 ;
     RECT  2.16 49.275 50.49 49.545 ;
     RECT  2.16 49.815 50.49 50.085 ;
     RECT  2.16 50.355 50.49 50.625 ;
     RECT  2.16 50.895 50.49 51.165 ;
     RECT  2.16 51.435 50.49 51.705 ;
     RECT  2.16 51.975 50.49 52.245 ;
     RECT  2.16 52.515 50.49 52.785 ;
     RECT  2.16 53.055 50.49 53.325 ;
     RECT  2.16 53.595 50.49 53.865 ;
     RECT  2.16 54.135 50.49 54.405 ;
     RECT  2.16 54.675 50.49 54.945 ;
     RECT  2.16 55.215 50.49 55.485 ;
     RECT  2.16 55.755 50.49 56.025 ;
     RECT  2.16 56.295 50.49 56.565 ;
     RECT  2.16 56.835 50.49 57.105 ;
     RECT  2.16 57.375 50.49 57.645 ;
     RECT  2.16 57.915 50.49 58.185 ;
     RECT  2.16 58.455 50.49 58.725 ;
     RECT  2.16 58.995 50.49 59.265 ;
     RECT  2.16 59.535 50.49 59.805 ;
     RECT  2.16 60.075 50.49 60.345 ;
     RECT  2.16 60.615 50.49 60.885 ;
     RECT  2.16 61.155 50.49 61.425 ;
     RECT  2.16 61.695 50.49 61.965 ;
     RECT  2.16 62.235 50.49 62.505 ;
     RECT  2.16 62.775 50.49 63.045 ;
     RECT  2.16 63.315 50.49 63.585 ;
     RECT  2.16 63.855 50.49 64.125 ;
     RECT  2.16 64.395 50.49 64.665 ;
     RECT  2.16 64.935 50.49 65.205 ;
     RECT  2.16 65.475 50.49 65.745 ;
     RECT  2.16 66.015 50.49 66.285 ;
     RECT  2.16 66.555 50.49 66.825 ;
     RECT  2.16 67.095 50.49 67.365 ;
     RECT  2.16 67.635 50.49 67.905 ;
     RECT  2.16 68.175 50.49 68.445 ;
     RECT  2.16 68.715 50.49 68.985 ;
     RECT  2.16 69.255 50.49 69.525 ;
     RECT  2.16 69.795 50.49 70.065 ;
     RECT  2.16 70.335 50.49 70.605 ;
     RECT  2.16 70.875 50.49 71.145 ;
     RECT  2.16 71.415 50.49 71.685 ;
     RECT  2.16 71.955 50.49 72.225 ;
     RECT  2.16 72.495 50.49 72.765 ;
     RECT  2.16 73.035 50.49 73.305 ;
     RECT  2.16 73.575 50.49 73.845 ;
     RECT  2.16 74.115 50.49 74.385 ;
     RECT  2.16 74.655 50.49 74.925 ;
     RECT  2.16 75.195 50.49 75.465 ;
     RECT  2.16 75.735 50.49 76.005 ;
     RECT  2.16 76.275 50.49 76.545 ;
     RECT  2.16 76.815 50.49 77.085 ;
     RECT  2.16 77.355 50.49 77.625 ;
     RECT  2.16 77.895 50.49 78.165 ;
     RECT  2.16 78.435 50.49 78.705 ;
     RECT  2.16 78.975 50.49 79.245 ;
     RECT  2.16 79.515 50.49 79.785 ;
     RECT  2.16 80.055 50.49 80.325 ;
     RECT  2.16 80.595 50.49 80.865 ;
     RECT  2.16 81.135 50.49 81.405 ;
     RECT  2.16 81.675 50.49 81.945 ;
     RECT  2.16 82.215 50.49 82.485 ;
     RECT  2.16 82.755 50.49 83.025 ;
     RECT  2.16 83.295 50.49 83.565 ;
     RECT  2.16 83.835 50.49 84.105 ;
     RECT  2.16 84.375 50.49 84.645 ;
     RECT  2.16 84.915 50.49 85.185 ;
     RECT  2.16 85.455 50.49 85.725 ;
     RECT  2.16 85.995 50.49 86.265 ;
     RECT  2.16 86.535 50.49 86.805 ;
     RECT  2.16 87.075 50.49 87.345 ;
     RECT  2.16 87.615 50.49 87.885 ;
     RECT  2.16 88.155 50.49 88.425 ;
     RECT  2.16 88.695 50.49 88.965 ;
     RECT  2.16 89.235 50.49 89.505 ;
     RECT  2.16 89.775 50.49 90.045 ;
     RECT  2.16 90.315 50.49 90.585 ;
     RECT  2.16 90.855 50.49 91.125 ;
     RECT  2.16 91.395 50.49 91.665 ;
     RECT  2.16 91.935 50.49 92.205 ;
     RECT  2.16 92.475 50.49 92.745 ;
     RECT  2.16 93.015 50.49 93.285 ;
     RECT  2.16 93.555 50.49 93.825 ;
     RECT  2.16 94.095 50.49 94.365 ;
     RECT  2.16 94.635 50.49 94.905 ;
     RECT  2.16 95.175 50.49 95.445 ;
     RECT  2.16 95.715 50.49 95.985 ;
     RECT  2.16 96.255 50.49 96.525 ;
     RECT  2.16 96.795 50.49 97.065 ;
     RECT  2.16 97.335 50.49 97.605 ;
     RECT  2.16 97.875 50.49 98.145 ;
     RECT  2.16 98.415 50.49 98.685 ;
     RECT  2.16 98.955 50.49 99.225 ;
     RECT  2.16 99.495 50.49 99.765 ;
     RECT  2.16 100.035 50.49 100.305 ;
     RECT  2.16 100.575 50.49 100.845 ;
     RECT  2.16 101.115 50.49 101.25 ;
    LAYER M1 ;
     RECT  2.16 2.151 50.49 101.259 ;
    LAYER M2 ;
     RECT  0.031 66.366 0.103 66.384 ;
     RECT  0.031 67.14 0.103 67.158 ;
     RECT  0.103 38.376 0.139 38.394 ;
     RECT  0.031 39.294 0.139 39.312 ;
     RECT  0.103 59.346 0.139 60.336 ;
     RECT  0.103 71.586 0.139 72.324 ;
     RECT  0.103 28.836 0.175 28.854 ;
     RECT  0.103 30.312 0.175 30.33 ;
     RECT  0.103 34.974 0.203 34.992 ;
     RECT  0.103 45.036 0.203 45.18 ;
     RECT  0.103 47.322 0.203 47.34 ;
     RECT  0.103 49.131 0.203 50.004 ;
     RECT  0.103 51.516 0.203 51.534 ;
     RECT  0.103 52.686 0.203 53.046 ;
     RECT  0.103 55.53 0.203 55.548 ;
     RECT  0.139 59.202 0.203 60.336 ;
     RECT  0.103 26.766 0.211 27.504 ;
     RECT  0.139 38.376 0.211 39.474 ;
     RECT  0.103 40.374 0.211 40.392 ;
     RECT  0.203 45.126 0.211 45.18 ;
     RECT  0.103 68.184 0.211 68.814 ;
     RECT  0.103 69.696 0.211 69.714 ;
     RECT  0.203 49.131 0.239 49.536 ;
     RECT  0.139 54.378 0.239 54.396 ;
     RECT  0.175 34.128 0.275 34.146 ;
     RECT  0.175 63.216 0.283 63.234 ;
     RECT  0.103 64.17 0.319 64.314 ;
     RECT  0.239 49.131 0.347 49.149 ;
     RECT  0.103 74.052 0.347 74.07 ;
     RECT  0.103 61.2 0.391 61.218 ;
     RECT  0.103 65.916 0.391 67.158 ;
     RECT  0.103 62.046 0.427 62.064 ;
     RECT  0.283 62.946 0.427 63.234 ;
     RECT  0.391 61.056 0.463 61.218 ;
     RECT  0.427 62.046 0.463 63.234 ;
     RECT  0.211 26.226 0.499 27.504 ;
     RECT  0.103 57.006 0.499 57.474 ;
     RECT  0.175 28.836 0.535 29.052 ;
     RECT  0.499 57.006 0.535 57.744 ;
     RECT  0.463 61.056 0.535 63.234 ;
     RECT  0.319 64.17 0.535 64.854 ;
     RECT  0.391 65.646 0.535 67.158 ;
     RECT  0.211 68.076 0.535 69.714 ;
     RECT  0.535 28.422 0.571 29.052 ;
     RECT  0.175 30.186 0.571 30.33 ;
     RECT  0.391 74.016 0.571 74.034 ;
     RECT  0.535 56.916 0.599 57.744 ;
     RECT  0.571 42.966 0.671 42.984 ;
     RECT  0.139 71.226 1.039 72.324 ;
     RECT  0.031 37.566 1.075 37.584 ;
     RECT  0.211 38.376 1.075 40.392 ;
     RECT  0.535 77.634 1.075 77.652 ;
     RECT  1.075 77.526 1.111 77.652 ;
     RECT  0.535 41.994 1.147 42.012 ;
     RECT  0.211 45.126 1.147 45.684 ;
     RECT  0.103 75.366 1.147 75.384 ;
     RECT  1.111 77.526 1.147 77.922 ;
     RECT  0.499 26.226 1.183 27.666 ;
     RECT  0.571 28.422 1.183 30.33 ;
     RECT  1.147 41.994 1.183 42.174 ;
     RECT  1.075 37.566 1.219 40.392 ;
     RECT  0.247 43.776 1.219 43.794 ;
     RECT  1.147 44.964 1.219 45.684 ;
     RECT  1.147 77.328 1.219 77.922 ;
     RECT  1.183 79.416 1.219 79.434 ;
     RECT  1.219 37.476 1.319 40.464 ;
     RECT  1.219 76.86 1.319 77.922 ;
     RECT  1.219 44.892 1.355 45.684 ;
     RECT  1.219 78.948 1.399 79.434 ;
     RECT  1.399 78.948 1.435 79.776 ;
     RECT  1.183 26.226 1.615 30.33 ;
     RECT  0.103 31.086 1.615 31.104 ;
     RECT  0.571 34.326 1.651 34.344 ;
     RECT  1.147 75.366 1.651 75.996 ;
     RECT  1.219 43.236 1.723 43.794 ;
     RECT  0.571 73.656 1.723 74.034 ;
     RECT  1.435 78.948 1.723 80.352 ;
     RECT  1.723 33.246 1.759 33.264 ;
     RECT  1.651 34.164 1.759 34.344 ;
     RECT  1.723 78.948 1.759 80.514 ;
     RECT  1.219 15.462 1.795 15.48 ;
     RECT  1.039 71.226 1.795 72.522 ;
     RECT  1.723 73.278 1.795 74.484 ;
     RECT  1.183 41.688 1.903 42.174 ;
     RECT  1.795 15.462 1.939 16.02 ;
     RECT  1.615 26.226 1.939 31.104 ;
     RECT  1.147 32.436 1.939 32.454 ;
     RECT  1.939 26.226 2.011 32.454 ;
     RECT  1.759 33.246 2.011 34.344 ;
     RECT  1.939 15.462 2.047 16.164 ;
     RECT  1.579 35.748 2.047 35.766 ;
     RECT  1.867 24.372 2.083 24.39 ;
     RECT  0.535 54.918 2.083 54.936 ;
     RECT  0.427 55.926 2.083 55.944 ;
     RECT  1.219 18.432 2.155 18.45 ;
     RECT  1.319 37.566 2.155 40.464 ;
     RECT  1.903 41.526 2.155 42.174 ;
     RECT  1.723 43.236 2.155 44.334 ;
     RECT  0.535 65.646 2.155 69.714 ;
     RECT  1.147 14.112 2.16 14.13 ;
     RECT  2.047 15.462 2.16 16.704 ;
     RECT  2.155 18.432 2.16 19.134 ;
     RECT  2.083 23.832 2.16 24.39 ;
     RECT  2.011 26.226 2.16 34.344 ;
     RECT  2.047 35.316 2.16 35.766 ;
     RECT  2.155 37.476 2.16 40.464 ;
     RECT  2.155 41.526 2.16 44.334 ;
     RECT  1.355 45.126 2.16 45.684 ;
     RECT  2.083 54.918 2.16 55.944 ;
     RECT  0.599 56.916 2.16 57.474 ;
     RECT  0.203 59.202 2.16 59.832 ;
     RECT  0.535 61.056 2.16 64.854 ;
     RECT  2.155 65.646 2.16 70.092 ;
     RECT  1.795 71.226 2.16 74.484 ;
     RECT  1.651 75.366 2.16 76.536 ;
     RECT  1.319 77.328 2.16 77.922 ;
     RECT  1.759 78.876 2.16 80.514 ;
     RECT  1.795 96.066 2.16 96.084 ;
     RECT  19.615 0.846 19.939 0.864 ;
     RECT  19.939 0.846 24.035 0.9 ;
     RECT  24.035 0.846 24.071 0.864 ;
     RECT  26.851 0.036 27.139 0.054 ;
     RECT  27.139 0.036 29.155 0.09 ;
     RECT  29.155 0.036 29.255 0.468 ;
     RECT  39.199 102.591 39.235 102.609 ;
     RECT  39.235 102.51 39.335 102.609 ;
     RECT  29.255 0.036 40.567 0.09 ;
     RECT  40.567 0.036 40.847 0.36 ;
     RECT  40.847 0.036 49.631 0.09 ;
     RECT  49.631 0.072 49.703 0.09 ;
     RECT  2.16 2.151 50.49 101.259 ;
     RECT  50.49 39.096 50.603 40.194 ;
     RECT  50.603 40.176 50.675 40.194 ;
     RECT  50.49 96.876 50.819 99.054 ;
     RECT  50.603 39.096 50.855 39.429 ;
     RECT  50.855 39.096 50.891 39.384 ;
     RECT  50.891 39.366 50.963 39.384 ;
     RECT  50.49 2.196 51.035 2.214 ;
     RECT  50.819 97.416 51.179 99.054 ;
     RECT  51.179 98.046 51.251 99.054 ;
     RECT  51.251 98.316 51.323 99.054 ;
     RECT  51.323 98.316 51.359 98.604 ;
     RECT  51.359 98.541 51.395 98.604 ;
     RECT  51.395 98.541 51.467 98.559 ;
    LAYER M3 ;
     RECT  26.856 0.031 26.874 0.067 ;
     RECT  49.608 0.031 49.626 0.067 ;
     RECT  39.924 0.043 39.942 0.091 ;
     RECT  42.228 0.043 42.246 0.091 ;
     RECT  49.608 0.067 49.698 0.091 ;
     RECT  27.9 0.091 27.918 0.139 ;
     RECT  29.16 0.091 29.178 0.139 ;
     RECT  39.528 0.091 39.942 0.139 ;
     RECT  40.752 0.091 42.714 0.139 ;
     RECT  13.428 0.043 13.446 0.173 ;
     RECT  39.528 0.139 42.714 0.173 ;
     RECT  24.84 0.091 24.858 0.235 ;
     RECT  26.856 0.067 27.162 0.235 ;
     RECT  2.34 0.091 2.358 0.269 ;
     RECT  31.932 0.091 34.83 0.269 ;
     RECT  39.528 0.173 39.654 0.269 ;
     RECT  45.936 0.091 46.062 0.269 ;
     RECT  45.936 0.269 45.954 0.283 ;
     RECT  31.932 0.269 34.758 0.317 ;
     RECT  37.152 0.091 38.286 0.317 ;
     RECT  26.748 0.235 27.162 0.331 ;
     RECT  40.572 0.173 42.714 0.365 ;
     RECT  21.276 0.091 24.066 0.379 ;
     RECT  24.84 0.235 25.218 0.379 ;
     RECT  27.9 0.139 29.178 0.379 ;
     RECT  5.94 0.091 6.138 0.427 ;
     RECT  7.02 0.379 7.038 0.427 ;
     RECT  19.584 0.043 19.602 0.427 ;
     RECT  5.94 0.427 7.038 0.475 ;
     RECT  21.276 0.379 25.218 0.475 ;
     RECT  27.9 0.379 29.358 0.509 ;
     RECT  5.94 0.475 7.326 0.523 ;
     RECT  19.584 0.427 20.358 0.523 ;
     RECT  21.276 0.475 25.434 0.523 ;
     RECT  36.072 0.091 36.27 0.523 ;
     RECT  37.152 0.317 37.17 0.523 ;
     RECT  49.464 0.091 51.03 0.523 ;
     RECT  8.568 0.091 9.162 0.571 ;
     RECT  30.852 0.091 30.87 0.571 ;
     RECT  30.708 0.571 30.87 0.619 ;
     RECT  30.456 0.619 30.87 0.763 ;
     RECT  18.756 0.091 18.774 0.811 ;
     RECT  19.584 0.523 25.434 0.811 ;
     RECT  26.244 0.331 27.162 0.811 ;
     RECT  31.932 0.317 34.65 0.811 ;
     RECT  37.908 0.317 38.286 0.811 ;
     RECT  30.348 0.763 30.87 0.859 ;
     RECT  31.716 0.811 34.65 0.859 ;
     RECT  37.908 0.811 38.466 0.907 ;
     RECT  39.528 0.269 39.546 0.907 ;
     RECT  36.072 0.523 37.17 1.051 ;
     RECT  10.548 0.523 10.566 1.099 ;
     RECT  30.348 0.859 34.65 1.099 ;
     RECT  35.712 1.051 37.17 1.099 ;
     RECT  40.716 0.365 42.714 1.099 ;
     RECT  45.756 0.283 45.954 1.099 ;
     RECT  11.664 0.523 11.682 1.147 ;
     RECT  27.9 0.509 28.782 1.229 ;
     RECT  19.584 0.811 27.162 1.435 ;
     RECT  27.9 1.229 28.566 1.435 ;
     RECT  10.548 1.099 10.602 1.579 ;
     RECT  37.908 0.907 39.546 1.579 ;
     RECT  10.116 1.579 10.602 1.627 ;
     RECT  11.376 1.147 11.682 1.627 ;
     RECT  5.148 1.099 5.166 1.675 ;
     RECT  8.568 0.571 9.306 1.675 ;
     RECT  10.044 1.627 11.682 1.675 ;
     RECT  8.568 1.675 11.682 1.723 ;
     RECT  12.6 1.099 12.618 1.723 ;
     RECT  13.572 0.571 13.59 1.723 ;
     RECT  45.756 1.099 46.026 1.723 ;
     RECT  3.492 0.571 3.51 1.915 ;
     RECT  2.88 1.915 3.51 2.011 ;
     RECT  12.6 1.723 12.69 2.011 ;
     RECT  13.572 1.723 14.238 2.011 ;
     RECT  30.348 1.099 37.17 2.011 ;
     RECT  37.908 1.579 39.618 2.011 ;
     RECT  45.756 1.723 46.746 2.011 ;
     RECT  2.772 2.011 3.51 2.143 ;
     RECT  5.94 0.523 7.614 2.143 ;
     RECT  8.568 1.723 11.862 2.143 ;
     RECT  29.556 2.011 29.574 2.143 ;
     RECT  30.348 2.011 39.618 2.143 ;
     RECT  40.716 1.099 42.858 2.143 ;
     RECT  4.896 1.675 5.166 2.203 ;
     RECT  45.108 2.011 46.746 2.203 ;
     RECT  49.284 0.523 51.03 2.219 ;
     RECT  4.824 2.203 5.166 2.251 ;
     RECT  5.94 2.143 11.862 2.251 ;
     RECT  18.108 0.811 18.774 2.413 ;
     RECT  19.584 1.435 28.566 2.413 ;
     RECT  29.415 2.143 29.574 2.413 ;
     RECT  30.348 2.143 42.858 2.413 ;
     RECT  4.464 2.251 11.862 3.605 ;
     RECT  2.415 2.143 3.51 3.979 ;
     RECT  4.464 3.605 11.754 3.979 ;
     RECT  2.415 3.979 11.754 5.131 ;
     RECT  12.6 2.011 14.238 5.131 ;
     RECT  29.415 2.413 42.858 5.563 ;
     RECT  2.415 5.131 14.238 5.765 ;
     RECT  5.94 5.765 14.238 6.413 ;
     RECT  14.976 5.227 14.994 6.583 ;
     RECT  16.164 1.723 16.506 6.583 ;
     RECT  49.284 2.219 50.958 6.691 ;
     RECT  18.108 2.413 28.566 6.817 ;
     RECT  29.376 5.563 42.858 6.817 ;
     RECT  45.072 2.203 46.746 7.385 ;
     RECT  2.415 5.765 5.166 7.435 ;
     RECT  5.976 6.413 14.238 7.435 ;
     RECT  14.976 6.583 16.506 7.435 ;
     RECT  45.108 7.385 46.746 7.435 ;
     RECT  45.108 7.435 46.854 7.483 ;
     RECT  47.772 7.435 47.79 7.483 ;
     RECT  2.304 7.435 16.506 7.663 ;
     RECT  2.304 7.663 16.686 7.963 ;
     RECT  18.108 6.817 42.858 7.963 ;
     RECT  45.108 7.483 47.79 7.963 ;
     RECT  48.564 6.691 50.958 7.963 ;
     RECT  2.304 7.963 16.794 7.997 ;
     RECT  5.976 7.997 16.794 8.011 ;
     RECT  17.676 7.963 42.858 8.011 ;
     RECT  45.108 7.963 50.958 8.275 ;
     RECT  44.892 8.275 50.958 8.311 ;
     RECT  2.304 7.997 5.166 9.545 ;
     RECT  2.34 9.545 5.166 10.831 ;
     RECT  2.34 10.831 5.238 11.261 ;
     RECT  2.415 11.261 5.238 11.419 ;
     RECT  5.976 8.011 42.858 11.419 ;
     RECT  44.82 8.311 50.958 13.019 ;
     RECT  2.415 11.419 42.858 13.099 ;
     RECT  1.152 13.099 1.17 13.147 ;
     RECT  1.908 13.099 42.858 13.147 ;
     RECT  1.152 13.147 42.858 13.325 ;
     RECT  1.152 13.325 2.697 14.071 ;
     RECT  3.492 13.325 42.858 14.071 ;
     RECT  1.152 14.071 42.858 14.135 ;
     RECT  1.224 14.135 42.858 14.513 ;
     RECT  14.868 14.513 42.858 14.945 ;
     RECT  44.82 13.019 48.402 15.295 ;
     RECT  44.784 15.295 48.402 15.331 ;
     RECT  1.224 14.513 13.986 15.485 ;
     RECT  1.8 15.485 13.986 16.025 ;
     RECT  1.944 16.025 13.986 16.411 ;
     RECT  14.904 14.945 42.858 16.411 ;
     RECT  44.676 15.331 48.402 16.835 ;
     RECT  43.92 16.141 43.938 17.041 ;
     RECT  44.676 16.835 48.366 17.041 ;
     RECT  1.944 16.411 42.858 18.235 ;
     RECT  1.224 18.235 42.858 18.455 ;
     RECT  1.944 18.455 42.858 24.367 ;
     RECT  0.216 26.221 0.234 26.491 ;
     RECT  0.216 26.491 0.27 26.761 ;
     RECT  43.92 17.041 48.366 26.825 ;
     RECT  0.108 26.761 0.27 26.941 ;
     RECT  0.108 26.941 0.486 27.103 ;
     RECT  1.872 24.367 42.858 27.403 ;
     RECT  0.108 27.103 0.558 27.409 ;
     RECT  1.728 27.403 42.858 27.409 ;
     RECT  43.992 26.825 48.366 29.083 ;
     RECT  49.284 13.019 50.958 29.083 ;
     RECT  0.108 27.409 42.858 29.165 ;
     RECT  43.992 29.083 50.958 30.181 ;
     RECT  0.144 29.165 42.858 30.307 ;
     RECT  0.108 30.307 42.93 30.605 ;
     RECT  43.74 30.181 50.958 30.721 ;
     RECT  1.152 30.605 42.93 30.811 ;
     RECT  43.668 30.721 50.958 30.811 ;
     RECT  0.108 30.605 0.198 31.339 ;
     RECT  0.108 31.339 0.342 31.661 ;
     RECT  1.152 30.811 50.958 32.459 ;
     RECT  0.144 31.661 0.342 32.971 ;
     RECT  1.512 32.459 50.958 33.107 ;
     RECT  1.512 33.107 48.222 34.051 ;
     RECT  48.996 33.107 50.958 34.051 ;
     RECT  0.144 32.971 0.594 34.349 ;
     RECT  0.144 34.349 0.342 34.969 ;
     RECT  0.108 34.969 0.342 35.213 ;
     RECT  0.18 35.213 0.342 35.261 ;
     RECT  0.216 35.261 0.342 35.501 ;
     RECT  0.216 35.501 0.234 35.693 ;
     RECT  1.512 34.051 50.958 36.653 ;
     RECT  0.144 36.571 0.162 36.749 ;
     RECT  1.512 36.653 39.078 36.851 ;
     RECT  1.512 36.851 38.934 37.147 ;
     RECT  1.152 37.147 38.934 37.319 ;
     RECT  38.844 37.319 38.934 37.391 ;
     RECT  1.152 37.319 37.926 37.421 ;
     RECT  1.224 37.421 37.926 37.517 ;
     RECT  38.916 37.391 38.934 37.733 ;
     RECT  40.215 36.653 50.958 37.769 ;
     RECT  40.215 37.769 42.174 37.859 ;
     RECT  43.452 37.769 50.958 37.859 ;
     RECT  41.328 37.859 42.174 37.931 ;
     RECT  44.1 37.859 50.958 37.967 ;
     RECT  0.036 37.561 0.054 38.059 ;
     RECT  1.512 37.517 37.926 38.165 ;
     RECT  41.328 37.931 41.958 38.165 ;
     RECT  0.036 38.059 0.342 38.189 ;
     RECT  1.512 38.165 37.854 38.245 ;
     RECT  44.136 37.967 50.958 38.273 ;
     RECT  1.116 38.245 37.854 38.281 ;
     RECT  44.136 38.273 48.942 38.705 ;
     RECT  41.328 38.165 41.922 38.741 ;
     RECT  44.928 38.705 48.942 38.777 ;
     RECT  49.896 38.273 50.958 38.849 ;
     RECT  0.036 38.189 0.234 38.923 ;
     RECT  0.036 38.923 0.342 39.053 ;
     RECT  44.136 38.705 44.154 39.055 ;
     RECT  0.036 39.053 0.234 39.317 ;
     RECT  50.472 38.849 50.958 39.389 ;
     RECT  50.472 39.389 50.85 39.434 ;
     RECT  43.488 39.055 44.154 39.631 ;
     RECT  42.768 39.631 44.154 39.857 ;
     RECT  50.472 39.434 50.67 39.929 ;
     RECT  43.488 39.857 44.154 40.019 ;
     RECT  45 38.777 48.942 40.135 ;
     RECT  0.108 39.317 0.234 40.171 ;
     RECT  1.08 38.281 37.854 40.171 ;
     RECT  50.652 39.929 50.67 40.199 ;
     RECT  0.108 40.171 37.854 40.781 ;
     RECT  44.136 40.019 44.154 40.829 ;
     RECT  0.252 40.781 37.854 40.877 ;
     RECT  44.928 40.135 48.942 40.945 ;
     RECT  44.424 40.945 48.942 41.021 ;
     RECT  0.252 40.877 0.342 41.165 ;
     RECT  45 41.021 48.942 41.549 ;
     RECT  0.252 41.165 0.27 41.707 ;
     RECT  0.108 41.707 0.27 41.989 ;
     RECT  1.08 40.877 37.854 41.989 ;
     RECT  45.468 41.549 48.942 43.025 ;
     RECT  0.108 41.989 37.854 43.085 ;
     RECT  45.504 43.025 48.942 43.673 ;
     RECT  0.108 43.085 0.342 44.141 ;
     RECT  0.108 44.141 0.27 45.067 ;
     RECT  0.108 45.067 0.342 45.197 ;
     RECT  0.216 45.197 0.27 45.245 ;
     RECT  0.216 45.245 0.234 45.689 ;
     RECT  0.144 46.267 0.162 46.555 ;
     RECT  0.144 46.555 0.234 46.733 ;
     RECT  40.215 37.859 40.497 46.741 ;
     RECT  0.144 46.733 0.198 47.308 ;
     RECT  0.108 47.308 0.198 47.453 ;
     RECT  0.108 47.453 0.162 47.501 ;
     RECT  40.215 46.741 40.554 47.615 ;
     RECT  38.772 47.563 38.79 47.693 ;
     RECT  40.215 47.615 40.497 48.139 ;
     RECT  1.08 43.085 37.854 48.433 ;
     RECT  39.672 48.139 40.497 48.763 ;
     RECT  39.348 48.763 40.497 48.973 ;
     RECT  0.144 47.501 0.162 49.051 ;
     RECT  0.144 49.051 0.198 49.099 ;
     RECT  0.108 49.099 0.198 49.126 ;
     RECT  1.08 48.433 37.998 49.351 ;
     RECT  0.108 49.126 0.342 49.517 ;
     RECT  0.108 49.517 0.234 49.565 ;
     RECT  0.108 49.565 0.198 50.009 ;
     RECT  38.952 48.973 40.497 50.011 ;
     RECT  41.328 38.741 41.814 50.011 ;
     RECT  0.144 50.009 0.198 50.045 ;
     RECT  38.952 50.011 41.814 51.061 ;
     RECT  0.144 50.045 0.162 51.511 ;
     RECT  0.108 51.511 0.198 51.629 ;
     RECT  0.18 51.629 0.198 51.677 ;
     RECT  0.216 52.075 0.342 52.205 ;
     RECT  0.216 52.205 0.234 52.397 ;
     RECT  0.144 52.507 0.198 52.681 ;
     RECT  0.108 52.681 0.198 53.117 ;
     RECT  0.108 53.117 0.126 53.165 ;
     RECT  0.144 54.139 0.162 54.331 ;
     RECT  0.144 54.331 0.234 54.413 ;
     RECT  1.08 49.351 38.178 54.913 ;
     RECT  0.54 54.913 38.178 55.339 ;
     RECT  0.144 55.339 38.178 55.516 ;
     RECT  38.952 51.061 42.03 55.561 ;
     RECT  0.108 55.516 38.178 55.661 ;
     RECT  0.18 55.661 38.178 55.709 ;
     RECT  38.952 55.561 42.174 55.805 ;
     RECT  38.952 55.805 41.814 56.299 ;
     RECT  0.432 55.709 38.178 56.827 ;
     RECT  0.144 56.827 38.178 57.001 ;
     RECT  0.108 57.001 38.178 57.451 ;
     RECT  38.916 56.299 41.814 57.451 ;
     RECT  0.108 57.451 41.814 57.488 ;
     RECT  0.432 57.488 41.814 57.581 ;
     RECT  0.468 57.581 41.814 58.349 ;
     RECT  0.144 58.459 0.198 59.083 ;
     RECT  0.108 59.083 0.198 59.809 ;
     RECT  1.08 58.349 41.814 59.809 ;
     RECT  0.108 59.809 41.814 62.189 ;
     RECT  0.18 62.189 41.814 62.237 ;
     RECT  0.288 62.237 41.814 62.971 ;
     RECT  0.216 62.971 41.814 63.211 ;
     RECT  0.18 63.211 41.814 63.355 ;
     RECT  45.504 43.673 48.906 63.595 ;
     RECT  0.144 63.355 41.814 64.075 ;
     RECT  0.108 64.075 41.814 66.361 ;
     RECT  0.036 66.361 41.814 67.163 ;
     RECT  0.108 67.163 41.814 69.965 ;
     RECT  0.108 69.965 0.342 70.349 ;
     RECT  0.108 70.349 0.234 70.445 ;
     RECT  0.216 70.445 0.234 70.541 ;
     RECT  1.08 69.965 41.814 71.179 ;
     RECT  0.144 71.221 0.162 71.581 ;
     RECT  45.504 63.595 48.978 71.761 ;
     RECT  0.108 71.581 0.162 72.139 ;
     RECT  1.044 71.179 41.814 72.139 ;
     RECT  45.504 71.761 49.014 72.185 ;
     RECT  0.108 72.139 41.814 74.093 ;
     RECT  0.216 74.093 41.814 74.285 ;
     RECT  0.396 74.285 41.814 75.361 ;
     RECT  0.108 75.361 41.814 76.397 ;
     RECT  0.54 76.397 41.814 76.649 ;
     RECT  0.54 76.649 41.562 77.227 ;
     RECT  0.324 77.227 41.562 77.357 ;
     RECT  0.54 77.357 41.562 77.657 ;
     RECT  1.116 77.657 41.562 77.927 ;
     RECT  1.188 77.927 41.562 78.269 ;
     RECT  1.188 78.269 40.806 79.439 ;
     RECT  1.404 79.439 40.806 79.781 ;
     RECT  43.596 62.545 43.614 80.221 ;
     RECT  1.44 79.781 40.806 80.357 ;
     RECT  1.728 80.357 40.806 80.519 ;
     RECT  45.615 72.185 49.014 81.877 ;
     RECT  45.615 81.877 49.41 82.957 ;
     RECT  2.268 80.519 40.806 84.451 ;
     RECT  41.544 78.269 41.562 84.451 ;
     RECT  43.596 80.221 44.154 84.613 ;
     RECT  45.288 82.957 49.41 84.613 ;
     RECT  2.268 84.451 41.562 86.639 ;
     RECT  2.376 86.639 41.562 87.149 ;
     RECT  2.415 87.149 41.562 88.051 ;
     RECT  2.304 88.051 41.562 92.911 ;
     RECT  2.304 92.911 41.886 94.603 ;
     RECT  43.596 84.613 49.41 95.071 ;
     RECT  43.056 95.071 49.41 95.251 ;
     RECT  42.768 95.251 49.41 95.369 ;
     RECT  43.056 95.369 49.41 95.521 ;
     RECT  43.056 95.521 50.058 95.819 ;
     RECT  44.136 95.819 50.058 95.909 ;
     RECT  2.268 94.603 41.886 96.061 ;
     RECT  1.8 96.061 41.886 96.269 ;
     RECT  2.304 96.269 41.886 96.317 ;
     RECT  2.34 96.317 41.886 96.601 ;
     RECT  45.615 95.909 50.058 96.691 ;
     RECT  45.615 96.691 50.31 96.871 ;
     RECT  2.34 96.601 42.246 97.141 ;
     RECT  43.056 95.819 43.074 97.141 ;
     RECT  45.615 96.871 50.814 97.411 ;
     RECT  2.34 97.141 43.074 97.681 ;
     RECT  45.615 97.411 51.174 98.041 ;
     RECT  2.304 97.681 43.074 98.045 ;
     RECT  2.376 98.045 43.074 98.149 ;
     RECT  44.136 95.909 44.802 98.149 ;
     RECT  45.615 98.041 51.246 98.311 ;
     RECT  45.615 98.311 51.354 98.536 ;
     RECT  2.376 98.149 44.802 98.669 ;
     RECT  45.615 98.536 51.462 98.669 ;
     RECT  45.615 98.669 51.39 98.861 ;
     RECT  14.364 98.669 44.802 99.031 ;
     RECT  45.615 98.861 51.318 99.031 ;
     RECT  14.364 99.031 51.318 99.149 ;
     RECT  2.376 98.669 13.59 99.197 ;
     RECT  17.1 99.149 51.318 99.197 ;
     RECT  14.364 99.149 16.362 99.599 ;
     RECT  4.104 99.197 5.886 99.677 ;
     RECT  2.376 99.197 3.33 99.725 ;
     RECT  14.4 99.599 16.362 99.725 ;
     RECT  15.264 99.725 16.362 99.773 ;
     RECT  17.1 99.197 51.246 100.031 ;
     RECT  6.66 99.197 13.59 100.171 ;
     RECT  26.244 100.031 51.246 100.265 ;
     RECT  4.14 99.677 5.886 100.349 ;
     RECT  6.66 100.171 13.626 100.397 ;
     RECT  17.1 100.031 25.434 100.877 ;
     RECT  4.356 100.349 5.886 100.925 ;
     RECT  6.66 100.397 13.59 100.925 ;
     RECT  14.4 99.725 14.418 100.925 ;
     RECT  31.356 100.265 51.246 100.925 ;
     RECT  21.456 100.877 25.434 100.973 ;
     RECT  2.415 99.725 2.934 100.997 ;
     RECT  4.5 100.925 5.886 101.213 ;
     RECT  9.18 100.925 13.59 101.405 ;
     RECT  33.876 100.925 51.246 101.405 ;
     RECT  2.556 100.997 2.934 101.453 ;
     RECT  17.1 100.877 20.718 101.501 ;
     RECT  26.244 100.265 30.51 101.501 ;
     RECT  31.356 100.925 33.102 101.501 ;
     RECT  33.876 101.405 45.054 101.501 ;
     RECT  6.66 100.925 8.406 102.029 ;
     RECT  15.264 99.773 16.254 102.029 ;
     RECT  2.556 101.453 2.574 102.077 ;
     RECT  5.22 101.213 5.886 102.077 ;
     RECT  6.66 102.029 6.678 102.077 ;
     RECT  15.264 102.029 15.75 102.077 ;
     RECT  21.78 100.973 25.434 102.077 ;
     RECT  26.244 101.501 27.81 102.125 ;
     RECT  35.136 101.501 44.658 102.173 ;
     RECT  9.18 101.405 12.582 102.317 ;
     RECT  31.356 101.501 32.706 102.509 ;
     RECT  5.22 102.077 5.238 102.605 ;
     RECT  7.956 102.029 7.974 102.605 ;
     RECT  9.18 102.317 11.322 102.605 ;
     RECT  12.276 102.317 12.582 102.605 ;
     RECT  15.264 102.077 15.714 102.605 ;
     RECT  17.748 101.501 20.718 102.605 ;
     RECT  21.78 102.077 23.598 102.605 ;
     RECT  31.356 102.509 31.698 102.605 ;
     RECT  32.436 102.509 32.706 102.605 ;
     RECT  35.136 102.173 43.254 102.605 ;
     RECT  9.18 102.605 10.134 102.653 ;
     RECT  12.276 102.605 12.294 102.653 ;
     RECT  17.748 102.605 19.854 102.653 ;
     RECT  23.472 102.605 23.598 102.653 ;
     RECT  26.424 102.125 27.81 102.653 ;
     RECT  28.584 101.501 30.51 102.653 ;
     RECT  35.136 102.605 40.59 102.653 ;
     RECT  41.508 102.605 42.21 102.653 ;
     RECT  44.028 102.173 44.658 102.653 ;
     RECT  45.936 101.405 51.246 102.653 ;
     RECT  23.58 102.653 23.598 102.701 ;
     RECT  35.244 102.653 35.262 102.701 ;
     RECT  36.54 102.653 40.05 102.701 ;
     RECT  43.236 102.605 43.254 102.701 ;
     RECT  36.54 102.701 37.53 102.749 ;
     RECT  38.376 102.701 40.05 102.749 ;
     RECT  44.028 102.653 44.154 102.749 ;
     RECT  24.336 102.077 25.038 103.085 ;
     RECT  44.028 102.749 44.046 103.483 ;
     RECT  26.748 102.653 27.558 103.517 ;
     RECT  38.376 102.749 39.906 103.517 ;
     RECT  45.936 102.653 49.014 103.517 ;
     RECT  49.788 102.653 51.246 103.517 ;
     RECT  9.18 102.653 9.45 103.565 ;
     RECT  13.572 101.405 13.59 103.565 ;
     RECT  15.3 102.605 15.714 103.565 ;
     RECT  17.748 102.653 18.414 103.565 ;
     RECT  19.836 102.653 19.854 103.565 ;
     RECT  21.78 102.605 22.734 103.565 ;
     RECT  24.876 103.085 25.038 103.565 ;
     RECT  26.748 103.517 26.766 103.565 ;
     RECT  27.54 103.517 27.558 103.565 ;
     RECT  28.584 102.653 30.006 103.565 ;
     RECT  31.356 102.605 31.374 103.565 ;
     RECT  32.688 102.605 32.706 103.565 ;
     RECT  33.876 101.501 34.326 103.565 ;
     RECT  36.828 102.749 37.53 103.565 ;
     RECT  38.376 103.517 39.546 103.565 ;
     RECT  41.508 102.653 41.742 103.565 ;
     RECT  43.92 103.483 44.046 103.565 ;
     RECT  45.936 103.517 47.574 103.565 ;
     RECT  48.312 103.517 48.942 103.565 ;
     RECT  49.788 103.517 51.174 103.565 ;
     RECT  41.508 103.565 41.526 103.613 ;
     RECT  43.92 103.565 43.938 103.613 ;
    LAYER M4 ;
     RECT  0.805 7.44 0.997 7.464 ;
     RECT  0.901 13.104 1.093 13.128 ;
     RECT  1.169 18.24 1.253 18.264 ;
     RECT  0.997 7.44 1.381 7.656 ;
     RECT  0.709 9.12 1.381 9.144 ;
     RECT  1.285 15.408 1.477 15.432 ;
     RECT  1.381 96 1.573 96.024 ;
     RECT  1.573 96 1.669 96.312 ;
     RECT  1.477 15.408 1.745 15.528 ;
     RECT  1.477 98.016 1.861 98.04 ;
     RECT  1.861 98.016 2.053 98.664 ;
     RECT  1.745 15.408 2.149 16.008 ;
     RECT  2.005 17.184 2.149 17.208 ;
     RECT  2.053 98.016 2.149 99.192 ;
     RECT  2.149 15.408 2.197 17.208 ;
     RECT  0.06 26.928 2.221 77.544 ;
     RECT  2.197 15.408 2.245 17.4 ;
     RECT  1.669 95.184 2.245 96.312 ;
     RECT  2.005 0.144 2.29 0.168 ;
     RECT  2.29 0.096 2.293 0.168 ;
     RECT  2.285 11.232 2.293 11.256 ;
     RECT  2.149 98.016 2.293 99.72 ;
     RECT  1.381 7.44 2.408 9.144 ;
     RECT  2.293 10.896 2.408 11.256 ;
     RECT  1.093 13.104 2.408 13.176 ;
     RECT  2.245 14.88 2.408 17.4 ;
     RECT  2.293 18.816 2.408 18.84 ;
     RECT  2.221 26.928 2.408 77.88 ;
     RECT  2.365 87.12 2.408 87.144 ;
     RECT  2.245 94.512 2.408 96.312 ;
     RECT  2.293 97.824 2.408 99.72 ;
     RECT  2.341 101.424 2.408 101.448 ;
     RECT  2.293 0.096 2.413 0.264 ;
     RECT  2.413 0.144 2.533 0.264 ;
     RECT  2.293 103.488 2.533 103.512 ;
     RECT  2.408 2.148 2.545 101.448 ;
     RECT  2.533 103.248 2.629 103.512 ;
     RECT  2.545 2.148 2.677 102.072 ;
     RECT  2.677 1.92 2.704 102.072 ;
     RECT  2.704 101.376 2.771 102.072 ;
     RECT  2.704 1.92 2.801 2.04 ;
     RECT  2.704 12 2.801 17.352 ;
     RECT  2.704 10.848 2.837 10.968 ;
     RECT  2.704 88.32 2.837 91.848 ;
     RECT  2.704 97.488 2.837 100.008 ;
     RECT  2.771 101.376 2.837 101.448 ;
     RECT  2.533 0.144 2.867 0.6 ;
     RECT  2.837 97.728 2.867 100.008 ;
     RECT  2.629 103.152 2.867 103.512 ;
     RECT  2.867 97.728 2.873 99.912 ;
     RECT  2.873 97.728 2.905 99.768 ;
     RECT  2.801 1.92 2.909 1.944 ;
     RECT  2.704 3.936 2.909 4.056 ;
     RECT  2.704 7.44 2.915 8.472 ;
     RECT  2.801 16.56 2.915 17.352 ;
     RECT  2.915 7.44 2.945 8.04 ;
     RECT  2.837 101.424 2.945 101.448 ;
     RECT  2.909 3.984 2.981 4.008 ;
     RECT  2.945 7.44 2.981 7.944 ;
     RECT  2.981 7.44 3.011 7.752 ;
     RECT  2.801 12 3.011 15.576 ;
     RECT  3.011 12 3.161 14.856 ;
     RECT  3.161 12 3.233 14.328 ;
     RECT  2.704 85.584 3.269 87.144 ;
     RECT  2.837 88.32 3.341 90.312 ;
     RECT  2.704 28.176 3.347 83.256 ;
     RECT  3.269 85.584 3.347 85.608 ;
     RECT  3.269 86.64 3.377 87.144 ;
     RECT  3.347 28.176 3.413 82.728 ;
     RECT  2.905 97.728 3.413 99.72 ;
     RECT  2.867 0.576 3.521 0.6 ;
     RECT  3.341 88.32 3.521 88.968 ;
     RECT  3.413 97.728 3.521 98.616 ;
     RECT  2.704 18.816 3.665 19.416 ;
     RECT  2.704 25.104 3.665 25.128 ;
     RECT  3.413 28.176 3.733 30.408 ;
     RECT  3.665 18.816 3.737 18.84 ;
     RECT  2.704 93.456 3.737 93.48 ;
     RECT  2.704 95.664 3.781 95.736 ;
     RECT  3.733 27.312 3.817 30.408 ;
     RECT  2.837 10.848 3.877 10.92 ;
     RECT  3.233 12 3.877 12.024 ;
     RECT  3.781 95.664 3.973 96.312 ;
     RECT  3.521 97.728 3.973 98.568 ;
     RECT  3.521 88.32 4.013 88.44 ;
     RECT  3.973 95.664 4.025 98.568 ;
     RECT  2.704 9.696 4.057 9.72 ;
     RECT  3.877 10.848 4.057 12.024 ;
     RECT  3.413 75.792 4.061 82.728 ;
     RECT  3.781 5.472 4.069 5.496 ;
     RECT  3.413 99.648 4.129 99.72 ;
     RECT  4.069 100.896 4.129 100.92 ;
     RECT  4.129 99.648 4.133 100.92 ;
     RECT  4.069 5.136 4.169 5.496 ;
     RECT  2.915 17.328 4.169 17.352 ;
     RECT  3.413 31.536 4.169 74.76 ;
     RECT  4.169 5.472 4.193 5.496 ;
     RECT  4.061 75.792 4.205 82.68 ;
     RECT  4.025 95.664 4.205 95.736 ;
     RECT  3.011 7.44 4.261 7.464 ;
     RECT  4.133 100.32 4.261 100.92 ;
     RECT  4.193 5.472 4.277 5.688 ;
     RECT  3.949 84.384 4.309 84.408 ;
     RECT  4.057 9.696 4.313 12.024 ;
     RECT  4.313 11.424 4.357 12.024 ;
     RECT  4.261 100.32 4.403 101.208 ;
     RECT  4.169 40.368 4.453 74.76 ;
     RECT  4.205 75.792 4.453 81.528 ;
     RECT  4.013 87.792 4.453 88.44 ;
     RECT  4.412 2.256 4.489 2.28 ;
     RECT  3.817 28.224 4.489 30.408 ;
     RECT  4.169 31.536 4.489 39.288 ;
     RECT  4.489 28.224 4.529 39.288 ;
     RECT  4.403 100.896 4.529 101.208 ;
     RECT  3.341 90.288 4.549 90.312 ;
     RECT  3.377 86.64 4.556 86.664 ;
     RECT  4.453 87.744 4.556 88.44 ;
     RECT  4.025 97.152 4.565 98.568 ;
     RECT  3.949 3.984 4.597 4.008 ;
     RECT  4.313 9.696 4.601 10.296 ;
     RECT  3.233 13.104 4.601 14.328 ;
     RECT  4.565 97.488 4.601 98.568 ;
     RECT  4.549 90.288 4.645 90.6 ;
     RECT  4.597 3.936 4.691 4.008 ;
     RECT  4.205 95.664 4.709 95.688 ;
     RECT  4.669 98.592 4.753 98.616 ;
     RECT  4.489 2.256 4.813 2.856 ;
     RECT  4.205 82.608 4.817 82.68 ;
     RECT  4.556 86.64 4.817 88.44 ;
     RECT  4.817 86.64 4.853 88.344 ;
     RECT  4.813 2.208 4.885 2.856 ;
     RECT  4.853 86.64 4.885 87.816 ;
     RECT  4.645 89.52 4.889 90.6 ;
     RECT  4.309 84.336 4.933 84.408 ;
     RECT  4.789 85.488 4.933 85.512 ;
     RECT  4.933 84.336 4.961 85.512 ;
     RECT  4.261 7.44 5.029 7.704 ;
     RECT  4.357 11.424 5.069 12.072 ;
     RECT  4.885 1.68 5.137 2.856 ;
     RECT  4.529 30.384 5.137 39.288 ;
     RECT  4.453 40.368 5.137 81.528 ;
     RECT  4.885 86.592 5.141 87.816 ;
     RECT  5.137 30.384 5.249 81.528 ;
     RECT  5.125 102.576 5.249 102.6 ;
     RECT  4.601 97.488 5.267 97.512 ;
     RECT  5.141 86.64 5.315 87.192 ;
     RECT  4.277 5.472 5.317 5.496 ;
     RECT  5.249 58.416 5.317 81.528 ;
     RECT  4.817 82.608 5.317 82.632 ;
     RECT  4.889 89.52 5.357 90.552 ;
     RECT  4.529 28.416 5.363 29.112 ;
     RECT  4.529 100.896 5.363 100.92 ;
     RECT  5.357 89.52 5.393 90.456 ;
     RECT  5.317 26.208 5.401 26.232 ;
     RECT  5.249 30.384 5.429 57.432 ;
     RECT  5.363 28.752 5.465 29.112 ;
     RECT  5.317 58.416 5.501 82.632 ;
     RECT  5.029 7.104 5.525 7.704 ;
     RECT  5.465 28.944 5.537 29.112 ;
     RECT  4.601 13.68 5.557 14.328 ;
     RECT  5.413 91.728 5.597 91.752 ;
     RECT  5.315 86.64 5.603 86.664 ;
     RECT  5.525 7.104 5.609 7.992 ;
     RECT  5.537 28.992 5.609 29.112 ;
     RECT  4.961 84.336 5.609 85.032 ;
     RECT  5.501 58.416 5.617 82.056 ;
     RECT  5.137 1.104 5.651 2.856 ;
     RECT  5.597 91.632 5.681 91.752 ;
     RECT  5.509 103.488 5.699 103.512 ;
     RECT  5.641 95.184 5.701 95.208 ;
     RECT  5.429 30.528 5.717 57.432 ;
     RECT  5.681 91.728 5.717 91.752 ;
     RECT  5.557 13.68 5.753 14.904 ;
     RECT  5.717 30.528 5.753 57.096 ;
     RECT  5.617 58.416 5.789 82.008 ;
     RECT  5.753 13.728 5.825 14.904 ;
     RECT  5.609 28.992 5.825 29.016 ;
     RECT  5.713 101.472 5.857 101.496 ;
     RECT  5.069 11.424 5.861 11.544 ;
     RECT  5.821 26.784 5.933 26.808 ;
     RECT  5.857 101.472 5.939 102.072 ;
     RECT  5.885 0.096 6.149 0.12 ;
     RECT  5.789 58.416 6.185 80.904 ;
     RECT  5.797 99.168 6.221 99.192 ;
     RECT  5.713 2.88 6.227 2.904 ;
     RECT  5.393 89.52 6.257 90.072 ;
     RECT  6.185 58.416 6.277 80.328 ;
     RECT  5.651 1.104 6.289 1.704 ;
     RECT  4.601 10.272 6.293 10.296 ;
     RECT  6.277 94.032 6.373 94.056 ;
     RECT  6.085 92.304 6.437 92.328 ;
     RECT  5.989 8.784 6.469 8.808 ;
     RECT  6.277 58.128 6.473 80.328 ;
     RECT  6.229 17.328 6.505 17.352 ;
     RECT  6.473 58.128 6.617 78.696 ;
     RECT  6.572 27.216 6.659 27.24 ;
     RECT  6.289 0.384 6.685 1.704 ;
     RECT  5.939 102.048 6.707 102.072 ;
     RECT  6.257 89.52 6.725 89.544 ;
     RECT  6.469 8.784 6.761 9.72 ;
     RECT  6.565 90.576 6.833 90.6 ;
     RECT  5.609 84.96 7.141 85.032 ;
     RECT  5.701 95.136 7.141 95.208 ;
     RECT  6.473 79.728 7.225 80.328 ;
     RECT  6.793 29.04 7.333 29.064 ;
     RECT  7.045 97.44 7.405 97.464 ;
     RECT  6.373 93.504 7.621 94.056 ;
     RECT  7.141 95.04 7.621 95.208 ;
     RECT  7.573 103.488 7.669 103.512 ;
     RECT  6.685 0.384 7.808 2.04 ;
     RECT  4.691 3.984 7.808 4.008 ;
     RECT  5.317 5.472 7.808 6.024 ;
     RECT  5.609 7.104 7.808 7.704 ;
     RECT  6.761 8.784 7.808 8.808 ;
     RECT  5.861 11.424 7.808 11.448 ;
     RECT  5.825 14.112 7.808 14.904 ;
     RECT  6.805 16.272 7.808 16.296 ;
     RECT  6.505 17.328 7.808 18.216 ;
     RECT  7.333 29.04 7.808 29.352 ;
     RECT  5.753 30.672 7.808 57.096 ;
     RECT  6.617 58.128 7.808 78.648 ;
     RECT  7.225 79.728 7.808 80.952 ;
     RECT  7.649 83.232 7.808 83.256 ;
     RECT  7.141 84.96 7.808 85.512 ;
     RECT  7.525 89.472 7.808 89.496 ;
     RECT  7.621 93.504 7.808 95.208 ;
     RECT  6.001 96.336 7.808 96.36 ;
     RECT  7.405 97.44 7.808 98.136 ;
     RECT  6.937 99.744 7.808 99.768 ;
     RECT  7.237 102 7.901 102.024 ;
     RECT  7.669 103.392 7.901 103.512 ;
     RECT  7.901 102 7.985 103.512 ;
     RECT  7.808 0.384 8 100.992 ;
     RECT  7.985 102 8 102.024 ;
     RECT  8 0.384 8.104 102.024 ;
     RECT  8.104 0.384 8.197 2.328 ;
     RECT  8.104 37.872 8.201 39.288 ;
     RECT  8.104 75.696 8.273 80.328 ;
     RECT  8.104 94.08 8.291 94.68 ;
     RECT  7.985 103.44 8.291 103.512 ;
     RECT  8.201 37.968 8.309 39.288 ;
     RECT  8.104 84.96 8.387 85.08 ;
     RECT  8.291 103.488 8.387 103.512 ;
     RECT  8.104 102 8.417 102.024 ;
     RECT  8.104 29.088 8.453 36.312 ;
     RECT  8.387 84.96 8.483 84.984 ;
     RECT  8.273 75.696 8.525 78.648 ;
     RECT  8.104 86.592 8.561 86.616 ;
     RECT  8.291 94.656 8.627 94.68 ;
     RECT  8.453 29.184 8.669 36.312 ;
     RECT  8.104 100.896 8.723 100.92 ;
     RECT  8.104 91.152 8.885 91.752 ;
     RECT  8.104 14.112 8.921 14.28 ;
     RECT  8.104 89.472 8.921 89.496 ;
     RECT  8.104 87.744 8.957 88.344 ;
     RECT  8.104 26.784 9.029 26.808 ;
     RECT  8.104 40.608 9.029 74.712 ;
     RECT  8.669 29.184 9.101 36.072 ;
     RECT  8.957 87.792 9.107 88.344 ;
     RECT  8.309 38.208 9.137 39.288 ;
     RECT  8.197 0.096 9.173 2.328 ;
     RECT  8.104 22.752 9.203 22.776 ;
     RECT  8.104 16.272 9.253 17.352 ;
     RECT  8.104 92.88 9.253 92.904 ;
     RECT  8.273 80.112 9.349 80.328 ;
     RECT  8.525 75.696 9.389 78.168 ;
     RECT  8.104 5.472 9.425 6.024 ;
     RECT  8.885 91.152 9.445 91.176 ;
     RECT  9.125 103.536 9.461 103.56 ;
     RECT  9.107 88.32 9.596 88.344 ;
     RECT  9.445 91.104 9.605 91.176 ;
     RECT  8.104 27.936 9.635 27.96 ;
     RECT  9.029 40.704 9.641 74.712 ;
     RECT  9.173 0.528 9.673 2.328 ;
     RECT  9.641 73.68 9.681 74.712 ;
     RECT  9.389 75.696 9.681 78.12 ;
     RECT  9.596 88.32 9.683 88.968 ;
     RECT  8.104 7.104 9.713 7.704 ;
     RECT  9.641 40.704 9.721 72.408 ;
     RECT  9.101 29.376 9.74 36.072 ;
     RECT  9.253 15.984 9.829 17.352 ;
     RECT  9.721 70.416 9.857 72.408 ;
     RECT  9.74 29.376 9.875 36.504 ;
     RECT  9.875 29.952 9.997 36.504 ;
     RECT  9.917 13.104 10.001 13.128 ;
     RECT  9.961 102.096 10.069 102.12 ;
     RECT  10.069 102.048 10.105 102.12 ;
     RECT  9.681 73.68 10.109 78.12 ;
     RECT  9.829 96.816 10.177 96.84 ;
     RECT  10.177 96.816 10.181 96.936 ;
     RECT  9.733 85.488 10.253 85.512 ;
     RECT  10.105 102.048 10.259 102.648 ;
     RECT  9.713 7.104 10.289 7.128 ;
     RECT  9.605 91.104 10.289 91.128 ;
     RECT  9.829 15.408 10.307 17.352 ;
     RECT  9.997 29.952 10.355 36.84 ;
     RECT  10.109 75.264 10.357 78.12 ;
     RECT  10.307 15.408 10.397 16.008 ;
     RECT  9.137 38.4 10.433 39.288 ;
     RECT  9.425 5.472 10.501 5.496 ;
     RECT  9.253 92.304 10.501 92.904 ;
     RECT  10.501 92.304 10.541 93.48 ;
     RECT  9.349 80.112 10.547 80.568 ;
     RECT  10.181 96.912 10.643 96.936 ;
     RECT  10.357 75.264 10.681 78.6 ;
     RECT  10.681 75.264 10.757 78.936 ;
     RECT  8.921 14.112 10.789 14.136 ;
     RECT  10.433 38.4 10.789 39.096 ;
     RECT  9.721 40.704 10.789 69.384 ;
     RECT  9.857 70.416 10.789 70.728 ;
     RECT  9.857 71.76 10.789 72.408 ;
     RECT  10.109 73.68 10.789 74.088 ;
     RECT  8.104 8.784 10.825 9.768 ;
     RECT  8.104 10.848 10.825 10.872 ;
     RECT  10.547 80.304 10.825 80.568 ;
     RECT  9.683 88.32 10.829 88.824 ;
     RECT  10.829 88.32 10.865 88.344 ;
     RECT  10.501 5.472 10.885 5.736 ;
     RECT  10.825 8.784 10.937 10.872 ;
     RECT  10.789 71.76 10.973 74.088 ;
     RECT  10.937 8.784 11.009 10.296 ;
     RECT  11.009 8.784 11.041 9.144 ;
     RECT  10.397 15.408 11.081 15.432 ;
     RECT  8.104 25.68 11.123 25.704 ;
     RECT  10.885 5.136 11.125 5.736 ;
     RECT  10.789 40.704 11.149 70.728 ;
     RECT  10.757 75.552 11.261 78.936 ;
     RECT  11.009 10.272 11.267 10.296 ;
     RECT  10.541 92.304 11.269 92.328 ;
     RECT  11.125 5.088 11.333 5.736 ;
     RECT  10.541 93.36 11.365 93.48 ;
     RECT  10.885 90.048 11.405 90.072 ;
     RECT  10.355 30.288 11.42 36.84 ;
     RECT  11.42 30 11.437 36.84 ;
     RECT  10.259 102.048 11.461 102.6 ;
     RECT  11.333 5.088 11.473 5.16 ;
     RECT  11.269 91.776 11.537 92.328 ;
     RECT  11.365 93.36 11.605 94.056 ;
     RECT  11.537 91.152 11.621 92.328 ;
     RECT  11.621 91.344 11.653 92.328 ;
     RECT  11.605 93.36 11.653 94.344 ;
     RECT  9.673 0.528 11.699 2.856 ;
     RECT  11.461 28.464 11.729 28.488 ;
     RECT  11.461 102 11.765 102.6 ;
     RECT  11.149 40.704 11.829 71.256 ;
     RECT  11.149 26.784 11.873 26.808 ;
     RECT  11.473 4.56 11.891 5.16 ;
     RECT  11.041 8.544 11.941 9.144 ;
     RECT  11.891 5.136 12.017 5.16 ;
     RECT  11.941 8.256 12.017 9.144 ;
     RECT  11.437 29.808 12.017 36.84 ;
     RECT  11.653 91.344 12.017 94.344 ;
     RECT  11.829 58.464 12.053 71.256 ;
     RECT  11.765 102.288 12.083 102.6 ;
     RECT  10.973 72.384 12.229 74.088 ;
     RECT  11.261 75.696 12.229 78.936 ;
     RECT  12.083 102.576 12.265 102.6 ;
     RECT  11.829 40.704 12.277 57.432 ;
     RECT  12.229 75.696 12.325 79.224 ;
     RECT  10.825 80.304 12.325 80.952 ;
     RECT  11.701 97.824 12.421 97.848 ;
     RECT  12.017 8.256 12.517 8.808 ;
     RECT  12.265 102.576 12.593 102.648 ;
     RECT  12.325 5.184 12.709 5.208 ;
     RECT  10.789 38.208 12.733 39.096 ;
     RECT  12.277 40.128 12.913 57.432 ;
     RECT  12.053 58.464 12.913 70.728 ;
     RECT  11.699 0.528 12.947 2.568 ;
     RECT  12.229 99.696 12.949 99.72 ;
     RECT  12.017 29.808 12.985 30.6 ;
     RECT  12.017 31.68 12.985 36.84 ;
     RECT  10.789 13.68 13.085 14.136 ;
     RECT  12.985 29.808 13.201 36.84 ;
     RECT  12.947 2.016 13.208 2.568 ;
     RECT  12.709 5.184 13.208 5.256 ;
     RECT  12.553 6.24 13.208 6.264 ;
     RECT  12.517 8.16 13.208 8.808 ;
     RECT  12.805 10.272 13.208 10.296 ;
     RECT  11.269 12.528 13.208 12.552 ;
     RECT  13.085 13.68 13.208 14.28 ;
     RECT  12.437 15.984 13.208 16.008 ;
     RECT  10.307 17.328 13.208 17.352 ;
     RECT  12.613 27.312 13.208 27.336 ;
     RECT  13.201 29.808 13.208 36.936 ;
     RECT  12.733 38.208 13.208 39.144 ;
     RECT  12.913 40.128 13.208 70.728 ;
     RECT  12.229 71.808 13.208 74.088 ;
     RECT  12.325 75.696 13.208 80.952 ;
     RECT  12.301 82.608 13.208 82.632 ;
     RECT  12.661 83.616 13.208 83.64 ;
     RECT  12.901 90.048 13.208 90.072 ;
     RECT  12.017 91.344 13.208 92.04 ;
     RECT  12.017 93.408 13.208 94.344 ;
     RECT  12.421 97.44 13.208 97.848 ;
     RECT  12.949 98.88 13.208 99.72 ;
     RECT  13.129 101.376 13.208 101.4 ;
     RECT  13.093 103.344 13.235 103.56 ;
     RECT  12.947 0.528 13.373 0.6 ;
     RECT  13.373 0.144 13.417 0.6 ;
     RECT  13.208 2.016 13.504 101.4 ;
     RECT  13.504 100.176 13.523 101.4 ;
     RECT  13.504 31.68 13.529 80.568 ;
     RECT  13.504 2.016 13.565 2.568 ;
     RECT  13.417 0.048 13.601 0.6 ;
     RECT  13.504 29.808 13.601 30.264 ;
     RECT  13.235 103.392 13.601 103.56 ;
     RECT  13.601 103.392 13.619 103.512 ;
     RECT  13.523 100.176 13.66 100.92 ;
     RECT  13.601 0.048 13.667 0.216 ;
     RECT  13.619 103.392 13.667 103.416 ;
     RECT  13.529 31.68 13.673 78.216 ;
     RECT  13.529 79.44 13.673 80.568 ;
     RECT  13.504 91.344 13.673 91.56 ;
     RECT  13.66 100.368 13.681 100.92 ;
     RECT  13.504 92.928 13.853 94.344 ;
     RECT  13.673 48.768 14.033 78.216 ;
     RECT  13.504 11.952 14.099 12.792 ;
     RECT  14.033 72.144 14.213 78.216 ;
     RECT  14.149 1.728 14.249 1.752 ;
     RECT  13.601 29.904 14.291 30.264 ;
     RECT  14.099 12.528 14.321 12.792 ;
     RECT  14.213 72.144 14.321 77.832 ;
     RECT  13.504 10.848 14.533 10.872 ;
     RECT  13.504 97.776 14.579 99.192 ;
     RECT  13.504 17.088 14.629 17.352 ;
     RECT  13.673 31.68 14.641 47.736 ;
     RECT  14.033 48.768 14.641 70.728 ;
     RECT  13.853 92.928 14.675 92.952 ;
     RECT  13.504 19.824 14.725 20.616 ;
     RECT  13.504 83.616 14.725 84.216 ;
     RECT  13.504 8.016 14.821 8.52 ;
     RECT  14.579 98.88 14.821 99.192 ;
     RECT  14.725 19.392 14.825 20.616 ;
     RECT  14.629 17.088 14.861 17.64 ;
     RECT  14.821 7.44 14.908 8.52 ;
     RECT  14.533 10.272 14.917 10.872 ;
     RECT  14.821 98.88 14.969 99.72 ;
     RECT  14.321 12.768 14.993 12.792 ;
     RECT  13.504 5.232 15.005 5.256 ;
     RECT  14.321 72.144 15.011 76.632 ;
     RECT  14.725 83.616 15.041 84.312 ;
     RECT  13.681 100.896 15.059 100.92 ;
     RECT  15.011 75.696 15.077 76.632 ;
     RECT  14.908 7.968 15.113 8.52 ;
     RECT  14.641 31.68 15.145 70.728 ;
     RECT  15.077 75.696 15.155 76.536 ;
     RECT  14.917 10.272 15.185 10.92 ;
     RECT  15.109 103.536 15.205 103.56 ;
     RECT  15.113 8.016 15.251 8.52 ;
     RECT  15.185 10.896 15.289 10.92 ;
     RECT  15.155 75.84 15.293 76.536 ;
     RECT  14.969 98.88 15.347 99.192 ;
     RECT  15.289 10.896 15.395 11.4 ;
     RECT  13.504 15.984 15.437 16.008 ;
     RECT  14.993 12.768 15.493 13.704 ;
     RECT  13.853 94.32 15.493 94.344 ;
     RECT  15.293 76.032 15.509 76.536 ;
     RECT  13.504 26.544 15.541 26.568 ;
     RECT  14.861 17.328 15.589 17.64 ;
     RECT  14.917 87.168 15.617 87.192 ;
     RECT  15.205 102.576 15.721 103.56 ;
     RECT  15.721 102.048 15.725 103.56 ;
     RECT  15.469 100.32 15.731 100.872 ;
     RECT  15.749 18.816 15.833 18.84 ;
     RECT  15.493 12.528 15.877 13.704 ;
     RECT  14.857 14.832 15.877 14.856 ;
     RECT  15.541 26.544 15.877 26.76 ;
     RECT  15.725 102.048 15.923 102.648 ;
     RECT  15.145 31.68 15.925 70.968 ;
     RECT  15.731 100.848 15.941 100.872 ;
     RECT  15.589 17.328 15.965 17.688 ;
     RECT  15.877 12.528 15.977 14.856 ;
     RECT  15.932 96.336 16.019 96.36 ;
     RECT  15.877 25.872 16.045 26.76 ;
     RECT  15.965 16.56 16.049 17.688 ;
     RECT  15.923 102.048 16.069 102.072 ;
     RECT  15.925 30.96 16.081 70.968 ;
     RECT  15.011 72.144 16.081 74.088 ;
     RECT  16.081 30.96 16.085 74.088 ;
     RECT  16.069 1.728 16.165 1.752 ;
     RECT  15.493 93.456 16.165 94.344 ;
     RECT  15.349 21.648 16.193 21.672 ;
     RECT  16.165 93.408 16.253 94.344 ;
     RECT  15.251 8.256 16.261 8.52 ;
     RECT  16.165 1.728 16.316 1.8 ;
     RECT  15.347 98.88 16.333 98.904 ;
     RECT  16.085 30.96 16.337 71.208 ;
     RECT  16.316 1.728 16.403 2.28 ;
     RECT  16.069 102 16.403 102.072 ;
     RECT  16.337 30.96 16.405 49.752 ;
     RECT  16.045 25.872 16.409 26.856 ;
     RECT  15.977 14.256 16.477 14.856 ;
     RECT  16.261 7.44 16.481 8.52 ;
     RECT  15.781 89.472 16.481 89.496 ;
     RECT  16.403 1.728 16.517 1.752 ;
     RECT  16.433 87.744 16.517 87.768 ;
     RECT  16.337 50.736 16.547 71.208 ;
     RECT  14.579 97.776 16.585 97.848 ;
     RECT  16.333 98.88 16.585 99.768 ;
     RECT  16.481 7.872 16.589 8.52 ;
     RECT  14.291 29.904 16.597 29.928 ;
     RECT  16.405 30.912 16.597 49.752 ;
     RECT  16.585 97.776 16.787 99.768 ;
     RECT  16.253 93.408 16.805 94.584 ;
     RECT  16.549 86.352 16.837 86.376 ;
     RECT  16.547 51.216 16.913 71.208 ;
     RECT  16.805 94.32 16.913 94.584 ;
     RECT  16.913 51.216 17.057 68.904 ;
     RECT  16.837 86.352 17.093 86.616 ;
     RECT  16.589 7.968 17.125 8.52 ;
     RECT  15.977 12.528 17.309 12.792 ;
     RECT  16.477 14.256 17.341 15.432 ;
     RECT  17.125 95.712 17.345 95.736 ;
     RECT  16.409 25.872 17.365 26.568 ;
     RECT  16.085 72.192 17.411 74.088 ;
     RECT  15.395 10.896 17.525 10.92 ;
     RECT  17.341 14.256 17.555 15.48 ;
     RECT  16.787 97.776 17.555 99.192 ;
     RECT  17.125 7.968 17.557 9.144 ;
     RECT  16.049 17.328 17.557 17.688 ;
     RECT  17.317 79.248 17.561 79.272 ;
     RECT  15.041 83.616 17.605 83.64 ;
     RECT  16.597 29.904 17.629 49.752 ;
     RECT  17.057 51.216 17.629 68.712 ;
     RECT  16.913 70.128 17.773 71.208 ;
     RECT  17.411 72.192 17.773 72.216 ;
     RECT  17.089 101.472 17.881 101.496 ;
     RECT  17.605 83.616 17.989 84.36 ;
     RECT  13.667 0.048 18.097 0.072 ;
     RECT  17.557 16.56 18.133 17.688 ;
     RECT  18.229 6.96 18.325 6.984 ;
     RECT  17.693 103.536 18.349 103.56 ;
     RECT  18.349 102.624 18.425 103.56 ;
     RECT  17.881 101.472 18.469 101.544 ;
     RECT  18.241 3.408 18.608 3.432 ;
     RECT  18.325 6.864 18.608 6.984 ;
     RECT  17.557 7.968 18.608 9.672 ;
     RECT  17.309 12.768 18.608 12.792 ;
     RECT  17.555 14.256 18.608 15.432 ;
     RECT  18.133 16.56 18.608 18.312 ;
     RECT  14.825 19.824 18.608 20.616 ;
     RECT  17.365 25.008 18.608 26.568 ;
     RECT  13.504 28.176 18.608 28.2 ;
     RECT  17.629 29.904 18.608 68.712 ;
     RECT  17.773 70.128 18.608 72.216 ;
     RECT  17.411 73.344 18.608 74.088 ;
     RECT  15.509 76.032 18.608 76.056 ;
     RECT  14.321 77.808 18.608 77.832 ;
     RECT  13.673 80.304 18.608 80.568 ;
     RECT  18.469 81.888 18.608 81.912 ;
     RECT  17.989 83.232 18.608 84.36 ;
     RECT  17.317 86.016 18.608 86.04 ;
     RECT  16.981 88.368 18.608 88.392 ;
     RECT  16.913 94.32 18.608 94.344 ;
     RECT  17.555 97.776 18.608 98.904 ;
     RECT  18.469 101.376 18.608 101.544 ;
     RECT  18.608 2.148 18.712 101.544 ;
     RECT  18.712 2.418 18.853 101.544 ;
     RECT  18.425 102.624 18.853 103.464 ;
     RECT  18.853 2.418 18.904 103.464 ;
     RECT  18.904 8.544 18.965 9.576 ;
     RECT  18.904 83.232 18.965 84.36 ;
     RECT  18.965 8.544 19.001 9.144 ;
     RECT  18.904 86.016 19.001 86.04 ;
     RECT  19.001 8.592 19.091 9.144 ;
     RECT  19.091 9.12 19.153 9.144 ;
     RECT  18.904 91.2 19.187 91.224 ;
     RECT  18.904 17.328 19.217 17.688 ;
     RECT  18.904 77.808 19.289 78.696 ;
     RECT  18.965 83.28 19.325 84.36 ;
     RECT  18.904 101.424 19.397 103.464 ;
     RECT  19.397 101.472 19.525 103.464 ;
     RECT  18.097 0.048 19.613 0.84 ;
     RECT  18.904 19.824 19.757 20.616 ;
     RECT  19.525 101.472 19.763 103.56 ;
     RECT  19.763 102.048 19.859 103.56 ;
     RECT  19.859 102.576 19.865 103.56 ;
     RECT  19.613 0.432 19.897 0.84 ;
     RECT  18.904 98.88 19.933 99.192 ;
     RECT  18.904 24.528 19.955 25.032 ;
     RECT  19.868 84.768 19.955 84.792 ;
     RECT  20.005 25.104 20.041 25.128 ;
     RECT  18.904 26.544 20.077 26.568 ;
     RECT  20.041 25.104 20.147 25.224 ;
     RECT  18.904 70.128 20.197 72.216 ;
     RECT  20.077 26.544 20.221 26.808 ;
     RECT  19.933 98.88 20.243 99.288 ;
     RECT  18.904 28.512 20.333 28.536 ;
     RECT  18.904 29.904 20.369 68.712 ;
     RECT  20.147 25.2 20.435 25.224 ;
     RECT  19.897 0.432 20.437 1.416 ;
     RECT  20.293 100.272 20.477 100.296 ;
     RECT  20.389 91.152 20.513 91.176 ;
     RECT  20.245 15.648 20.581 15.672 ;
     RECT  20.437 0.432 20.627 1.704 ;
     RECT  20.485 86.016 20.677 86.04 ;
     RECT  20.221 26.208 20.689 26.808 ;
     RECT  19.865 102.576 20.729 102.6 ;
     RECT  20.369 29.904 20.771 36.936 ;
     RECT  18.904 80.304 20.773 80.568 ;
     RECT  19.325 83.28 20.773 83.784 ;
     RECT  19.217 17.328 20.801 17.352 ;
     RECT  20.771 30.048 20.801 36.936 ;
     RECT  20.197 69.744 20.801 72.216 ;
     RECT  19.757 20.592 20.837 20.616 ;
     RECT  20.485 13.632 20.869 13.656 ;
     RECT  20.689 26.208 21.011 27.384 ;
     RECT  20.869 13.104 21.017 13.656 ;
     RECT  20.801 30.768 21.089 36.936 ;
     RECT  20.041 88.944 21.107 88.968 ;
     RECT  20.773 83.232 21.125 83.784 ;
     RECT  20.369 38.4 21.161 39.624 ;
     RECT  20.369 40.8 21.161 68.712 ;
     RECT  21.017 13.104 21.203 13.128 ;
     RECT  20.627 0.432 21.221 1.608 ;
     RECT  20.677 85.488 21.233 86.04 ;
     RECT  21.089 34.896 21.337 36.936 ;
     RECT  20.245 78.912 21.349 78.936 ;
     RECT  21.089 30.768 21.377 33.432 ;
     RECT  21.161 40.8 21.449 43.416 ;
     RECT  21.233 85.488 21.485 85.512 ;
     RECT  20.581 15.36 21.493 15.672 ;
     RECT  21.377 30.768 21.521 33.144 ;
     RECT  20.545 100.848 21.593 100.968 ;
     RECT  21.125 83.232 21.665 83.64 ;
     RECT  21.541 88.896 21.665 88.92 ;
     RECT  21.521 30.768 21.673 33.096 ;
     RECT  21.593 100.896 21.683 100.968 ;
     RECT  21.337 34.896 21.701 37.176 ;
     RECT  21.011 26.208 21.731 26.808 ;
     RECT  20.801 70.128 21.731 72.216 ;
     RECT  21.301 28.464 21.733 28.488 ;
     RECT  21.349 86.592 21.773 86.616 ;
     RECT  21.725 103.536 21.829 103.56 ;
     RECT  21.733 27.936 21.845 28.488 ;
     RECT  21.349 78.912 21.877 79.272 ;
     RECT  20.773 80.304 21.877 81.192 ;
     RECT  21.221 0.096 21.949 1.608 ;
     RECT  21.877 78.912 21.989 81.192 ;
     RECT  21.829 102.576 22.021 103.56 ;
     RECT  21.673 30.816 22.133 33.096 ;
     RECT  21.925 91.152 22.133 91.176 ;
     RECT  21.845 27.936 22.163 27.96 ;
     RECT  21.449 40.896 22.165 43.416 ;
     RECT  21.161 44.4 22.165 68.712 ;
     RECT  18.904 97.776 22.201 97.848 ;
     RECT  20.243 98.88 22.201 98.904 ;
     RECT  21.701 35.232 22.241 37.176 ;
     RECT  21.161 38.4 22.268 39.528 ;
     RECT  22.268 38.16 22.355 39.528 ;
     RECT  21.683 100.944 22.451 100.968 ;
     RECT  21.949 0.096 22.489 1.992 ;
     RECT  22.201 97.776 22.501 98.904 ;
     RECT  21.493 15.36 22.597 15.96 ;
     RECT  22.309 27.36 22.739 27.384 ;
     RECT  22.021 102.528 22.745 103.56 ;
     RECT  22.241 35.232 22.781 36.984 ;
     RECT  22.501 97.44 22.781 98.904 ;
     RECT  22.355 38.4 22.813 39.528 ;
     RECT  22.165 40.896 22.813 68.712 ;
     RECT  22.133 31.248 22.835 33.096 ;
     RECT  22.781 97.776 22.835 98.904 ;
     RECT  22.813 38.4 22.889 68.712 ;
     RECT  22.889 38.4 22.931 43.896 ;
     RECT  18.904 76.032 22.933 76.056 ;
     RECT  22.931 41.232 22.961 43.896 ;
     RECT  22.813 101.472 22.981 101.544 ;
     RECT  22.745 102.528 22.981 102.696 ;
     RECT  22.741 28.944 23.065 28.968 ;
     RECT  22.781 35.232 23.065 36.936 ;
     RECT  22.129 26.16 23.209 26.184 ;
     RECT  23.065 28.944 23.209 29.592 ;
     RECT  21.989 78.912 23.221 79.272 ;
     RECT  21.989 80.304 23.221 81.192 ;
     RECT  22.597 85.92 23.237 85.944 ;
     RECT  23.209 26.16 23.317 26.232 ;
     RECT  23.209 28.944 23.605 30.072 ;
     RECT  22.835 98.88 23.605 98.904 ;
     RECT  23.221 78.912 23.653 81.192 ;
     RECT  23.317 26.16 23.893 26.808 ;
     RECT  22.961 41.232 23.893 43.128 ;
     RECT  22.981 101.472 23.941 102.696 ;
     RECT  22.489 0.096 24.008 2.568 ;
     RECT  22.597 15.216 24.008 15.96 ;
     RECT  21.481 18.192 24.008 18.216 ;
     RECT  23.137 21.504 24.008 21.528 ;
     RECT  23.893 26.064 24.008 26.808 ;
     RECT  23.605 28.176 24.008 30.072 ;
     RECT  22.835 31.248 24.008 32.328 ;
     RECT  23.065 35.184 24.008 36.936 ;
     RECT  22.931 38.4 24.008 39.528 ;
     RECT  23.893 40.608 24.008 43.128 ;
     RECT  22.889 45.024 24.008 68.712 ;
     RECT  21.731 70.848 24.008 72.216 ;
     RECT  18.904 73.248 24.008 74.088 ;
     RECT  22.933 76.032 24.008 76.392 ;
     RECT  19.289 77.808 24.008 77.832 ;
     RECT  23.653 78.912 24.008 82.008 ;
     RECT  21.665 83.616 24.008 83.64 ;
     RECT  23.173 84.912 24.008 84.936 ;
     RECT  23.237 85.92 24.008 86.04 ;
     RECT  23.365 87.168 24.008 87.192 ;
     RECT  18.904 94.32 24.008 94.344 ;
     RECT  22.835 97.776 24.008 97.848 ;
     RECT  23.605 98.88 24.008 99.288 ;
     RECT  23.941 101.472 24.008 103.416 ;
     RECT  24.008 0.096 24.083 103.416 ;
     RECT  24.083 0.096 24.304 101.496 ;
     RECT  24.304 35.136 24.365 68.712 ;
     RECT  24.304 28.176 24.401 30.072 ;
     RECT  24.304 15.216 24.419 15.528 ;
     RECT  24.365 38.4 24.419 68.712 ;
     RECT  24.304 80.256 24.419 82.632 ;
     RECT  24.419 15.216 24.563 15.48 ;
     RECT  24.419 80.304 24.581 82.632 ;
     RECT  24.083 102.624 24.659 103.416 ;
     RECT  24.419 41.232 24.851 68.712 ;
     RECT  24.304 0.096 24.869 3.144 ;
     RECT  24.851 41.232 24.941 63.672 ;
     RECT  24.304 101.472 24.947 101.496 ;
     RECT  24.304 97.44 24.977 100.344 ;
     RECT  24.304 78.912 25.049 78.936 ;
     RECT  24.709 103.536 25.049 103.56 ;
     RECT  24.581 82.608 25.085 82.632 ;
     RECT  24.563 15.456 25.139 15.48 ;
     RECT  24.941 61.968 25.193 63.672 ;
     RECT  24.941 41.232 25.229 60.888 ;
     RECT  25.229 41.904 25.265 60.888 ;
     RECT  24.304 31.872 25.301 33.048 ;
     RECT  24.304 76.032 25.325 76.056 ;
     RECT  24.304 25.968 25.331 26.808 ;
     RECT  24.977 97.776 25.373 100.344 ;
     RECT  25.325 76.032 25.409 76.392 ;
     RECT  24.304 21.504 25.441 21.528 ;
     RECT  24.304 22.752 25.441 22.776 ;
     RECT  24.365 35.136 25.445 37.224 ;
     RECT  24.304 83.616 25.477 83.64 ;
     RECT  25.373 98.88 25.619 100.344 ;
     RECT  24.304 85.488 25.697 85.512 ;
     RECT  24.869 0.24 25.715 3.144 ;
     RECT  25.441 21.504 25.811 22.776 ;
     RECT  25.477 83.616 25.841 83.784 ;
     RECT  25.841 83.616 25.861 83.688 ;
     RECT  24.304 73.248 25.955 74.088 ;
     RECT  25.765 84.912 25.957 84.936 ;
     RECT  25.265 41.904 25.985 60.648 ;
     RECT  25.957 84.864 26.053 84.936 ;
     RECT  24.419 38.4 26.125 39.624 ;
     RECT  26.053 84.816 26.149 84.936 ;
     RECT  25.811 21.936 26.195 22.776 ;
     RECT  26.125 38.4 26.197 40.2 ;
     RECT  25.405 102.048 26.233 102.072 ;
     RECT  25.861 82.656 26.237 83.688 ;
     RECT  26.197 38.4 26.243 40.632 ;
     RECT  25.301 32.256 26.269 33.048 ;
     RECT  25.715 0.24 26.291 1.704 ;
     RECT  26.149 84.768 26.308 84.936 ;
     RECT  26.269 32.064 26.353 33.048 ;
     RECT  26.233 102.048 26.413 102.12 ;
     RECT  26.308 84.72 26.417 84.936 ;
     RECT  25.409 76.032 26.437 76.056 ;
     RECT  26.413 102.048 26.533 102.648 ;
     RECT  26.353 32.688 26.557 33.048 ;
     RECT  26.437 76.032 26.561 76.392 ;
     RECT  25.955 73.248 26.579 73.368 ;
     RECT  26.417 84.72 26.597 84.888 ;
     RECT  26.533 101.424 26.693 102.648 ;
     RECT  26.693 101.424 26.741 103.56 ;
     RECT  24.401 28.176 26.773 29.976 ;
     RECT  26.291 0.24 26.777 1.416 ;
     RECT  26.773 28.176 26.993 30.84 ;
     RECT  26.557 32.688 27.061 33.384 ;
     RECT  25.445 35.136 27.061 37.032 ;
     RECT  26.741 101.472 27.101 103.56 ;
     RECT  24.851 64.704 27.107 68.712 ;
     RECT  24.304 77.808 27.109 77.832 ;
     RECT  27.061 32.688 27.137 37.032 ;
     RECT  25.985 41.904 27.137 60.12 ;
     RECT  26.237 82.656 27.137 83.64 ;
     RECT  26.597 84.72 27.137 84.744 ;
     RECT  27.137 36.864 27.317 37.032 ;
     RECT  26.243 38.4 27.349 39.624 ;
     RECT  26.243 40.608 27.349 40.632 ;
     RECT  27.137 42.048 27.349 60.12 ;
     RECT  27.137 32.688 27.353 35.352 ;
     RECT  27.269 79.2 27.353 79.224 ;
     RECT  27.317 36.864 27.389 36.984 ;
     RECT  27.349 38.4 27.389 40.632 ;
     RECT  27.109 77.712 27.493 77.832 ;
     RECT  27.349 42.048 27.637 60.456 ;
     RECT  25.193 62.496 27.673 63.672 ;
     RECT  27.493 77.712 27.685 78.024 ;
     RECT  26.777 0.336 27.709 1.416 ;
     RECT  27.637 42.048 27.713 60.936 ;
     RECT  27.101 102.624 27.827 103.56 ;
     RECT  27.709 0.336 27.889 1.464 ;
     RECT  27.389 36.96 27.965 36.984 ;
     RECT  25.373 97.776 27.973 97.848 ;
     RECT  25.619 98.88 27.973 99.768 ;
     RECT  24.581 80.304 28.069 81.192 ;
     RECT  27.973 97.776 28.145 99.768 ;
     RECT  27.101 101.472 28.165 101.544 ;
     RECT  26.561 76.032 28.211 76.056 ;
     RECT  27.353 32.736 28.253 35.352 ;
     RECT  28.145 98.88 28.307 99.768 ;
     RECT  27.889 0.096 28.321 1.464 ;
     RECT  27.685 77.712 28.325 79.08 ;
     RECT  27.389 38.4 28.357 40.536 ;
     RECT  28.253 32.736 28.361 34.2 ;
     RECT  28.165 100.848 28.361 101.544 ;
     RECT  27.107 64.704 28.403 67.128 ;
     RECT  28.361 32.736 28.405 33.624 ;
     RECT  28.253 35.184 28.429 35.352 ;
     RECT  26.195 21.936 28.573 22.488 ;
     RECT  27.713 42.048 28.604 43.128 ;
     RECT  28.573 21.168 28.645 22.488 ;
     RECT  28.645 10.8 28.789 10.824 ;
     RECT  28.789 10.8 28.885 11.112 ;
     RECT  27.137 83.616 28.933 83.64 ;
     RECT  28.885 10.8 28.969 11.352 ;
     RECT  28.861 14.832 28.969 14.856 ;
     RECT  28.069 80.304 29.029 81.48 ;
     RECT  28.357 37.536 29.077 40.536 ;
     RECT  28.645 21.12 29.113 22.488 ;
     RECT  28.969 10.272 29.125 11.352 ;
     RECT  29.113 20.544 29.125 22.488 ;
     RECT  28.321 0.096 29.189 1.704 ;
     RECT  28.145 97.776 29.221 97.848 ;
     RECT  28.307 98.88 29.221 99.432 ;
     RECT  29.221 97.776 29.269 99.432 ;
     RECT  29.189 0.144 29.408 1.704 ;
     RECT  25.715 3.12 29.408 3.144 ;
     RECT  29.365 5.568 29.408 5.592 ;
     RECT  29.125 10.272 29.408 11.976 ;
     RECT  28.969 14.832 29.408 15.384 ;
     RECT  28.741 19.248 29.408 19.272 ;
     RECT  29.125 20.544 29.408 22.824 ;
     RECT  25.331 25.968 29.408 25.992 ;
     RECT  26.993 28.176 29.408 30.408 ;
     RECT  28.465 31.728 29.408 31.752 ;
     RECT  28.405 32.736 29.408 33.384 ;
     RECT  28.429 35.184 29.408 35.784 ;
     RECT  29.077 36.96 29.408 40.536 ;
     RECT  28.604 41.856 29.408 43.128 ;
     RECT  27.713 44.736 29.408 60.936 ;
     RECT  27.673 62.016 29.408 63.672 ;
     RECT  28.403 64.704 29.408 65.832 ;
     RECT  28.403 66.816 29.408 67.128 ;
     RECT  27.107 68.688 29.408 68.712 ;
     RECT  24.304 70.848 29.408 72.216 ;
     RECT  26.579 73.248 29.408 73.272 ;
     RECT  28.325 77.808 29.408 79.08 ;
     RECT  29.029 80.304 29.408 82.2 ;
     RECT  28.933 83.184 29.408 83.64 ;
     RECT  29.221 86.208 29.408 86.232 ;
     RECT  27.997 92.928 29.408 92.952 ;
     RECT  24.304 94.32 29.408 94.344 ;
     RECT  29.269 97.776 29.408 99.768 ;
     RECT  28.361 101.328 29.408 101.544 ;
     RECT  29.408 0.144 29.651 101.544 ;
     RECT  29.651 0.144 29.704 101.496 ;
     RECT  29.704 77.808 29.765 78.648 ;
     RECT  29.704 80.304 29.765 82.2 ;
     RECT  27.827 103.536 29.789 103.56 ;
     RECT  29.704 19.104 29.801 19.272 ;
     RECT  29.704 45.984 29.801 46.632 ;
     RECT  29.704 5.568 29.891 5.592 ;
     RECT  29.801 46.272 29.909 46.632 ;
     RECT  29.704 100.896 29.939 101.496 ;
     RECT  29.704 10.272 29.953 11.976 ;
     RECT  29.789 103.488 30.017 103.56 ;
     RECT  29.704 20.544 30.083 20.568 ;
     RECT  29.953 10.752 30.089 11.976 ;
     RECT  29.704 36.96 30.089 37.128 ;
     RECT  29.704 83.616 30.179 83.784 ;
     RECT  29.765 80.304 30.197 81.816 ;
     RECT  29.704 60.096 30.227 60.936 ;
     RECT  29.704 35.184 30.275 35.928 ;
     RECT  29.909 46.272 30.305 46.392 ;
     RECT  29.704 47.712 30.323 58.536 ;
     RECT  29.939 100.896 30.341 101.448 ;
     RECT  29.704 62.016 30.419 63.672 ;
     RECT  30.341 100.896 30.419 100.92 ;
     RECT  29.704 38.928 30.457 39.336 ;
     RECT  29.704 31.728 30.697 31.752 ;
     RECT  29.704 26.784 30.733 27.192 ;
     RECT  29.704 28.176 30.733 30.168 ;
     RECT  30.697 31.632 30.737 31.752 ;
     RECT  29.704 3.12 30.757 3.144 ;
     RECT  29.704 42.048 30.757 42.072 ;
     RECT  29.704 43.104 30.757 43.128 ;
     RECT  30.323 58.512 30.757 58.536 ;
     RECT  29.704 64.704 30.757 65.832 ;
     RECT  29.704 66.816 30.757 67.128 ;
     RECT  29.704 70.848 30.757 72.216 ;
     RECT  29.704 94.32 30.757 94.344 ;
     RECT  30.481 102.624 30.757 102.648 ;
     RECT  30.419 62.496 30.769 63.672 ;
     RECT  30.757 64.704 30.769 67.128 ;
     RECT  30.757 94.32 30.769 94.68 ;
     RECT  29.704 97.488 30.769 99.432 ;
     RECT  29.704 88.32 30.773 88.344 ;
     RECT  29.704 0.144 30.802 1.464 ;
     RECT  29.704 21.696 30.805 23.4 ;
     RECT  30.733 26.784 30.851 30.168 ;
     RECT  30.757 6.768 30.899 6.888 ;
     RECT  30.089 10.8 30.899 11.976 ;
     RECT  30.757 42.048 30.899 43.128 ;
     RECT  30.757 58.512 30.899 58.776 ;
     RECT  30.769 62.496 30.899 67.128 ;
     RECT  30.757 70.608 30.899 72.216 ;
     RECT  30.757 86.544 30.899 86.664 ;
     RECT  30.757 90.576 30.899 90.696 ;
     RECT  30.757 102.48 30.899 102.648 ;
     RECT  30.805 21.648 30.949 23.4 ;
     RECT  30.757 2.832 31.043 3.144 ;
     RECT  30.769 97.488 31.043 100.056 ;
     RECT  30.769 94.32 31.091 95.208 ;
     RECT  30.949 84.336 31.141 84.36 ;
     RECT  30.949 21.648 31.165 23.496 ;
     RECT  30.899 11.328 31.189 11.976 ;
     RECT  30.899 102.576 31.301 102.648 ;
     RECT  30.089 37.008 31.345 37.128 ;
     RECT  30.851 26.784 31.381 26.904 ;
     RECT  31.301 102.576 31.385 103.56 ;
     RECT  31.189 11.328 31.421 12.408 ;
     RECT  31.421 11.472 31.475 12.408 ;
     RECT  31.381 95.76 31.475 95.784 ;
     RECT  31.475 11.952 31.493 12.408 ;
     RECT  31.381 26.736 31.529 26.904 ;
     RECT  31.493 12 31.565 12.408 ;
     RECT  31.565 12 31.571 12.024 ;
     RECT  31.165 21.648 31.597 23.976 ;
     RECT  31.345 36.912 31.637 37.128 ;
     RECT  31.141 84.288 31.637 84.36 ;
     RECT  30.323 47.712 31.673 57.384 ;
     RECT  29.704 73.248 31.715 73.272 ;
     RECT  30.197 81.168 31.717 81.816 ;
     RECT  31.637 84.288 31.745 84.312 ;
     RECT  30.275 35.184 31.813 35.784 ;
     RECT  31.637 36.912 31.813 37.08 ;
     RECT  31.529 26.88 31.889 26.904 ;
     RECT  30.853 83.184 31.925 83.208 ;
     RECT  31.813 35.184 31.955 37.08 ;
     RECT  30.899 70.944 31.955 71.64 ;
     RECT  29.704 92.592 31.961 92.616 ;
     RECT  31.385 102.576 32.005 102.6 ;
     RECT  32.005 102 32.101 102.6 ;
     RECT  31.043 99.408 32.137 100.056 ;
     RECT  30.802 0.096 32.173 1.464 ;
     RECT  30.851 28.176 32.173 30.168 ;
     RECT  31.673 55.776 32.197 57.384 ;
     RECT  30.899 58.512 32.197 58.536 ;
     RECT  30.899 42.048 32.243 42.072 ;
     RECT  31.673 47.712 32.249 54.744 ;
     RECT  31.597 21.408 32.281 23.976 ;
     RECT  32.209 25.44 32.281 25.464 ;
     RECT  32.101 101.952 32.321 102.6 ;
     RECT  32.321 102.48 32.429 102.6 ;
     RECT  32.317 88.368 32.435 88.392 ;
     RECT  32.429 102.576 32.465 102.6 ;
     RECT  29.704 13.536 32.533 13.848 ;
     RECT  31.955 37.056 32.537 37.08 ;
     RECT  31.717 81.168 32.573 82.056 ;
     RECT  32.533 13.104 32.645 13.848 ;
     RECT  32.581 103.536 32.717 103.56 ;
     RECT  32.173 0.096 32.749 2.04 ;
     RECT  31.043 3.12 32.749 3.144 ;
     RECT  30.305 46.272 32.773 46.296 ;
     RECT  32.197 55.776 32.789 58.536 ;
     RECT  31.955 35.184 32.861 35.784 ;
     RECT  32.137 99.12 32.861 100.056 ;
     RECT  32.749 0.096 32.915 3.144 ;
     RECT  32.773 46.272 33.073 46.584 ;
     RECT  30.457 38.928 33.107 38.952 ;
     RECT  29.765 77.808 33.107 77.832 ;
     RECT  33.073 46.224 33.113 46.584 ;
     RECT  31.955 70.944 33.155 70.968 ;
     RECT  29.801 19.104 33.361 19.128 ;
     RECT  32.281 21.408 33.397 25.464 ;
     RECT  32.965 26.544 33.397 26.568 ;
     RECT  33.397 21.408 33.433 26.568 ;
     RECT  32.173 27.6 33.433 30.168 ;
     RECT  30.899 62.496 33.437 65.832 ;
     RECT  32.789 58.128 33.545 58.536 ;
     RECT  32.485 101.424 33.587 101.496 ;
     RECT  32.573 81.168 33.617 81.528 ;
     RECT  32.249 47.712 33.653 54.456 ;
     RECT  30.227 60.096 33.653 60.12 ;
     RECT  33.433 21.408 33.683 30.168 ;
     RECT  33.653 47.712 33.689 53.064 ;
     RECT  33.689 51.024 33.797 53.064 ;
     RECT  32.861 99.12 33.884 99.768 ;
     RECT  33.596 100.8 33.884 101.4 ;
     RECT  32.915 0.096 34.076 0.36 ;
     RECT  32.915 1.392 34.076 3.144 ;
     RECT  31.043 97.68 34.117 97.848 ;
     RECT  33.884 99.12 34.117 101.4 ;
     RECT  34.117 97.68 34.765 101.4 ;
     RECT  34.076 0.096 34.808 3.144 ;
     RECT  34.549 11.952 34.808 11.976 ;
     RECT  32.645 13.104 34.808 13.704 ;
     RECT  33.361 19.104 34.808 19.656 ;
     RECT  33.683 21.408 34.808 23.4 ;
     RECT  33.683 24.384 34.808 30.168 ;
     RECT  30.737 31.632 34.808 31.656 ;
     RECT  29.704 32.736 34.808 33.384 ;
     RECT  32.861 35.472 34.808 35.784 ;
     RECT  30.899 43.104 34.808 43.128 ;
     RECT  33.113 46.224 34.808 46.248 ;
     RECT  33.689 47.712 34.808 50.04 ;
     RECT  33.797 51.408 34.808 53.064 ;
     RECT  33.653 54.432 34.808 54.456 ;
     RECT  32.789 55.776 34.808 56.904 ;
     RECT  33.545 58.512 34.808 58.536 ;
     RECT  33.437 62.496 34.808 64.968 ;
     RECT  30.899 66.816 34.808 67.128 ;
     RECT  33.617 81.168 34.808 81.192 ;
     RECT  31.091 94.32 34.808 94.344 ;
     RECT  34.765 97.68 34.808 101.496 ;
     RECT  34.808 0.096 34.841 101.496 ;
     RECT  34.841 0.144 35.104 101.496 ;
     RECT  35.104 0.144 35.123 1.944 ;
     RECT  33.821 103.536 35.123 103.56 ;
     RECT  35.104 11.328 35.273 12.552 ;
     RECT  35.125 102.624 35.305 102.696 ;
     RECT  35.104 97.68 35.314 101.496 ;
     RECT  35.305 102.576 35.411 102.696 ;
     RECT  35.104 56.064 35.555 56.856 ;
     RECT  35.314 97.68 35.603 101.544 ;
     RECT  35.104 62.496 35.633 64.968 ;
     RECT  35.633 63.072 35.705 64.968 ;
     RECT  35.273 11.424 35.849 12.552 ;
     RECT  35.104 66.816 35.849 67.128 ;
     RECT  35.104 35.568 35.957 35.784 ;
     RECT  35.123 0.144 36.017 1.704 ;
     RECT  35.104 94.32 36.065 94.344 ;
     RECT  35.603 97.68 36.083 101.448 ;
     RECT  35.104 81.168 36.101 81.192 ;
     RECT  36.017 0.096 36.169 1.704 ;
     RECT  35.104 3.12 36.179 3.96 ;
     RECT  35.104 43.104 36.209 43.128 ;
     RECT  36.083 97.68 36.371 100.344 ;
     RECT  35.705 63.072 36.461 63.624 ;
     RECT  36.083 101.424 36.467 101.448 ;
     RECT  35.411 102.624 36.517 102.696 ;
     RECT  36.517 102.576 36.529 102.696 ;
     RECT  35.849 11.952 36.565 12.552 ;
     RECT  35.104 47.712 36.677 48.792 ;
     RECT  36.529 102.576 36.677 102.744 ;
     RECT  36.169 0.096 36.745 1.992 ;
     RECT  36.179 3.12 36.745 3.144 ;
     RECT  36.677 102.624 36.773 102.744 ;
     RECT  35.555 56.304 36.785 56.856 ;
     RECT  36.485 15.408 36.821 15.432 ;
     RECT  36.349 5.088 36.851 5.112 ;
     RECT  36.565 11.952 36.997 13.032 ;
     RECT  36.997 11.424 37.331 13.032 ;
     RECT  37.033 101.472 37.427 101.496 ;
     RECT  37.331 12 37.477 13.032 ;
     RECT  36.371 97.68 37.577 99.528 ;
     RECT  35.705 64.704 37.669 64.968 ;
     RECT  37.477 12.528 37.717 13.032 ;
     RECT  37.645 8.496 37.811 8.52 ;
     RECT  37.609 100.896 37.811 100.92 ;
     RECT  35.104 58.512 37.861 58.536 ;
     RECT  36.773 102.624 37.861 103.56 ;
     RECT  36.677 48.144 37.957 48.792 ;
     RECT  35.104 21.408 38.099 30.168 ;
     RECT  37.717 12.528 38.195 13.08 ;
     RECT  38.195 13.056 38.225 13.08 ;
     RECT  36.745 0.096 38.297 3.144 ;
     RECT  35.849 66.816 38.339 66.84 ;
     RECT  37.861 58.512 38.729 59.256 ;
     RECT  35.104 19.104 38.761 19.656 ;
     RECT  35.104 31.632 38.761 31.656 ;
     RECT  38.761 31.488 38.801 31.656 ;
     RECT  37.957 47.568 38.801 48.792 ;
     RECT  37.861 102.048 38.867 103.56 ;
     RECT  36.785 56.304 38.945 56.328 ;
     RECT  36.461 63.6 39.013 63.624 ;
     RECT  37.669 64.608 39.013 64.968 ;
     RECT  37.577 97.68 39.013 99.144 ;
     RECT  39.013 97.68 39.373 99.48 ;
     RECT  39.337 100.752 39.373 100.776 ;
     RECT  38.297 0.144 39.473 3.144 ;
     RECT  39.373 97.68 39.481 100.776 ;
     RECT  39.013 63.6 39.493 64.968 ;
     RECT  38.867 102.624 39.557 103.56 ;
     RECT  39.049 8.208 39.697 8.232 ;
     RECT  39.473 0.096 39.913 3.144 ;
     RECT  39.481 97.68 39.913 101.4 ;
     RECT  39.557 102.624 39.913 103.512 ;
     RECT  39.913 97.68 39.917 103.512 ;
     RECT  35.957 35.568 40.093 35.592 ;
     RECT  39.913 0.048 40.208 3.144 ;
     RECT  38.581 4.224 40.208 4.248 ;
     RECT  39.697 7.68 40.208 8.232 ;
     RECT  38.761 19.008 40.208 19.656 ;
     RECT  38.099 21.408 40.208 23.112 ;
     RECT  38.099 24.144 40.208 30.168 ;
     RECT  38.801 31.488 40.208 31.512 ;
     RECT  35.104 32.736 40.208 33.384 ;
     RECT  40.093 35.472 40.208 35.592 ;
     RECT  35.104 46.224 40.208 46.248 ;
     RECT  38.801 47.664 40.208 48.792 ;
     RECT  35.104 50.016 40.208 50.04 ;
     RECT  35.104 54.432 40.208 54.456 ;
     RECT  39.109 55.776 40.208 55.8 ;
     RECT  38.729 58.512 40.208 58.536 ;
     RECT  39.493 63.072 40.208 64.968 ;
     RECT  39.917 97.68 40.208 103.464 ;
     RECT  40.208 0.048 40.403 103.464 ;
     RECT  40.403 0.048 40.504 102.744 ;
     RECT  40.504 63.072 40.529 64.344 ;
     RECT  40.504 24.144 40.643 30.168 ;
     RECT  40.643 24.144 40.739 30.12 ;
     RECT  40.504 3.072 40.787 3.144 ;
     RECT  40.504 54.432 40.817 54.456 ;
     RECT  40.504 50.016 41.033 50.04 ;
     RECT  40.504 21.408 41.171 23.112 ;
     RECT  40.529 63.6 41.177 64.344 ;
     RECT  40.504 97.68 41.363 102.744 ;
     RECT  40.504 19.008 41.459 19.656 ;
     RECT  40.504 34.8 41.497 35.496 ;
     RECT  41.363 102.048 41.497 102.744 ;
     RECT  40.504 32.736 41.533 33.384 ;
     RECT  41.497 34.464 41.533 35.496 ;
     RECT  41.459 19.008 41.537 19.032 ;
     RECT  41.533 32.736 41.609 35.496 ;
     RECT  40.739 24.192 41.651 30.12 ;
     RECT  40.504 47.664 41.753 47.688 ;
     RECT  40.504 31.488 41.843 31.512 ;
     RECT  41.171 21.408 41.939 21.96 ;
     RECT  41.363 97.68 41.939 100.92 ;
     RECT  41.939 97.68 42.041 98.184 ;
     RECT  40.504 55.776 42.185 55.8 ;
     RECT  40.504 0.048 42.257 1.608 ;
     RECT  41.939 99.168 42.323 100.92 ;
     RECT  41.609 32.736 42.329 34.968 ;
     RECT  42.323 99.552 42.433 100.92 ;
     RECT  42.433 99.552 42.469 101.016 ;
     RECT  41.497 102.048 42.469 103.608 ;
     RECT  42.469 99.552 42.689 103.608 ;
     RECT  42.257 0.096 42.725 1.608 ;
     RECT  41.845 36.288 42.757 36.312 ;
     RECT  41.569 37.296 42.757 37.32 ;
     RECT  42.757 37.296 42.797 37.416 ;
     RECT  42.041 97.68 42.833 97.848 ;
     RECT  42.329 32.736 42.865 34.776 ;
     RECT  42.757 36.24 43.081 36.312 ;
     RECT  42.725 0.144 43.187 1.608 ;
     RECT  41.651 25.968 43.475 30.12 ;
     RECT  42.865 32.208 43.549 34.776 ;
     RECT  40.787 3.072 43.571 3.096 ;
     RECT  43.549 32.208 43.657 34.968 ;
     RECT  43.081 36.048 43.657 36.312 ;
     RECT  41.651 24.192 43.667 24.984 ;
     RECT  43.187 0.144 43.763 1.512 ;
     RECT  42.797 37.392 43.868 37.416 ;
     RECT  43.657 32.208 43.909 36.312 ;
     RECT  43.909 31.536 43.949 36.312 ;
     RECT  42.689 99.744 43.949 103.608 ;
     RECT  43.475 27.072 43.955 30.12 ;
     RECT  43.868 37.392 43.955 37.848 ;
     RECT  40.504 46.224 43.955 46.248 ;
     RECT  43.949 31.536 44.017 36.264 ;
     RECT  44.017 31.104 44.057 36.264 ;
     RECT  43.949 99.744 44.057 103.56 ;
     RECT  43.955 28.752 44.197 30.12 ;
     RECT  44.057 31.104 44.197 36.12 ;
     RECT  44.197 28.752 44.237 36.12 ;
     RECT  40.504 4.224 44.243 4.248 ;
     RECT  44.237 28.752 44.339 31.128 ;
     RECT  42.833 97.824 44.485 97.848 ;
     RECT  44.057 99.744 44.485 102.744 ;
     RECT  43.955 27.072 44.627 27.672 ;
     RECT  43.763 0.144 45.061 1.464 ;
     RECT  45.061 0.144 45.169 2.232 ;
     RECT  44.339 30.576 45.277 31.128 ;
     RECT  44.237 32.208 45.277 36.12 ;
     RECT  44.485 99.168 45.299 102.744 ;
     RECT  40.504 7.68 45.493 8.232 ;
     RECT  45.452 39.6 45.493 39.624 ;
     RECT  45.277 30.576 45.565 36.12 ;
     RECT  43.955 37.392 45.565 37.416 ;
     RECT  45.169 0.144 45.608 2.28 ;
     RECT  45.493 7.68 45.608 9 ;
     RECT  45.485 16.56 45.608 16.584 ;
     RECT  41.939 21.936 45.608 21.96 ;
     RECT  41.171 23.088 45.608 23.112 ;
     RECT  43.667 24.192 45.608 24.792 ;
     RECT  43.475 25.968 45.608 25.992 ;
     RECT  44.627 27.072 45.608 27.624 ;
     RECT  44.339 28.752 45.608 29.352 ;
     RECT  45.565 30.576 45.608 37.416 ;
     RECT  45.493 38.784 45.608 39.624 ;
     RECT  44.413 40.992 45.608 41.016 ;
     RECT  41.177 63.6 45.608 63.624 ;
     RECT  44.485 97.824 45.608 98.088 ;
     RECT  45.299 99.168 45.608 101.496 ;
     RECT  45.608 0.144 45.637 101.496 ;
     RECT  45.637 0.096 45.779 101.496 ;
     RECT  45.299 102.672 45.829 102.744 ;
     RECT  45.779 0.096 45.904 101.262 ;
     RECT  45.904 38.688 46.001 38.712 ;
     RECT  45.904 99.744 46.019 99.768 ;
     RECT  45.904 31.488 46.037 34.824 ;
     RECT  45.904 36 46.037 37.656 ;
     RECT  45.904 0.096 46.067 2.28 ;
     RECT  46.037 36 46.115 37.608 ;
     RECT  46.037 31.488 46.145 31.512 ;
     RECT  46.115 36.048 46.145 37.608 ;
     RECT  45.904 25.968 46.181 27.624 ;
     RECT  46.037 32.496 46.181 34.824 ;
     RECT  45.829 102.672 46.268 103.56 ;
     RECT  46.067 1.392 46.451 2.28 ;
     RECT  45.904 70.992 46.469 71.544 ;
     RECT  45.904 72.912 46.613 72.936 ;
     RECT  46.268 102.624 46.643 103.56 ;
     RECT  46.181 33.072 46.721 34.824 ;
     RECT  46.451 1.392 46.757 1.752 ;
     RECT  46.721 33.36 47.045 34.824 ;
     RECT  46.145 36.048 47.045 37.32 ;
     RECT  45.904 15.408 47.075 17.112 ;
     RECT  47.075 15.984 47.123 17.112 ;
     RECT  47.045 36.48 47.149 37.32 ;
     RECT  47.123 15.984 47.219 16.584 ;
     RECT  45.904 97.824 47.261 97.848 ;
     RECT  47.219 15.984 47.297 16.104 ;
     RECT  47.297 15.984 47.315 16.008 ;
     RECT  46.469 71.232 47.333 71.544 ;
     RECT  47.149 36.48 47.549 38.136 ;
     RECT  45.904 7.44 47.581 9.096 ;
     RECT  47.549 36.48 47.585 37.32 ;
     RECT  46.643 103.44 47.645 103.56 ;
     RECT  47.365 74.592 47.749 74.616 ;
     RECT  47.581 7.44 47.795 9.144 ;
     RECT  47.795 7.44 47.801 8.568 ;
     RECT  47.801 7.488 47.891 8.568 ;
     RECT  47.045 34.8 47.909 34.824 ;
     RECT  47.749 74.064 47.909 74.616 ;
     RECT  47.645 103.392 47.977 103.56 ;
     RECT  47.891 7.968 47.987 8.568 ;
     RECT  47.333 71.232 48.125 71.256 ;
     RECT  47.909 74.592 48.197 74.616 ;
     RECT  47.987 7.968 48.205 8.04 ;
     RECT  48.205 7.968 48.277 7.992 ;
     RECT  47.941 100.944 48.337 100.968 ;
     RECT  45.904 28.752 48.371 29.352 ;
     RECT  48.325 72.336 48.421 72.36 ;
     RECT  47.045 33.36 48.467 33.384 ;
     RECT  48.421 72.048 48.557 72.36 ;
     RECT  48.133 73.488 48.557 73.512 ;
     RECT  48.371 28.752 48.563 29.112 ;
     RECT  46.181 27.072 48.659 27.624 ;
     RECT  48.557 72.048 48.701 72.072 ;
     RECT  45.904 21.936 48.755 21.96 ;
     RECT  47.977 102.624 48.805 103.56 ;
     RECT  48.659 27.072 48.851 27.096 ;
     RECT  48.805 102.096 48.913 103.56 ;
     RECT  46.181 25.968 48.947 25.992 ;
     RECT  45.904 63.6 48.989 63.624 ;
     RECT  48.409 35.904 49.025 35.928 ;
     RECT  48.563 29.088 49.043 29.112 ;
     RECT  48.956 33.024 49.043 33.144 ;
     RECT  48.337 100.944 49.057 101.016 ;
     RECT  47.585 37.296 49.139 37.32 ;
     RECT  45.904 24.192 49.235 24.792 ;
     RECT  46.067 0.096 49.273 0.36 ;
     RECT  46.757 1.392 49.273 1.416 ;
     RECT  49.235 24.192 49.331 24.216 ;
     RECT  49.273 0.096 49.427 1.416 ;
     RECT  49.057 100.896 49.553 101.016 ;
     RECT  49.553 100.272 49.637 101.016 ;
     RECT  49.637 100.848 49.741 101.016 ;
     RECT  48.913 102.048 49.741 103.56 ;
     RECT  49.741 100.848 49.753 103.56 ;
     RECT  49.427 0.096 50.387 1.128 ;
     RECT  49.753 101.424 50.483 103.56 ;
     RECT  50.713 98.64 50.749 98.664 ;
     RECT  50.483 102.048 50.963 103.56 ;
     RECT  50.387 0.096 50.969 0.168 ;
     RECT  50.969 0.096 51.085 0.12 ;
     RECT  50.963 102.624 51.185 103.56 ;
     RECT  51.185 102.624 51.257 103.512 ;
     RECT  50.749 98.64 51.289 98.76 ;
     RECT  50.317 99.744 51.289 99.768 ;
     RECT  51.289 98.64 51.539 99.768 ;
     RECT  51.257 102.624 51.635 102.648 ;
     RECT  51.539 98.64 51.827 98.856 ;
     RECT  51.827 98.64 51.923 98.664 ;
    LAYER M5 ;
     RECT  0.72 0.016 51.048 0.131 ;
     RECT  0.72 0.131 50.952 0.179 ;
     RECT  0.72 0.179 50.376 0.947 ;
     RECT  0.72 0.947 27.336 1.091 ;
     RECT  27.312 1.091 27.336 1.139 ;
     RECT  28.368 0.947 50.376 1.139 ;
     RECT  28.368 1.139 49.416 1.427 ;
     RECT  0.72 1.091 26.28 1.715 ;
     RECT  0.72 1.715 26.184 8.531 ;
     RECT  0.72 8.531 11.4 9.155 ;
     RECT  28.368 1.427 49.32 9.155 ;
     RECT  0.912 9.155 11.304 11.507 ;
     RECT  5.424 11.507 11.304 11.555 ;
     RECT  0.912 11.507 4.392 12.083 ;
     RECT  5.52 11.555 11.304 12.563 ;
     RECT  28.368 9.155 47.304 12.563 ;
     RECT  0.912 12.083 3.72 13.139 ;
     RECT  1.104 13.139 3.72 13.187 ;
     RECT  5.52 12.563 10.824 13.715 ;
     RECT  5.52 13.715 9.864 13.763 ;
     RECT  5.568 13.763 9.864 14.147 ;
     RECT  6.576 14.147 9.864 14.867 ;
     RECT  5.568 14.147 5.592 14.915 ;
     RECT  6.864 14.867 9.864 15.443 ;
     RECT  12.48 8.531 26.184 15.443 ;
     RECT  17.52 15.443 26.184 15.491 ;
     RECT  17.568 15.491 26.184 15.539 ;
     RECT  12.48 15.443 16.008 16.019 ;
     RECT  39.12 12.563 47.304 16.019 ;
     RECT  39.12 16.019 47.256 16.115 ;
     RECT  6.864 15.443 9.576 16.261 ;
     RECT  6.816 16.261 9.576 16.549 ;
     RECT  6.816 16.549 10.296 16.595 ;
     RECT  13.2 16.019 16.008 16.595 ;
     RECT  17.568 15.539 24.312 16.595 ;
     RECT  39.12 16.115 47.208 16.595 ;
     RECT  17.76 16.595 24.312 17.123 ;
     RECT  39.12 16.595 47.112 17.123 ;
     RECT  18 17.123 24.312 17.171 ;
     RECT  1.2 13.187 3.72 17.219 ;
     RECT  6.816 16.595 8.112 17.317 ;
     RECT  2.208 17.219 3.72 17.411 ;
     RECT  18.192 17.171 24.312 17.699 ;
     RECT  1.2 17.219 1.224 18.275 ;
     RECT  18.192 17.699 18.912 18.323 ;
     RECT  2.304 17.411 3.72 18.851 ;
     RECT  13.2 16.595 15.816 18.851 ;
     RECT  2.4 18.851 3.624 19.427 ;
     RECT  13.2 18.851 15.432 20.003 ;
     RECT  13.2 20.003 15.384 20.579 ;
     RECT  13.2 20.579 14.376 20.627 ;
     RECT  15.36 20.579 15.384 21.683 ;
     RECT  9.168 16.595 10.296 22.787 ;
     RECT  25.296 15.539 26.184 22.787 ;
     RECT  39.12 17.123 45.912 23.123 ;
     RECT  28.368 12.563 38.088 23.987 ;
     RECT  34.224 23.987 38.088 24.035 ;
     RECT  48.336 9.155 49.32 24.227 ;
     RECT  19.92 17.699 24.312 24.563 ;
     RECT  32.976 23.987 33 24.563 ;
     RECT  34.224 24.035 37.752 24.563 ;
     RECT  34.224 24.563 35.112 24.611 ;
     RECT  48.336 24.227 49.224 24.803 ;
     RECT  20.112 24.563 24.312 25.139 ;
     RECT  9.456 22.787 10.296 25.669 ;
     RECT  36.576 24.563 36.6 25.715 ;
     RECT  37.728 24.563 37.752 25.715 ;
     RECT  6.24 17.317 8.112 26.197 ;
     RECT  20.256 25.139 24.312 26.243 ;
     RECT  15.888 25.861 15.912 26.725 ;
     RECT  25.296 22.787 25.32 26.819 ;
     RECT  28.368 23.987 30.648 27.203 ;
     RECT  13.2 20.627 13.512 27.301 ;
     RECT  20.256 26.243 22.728 27.395 ;
     RECT  39.12 23.123 44.616 27.683 ;
     RECT  20.256 27.395 22.152 27.971 ;
     RECT  12.624 27.301 13.512 28.165 ;
     RECT  39.12 27.683 44.52 28.259 ;
     RECT  9.456 25.669 11.112 28.453 ;
     RECT  18.6 18.323 18.912 28.501 ;
     RECT  20.256 27.971 21.72 28.501 ;
     RECT  39.12 28.259 40.68 28.835 ;
     RECT  41.808 28.259 44.52 28.979 ;
     RECT  23.904 26.243 24.312 29.029 ;
     RECT  26.496 28.453 26.52 29.029 ;
     RECT  0.144 28.789 0.168 29.075 ;
     RECT  2.4 19.427 2.712 29.077 ;
     RECT  3.744 27.301 3.768 29.077 ;
     RECT  25.584 29.029 26.52 29.077 ;
     RECT  28.368 27.203 29.712 29.123 ;
     RECT  48.336 24.803 49.128 29.363 ;
     RECT  39.12 28.835 40.632 29.507 ;
     RECT  39.216 29.507 40.632 29.939 ;
     RECT  23.904 29.029 24.552 29.941 ;
     RECT  25.584 29.077 26.664 29.941 ;
     RECT  17.376 24.997 17.4 30.037 ;
     RECT  41.808 28.979 44.328 30.083 ;
     RECT  28.704 29.123 29.712 30.085 ;
     RECT  30.816 27.301 30.84 30.085 ;
     RECT  41.808 30.083 44.232 30.131 ;
     RECT  40.2 29.939 40.632 30.179 ;
     RECT  28.704 30.085 30.84 30.181 ;
     RECT  23.904 29.941 26.664 30.229 ;
     RECT  27.648 30.181 30.84 30.229 ;
     RECT  2.4 29.077 3.768 30.323 ;
     RECT  9.456 28.453 11.496 30.325 ;
     RECT  15.552 26.725 15.912 30.565 ;
     RECT  16.944 30.037 17.4 30.565 ;
     RECT  5.328 26.197 8.112 30.757 ;
     RECT  9.456 30.325 11.64 30.757 ;
     RECT  44.208 30.131 44.232 30.851 ;
     RECT  22.752 28.933 22.776 31.285 ;
     RECT  23.904 30.229 30.84 31.285 ;
     RECT  45.6 23.123 45.912 31.285 ;
     RECT  41.808 30.131 42.888 31.523 ;
     RECT  0.144 31.717 0.168 31.907 ;
     RECT  5.328 30.757 11.64 31.907 ;
     RECT  45.504 31.285 45.912 32.245 ;
     RECT  45.408 32.245 45.912 32.437 ;
     RECT  15.552 30.565 17.4 32.725 ;
     RECT  18.6 28.501 21.72 32.725 ;
     RECT  42.192 31.523 42.888 32.771 ;
     RECT  42.192 32.771 42.216 32.819 ;
     RECT  2.4 30.323 2.712 32.869 ;
     RECT  3.744 30.323 3.768 32.869 ;
     RECT  48.432 29.363 49.128 33.395 ;
     RECT  45.408 32.437 46.008 33.493 ;
     RECT  5.616 31.907 11.64 33.827 ;
     RECT  12.624 28.165 14.28 33.829 ;
     RECT  43.92 31.525 43.944 33.925 ;
     RECT  45.408 33.493 46.056 33.925 ;
     RECT  5.616 33.827 11.112 34.115 ;
     RECT  6.144 34.115 11.112 34.835 ;
     RECT  43.92 33.925 46.056 34.883 ;
     RECT  12.624 33.829 14.472 34.981 ;
     RECT  15.552 32.725 21.72 34.981 ;
     RECT  6.144 34.835 9.864 35.075 ;
     RECT  12.624 34.981 21.72 35.363 ;
     RECT  0.144 34.453 0.168 35.747 ;
     RECT  5.616 35.077 5.64 35.939 ;
     RECT  2.4 32.869 3.768 35.989 ;
     RECT  45.6 34.883 46.056 35.989 ;
     RECT  2.4 35.989 3.96 36.131 ;
     RECT  41.856 34.117 41.88 36.323 ;
     RECT  2.4 36.131 3.816 36.419 ;
     RECT  45.6 35.989 46.104 36.419 ;
     RECT  15.168 35.363 21.72 36.565 ;
     RECT  45.6 36.419 46.056 36.611 ;
     RECT  22.752 31.285 30.84 36.901 ;
     RECT  31.92 36.421 31.944 36.901 ;
     RECT  6.624 35.075 9.864 36.997 ;
     RECT  3.744 36.419 3.816 37.141 ;
     RECT  49.104 33.395 49.128 37.331 ;
     RECT  3.744 37.141 4.584 37.427 ;
     RECT  45.6 36.611 46.008 37.667 ;
     RECT  15.12 36.565 21.72 38.149 ;
     RECT  22.752 36.901 31.944 38.149 ;
     RECT  0.192 37.909 0.216 38.195 ;
     RECT  6.384 36.997 9.864 38.389 ;
     RECT  12.624 35.363 13.512 38.725 ;
     RECT  15.12 38.149 31.944 38.819 ;
     RECT  33.12 35.701 33.144 38.917 ;
     RECT  6.384 38.389 10.008 39.013 ;
     RECT  5.808 39.013 10.008 39.061 ;
     RECT  11.088 34.835 11.112 39.061 ;
     RECT  0.144 39.013 0.168 39.299 ;
     RECT  2.4 36.419 2.712 39.301 ;
     RECT  3.744 37.427 3.816 39.301 ;
     RECT  45.6 37.667 45.912 39.589 ;
     RECT  12.624 38.725 13.944 40.117 ;
     RECT  5.808 39.061 11.112 40.597 ;
     RECT  5.664 40.597 11.112 40.789 ;
     RECT  15.12 38.819 21.72 40.885 ;
     RECT  22.752 38.819 31.944 40.885 ;
     RECT  12.288 40.117 13.944 40.981 ;
     RECT  15.12 40.885 31.944 40.981 ;
     RECT  12.288 40.981 31.944 41.027 ;
     RECT  45.504 39.589 45.912 41.027 ;
     RECT  0.144 41.125 0.168 41.315 ;
     RECT  2.4 39.301 3.816 41.365 ;
     RECT  2.4 41.365 3.864 41.461 ;
     RECT  5.04 40.789 11.112 41.461 ;
     RECT  2.4 41.461 11.112 41.989 ;
     RECT  22.752 41.027 31.944 42.037 ;
     RECT  33.072 38.917 33.144 42.037 ;
     RECT  2.4 41.989 11.16 42.227 ;
     RECT  3.792 42.227 11.16 43.861 ;
     RECT  12.288 41.027 21.72 43.861 ;
     RECT  22.752 42.037 33.144 43.861 ;
     RECT  2.4 42.227 2.712 44.341 ;
     RECT  3.792 43.861 11.256 44.341 ;
     RECT  0.144 43.621 0.168 44.387 ;
     RECT  1.152 44.629 1.176 44.677 ;
     RECT  1.152 44.677 1.272 44.963 ;
     RECT  2.4 44.341 11.256 45.155 ;
     RECT  2.4 45.155 2.808 45.203 ;
     RECT  3.792 45.155 11.16 45.635 ;
     RECT  43.92 34.883 43.944 46.259 ;
     RECT  3.936 45.635 11.16 46.645 ;
     RECT  3.744 46.645 11.16 47.363 ;
     RECT  4.272 47.363 11.16 47.893 ;
     RECT  12.288 43.861 33.144 47.893 ;
     RECT  0.144 48.997 1.128 49.187 ;
     RECT  4.272 47.893 33.144 51.109 ;
     RECT  4.272 51.109 33.192 51.299 ;
     RECT  4.272 51.299 33.144 51.301 ;
     RECT  2.4 45.203 2.712 52.021 ;
     RECT  3.696 51.301 33.144 52.021 ;
     RECT  0.144 52.021 0.168 52.211 ;
     RECT  2.4 52.021 33.144 52.259 ;
     RECT  3.696 52.259 33.144 52.739 ;
     RECT  3.936 52.739 33.144 53.411 ;
     RECT  4.272 53.411 33.144 54.613 ;
     RECT  3.936 54.613 33.144 54.755 ;
     RECT  4.272 54.755 33.144 55.813 ;
     RECT  34.8 24.611 35.112 56.053 ;
     RECT  34.8 56.053 35.544 56.339 ;
     RECT  3.696 55.813 33.144 58.163 ;
     RECT  2.4 52.259 2.712 58.213 ;
     RECT  3.696 58.163 31.944 58.213 ;
     RECT  2.4 58.213 31.944 58.355 ;
     RECT  37.968 47.557 37.992 59.221 ;
     RECT  3.744 58.355 31.944 59.987 ;
     RECT  2.4 58.355 2.712 62.101 ;
     RECT  4.176 59.987 31.944 62.101 ;
     RECT  0.144 61.669 0.168 63.059 ;
     RECT  39.12 55.765 39.144 63.061 ;
     RECT  40.2 30.179 40.512 63.061 ;
     RECT  2.4 62.101 31.944 64.021 ;
     RECT  39.12 63.061 40.512 64.309 ;
     RECT  0.24 64.117 0.264 64.403 ;
     RECT  37.872 59.221 37.992 64.597 ;
     RECT  2.304 64.021 31.944 64.643 ;
     RECT  2.304 64.643 24.312 65.267 ;
     RECT  2.304 65.267 2.904 66.229 ;
     RECT  25.344 64.643 31.944 66.563 ;
     RECT  1.92 66.229 2.904 66.803 ;
     RECT  37.68 64.597 37.992 66.805 ;
     RECT  39.024 64.309 40.512 66.805 ;
     RECT  4.176 65.267 24.312 66.997 ;
     RECT  2.304 66.803 2.904 67.813 ;
     RECT  4.08 66.997 24.312 67.813 ;
     RECT  2.304 67.813 24.312 67.907 ;
     RECT  2.304 67.907 21.912 68.003 ;
     RECT  25.344 66.563 27.096 68.003 ;
     RECT  4.176 68.003 21.912 68.387 ;
     RECT  2.304 68.003 2.904 69.011 ;
     RECT  2.304 69.011 2.712 69.203 ;
     RECT  4.176 68.387 17.448 70.307 ;
     RECT  0.144 70.309 0.168 70.595 ;
     RECT  4.176 70.307 17.4 70.739 ;
     RECT  28.176 66.563 31.944 70.883 ;
     RECT  33.072 58.163 33.144 70.979 ;
     RECT  45.6 41.027 45.912 70.981 ;
     RECT  45.6 70.981 46.056 71.509 ;
     RECT  47.28 71.221 47.304 71.509 ;
     RECT  30.864 70.883 31.944 71.651 ;
     RECT  30.864 71.651 31.704 72.227 ;
     RECT  2.4 69.203 2.712 72.325 ;
     RECT  48.432 72.037 48.456 72.325 ;
     RECT  4.176 70.739 15.912 72.419 ;
     RECT  17.328 70.739 17.4 72.419 ;
     RECT  15.12 72.419 15.576 72.515 ;
     RECT  2.304 72.325 2.712 73.045 ;
     RECT  31.68 72.227 31.704 73.283 ;
     RECT  25.344 68.003 26.568 73.379 ;
     RECT  4.176 72.419 13.944 73.477 ;
     RECT  15.12 72.515 15.144 73.477 ;
     RECT  45.6 71.509 47.304 73.477 ;
     RECT  48.336 72.325 48.456 73.477 ;
     RECT  2.304 73.045 2.808 73.909 ;
     RECT  4.176 73.477 15.144 73.909 ;
     RECT  18.6 68.387 21.912 74.099 ;
     RECT  25.344 73.379 26.472 74.099 ;
     RECT  2.304 73.909 15.144 74.963 ;
     RECT  2.4 74.963 15.144 75.059 ;
     RECT  14.976 75.059 15.144 75.731 ;
     RECT  14.976 75.731 15 75.875 ;
     RECT  28.176 70.883 29.712 76.067 ;
     RECT  22.944 67.907 24.312 76.403 ;
     RECT  25.344 74.099 25.368 76.403 ;
     RECT  26.448 74.099 26.472 76.403 ;
     RECT  2.4 75.059 13.944 77.075 ;
     RECT  2.4 77.075 13.512 77.315 ;
     RECT  0.144 77.317 0.168 77.507 ;
     RECT  33.072 70.979 33.096 77.843 ;
     RECT  27.12 77.701 27.144 77.989 ;
     RECT  10.512 77.315 13.512 78.083 ;
     RECT  27.12 77.989 27.528 78.517 ;
     RECT  27.12 78.517 27.72 78.613 ;
     RECT  29.04 76.067 29.712 78.613 ;
     RECT  18.6 74.099 19.08 78.707 ;
     RECT  20.256 74.099 21.912 78.947 ;
     RECT  17.328 72.419 17.352 79.283 ;
     RECT  20.784 78.947 21.912 79.283 ;
     RECT  21.888 79.283 21.912 79.859 ;
     RECT  23.232 76.403 24.312 79.859 ;
     RECT  10.512 78.083 10.536 80.147 ;
     RECT  24 79.859 24.312 80.245 ;
     RECT  27.12 78.613 29.712 80.293 ;
     RECT  2.4 77.315 9.384 80.579 ;
     RECT  24 80.245 24.408 80.917 ;
     RECT  20.784 79.283 20.808 81.203 ;
     RECT  27.12 80.293 30.12 81.781 ;
     RECT  18.6 78.707 18.912 81.877 ;
     RECT  31.824 81.493 32.712 82.021 ;
     RECT  23.616 80.917 24.408 82.597 ;
     RECT  25.392 80.917 25.416 82.597 ;
     RECT  23.616 82.597 25.416 82.645 ;
     RECT  27.12 81.781 30.6 83.173 ;
     RECT  31.728 82.021 32.712 83.173 ;
     RECT  18.48 81.877 18.912 83.221 ;
     RECT  11.616 78.083 13.512 83.651 ;
     RECT  18 83.221 18.912 83.653 ;
     RECT  20.784 83.221 20.808 83.749 ;
     RECT  18 83.653 19.272 84.133 ;
     RECT  12.864 83.651 13.512 84.181 ;
     RECT  12.864 84.181 14.472 84.277 ;
     RECT  17.904 84.133 19.272 84.325 ;
     RECT  23.616 82.645 25.896 84.709 ;
     RECT  27.12 83.173 32.712 84.709 ;
     RECT  17.616 84.325 19.272 84.757 ;
     RECT  20.784 83.749 20.904 84.757 ;
     RECT  23.616 84.709 32.712 84.901 ;
     RECT  2.4 80.579 8.472 84.995 ;
     RECT  7.152 84.995 8.376 85.091 ;
     RECT  7.152 85.091 8.112 85.523 ;
     RECT  23.184 84.901 32.712 85.909 ;
     RECT  17.616 84.757 20.904 86.005 ;
     RECT  17.328 86.005 21 86.341 ;
     RECT  7.8 85.523 8.112 86.581 ;
     RECT  16.56 86.341 21 86.581 ;
     RECT  2.4 84.995 5.592 86.675 ;
     RECT  12.864 84.277 14.76 87.157 ;
     RECT  2.4 86.675 5.304 87.203 ;
     RECT  7.8 86.581 8.424 87.733 ;
     RECT  9.744 85.477 9.768 87.733 ;
     RECT  16.56 86.581 21.384 87.733 ;
     RECT  7.8 87.733 9.768 88.789 ;
     RECT  16.464 87.733 21.384 88.885 ;
     RECT  7.8 88.789 10.344 89.461 ;
     RECT  12.864 87.157 14.952 89.461 ;
     RECT  16.464 88.885 21.576 89.461 ;
     RECT  2.4 87.203 5.256 89.509 ;
     RECT  2.4 89.509 5.688 90.037 ;
     RECT  7.536 89.461 10.344 90.037 ;
     RECT  11.616 83.651 11.736 90.037 ;
     RECT  2.4 90.037 6.216 90.323 ;
     RECT  4.176 90.323 6.216 90.565 ;
     RECT  7.536 90.037 11.736 90.565 ;
     RECT  12.864 89.461 21.576 91.141 ;
     RECT  22.608 85.909 32.712 91.141 ;
     RECT  4.176 90.565 11.736 91.333 ;
     RECT  12.864 91.141 32.712 91.333 ;
     RECT  2.4 90.323 2.808 91.859 ;
     RECT  4.176 91.333 32.712 93.445 ;
     RECT  2.4 91.859 2.712 94.501 ;
     RECT  2.256 94.501 2.712 95.173 ;
     RECT  1.68 95.173 2.712 95.653 ;
     RECT  3.696 93.445 32.712 95.653 ;
     RECT  1.68 95.653 32.712 95.989 ;
     RECT  45.6 73.477 48.456 98.053 ;
     RECT  37.68 66.805 40.512 99.107 ;
     RECT  41.904 98.629 41.928 99.157 ;
     RECT  34.8 56.339 35.112 99.301 ;
     RECT  34.8 99.301 35.688 99.733 ;
     RECT  41.904 99.157 42.312 99.733 ;
     RECT  41.904 99.733 42.888 99.781 ;
     RECT  41.904 99.781 43.08 100.117 ;
     RECT  34.032 99.733 35.688 100.309 ;
     RECT  41.904 100.117 43.848 100.309 ;
     RECT  33.936 100.309 36.36 100.789 ;
     RECT  49.584 100.261 49.608 100.837 ;
     RECT  1.392 95.989 32.712 100.885 ;
     RECT  33.744 100.789 36.36 100.885 ;
     RECT  39.024 99.107 40.512 100.885 ;
     RECT  41.52 100.309 43.848 100.885 ;
     RECT  44.88 98.053 48.456 100.885 ;
     RECT  49.584 100.837 49.704 100.885 ;
     RECT  1.392 100.885 36.36 101.413 ;
     RECT  39.024 100.885 49.704 101.413 ;
     RECT  50.736 98.629 51.912 101.413 ;
     RECT  1.392 101.413 36.456 101.461 ;
     RECT  37.68 99.107 37.992 101.461 ;
     RECT  1.392 101.461 37.992 102.037 ;
     RECT  39.024 101.413 51.912 102.037 ;
     RECT  1.392 102.037 51.912 103.632 ;
  END
END qfd_cst_n
END LIBRARY
